VERSION 5.8 ;
BUSBITCHARS "[]" ;
DIVIDERCHAR "/" ;
UNITS
    DATABASE MICRONS 1000 ;
END UNITS

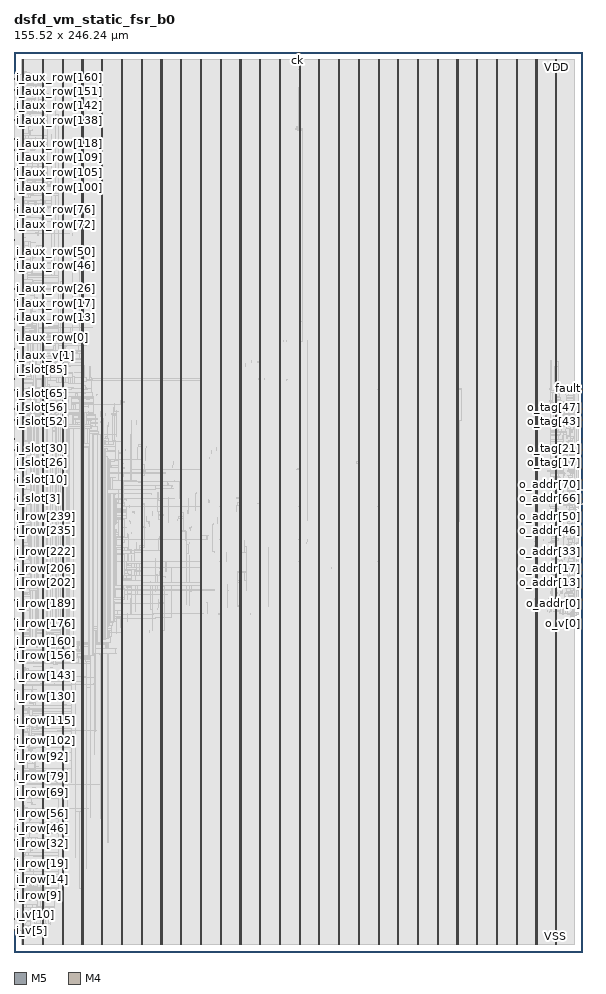
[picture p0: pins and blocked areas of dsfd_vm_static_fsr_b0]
MACRO dsfd_vm_static_fsr_b0
  FOREIGN dsfd_vm_static_fsr_b0 0 0 ;
  CLASS BLOCK ;
  SIZE 155.52 BY 246.24 ;
  PIN ck
    DIRECTION INPUT ;
    USE SIGNAL ;
    PORT
      LAYER M5 ;
        RECT  77.52 246.156 77.544 246.24 ;
    END
  END ck
  PIN fault
    DIRECTION OUTPUT ;
    USE SIGNAL ;
    PORT
      LAYER M4 ;
        RECT  155.436 154.176 155.52 154.2 ;
    END
  END fault
  PIN i_aux_row[0]
    DIRECTION INPUT ;
    USE SIGNAL ;
    PORT
      LAYER M4 ;
        RECT  0 168 0.084 168.024 ;
    END
  END i_aux_row[0]
  PIN i_aux_row[100]
    DIRECTION INPUT ;
    USE SIGNAL ;
    PORT
      LAYER M4 ;
        RECT  0 211.2 0.084 211.224 ;
    END
  END i_aux_row[100]
  PIN i_aux_row[101]
    DIRECTION INPUT ;
    USE SIGNAL ;
    PORT
      LAYER M4 ;
        RECT  0 211.632 0.084 211.656 ;
    END
  END i_aux_row[101]
  PIN i_aux_row[102]
    DIRECTION INPUT ;
    USE SIGNAL ;
    PORT
      LAYER M4 ;
        RECT  0 212.064 0.084 212.088 ;
    END
  END i_aux_row[102]
  PIN i_aux_row[103]
    DIRECTION INPUT ;
    USE SIGNAL ;
    PORT
      LAYER M4 ;
        RECT  0 212.496 0.084 212.52 ;
    END
  END i_aux_row[103]
  PIN i_aux_row[104]
    DIRECTION INPUT ;
    USE SIGNAL ;
    PORT
      LAYER M4 ;
        RECT  0 212.928 0.084 212.952 ;
    END
  END i_aux_row[104]
  PIN i_aux_row[105]
    DIRECTION INPUT ;
    USE SIGNAL ;
    PORT
      LAYER M4 ;
        RECT  0 213.36 0.084 213.384 ;
    END
  END i_aux_row[105]
  PIN i_aux_row[106]
    DIRECTION INPUT ;
    USE SIGNAL ;
    PORT
      LAYER M4 ;
        RECT  0 213.792 0.084 213.816 ;
    END
  END i_aux_row[106]
  PIN i_aux_row[107]
    DIRECTION INPUT ;
    USE SIGNAL ;
    PORT
      LAYER M4 ;
        RECT  0 214.224 0.084 214.248 ;
    END
  END i_aux_row[107]
  PIN i_aux_row[108]
    DIRECTION INPUT ;
    USE SIGNAL ;
    PORT
      LAYER M4 ;
        RECT  0 214.656 0.084 214.68 ;
    END
  END i_aux_row[108]
  PIN i_aux_row[109]
    DIRECTION INPUT ;
    USE SIGNAL ;
    PORT
      LAYER M4 ;
        RECT  0 215.088 0.084 215.112 ;
    END
  END i_aux_row[109]
  PIN i_aux_row[10]
    DIRECTION INPUT ;
    USE SIGNAL ;
    PORT
      LAYER M4 ;
        RECT  0 172.32 0.084 172.344 ;
    END
  END i_aux_row[10]
  PIN i_aux_row[110]
    DIRECTION INPUT ;
    USE SIGNAL ;
    PORT
      LAYER M4 ;
        RECT  0 215.52 0.084 215.544 ;
    END
  END i_aux_row[110]
  PIN i_aux_row[111]
    DIRECTION INPUT ;
    USE SIGNAL ;
    PORT
      LAYER M4 ;
        RECT  0 215.952 0.084 215.976 ;
    END
  END i_aux_row[111]
  PIN i_aux_row[112]
    DIRECTION INPUT ;
    USE SIGNAL ;
    PORT
      LAYER M4 ;
        RECT  0 216.384 0.084 216.408 ;
    END
  END i_aux_row[112]
  PIN i_aux_row[113]
    DIRECTION INPUT ;
    USE SIGNAL ;
    PORT
      LAYER M4 ;
        RECT  0 216.816 0.084 216.84 ;
    END
  END i_aux_row[113]
  PIN i_aux_row[114]
    DIRECTION INPUT ;
    USE SIGNAL ;
    PORT
      LAYER M4 ;
        RECT  0 217.248 0.084 217.272 ;
    END
  END i_aux_row[114]
  PIN i_aux_row[115]
    DIRECTION INPUT ;
    USE SIGNAL ;
    PORT
      LAYER M4 ;
        RECT  0 217.68 0.084 217.704 ;
    END
  END i_aux_row[115]
  PIN i_aux_row[116]
    DIRECTION INPUT ;
    USE SIGNAL ;
    PORT
      LAYER M4 ;
        RECT  0 218.112 0.084 218.136 ;
    END
  END i_aux_row[116]
  PIN i_aux_row[117]
    DIRECTION INPUT ;
    USE SIGNAL ;
    PORT
      LAYER M4 ;
        RECT  0 218.544 0.084 218.568 ;
    END
  END i_aux_row[117]
  PIN i_aux_row[118]
    DIRECTION INPUT ;
    USE SIGNAL ;
    PORT
      LAYER M4 ;
        RECT  0 218.976 0.084 219 ;
    END
  END i_aux_row[118]
  PIN i_aux_row[119]
    DIRECTION INPUT ;
    USE SIGNAL ;
    PORT
      LAYER M4 ;
        RECT  0 219.408 0.084 219.432 ;
    END
  END i_aux_row[119]
  PIN i_aux_row[11]
    DIRECTION INPUT ;
    USE SIGNAL ;
    PORT
      LAYER M4 ;
        RECT  0 172.752 0.084 172.776 ;
    END
  END i_aux_row[11]
  PIN i_aux_row[120]
    DIRECTION INPUT ;
    USE SIGNAL ;
    PORT
      LAYER M4 ;
        RECT  0 219.84 0.084 219.864 ;
    END
  END i_aux_row[120]
  PIN i_aux_row[121]
    DIRECTION INPUT ;
    USE SIGNAL ;
    PORT
      LAYER M4 ;
        RECT  0 220.272 0.084 220.296 ;
    END
  END i_aux_row[121]
  PIN i_aux_row[122]
    DIRECTION INPUT ;
    USE SIGNAL ;
    PORT
      LAYER M4 ;
        RECT  0 220.704 0.084 220.728 ;
    END
  END i_aux_row[122]
  PIN i_aux_row[123]
    DIRECTION INPUT ;
    USE SIGNAL ;
    PORT
      LAYER M4 ;
        RECT  0 221.136 0.084 221.16 ;
    END
  END i_aux_row[123]
  PIN i_aux_row[124]
    DIRECTION INPUT ;
    USE SIGNAL ;
    PORT
      LAYER M4 ;
        RECT  0 221.568 0.084 221.592 ;
    END
  END i_aux_row[124]
  PIN i_aux_row[125]
    DIRECTION INPUT ;
    USE SIGNAL ;
    PORT
      LAYER M4 ;
        RECT  0 222 0.084 222.024 ;
    END
  END i_aux_row[125]
  PIN i_aux_row[126]
    DIRECTION INPUT ;
    USE SIGNAL ;
    PORT
      LAYER M4 ;
        RECT  0 222.432 0.084 222.456 ;
    END
  END i_aux_row[126]
  PIN i_aux_row[127]
    DIRECTION INPUT ;
    USE SIGNAL ;
    PORT
      LAYER M4 ;
        RECT  0 222.864 0.084 222.888 ;
    END
  END i_aux_row[127]
  PIN i_aux_row[128]
    DIRECTION INPUT ;
    USE SIGNAL ;
    PORT
      LAYER M4 ;
        RECT  0 223.296 0.084 223.32 ;
    END
  END i_aux_row[128]
  PIN i_aux_row[129]
    DIRECTION INPUT ;
    USE SIGNAL ;
    PORT
      LAYER M4 ;
        RECT  0 223.728 0.084 223.752 ;
    END
  END i_aux_row[129]
  PIN i_aux_row[12]
    DIRECTION INPUT ;
    USE SIGNAL ;
    PORT
      LAYER M4 ;
        RECT  0 173.184 0.084 173.208 ;
    END
  END i_aux_row[12]
  PIN i_aux_row[130]
    DIRECTION INPUT ;
    USE SIGNAL ;
    PORT
      LAYER M4 ;
        RECT  0 224.16 0.084 224.184 ;
    END
  END i_aux_row[130]
  PIN i_aux_row[131]
    DIRECTION INPUT ;
    USE SIGNAL ;
    PORT
      LAYER M4 ;
        RECT  0 224.592 0.084 224.616 ;
    END
  END i_aux_row[131]
  PIN i_aux_row[132]
    DIRECTION INPUT ;
    USE SIGNAL ;
    PORT
      LAYER M4 ;
        RECT  0 225.024 0.084 225.048 ;
    END
  END i_aux_row[132]
  PIN i_aux_row[133]
    DIRECTION INPUT ;
    USE SIGNAL ;
    PORT
      LAYER M4 ;
        RECT  0 225.456 0.084 225.48 ;
    END
  END i_aux_row[133]
  PIN i_aux_row[134]
    DIRECTION INPUT ;
    USE SIGNAL ;
    PORT
      LAYER M4 ;
        RECT  0 225.888 0.084 225.912 ;
    END
  END i_aux_row[134]
  PIN i_aux_row[135]
    DIRECTION INPUT ;
    USE SIGNAL ;
    PORT
      LAYER M4 ;
        RECT  0 226.32 0.084 226.344 ;
    END
  END i_aux_row[135]
  PIN i_aux_row[136]
    DIRECTION INPUT ;
    USE SIGNAL ;
    PORT
      LAYER M4 ;
        RECT  0 226.752 0.084 226.776 ;
    END
  END i_aux_row[136]
  PIN i_aux_row[137]
    DIRECTION INPUT ;
    USE SIGNAL ;
    PORT
      LAYER M4 ;
        RECT  0 227.184 0.084 227.208 ;
    END
  END i_aux_row[137]
  PIN i_aux_row[138]
    DIRECTION INPUT ;
    USE SIGNAL ;
    PORT
      LAYER M4 ;
        RECT  0 227.616 0.084 227.64 ;
    END
  END i_aux_row[138]
  PIN i_aux_row[139]
    DIRECTION INPUT ;
    USE SIGNAL ;
    PORT
      LAYER M4 ;
        RECT  0 228.048 0.084 228.072 ;
    END
  END i_aux_row[139]
  PIN i_aux_row[13]
    DIRECTION INPUT ;
    USE SIGNAL ;
    PORT
      LAYER M4 ;
        RECT  0 173.616 0.084 173.64 ;
    END
  END i_aux_row[13]
  PIN i_aux_row[140]
    DIRECTION INPUT ;
    USE SIGNAL ;
    PORT
      LAYER M4 ;
        RECT  0 228.48 0.084 228.504 ;
    END
  END i_aux_row[140]
  PIN i_aux_row[141]
    DIRECTION INPUT ;
    USE SIGNAL ;
    PORT
      LAYER M4 ;
        RECT  0 228.912 0.084 228.936 ;
    END
  END i_aux_row[141]
  PIN i_aux_row[142]
    DIRECTION INPUT ;
    USE SIGNAL ;
    PORT
      LAYER M4 ;
        RECT  0 229.344 0.084 229.368 ;
    END
  END i_aux_row[142]
  PIN i_aux_row[143]
    DIRECTION INPUT ;
    USE SIGNAL ;
    PORT
      LAYER M4 ;
        RECT  0 229.776 0.084 229.8 ;
    END
  END i_aux_row[143]
  PIN i_aux_row[144]
    DIRECTION INPUT ;
    USE SIGNAL ;
    PORT
      LAYER M4 ;
        RECT  0 230.208 0.084 230.232 ;
    END
  END i_aux_row[144]
  PIN i_aux_row[145]
    DIRECTION INPUT ;
    USE SIGNAL ;
    PORT
      LAYER M4 ;
        RECT  0 230.64 0.084 230.664 ;
    END
  END i_aux_row[145]
  PIN i_aux_row[146]
    DIRECTION INPUT ;
    USE SIGNAL ;
    PORT
      LAYER M4 ;
        RECT  0 231.072 0.084 231.096 ;
    END
  END i_aux_row[146]
  PIN i_aux_row[147]
    DIRECTION INPUT ;
    USE SIGNAL ;
    PORT
      LAYER M4 ;
        RECT  0 231.504 0.084 231.528 ;
    END
  END i_aux_row[147]
  PIN i_aux_row[148]
    DIRECTION INPUT ;
    USE SIGNAL ;
    PORT
      LAYER M4 ;
        RECT  0 231.936 0.084 231.96 ;
    END
  END i_aux_row[148]
  PIN i_aux_row[149]
    DIRECTION INPUT ;
    USE SIGNAL ;
    PORT
      LAYER M4 ;
        RECT  0 232.368 0.084 232.392 ;
    END
  END i_aux_row[149]
  PIN i_aux_row[14]
    DIRECTION INPUT ;
    USE SIGNAL ;
    PORT
      LAYER M4 ;
        RECT  0 174.048 0.084 174.072 ;
    END
  END i_aux_row[14]
  PIN i_aux_row[150]
    DIRECTION INPUT ;
    USE SIGNAL ;
    PORT
      LAYER M4 ;
        RECT  0 232.8 0.084 232.824 ;
    END
  END i_aux_row[150]
  PIN i_aux_row[151]
    DIRECTION INPUT ;
    USE SIGNAL ;
    PORT
      LAYER M4 ;
        RECT  0 233.232 0.084 233.256 ;
    END
  END i_aux_row[151]
  PIN i_aux_row[152]
    DIRECTION INPUT ;
    USE SIGNAL ;
    PORT
      LAYER M4 ;
        RECT  0 233.664 0.084 233.688 ;
    END
  END i_aux_row[152]
  PIN i_aux_row[153]
    DIRECTION INPUT ;
    USE SIGNAL ;
    PORT
      LAYER M4 ;
        RECT  0 234.096 0.084 234.12 ;
    END
  END i_aux_row[153]
  PIN i_aux_row[154]
    DIRECTION INPUT ;
    USE SIGNAL ;
    PORT
      LAYER M4 ;
        RECT  0 234.528 0.084 234.552 ;
    END
  END i_aux_row[154]
  PIN i_aux_row[155]
    DIRECTION INPUT ;
    USE SIGNAL ;
    PORT
      LAYER M4 ;
        RECT  0 234.96 0.084 234.984 ;
    END
  END i_aux_row[155]
  PIN i_aux_row[156]
    DIRECTION INPUT ;
    USE SIGNAL ;
    PORT
      LAYER M4 ;
        RECT  0 235.392 0.084 235.416 ;
    END
  END i_aux_row[156]
  PIN i_aux_row[157]
    DIRECTION INPUT ;
    USE SIGNAL ;
    PORT
      LAYER M4 ;
        RECT  0 235.824 0.084 235.848 ;
    END
  END i_aux_row[157]
  PIN i_aux_row[158]
    DIRECTION INPUT ;
    USE SIGNAL ;
    PORT
      LAYER M4 ;
        RECT  0 236.256 0.084 236.28 ;
    END
  END i_aux_row[158]
  PIN i_aux_row[159]
    DIRECTION INPUT ;
    USE SIGNAL ;
    PORT
      LAYER M4 ;
        RECT  0 236.688 0.084 236.712 ;
    END
  END i_aux_row[159]
  PIN i_aux_row[15]
    DIRECTION INPUT ;
    USE SIGNAL ;
    PORT
      LAYER M4 ;
        RECT  0 174.48 0.084 174.504 ;
    END
  END i_aux_row[15]
  PIN i_aux_row[160]
    DIRECTION INPUT ;
    USE SIGNAL ;
    PORT
      LAYER M4 ;
        RECT  0 237.12 0.084 237.144 ;
    END
  END i_aux_row[160]
  PIN i_aux_row[161]
    DIRECTION INPUT ;
    USE SIGNAL ;
    PORT
      LAYER M4 ;
        RECT  0 237.552 0.084 237.576 ;
    END
  END i_aux_row[161]
  PIN i_aux_row[162]
    DIRECTION INPUT ;
    USE SIGNAL ;
    PORT
      LAYER M4 ;
        RECT  0 237.984 0.084 238.008 ;
    END
  END i_aux_row[162]
  PIN i_aux_row[163]
    DIRECTION INPUT ;
    USE SIGNAL ;
    PORT
      LAYER M4 ;
        RECT  0 238.416 0.084 238.44 ;
    END
  END i_aux_row[163]
  PIN i_aux_row[164]
    DIRECTION INPUT ;
    USE SIGNAL ;
    PORT
      LAYER M4 ;
        RECT  0 238.848 0.084 238.872 ;
    END
  END i_aux_row[164]
  PIN i_aux_row[165]
    DIRECTION INPUT ;
    USE SIGNAL ;
    PORT
      LAYER M4 ;
        RECT  0 239.28 0.084 239.304 ;
    END
  END i_aux_row[165]
  PIN i_aux_row[166]
    DIRECTION INPUT ;
    USE SIGNAL ;
    PORT
      LAYER M4 ;
        RECT  0 239.712 0.084 239.736 ;
    END
  END i_aux_row[166]
  PIN i_aux_row[167]
    DIRECTION INPUT ;
    USE SIGNAL ;
    PORT
      LAYER M4 ;
        RECT  0 240.144 0.084 240.168 ;
    END
  END i_aux_row[167]
  PIN i_aux_row[16]
    DIRECTION INPUT ;
    USE SIGNAL ;
    PORT
      LAYER M4 ;
        RECT  0 174.912 0.084 174.936 ;
    END
  END i_aux_row[16]
  PIN i_aux_row[17]
    DIRECTION INPUT ;
    USE SIGNAL ;
    PORT
      LAYER M4 ;
        RECT  0 175.344 0.084 175.368 ;
    END
  END i_aux_row[17]
  PIN i_aux_row[18]
    DIRECTION INPUT ;
    USE SIGNAL ;
    PORT
      LAYER M4 ;
        RECT  0 175.776 0.084 175.8 ;
    END
  END i_aux_row[18]
  PIN i_aux_row[19]
    DIRECTION INPUT ;
    USE SIGNAL ;
    PORT
      LAYER M4 ;
        RECT  0 176.208 0.084 176.232 ;
    END
  END i_aux_row[19]
  PIN i_aux_row[1]
    DIRECTION INPUT ;
    USE SIGNAL ;
    PORT
      LAYER M4 ;
        RECT  0 168.432 0.084 168.456 ;
    END
  END i_aux_row[1]
  PIN i_aux_row[20]
    DIRECTION INPUT ;
    USE SIGNAL ;
    PORT
      LAYER M4 ;
        RECT  0 176.64 0.084 176.664 ;
    END
  END i_aux_row[20]
  PIN i_aux_row[21]
    DIRECTION INPUT ;
    USE SIGNAL ;
    PORT
      LAYER M4 ;
        RECT  0 177.072 0.084 177.096 ;
    END
  END i_aux_row[21]
  PIN i_aux_row[22]
    DIRECTION INPUT ;
    USE SIGNAL ;
    PORT
      LAYER M4 ;
        RECT  0 177.504 0.084 177.528 ;
    END
  END i_aux_row[22]
  PIN i_aux_row[23]
    DIRECTION INPUT ;
    USE SIGNAL ;
    PORT
      LAYER M4 ;
        RECT  0 177.936 0.084 177.96 ;
    END
  END i_aux_row[23]
  PIN i_aux_row[24]
    DIRECTION INPUT ;
    USE SIGNAL ;
    PORT
      LAYER M4 ;
        RECT  0 178.368 0.084 178.392 ;
    END
  END i_aux_row[24]
  PIN i_aux_row[25]
    DIRECTION INPUT ;
    USE SIGNAL ;
    PORT
      LAYER M4 ;
        RECT  0 178.8 0.084 178.824 ;
    END
  END i_aux_row[25]
  PIN i_aux_row[26]
    DIRECTION INPUT ;
    USE SIGNAL ;
    PORT
      LAYER M4 ;
        RECT  0 179.232 0.084 179.256 ;
    END
  END i_aux_row[26]
  PIN i_aux_row[27]
    DIRECTION INPUT ;
    USE SIGNAL ;
    PORT
      LAYER M4 ;
        RECT  0 179.664 0.084 179.688 ;
    END
  END i_aux_row[27]
  PIN i_aux_row[28]
    DIRECTION INPUT ;
    USE SIGNAL ;
    PORT
      LAYER M4 ;
        RECT  0 180.096 0.084 180.12 ;
    END
  END i_aux_row[28]
  PIN i_aux_row[29]
    DIRECTION INPUT ;
    USE SIGNAL ;
    PORT
      LAYER M4 ;
        RECT  0 180.528 0.084 180.552 ;
    END
  END i_aux_row[29]
  PIN i_aux_row[2]
    DIRECTION INPUT ;
    USE SIGNAL ;
    PORT
      LAYER M4 ;
        RECT  0 168.864 0.084 168.888 ;
    END
  END i_aux_row[2]
  PIN i_aux_row[30]
    DIRECTION INPUT ;
    USE SIGNAL ;
    PORT
      LAYER M4 ;
        RECT  0 180.96 0.084 180.984 ;
    END
  END i_aux_row[30]
  PIN i_aux_row[31]
    DIRECTION INPUT ;
    USE SIGNAL ;
    PORT
      LAYER M4 ;
        RECT  0 181.392 0.084 181.416 ;
    END
  END i_aux_row[31]
  PIN i_aux_row[32]
    DIRECTION INPUT ;
    USE SIGNAL ;
    PORT
      LAYER M4 ;
        RECT  0 181.824 0.084 181.848 ;
    END
  END i_aux_row[32]
  PIN i_aux_row[33]
    DIRECTION INPUT ;
    USE SIGNAL ;
    PORT
      LAYER M4 ;
        RECT  0 182.256 0.084 182.28 ;
    END
  END i_aux_row[33]
  PIN i_aux_row[34]
    DIRECTION INPUT ;
    USE SIGNAL ;
    PORT
      LAYER M4 ;
        RECT  0 182.688 0.084 182.712 ;
    END
  END i_aux_row[34]
  PIN i_aux_row[35]
    DIRECTION INPUT ;
    USE SIGNAL ;
    PORT
      LAYER M4 ;
        RECT  0 183.12 0.084 183.144 ;
    END
  END i_aux_row[35]
  PIN i_aux_row[36]
    DIRECTION INPUT ;
    USE SIGNAL ;
    PORT
      LAYER M4 ;
        RECT  0 183.552 0.084 183.576 ;
    END
  END i_aux_row[36]
  PIN i_aux_row[37]
    DIRECTION INPUT ;
    USE SIGNAL ;
    PORT
      LAYER M4 ;
        RECT  0 183.984 0.084 184.008 ;
    END
  END i_aux_row[37]
  PIN i_aux_row[38]
    DIRECTION INPUT ;
    USE SIGNAL ;
    PORT
      LAYER M4 ;
        RECT  0 184.416 0.084 184.44 ;
    END
  END i_aux_row[38]
  PIN i_aux_row[39]
    DIRECTION INPUT ;
    USE SIGNAL ;
    PORT
      LAYER M4 ;
        RECT  0 184.848 0.084 184.872 ;
    END
  END i_aux_row[39]
  PIN i_aux_row[3]
    DIRECTION INPUT ;
    USE SIGNAL ;
    PORT
      LAYER M4 ;
        RECT  0 169.296 0.084 169.32 ;
    END
  END i_aux_row[3]
  PIN i_aux_row[40]
    DIRECTION INPUT ;
    USE SIGNAL ;
    PORT
      LAYER M4 ;
        RECT  0 185.28 0.084 185.304 ;
    END
  END i_aux_row[40]
  PIN i_aux_row[41]
    DIRECTION INPUT ;
    USE SIGNAL ;
    PORT
      LAYER M4 ;
        RECT  0 185.712 0.084 185.736 ;
    END
  END i_aux_row[41]
  PIN i_aux_row[42]
    DIRECTION INPUT ;
    USE SIGNAL ;
    PORT
      LAYER M4 ;
        RECT  0 186.144 0.084 186.168 ;
    END
  END i_aux_row[42]
  PIN i_aux_row[43]
    DIRECTION INPUT ;
    USE SIGNAL ;
    PORT
      LAYER M4 ;
        RECT  0 186.576 0.084 186.6 ;
    END
  END i_aux_row[43]
  PIN i_aux_row[44]
    DIRECTION INPUT ;
    USE SIGNAL ;
    PORT
      LAYER M4 ;
        RECT  0 187.008 0.084 187.032 ;
    END
  END i_aux_row[44]
  PIN i_aux_row[45]
    DIRECTION INPUT ;
    USE SIGNAL ;
    PORT
      LAYER M4 ;
        RECT  0 187.44 0.084 187.464 ;
    END
  END i_aux_row[45]
  PIN i_aux_row[46]
    DIRECTION INPUT ;
    USE SIGNAL ;
    PORT
      LAYER M4 ;
        RECT  0 187.872 0.084 187.896 ;
    END
  END i_aux_row[46]
  PIN i_aux_row[47]
    DIRECTION INPUT ;
    USE SIGNAL ;
    PORT
      LAYER M4 ;
        RECT  0 188.304 0.084 188.328 ;
    END
  END i_aux_row[47]
  PIN i_aux_row[48]
    DIRECTION INPUT ;
    USE SIGNAL ;
    PORT
      LAYER M4 ;
        RECT  0 188.736 0.084 188.76 ;
    END
  END i_aux_row[48]
  PIN i_aux_row[49]
    DIRECTION INPUT ;
    USE SIGNAL ;
    PORT
      LAYER M4 ;
        RECT  0 189.168 0.084 189.192 ;
    END
  END i_aux_row[49]
  PIN i_aux_row[4]
    DIRECTION INPUT ;
    USE SIGNAL ;
    PORT
      LAYER M4 ;
        RECT  0 169.728 0.084 169.752 ;
    END
  END i_aux_row[4]
  PIN i_aux_row[50]
    DIRECTION INPUT ;
    USE SIGNAL ;
    PORT
      LAYER M4 ;
        RECT  0 189.6 0.084 189.624 ;
    END
  END i_aux_row[50]
  PIN i_aux_row[51]
    DIRECTION INPUT ;
    USE SIGNAL ;
    PORT
      LAYER M4 ;
        RECT  0 190.032 0.084 190.056 ;
    END
  END i_aux_row[51]
  PIN i_aux_row[52]
    DIRECTION INPUT ;
    USE SIGNAL ;
    PORT
      LAYER M4 ;
        RECT  0 190.464 0.084 190.488 ;
    END
  END i_aux_row[52]
  PIN i_aux_row[53]
    DIRECTION INPUT ;
    USE SIGNAL ;
    PORT
      LAYER M4 ;
        RECT  0 190.896 0.084 190.92 ;
    END
  END i_aux_row[53]
  PIN i_aux_row[54]
    DIRECTION INPUT ;
    USE SIGNAL ;
    PORT
      LAYER M4 ;
        RECT  0 191.328 0.084 191.352 ;
    END
  END i_aux_row[54]
  PIN i_aux_row[55]
    DIRECTION INPUT ;
    USE SIGNAL ;
    PORT
      LAYER M4 ;
        RECT  0 191.76 0.084 191.784 ;
    END
  END i_aux_row[55]
  PIN i_aux_row[56]
    DIRECTION INPUT ;
    USE SIGNAL ;
    PORT
      LAYER M4 ;
        RECT  0 192.192 0.084 192.216 ;
    END
  END i_aux_row[56]
  PIN i_aux_row[57]
    DIRECTION INPUT ;
    USE SIGNAL ;
    PORT
      LAYER M4 ;
        RECT  0 192.624 0.084 192.648 ;
    END
  END i_aux_row[57]
  PIN i_aux_row[58]
    DIRECTION INPUT ;
    USE SIGNAL ;
    PORT
      LAYER M4 ;
        RECT  0 193.056 0.084 193.08 ;
    END
  END i_aux_row[58]
  PIN i_aux_row[59]
    DIRECTION INPUT ;
    USE SIGNAL ;
    PORT
      LAYER M4 ;
        RECT  0 193.488 0.084 193.512 ;
    END
  END i_aux_row[59]
  PIN i_aux_row[5]
    DIRECTION INPUT ;
    USE SIGNAL ;
    PORT
      LAYER M4 ;
        RECT  0 170.16 0.084 170.184 ;
    END
  END i_aux_row[5]
  PIN i_aux_row[60]
    DIRECTION INPUT ;
    USE SIGNAL ;
    PORT
      LAYER M4 ;
        RECT  0 193.92 0.084 193.944 ;
    END
  END i_aux_row[60]
  PIN i_aux_row[61]
    DIRECTION INPUT ;
    USE SIGNAL ;
    PORT
      LAYER M4 ;
        RECT  0 194.352 0.084 194.376 ;
    END
  END i_aux_row[61]
  PIN i_aux_row[62]
    DIRECTION INPUT ;
    USE SIGNAL ;
    PORT
      LAYER M4 ;
        RECT  0 194.784 0.084 194.808 ;
    END
  END i_aux_row[62]
  PIN i_aux_row[63]
    DIRECTION INPUT ;
    USE SIGNAL ;
    PORT
      LAYER M4 ;
        RECT  0 195.216 0.084 195.24 ;
    END
  END i_aux_row[63]
  PIN i_aux_row[64]
    DIRECTION INPUT ;
    USE SIGNAL ;
    PORT
      LAYER M4 ;
        RECT  0 195.648 0.084 195.672 ;
    END
  END i_aux_row[64]
  PIN i_aux_row[65]
    DIRECTION INPUT ;
    USE SIGNAL ;
    PORT
      LAYER M4 ;
        RECT  0 196.08 0.084 196.104 ;
    END
  END i_aux_row[65]
  PIN i_aux_row[66]
    DIRECTION INPUT ;
    USE SIGNAL ;
    PORT
      LAYER M4 ;
        RECT  0 196.512 0.084 196.536 ;
    END
  END i_aux_row[66]
  PIN i_aux_row[67]
    DIRECTION INPUT ;
    USE SIGNAL ;
    PORT
      LAYER M4 ;
        RECT  0 196.944 0.084 196.968 ;
    END
  END i_aux_row[67]
  PIN i_aux_row[68]
    DIRECTION INPUT ;
    USE SIGNAL ;
    PORT
      LAYER M4 ;
        RECT  0 197.376 0.084 197.4 ;
    END
  END i_aux_row[68]
  PIN i_aux_row[69]
    DIRECTION INPUT ;
    USE SIGNAL ;
    PORT
      LAYER M4 ;
        RECT  0 197.808 0.084 197.832 ;
    END
  END i_aux_row[69]
  PIN i_aux_row[6]
    DIRECTION INPUT ;
    USE SIGNAL ;
    PORT
      LAYER M4 ;
        RECT  0 170.592 0.084 170.616 ;
    END
  END i_aux_row[6]
  PIN i_aux_row[70]
    DIRECTION INPUT ;
    USE SIGNAL ;
    PORT
      LAYER M4 ;
        RECT  0 198.24 0.084 198.264 ;
    END
  END i_aux_row[70]
  PIN i_aux_row[71]
    DIRECTION INPUT ;
    USE SIGNAL ;
    PORT
      LAYER M4 ;
        RECT  0 198.672 0.084 198.696 ;
    END
  END i_aux_row[71]
  PIN i_aux_row[72]
    DIRECTION INPUT ;
    USE SIGNAL ;
    PORT
      LAYER M4 ;
        RECT  0 199.104 0.084 199.128 ;
    END
  END i_aux_row[72]
  PIN i_aux_row[73]
    DIRECTION INPUT ;
    USE SIGNAL ;
    PORT
      LAYER M4 ;
        RECT  0 199.536 0.084 199.56 ;
    END
  END i_aux_row[73]
  PIN i_aux_row[74]
    DIRECTION INPUT ;
    USE SIGNAL ;
    PORT
      LAYER M4 ;
        RECT  0 199.968 0.084 199.992 ;
    END
  END i_aux_row[74]
  PIN i_aux_row[75]
    DIRECTION INPUT ;
    USE SIGNAL ;
    PORT
      LAYER M4 ;
        RECT  0 200.4 0.084 200.424 ;
    END
  END i_aux_row[75]
  PIN i_aux_row[76]
    DIRECTION INPUT ;
    USE SIGNAL ;
    PORT
      LAYER M4 ;
        RECT  0 200.832 0.084 200.856 ;
    END
  END i_aux_row[76]
  PIN i_aux_row[77]
    DIRECTION INPUT ;
    USE SIGNAL ;
    PORT
      LAYER M4 ;
        RECT  0 201.264 0.084 201.288 ;
    END
  END i_aux_row[77]
  PIN i_aux_row[78]
    DIRECTION INPUT ;
    USE SIGNAL ;
    PORT
      LAYER M4 ;
        RECT  0 201.696 0.084 201.72 ;
    END
  END i_aux_row[78]
  PIN i_aux_row[79]
    DIRECTION INPUT ;
    USE SIGNAL ;
    PORT
      LAYER M4 ;
        RECT  0 202.128 0.084 202.152 ;
    END
  END i_aux_row[79]
  PIN i_aux_row[7]
    DIRECTION INPUT ;
    USE SIGNAL ;
    PORT
      LAYER M4 ;
        RECT  0 171.024 0.084 171.048 ;
    END
  END i_aux_row[7]
  PIN i_aux_row[80]
    DIRECTION INPUT ;
    USE SIGNAL ;
    PORT
      LAYER M4 ;
        RECT  0 202.56 0.084 202.584 ;
    END
  END i_aux_row[80]
  PIN i_aux_row[81]
    DIRECTION INPUT ;
    USE SIGNAL ;
    PORT
      LAYER M4 ;
        RECT  0 202.992 0.084 203.016 ;
    END
  END i_aux_row[81]
  PIN i_aux_row[82]
    DIRECTION INPUT ;
    USE SIGNAL ;
    PORT
      LAYER M4 ;
        RECT  0 203.424 0.084 203.448 ;
    END
  END i_aux_row[82]
  PIN i_aux_row[83]
    DIRECTION INPUT ;
    USE SIGNAL ;
    PORT
      LAYER M4 ;
        RECT  0 203.856 0.084 203.88 ;
    END
  END i_aux_row[83]
  PIN i_aux_row[84]
    DIRECTION INPUT ;
    USE SIGNAL ;
    PORT
      LAYER M4 ;
        RECT  0 204.288 0.084 204.312 ;
    END
  END i_aux_row[84]
  PIN i_aux_row[85]
    DIRECTION INPUT ;
    USE SIGNAL ;
    PORT
      LAYER M4 ;
        RECT  0 204.72 0.084 204.744 ;
    END
  END i_aux_row[85]
  PIN i_aux_row[86]
    DIRECTION INPUT ;
    USE SIGNAL ;
    PORT
      LAYER M4 ;
        RECT  0 205.152 0.084 205.176 ;
    END
  END i_aux_row[86]
  PIN i_aux_row[87]
    DIRECTION INPUT ;
    USE SIGNAL ;
    PORT
      LAYER M4 ;
        RECT  0 205.584 0.084 205.608 ;
    END
  END i_aux_row[87]
  PIN i_aux_row[88]
    DIRECTION INPUT ;
    USE SIGNAL ;
    PORT
      LAYER M4 ;
        RECT  0 206.016 0.084 206.04 ;
    END
  END i_aux_row[88]
  PIN i_aux_row[89]
    DIRECTION INPUT ;
    USE SIGNAL ;
    PORT
      LAYER M4 ;
        RECT  0 206.448 0.084 206.472 ;
    END
  END i_aux_row[89]
  PIN i_aux_row[8]
    DIRECTION INPUT ;
    USE SIGNAL ;
    PORT
      LAYER M4 ;
        RECT  0 171.456 0.084 171.48 ;
    END
  END i_aux_row[8]
  PIN i_aux_row[90]
    DIRECTION INPUT ;
    USE SIGNAL ;
    PORT
      LAYER M4 ;
        RECT  0 206.88 0.084 206.904 ;
    END
  END i_aux_row[90]
  PIN i_aux_row[91]
    DIRECTION INPUT ;
    USE SIGNAL ;
    PORT
      LAYER M4 ;
        RECT  0 207.312 0.084 207.336 ;
    END
  END i_aux_row[91]
  PIN i_aux_row[92]
    DIRECTION INPUT ;
    USE SIGNAL ;
    PORT
      LAYER M4 ;
        RECT  0 207.744 0.084 207.768 ;
    END
  END i_aux_row[92]
  PIN i_aux_row[93]
    DIRECTION INPUT ;
    USE SIGNAL ;
    PORT
      LAYER M4 ;
        RECT  0 208.176 0.084 208.2 ;
    END
  END i_aux_row[93]
  PIN i_aux_row[94]
    DIRECTION INPUT ;
    USE SIGNAL ;
    PORT
      LAYER M4 ;
        RECT  0 208.608 0.084 208.632 ;
    END
  END i_aux_row[94]
  PIN i_aux_row[95]
    DIRECTION INPUT ;
    USE SIGNAL ;
    PORT
      LAYER M4 ;
        RECT  0 209.04 0.084 209.064 ;
    END
  END i_aux_row[95]
  PIN i_aux_row[96]
    DIRECTION INPUT ;
    USE SIGNAL ;
    PORT
      LAYER M4 ;
        RECT  0 209.472 0.084 209.496 ;
    END
  END i_aux_row[96]
  PIN i_aux_row[97]
    DIRECTION INPUT ;
    USE SIGNAL ;
    PORT
      LAYER M4 ;
        RECT  0 209.904 0.084 209.928 ;
    END
  END i_aux_row[97]
  PIN i_aux_row[98]
    DIRECTION INPUT ;
    USE SIGNAL ;
    PORT
      LAYER M4 ;
        RECT  0 210.336 0.084 210.36 ;
    END
  END i_aux_row[98]
  PIN i_aux_row[99]
    DIRECTION INPUT ;
    USE SIGNAL ;
    PORT
      LAYER M4 ;
        RECT  0 210.768 0.084 210.792 ;
    END
  END i_aux_row[99]
  PIN i_aux_row[9]
    DIRECTION INPUT ;
    USE SIGNAL ;
    PORT
      LAYER M4 ;
        RECT  0 171.888 0.084 171.912 ;
    END
  END i_aux_row[9]
  PIN i_aux_v[0]
    DIRECTION INPUT ;
    USE SIGNAL ;
    PORT
      LAYER M4 ;
        RECT  0 162.816 0.084 162.84 ;
    END
  END i_aux_v[0]
  PIN i_aux_v[10]
    DIRECTION INPUT ;
    USE SIGNAL ;
    PORT
      LAYER M4 ;
        RECT  0 167.136 0.084 167.16 ;
    END
  END i_aux_v[10]
  PIN i_aux_v[11]
    DIRECTION INPUT ;
    USE SIGNAL ;
    PORT
      LAYER M4 ;
        RECT  0 167.568 0.084 167.592 ;
    END
  END i_aux_v[11]
  PIN i_aux_v[1]
    DIRECTION INPUT ;
    USE SIGNAL ;
    PORT
      LAYER M4 ;
        RECT  0 163.248 0.084 163.272 ;
    END
  END i_aux_v[1]
  PIN i_aux_v[2]
    DIRECTION INPUT ;
    USE SIGNAL ;
    PORT
      LAYER M4 ;
        RECT  0 163.68 0.084 163.704 ;
    END
  END i_aux_v[2]
  PIN i_aux_v[3]
    DIRECTION INPUT ;
    USE SIGNAL ;
    PORT
      LAYER M4 ;
        RECT  0 164.112 0.084 164.136 ;
    END
  END i_aux_v[3]
  PIN i_aux_v[4]
    DIRECTION INPUT ;
    USE SIGNAL ;
    PORT
      LAYER M4 ;
        RECT  0 164.544 0.084 164.568 ;
    END
  END i_aux_v[4]
  PIN i_aux_v[5]
    DIRECTION INPUT ;
    USE SIGNAL ;
    PORT
      LAYER M4 ;
        RECT  0 164.976 0.084 165 ;
    END
  END i_aux_v[5]
  PIN i_aux_v[6]
    DIRECTION INPUT ;
    USE SIGNAL ;
    PORT
      LAYER M4 ;
        RECT  0 165.408 0.084 165.432 ;
    END
  END i_aux_v[6]
  PIN i_aux_v[7]
    DIRECTION INPUT ;
    USE SIGNAL ;
    PORT
      LAYER M4 ;
        RECT  0 165.84 0.084 165.864 ;
    END
  END i_aux_v[7]
  PIN i_aux_v[8]
    DIRECTION INPUT ;
    USE SIGNAL ;
    PORT
      LAYER M4 ;
        RECT  0 166.272 0.084 166.296 ;
    END
  END i_aux_v[8]
  PIN i_aux_v[9]
    DIRECTION INPUT ;
    USE SIGNAL ;
    PORT
      LAYER M4 ;
        RECT  0 166.704 0.084 166.728 ;
    END
  END i_aux_v[9]
  PIN i_group[0]
    DIRECTION INPUT ;
    USE SIGNAL ;
    PORT
      LAYER M4 ;
        RECT  0 161.52 0.084 161.544 ;
    END
  END i_group[0]
  PIN i_group[1]
    DIRECTION INPUT ;
    USE SIGNAL ;
    PORT
      LAYER M4 ;
        RECT  0 161.952 0.084 161.976 ;
    END
  END i_group[1]
  PIN i_group[2]
    DIRECTION INPUT ;
    USE SIGNAL ;
    PORT
      LAYER M4 ;
        RECT  0 162.384 0.084 162.408 ;
    END
  END i_group[2]
  PIN i_row[0]
    DIRECTION INPUT ;
    USE SIGNAL ;
    PORT
      LAYER M4 ;
        RECT  0 13.776 0.084 13.8 ;
    END
  END i_row[0]
  PIN i_row[100]
    DIRECTION INPUT ;
    USE SIGNAL ;
    PORT
      LAYER M4 ;
        RECT  0 56.976 0.084 57 ;
    END
  END i_row[100]
  PIN i_row[101]
    DIRECTION INPUT ;
    USE SIGNAL ;
    PORT
      LAYER M4 ;
        RECT  0 57.408 0.084 57.432 ;
    END
  END i_row[101]
  PIN i_row[102]
    DIRECTION INPUT ;
    USE SIGNAL ;
    PORT
      LAYER M4 ;
        RECT  0 57.84 0.084 57.864 ;
    END
  END i_row[102]
  PIN i_row[103]
    DIRECTION INPUT ;
    USE SIGNAL ;
    PORT
      LAYER M4 ;
        RECT  0 58.272 0.084 58.296 ;
    END
  END i_row[103]
  PIN i_row[104]
    DIRECTION INPUT ;
    USE SIGNAL ;
    PORT
      LAYER M4 ;
        RECT  0 58.704 0.084 58.728 ;
    END
  END i_row[104]
  PIN i_row[105]
    DIRECTION INPUT ;
    USE SIGNAL ;
    PORT
      LAYER M4 ;
        RECT  0 59.136 0.084 59.16 ;
    END
  END i_row[105]
  PIN i_row[106]
    DIRECTION INPUT ;
    USE SIGNAL ;
    PORT
      LAYER M4 ;
        RECT  0 59.568 0.084 59.592 ;
    END
  END i_row[106]
  PIN i_row[107]
    DIRECTION INPUT ;
    USE SIGNAL ;
    PORT
      LAYER M4 ;
        RECT  0 60 0.084 60.024 ;
    END
  END i_row[107]
  PIN i_row[108]
    DIRECTION INPUT ;
    USE SIGNAL ;
    PORT
      LAYER M4 ;
        RECT  0 60.432 0.084 60.456 ;
    END
  END i_row[108]
  PIN i_row[109]
    DIRECTION INPUT ;
    USE SIGNAL ;
    PORT
      LAYER M4 ;
        RECT  0 60.864 0.084 60.888 ;
    END
  END i_row[109]
  PIN i_row[10]
    DIRECTION INPUT ;
    USE SIGNAL ;
    PORT
      LAYER M4 ;
        RECT  0 18.096 0.084 18.12 ;
    END
  END i_row[10]
  PIN i_row[110]
    DIRECTION INPUT ;
    USE SIGNAL ;
    PORT
      LAYER M4 ;
        RECT  0 61.296 0.084 61.32 ;
    END
  END i_row[110]
  PIN i_row[111]
    DIRECTION INPUT ;
    USE SIGNAL ;
    PORT
      LAYER M4 ;
        RECT  0 61.728 0.084 61.752 ;
    END
  END i_row[111]
  PIN i_row[112]
    DIRECTION INPUT ;
    USE SIGNAL ;
    PORT
      LAYER M4 ;
        RECT  0 62.16 0.084 62.184 ;
    END
  END i_row[112]
  PIN i_row[113]
    DIRECTION INPUT ;
    USE SIGNAL ;
    PORT
      LAYER M4 ;
        RECT  0 62.592 0.084 62.616 ;
    END
  END i_row[113]
  PIN i_row[114]
    DIRECTION INPUT ;
    USE SIGNAL ;
    PORT
      LAYER M4 ;
        RECT  0 63.024 0.084 63.048 ;
    END
  END i_row[114]
  PIN i_row[115]
    DIRECTION INPUT ;
    USE SIGNAL ;
    PORT
      LAYER M4 ;
        RECT  0 63.456 0.084 63.48 ;
    END
  END i_row[115]
  PIN i_row[116]
    DIRECTION INPUT ;
    USE SIGNAL ;
    PORT
      LAYER M4 ;
        RECT  0 63.888 0.084 63.912 ;
    END
  END i_row[116]
  PIN i_row[117]
    DIRECTION INPUT ;
    USE SIGNAL ;
    PORT
      LAYER M4 ;
        RECT  0 64.32 0.084 64.344 ;
    END
  END i_row[117]
  PIN i_row[118]
    DIRECTION INPUT ;
    USE SIGNAL ;
    PORT
      LAYER M4 ;
        RECT  0 64.752 0.084 64.776 ;
    END
  END i_row[118]
  PIN i_row[119]
    DIRECTION INPUT ;
    USE SIGNAL ;
    PORT
      LAYER M4 ;
        RECT  0 65.184 0.084 65.208 ;
    END
  END i_row[119]
  PIN i_row[11]
    DIRECTION INPUT ;
    USE SIGNAL ;
    PORT
      LAYER M4 ;
        RECT  0 18.528 0.084 18.552 ;
    END
  END i_row[11]
  PIN i_row[120]
    DIRECTION INPUT ;
    USE SIGNAL ;
    PORT
      LAYER M4 ;
        RECT  0 65.616 0.084 65.64 ;
    END
  END i_row[120]
  PIN i_row[121]
    DIRECTION INPUT ;
    USE SIGNAL ;
    PORT
      LAYER M4 ;
        RECT  0 66.048 0.084 66.072 ;
    END
  END i_row[121]
  PIN i_row[122]
    DIRECTION INPUT ;
    USE SIGNAL ;
    PORT
      LAYER M4 ;
        RECT  0 66.48 0.084 66.504 ;
    END
  END i_row[122]
  PIN i_row[123]
    DIRECTION INPUT ;
    USE SIGNAL ;
    PORT
      LAYER M4 ;
        RECT  0 66.912 0.084 66.936 ;
    END
  END i_row[123]
  PIN i_row[124]
    DIRECTION INPUT ;
    USE SIGNAL ;
    PORT
      LAYER M4 ;
        RECT  0 67.344 0.084 67.368 ;
    END
  END i_row[124]
  PIN i_row[125]
    DIRECTION INPUT ;
    USE SIGNAL ;
    PORT
      LAYER M4 ;
        RECT  0 67.776 0.084 67.8 ;
    END
  END i_row[125]
  PIN i_row[126]
    DIRECTION INPUT ;
    USE SIGNAL ;
    PORT
      LAYER M4 ;
        RECT  0 68.208 0.084 68.232 ;
    END
  END i_row[126]
  PIN i_row[127]
    DIRECTION INPUT ;
    USE SIGNAL ;
    PORT
      LAYER M4 ;
        RECT  0 68.64 0.084 68.664 ;
    END
  END i_row[127]
  PIN i_row[128]
    DIRECTION INPUT ;
    USE SIGNAL ;
    PORT
      LAYER M4 ;
        RECT  0 69.072 0.084 69.096 ;
    END
  END i_row[128]
  PIN i_row[129]
    DIRECTION INPUT ;
    USE SIGNAL ;
    PORT
      LAYER M4 ;
        RECT  0 69.504 0.084 69.528 ;
    END
  END i_row[129]
  PIN i_row[12]
    DIRECTION INPUT ;
    USE SIGNAL ;
    PORT
      LAYER M4 ;
        RECT  0 18.96 0.084 18.984 ;
    END
  END i_row[12]
  PIN i_row[130]
    DIRECTION INPUT ;
    USE SIGNAL ;
    PORT
      LAYER M4 ;
        RECT  0 69.936 0.084 69.96 ;
    END
  END i_row[130]
  PIN i_row[131]
    DIRECTION INPUT ;
    USE SIGNAL ;
    PORT
      LAYER M4 ;
        RECT  0 70.368 0.084 70.392 ;
    END
  END i_row[131]
  PIN i_row[132]
    DIRECTION INPUT ;
    USE SIGNAL ;
    PORT
      LAYER M4 ;
        RECT  0 70.8 0.084 70.824 ;
    END
  END i_row[132]
  PIN i_row[133]
    DIRECTION INPUT ;
    USE SIGNAL ;
    PORT
      LAYER M4 ;
        RECT  0 71.232 0.084 71.256 ;
    END
  END i_row[133]
  PIN i_row[134]
    DIRECTION INPUT ;
    USE SIGNAL ;
    PORT
      LAYER M4 ;
        RECT  0 71.664 0.084 71.688 ;
    END
  END i_row[134]
  PIN i_row[135]
    DIRECTION INPUT ;
    USE SIGNAL ;
    PORT
      LAYER M4 ;
        RECT  0 72.096 0.084 72.12 ;
    END
  END i_row[135]
  PIN i_row[136]
    DIRECTION INPUT ;
    USE SIGNAL ;
    PORT
      LAYER M4 ;
        RECT  0 72.528 0.084 72.552 ;
    END
  END i_row[136]
  PIN i_row[137]
    DIRECTION INPUT ;
    USE SIGNAL ;
    PORT
      LAYER M4 ;
        RECT  0 72.96 0.084 72.984 ;
    END
  END i_row[137]
  PIN i_row[138]
    DIRECTION INPUT ;
    USE SIGNAL ;
    PORT
      LAYER M4 ;
        RECT  0 73.392 0.084 73.416 ;
    END
  END i_row[138]
  PIN i_row[139]
    DIRECTION INPUT ;
    USE SIGNAL ;
    PORT
      LAYER M4 ;
        RECT  0 73.824 0.084 73.848 ;
    END
  END i_row[139]
  PIN i_row[13]
    DIRECTION INPUT ;
    USE SIGNAL ;
    PORT
      LAYER M4 ;
        RECT  0 19.392 0.084 19.416 ;
    END
  END i_row[13]
  PIN i_row[140]
    DIRECTION INPUT ;
    USE SIGNAL ;
    PORT
      LAYER M4 ;
        RECT  0 74.256 0.084 74.28 ;
    END
  END i_row[140]
  PIN i_row[141]
    DIRECTION INPUT ;
    USE SIGNAL ;
    PORT
      LAYER M4 ;
        RECT  0 74.688 0.084 74.712 ;
    END
  END i_row[141]
  PIN i_row[142]
    DIRECTION INPUT ;
    USE SIGNAL ;
    PORT
      LAYER M4 ;
        RECT  0 75.12 0.084 75.144 ;
    END
  END i_row[142]
  PIN i_row[143]
    DIRECTION INPUT ;
    USE SIGNAL ;
    PORT
      LAYER M4 ;
        RECT  0 75.552 0.084 75.576 ;
    END
  END i_row[143]
  PIN i_row[144]
    DIRECTION INPUT ;
    USE SIGNAL ;
    PORT
      LAYER M4 ;
        RECT  0 75.984 0.084 76.008 ;
    END
  END i_row[144]
  PIN i_row[145]
    DIRECTION INPUT ;
    USE SIGNAL ;
    PORT
      LAYER M4 ;
        RECT  0 76.416 0.084 76.44 ;
    END
  END i_row[145]
  PIN i_row[146]
    DIRECTION INPUT ;
    USE SIGNAL ;
    PORT
      LAYER M4 ;
        RECT  0 76.848 0.084 76.872 ;
    END
  END i_row[146]
  PIN i_row[147]
    DIRECTION INPUT ;
    USE SIGNAL ;
    PORT
      LAYER M4 ;
        RECT  0 77.28 0.084 77.304 ;
    END
  END i_row[147]
  PIN i_row[148]
    DIRECTION INPUT ;
    USE SIGNAL ;
    PORT
      LAYER M4 ;
        RECT  0 77.712 0.084 77.736 ;
    END
  END i_row[148]
  PIN i_row[149]
    DIRECTION INPUT ;
    USE SIGNAL ;
    PORT
      LAYER M4 ;
        RECT  0 78.144 0.084 78.168 ;
    END
  END i_row[149]
  PIN i_row[14]
    DIRECTION INPUT ;
    USE SIGNAL ;
    PORT
      LAYER M4 ;
        RECT  0 19.824 0.084 19.848 ;
    END
  END i_row[14]
  PIN i_row[150]
    DIRECTION INPUT ;
    USE SIGNAL ;
    PORT
      LAYER M4 ;
        RECT  0 78.576 0.084 78.6 ;
    END
  END i_row[150]
  PIN i_row[151]
    DIRECTION INPUT ;
    USE SIGNAL ;
    PORT
      LAYER M4 ;
        RECT  0 79.008 0.084 79.032 ;
    END
  END i_row[151]
  PIN i_row[152]
    DIRECTION INPUT ;
    USE SIGNAL ;
    PORT
      LAYER M4 ;
        RECT  0 79.44 0.084 79.464 ;
    END
  END i_row[152]
  PIN i_row[153]
    DIRECTION INPUT ;
    USE SIGNAL ;
    PORT
      LAYER M4 ;
        RECT  0 79.872 0.084 79.896 ;
    END
  END i_row[153]
  PIN i_row[154]
    DIRECTION INPUT ;
    USE SIGNAL ;
    PORT
      LAYER M4 ;
        RECT  0 80.304 0.084 80.328 ;
    END
  END i_row[154]
  PIN i_row[155]
    DIRECTION INPUT ;
    USE SIGNAL ;
    PORT
      LAYER M4 ;
        RECT  0 80.736 0.084 80.76 ;
    END
  END i_row[155]
  PIN i_row[156]
    DIRECTION INPUT ;
    USE SIGNAL ;
    PORT
      LAYER M4 ;
        RECT  0 81.168 0.084 81.192 ;
    END
  END i_row[156]
  PIN i_row[157]
    DIRECTION INPUT ;
    USE SIGNAL ;
    PORT
      LAYER M4 ;
        RECT  0 81.6 0.084 81.624 ;
    END
  END i_row[157]
  PIN i_row[158]
    DIRECTION INPUT ;
    USE SIGNAL ;
    PORT
      LAYER M4 ;
        RECT  0 82.032 0.084 82.056 ;
    END
  END i_row[158]
  PIN i_row[159]
    DIRECTION INPUT ;
    USE SIGNAL ;
    PORT
      LAYER M4 ;
        RECT  0 82.464 0.084 82.488 ;
    END
  END i_row[159]
  PIN i_row[15]
    DIRECTION INPUT ;
    USE SIGNAL ;
    PORT
      LAYER M4 ;
        RECT  0 20.256 0.084 20.28 ;
    END
  END i_row[15]
  PIN i_row[160]
    DIRECTION INPUT ;
    USE SIGNAL ;
    PORT
      LAYER M4 ;
        RECT  0 82.896 0.084 82.92 ;
    END
  END i_row[160]
  PIN i_row[161]
    DIRECTION INPUT ;
    USE SIGNAL ;
    PORT
      LAYER M4 ;
        RECT  0 83.328 0.084 83.352 ;
    END
  END i_row[161]
  PIN i_row[162]
    DIRECTION INPUT ;
    USE SIGNAL ;
    PORT
      LAYER M4 ;
        RECT  0 83.76 0.084 83.784 ;
    END
  END i_row[162]
  PIN i_row[163]
    DIRECTION INPUT ;
    USE SIGNAL ;
    PORT
      LAYER M4 ;
        RECT  0 84.192 0.084 84.216 ;
    END
  END i_row[163]
  PIN i_row[164]
    DIRECTION INPUT ;
    USE SIGNAL ;
    PORT
      LAYER M4 ;
        RECT  0 84.624 0.084 84.648 ;
    END
  END i_row[164]
  PIN i_row[165]
    DIRECTION INPUT ;
    USE SIGNAL ;
    PORT
      LAYER M4 ;
        RECT  0 85.056 0.084 85.08 ;
    END
  END i_row[165]
  PIN i_row[166]
    DIRECTION INPUT ;
    USE SIGNAL ;
    PORT
      LAYER M4 ;
        RECT  0 85.488 0.084 85.512 ;
    END
  END i_row[166]
  PIN i_row[167]
    DIRECTION INPUT ;
    USE SIGNAL ;
    PORT
      LAYER M4 ;
        RECT  0 85.92 0.084 85.944 ;
    END
  END i_row[167]
  PIN i_row[168]
    DIRECTION INPUT ;
    USE SIGNAL ;
    PORT
      LAYER M4 ;
        RECT  0 86.352 0.084 86.376 ;
    END
  END i_row[168]
  PIN i_row[169]
    DIRECTION INPUT ;
    USE SIGNAL ;
    PORT
      LAYER M4 ;
        RECT  0 86.784 0.084 86.808 ;
    END
  END i_row[169]
  PIN i_row[16]
    DIRECTION INPUT ;
    USE SIGNAL ;
    PORT
      LAYER M4 ;
        RECT  0 20.688 0.084 20.712 ;
    END
  END i_row[16]
  PIN i_row[170]
    DIRECTION INPUT ;
    USE SIGNAL ;
    PORT
      LAYER M4 ;
        RECT  0 87.216 0.084 87.24 ;
    END
  END i_row[170]
  PIN i_row[171]
    DIRECTION INPUT ;
    USE SIGNAL ;
    PORT
      LAYER M4 ;
        RECT  0 87.648 0.084 87.672 ;
    END
  END i_row[171]
  PIN i_row[172]
    DIRECTION INPUT ;
    USE SIGNAL ;
    PORT
      LAYER M4 ;
        RECT  0 88.08 0.084 88.104 ;
    END
  END i_row[172]
  PIN i_row[173]
    DIRECTION INPUT ;
    USE SIGNAL ;
    PORT
      LAYER M4 ;
        RECT  0 88.512 0.084 88.536 ;
    END
  END i_row[173]
  PIN i_row[174]
    DIRECTION INPUT ;
    USE SIGNAL ;
    PORT
      LAYER M4 ;
        RECT  0 88.944 0.084 88.968 ;
    END
  END i_row[174]
  PIN i_row[175]
    DIRECTION INPUT ;
    USE SIGNAL ;
    PORT
      LAYER M4 ;
        RECT  0 89.376 0.084 89.4 ;
    END
  END i_row[175]
  PIN i_row[176]
    DIRECTION INPUT ;
    USE SIGNAL ;
    PORT
      LAYER M4 ;
        RECT  0 89.808 0.084 89.832 ;
    END
  END i_row[176]
  PIN i_row[177]
    DIRECTION INPUT ;
    USE SIGNAL ;
    PORT
      LAYER M4 ;
        RECT  0 90.24 0.084 90.264 ;
    END
  END i_row[177]
  PIN i_row[178]
    DIRECTION INPUT ;
    USE SIGNAL ;
    PORT
      LAYER M4 ;
        RECT  0 90.672 0.084 90.696 ;
    END
  END i_row[178]
  PIN i_row[179]
    DIRECTION INPUT ;
    USE SIGNAL ;
    PORT
      LAYER M4 ;
        RECT  0 91.104 0.084 91.128 ;
    END
  END i_row[179]
  PIN i_row[17]
    DIRECTION INPUT ;
    USE SIGNAL ;
    PORT
      LAYER M4 ;
        RECT  0 21.12 0.084 21.144 ;
    END
  END i_row[17]
  PIN i_row[180]
    DIRECTION INPUT ;
    USE SIGNAL ;
    PORT
      LAYER M4 ;
        RECT  0 91.536 0.084 91.56 ;
    END
  END i_row[180]
  PIN i_row[181]
    DIRECTION INPUT ;
    USE SIGNAL ;
    PORT
      LAYER M4 ;
        RECT  0 91.968 0.084 91.992 ;
    END
  END i_row[181]
  PIN i_row[182]
    DIRECTION INPUT ;
    USE SIGNAL ;
    PORT
      LAYER M4 ;
        RECT  0 92.4 0.084 92.424 ;
    END
  END i_row[182]
  PIN i_row[183]
    DIRECTION INPUT ;
    USE SIGNAL ;
    PORT
      LAYER M4 ;
        RECT  0 92.832 0.084 92.856 ;
    END
  END i_row[183]
  PIN i_row[184]
    DIRECTION INPUT ;
    USE SIGNAL ;
    PORT
      LAYER M4 ;
        RECT  0 93.264 0.084 93.288 ;
    END
  END i_row[184]
  PIN i_row[185]
    DIRECTION INPUT ;
    USE SIGNAL ;
    PORT
      LAYER M4 ;
        RECT  0 93.696 0.084 93.72 ;
    END
  END i_row[185]
  PIN i_row[186]
    DIRECTION INPUT ;
    USE SIGNAL ;
    PORT
      LAYER M4 ;
        RECT  0 94.128 0.084 94.152 ;
    END
  END i_row[186]
  PIN i_row[187]
    DIRECTION INPUT ;
    USE SIGNAL ;
    PORT
      LAYER M4 ;
        RECT  0 94.56 0.084 94.584 ;
    END
  END i_row[187]
  PIN i_row[188]
    DIRECTION INPUT ;
    USE SIGNAL ;
    PORT
      LAYER M4 ;
        RECT  0 94.992 0.084 95.016 ;
    END
  END i_row[188]
  PIN i_row[189]
    DIRECTION INPUT ;
    USE SIGNAL ;
    PORT
      LAYER M4 ;
        RECT  0 95.424 0.084 95.448 ;
    END
  END i_row[189]
  PIN i_row[18]
    DIRECTION INPUT ;
    USE SIGNAL ;
    PORT
      LAYER M4 ;
        RECT  0 21.552 0.084 21.576 ;
    END
  END i_row[18]
  PIN i_row[190]
    DIRECTION INPUT ;
    USE SIGNAL ;
    PORT
      LAYER M4 ;
        RECT  0 95.856 0.084 95.88 ;
    END
  END i_row[190]
  PIN i_row[191]
    DIRECTION INPUT ;
    USE SIGNAL ;
    PORT
      LAYER M4 ;
        RECT  0 96.288 0.084 96.312 ;
    END
  END i_row[191]
  PIN i_row[192]
    DIRECTION INPUT ;
    USE SIGNAL ;
    PORT
      LAYER M4 ;
        RECT  0 96.72 0.084 96.744 ;
    END
  END i_row[192]
  PIN i_row[193]
    DIRECTION INPUT ;
    USE SIGNAL ;
    PORT
      LAYER M4 ;
        RECT  0 97.152 0.084 97.176 ;
    END
  END i_row[193]
  PIN i_row[194]
    DIRECTION INPUT ;
    USE SIGNAL ;
    PORT
      LAYER M4 ;
        RECT  0 97.584 0.084 97.608 ;
    END
  END i_row[194]
  PIN i_row[195]
    DIRECTION INPUT ;
    USE SIGNAL ;
    PORT
      LAYER M4 ;
        RECT  0 98.016 0.084 98.04 ;
    END
  END i_row[195]
  PIN i_row[196]
    DIRECTION INPUT ;
    USE SIGNAL ;
    PORT
      LAYER M4 ;
        RECT  0 98.448 0.084 98.472 ;
    END
  END i_row[196]
  PIN i_row[197]
    DIRECTION INPUT ;
    USE SIGNAL ;
    PORT
      LAYER M4 ;
        RECT  0 98.88 0.084 98.904 ;
    END
  END i_row[197]
  PIN i_row[198]
    DIRECTION INPUT ;
    USE SIGNAL ;
    PORT
      LAYER M4 ;
        RECT  0 99.312 0.084 99.336 ;
    END
  END i_row[198]
  PIN i_row[199]
    DIRECTION INPUT ;
    USE SIGNAL ;
    PORT
      LAYER M4 ;
        RECT  0 99.744 0.084 99.768 ;
    END
  END i_row[199]
  PIN i_row[19]
    DIRECTION INPUT ;
    USE SIGNAL ;
    PORT
      LAYER M4 ;
        RECT  0 21.984 0.084 22.008 ;
    END
  END i_row[19]
  PIN i_row[1]
    DIRECTION INPUT ;
    USE SIGNAL ;
    PORT
      LAYER M4 ;
        RECT  0 14.208 0.084 14.232 ;
    END
  END i_row[1]
  PIN i_row[200]
    DIRECTION INPUT ;
    USE SIGNAL ;
    PORT
      LAYER M4 ;
        RECT  0 100.176 0.084 100.2 ;
    END
  END i_row[200]
  PIN i_row[201]
    DIRECTION INPUT ;
    USE SIGNAL ;
    PORT
      LAYER M4 ;
        RECT  0 100.608 0.084 100.632 ;
    END
  END i_row[201]
  PIN i_row[202]
    DIRECTION INPUT ;
    USE SIGNAL ;
    PORT
      LAYER M4 ;
        RECT  0 101.04 0.084 101.064 ;
    END
  END i_row[202]
  PIN i_row[203]
    DIRECTION INPUT ;
    USE SIGNAL ;
    PORT
      LAYER M4 ;
        RECT  0 101.472 0.084 101.496 ;
    END
  END i_row[203]
  PIN i_row[204]
    DIRECTION INPUT ;
    USE SIGNAL ;
    PORT
      LAYER M4 ;
        RECT  0 101.904 0.084 101.928 ;
    END
  END i_row[204]
  PIN i_row[205]
    DIRECTION INPUT ;
    USE SIGNAL ;
    PORT
      LAYER M4 ;
        RECT  0 102.336 0.084 102.36 ;
    END
  END i_row[205]
  PIN i_row[206]
    DIRECTION INPUT ;
    USE SIGNAL ;
    PORT
      LAYER M4 ;
        RECT  0 102.768 0.084 102.792 ;
    END
  END i_row[206]
  PIN i_row[207]
    DIRECTION INPUT ;
    USE SIGNAL ;
    PORT
      LAYER M4 ;
        RECT  0 103.2 0.084 103.224 ;
    END
  END i_row[207]
  PIN i_row[208]
    DIRECTION INPUT ;
    USE SIGNAL ;
    PORT
      LAYER M4 ;
        RECT  0 103.632 0.084 103.656 ;
    END
  END i_row[208]
  PIN i_row[209]
    DIRECTION INPUT ;
    USE SIGNAL ;
    PORT
      LAYER M4 ;
        RECT  0 104.064 0.084 104.088 ;
    END
  END i_row[209]
  PIN i_row[20]
    DIRECTION INPUT ;
    USE SIGNAL ;
    PORT
      LAYER M4 ;
        RECT  0 22.416 0.084 22.44 ;
    END
  END i_row[20]
  PIN i_row[210]
    DIRECTION INPUT ;
    USE SIGNAL ;
    PORT
      LAYER M4 ;
        RECT  0 104.496 0.084 104.52 ;
    END
  END i_row[210]
  PIN i_row[211]
    DIRECTION INPUT ;
    USE SIGNAL ;
    PORT
      LAYER M4 ;
        RECT  0 104.928 0.084 104.952 ;
    END
  END i_row[211]
  PIN i_row[212]
    DIRECTION INPUT ;
    USE SIGNAL ;
    PORT
      LAYER M4 ;
        RECT  0 105.36 0.084 105.384 ;
    END
  END i_row[212]
  PIN i_row[213]
    DIRECTION INPUT ;
    USE SIGNAL ;
    PORT
      LAYER M4 ;
        RECT  0 105.792 0.084 105.816 ;
    END
  END i_row[213]
  PIN i_row[214]
    DIRECTION INPUT ;
    USE SIGNAL ;
    PORT
      LAYER M4 ;
        RECT  0 106.224 0.084 106.248 ;
    END
  END i_row[214]
  PIN i_row[215]
    DIRECTION INPUT ;
    USE SIGNAL ;
    PORT
      LAYER M4 ;
        RECT  0 106.656 0.084 106.68 ;
    END
  END i_row[215]
  PIN i_row[216]
    DIRECTION INPUT ;
    USE SIGNAL ;
    PORT
      LAYER M4 ;
        RECT  0 107.088 0.084 107.112 ;
    END
  END i_row[216]
  PIN i_row[217]
    DIRECTION INPUT ;
    USE SIGNAL ;
    PORT
      LAYER M4 ;
        RECT  0 107.52 0.084 107.544 ;
    END
  END i_row[217]
  PIN i_row[218]
    DIRECTION INPUT ;
    USE SIGNAL ;
    PORT
      LAYER M4 ;
        RECT  0 107.952 0.084 107.976 ;
    END
  END i_row[218]
  PIN i_row[219]
    DIRECTION INPUT ;
    USE SIGNAL ;
    PORT
      LAYER M4 ;
        RECT  0 108.384 0.084 108.408 ;
    END
  END i_row[219]
  PIN i_row[21]
    DIRECTION INPUT ;
    USE SIGNAL ;
    PORT
      LAYER M4 ;
        RECT  0 22.848 0.084 22.872 ;
    END
  END i_row[21]
  PIN i_row[220]
    DIRECTION INPUT ;
    USE SIGNAL ;
    PORT
      LAYER M4 ;
        RECT  0 108.816 0.084 108.84 ;
    END
  END i_row[220]
  PIN i_row[221]
    DIRECTION INPUT ;
    USE SIGNAL ;
    PORT
      LAYER M4 ;
        RECT  0 109.248 0.084 109.272 ;
    END
  END i_row[221]
  PIN i_row[222]
    DIRECTION INPUT ;
    USE SIGNAL ;
    PORT
      LAYER M4 ;
        RECT  0 109.68 0.084 109.704 ;
    END
  END i_row[222]
  PIN i_row[223]
    DIRECTION INPUT ;
    USE SIGNAL ;
    PORT
      LAYER M4 ;
        RECT  0 110.112 0.084 110.136 ;
    END
  END i_row[223]
  PIN i_row[224]
    DIRECTION INPUT ;
    USE SIGNAL ;
    PORT
      LAYER M4 ;
        RECT  0 110.544 0.084 110.568 ;
    END
  END i_row[224]
  PIN i_row[225]
    DIRECTION INPUT ;
    USE SIGNAL ;
    PORT
      LAYER M4 ;
        RECT  0 110.976 0.084 111 ;
    END
  END i_row[225]
  PIN i_row[226]
    DIRECTION INPUT ;
    USE SIGNAL ;
    PORT
      LAYER M4 ;
        RECT  0 111.408 0.084 111.432 ;
    END
  END i_row[226]
  PIN i_row[227]
    DIRECTION INPUT ;
    USE SIGNAL ;
    PORT
      LAYER M4 ;
        RECT  0 111.84 0.084 111.864 ;
    END
  END i_row[227]
  PIN i_row[228]
    DIRECTION INPUT ;
    USE SIGNAL ;
    PORT
      LAYER M4 ;
        RECT  0 112.272 0.084 112.296 ;
    END
  END i_row[228]
  PIN i_row[229]
    DIRECTION INPUT ;
    USE SIGNAL ;
    PORT
      LAYER M4 ;
        RECT  0 112.704 0.084 112.728 ;
    END
  END i_row[229]
  PIN i_row[22]
    DIRECTION INPUT ;
    USE SIGNAL ;
    PORT
      LAYER M4 ;
        RECT  0 23.28 0.084 23.304 ;
    END
  END i_row[22]
  PIN i_row[230]
    DIRECTION INPUT ;
    USE SIGNAL ;
    PORT
      LAYER M4 ;
        RECT  0 113.136 0.084 113.16 ;
    END
  END i_row[230]
  PIN i_row[231]
    DIRECTION INPUT ;
    USE SIGNAL ;
    PORT
      LAYER M4 ;
        RECT  0 113.568 0.084 113.592 ;
    END
  END i_row[231]
  PIN i_row[232]
    DIRECTION INPUT ;
    USE SIGNAL ;
    PORT
      LAYER M4 ;
        RECT  0 114 0.084 114.024 ;
    END
  END i_row[232]
  PIN i_row[233]
    DIRECTION INPUT ;
    USE SIGNAL ;
    PORT
      LAYER M4 ;
        RECT  0 114.432 0.084 114.456 ;
    END
  END i_row[233]
  PIN i_row[234]
    DIRECTION INPUT ;
    USE SIGNAL ;
    PORT
      LAYER M4 ;
        RECT  0 114.864 0.084 114.888 ;
    END
  END i_row[234]
  PIN i_row[235]
    DIRECTION INPUT ;
    USE SIGNAL ;
    PORT
      LAYER M4 ;
        RECT  0 115.296 0.084 115.32 ;
    END
  END i_row[235]
  PIN i_row[236]
    DIRECTION INPUT ;
    USE SIGNAL ;
    PORT
      LAYER M4 ;
        RECT  0 115.728 0.084 115.752 ;
    END
  END i_row[236]
  PIN i_row[237]
    DIRECTION INPUT ;
    USE SIGNAL ;
    PORT
      LAYER M4 ;
        RECT  0 116.16 0.084 116.184 ;
    END
  END i_row[237]
  PIN i_row[238]
    DIRECTION INPUT ;
    USE SIGNAL ;
    PORT
      LAYER M4 ;
        RECT  0 116.592 0.084 116.616 ;
    END
  END i_row[238]
  PIN i_row[239]
    DIRECTION INPUT ;
    USE SIGNAL ;
    PORT
      LAYER M4 ;
        RECT  0 117.024 0.084 117.048 ;
    END
  END i_row[239]
  PIN i_row[23]
    DIRECTION INPUT ;
    USE SIGNAL ;
    PORT
      LAYER M4 ;
        RECT  0 23.712 0.084 23.736 ;
    END
  END i_row[23]
  PIN i_row[240]
    DIRECTION INPUT ;
    USE SIGNAL ;
    PORT
      LAYER M4 ;
        RECT  0 117.456 0.084 117.48 ;
    END
  END i_row[240]
  PIN i_row[241]
    DIRECTION INPUT ;
    USE SIGNAL ;
    PORT
      LAYER M4 ;
        RECT  0 117.888 0.084 117.912 ;
    END
  END i_row[241]
  PIN i_row[242]
    DIRECTION INPUT ;
    USE SIGNAL ;
    PORT
      LAYER M4 ;
        RECT  0 118.32 0.084 118.344 ;
    END
  END i_row[242]
  PIN i_row[243]
    DIRECTION INPUT ;
    USE SIGNAL ;
    PORT
      LAYER M4 ;
        RECT  0 118.752 0.084 118.776 ;
    END
  END i_row[243]
  PIN i_row[244]
    DIRECTION INPUT ;
    USE SIGNAL ;
    PORT
      LAYER M4 ;
        RECT  0 119.184 0.084 119.208 ;
    END
  END i_row[244]
  PIN i_row[245]
    DIRECTION INPUT ;
    USE SIGNAL ;
    PORT
      LAYER M4 ;
        RECT  0 119.616 0.084 119.64 ;
    END
  END i_row[245]
  PIN i_row[246]
    DIRECTION INPUT ;
    USE SIGNAL ;
    PORT
      LAYER M4 ;
        RECT  0 120.048 0.084 120.072 ;
    END
  END i_row[246]
  PIN i_row[247]
    DIRECTION INPUT ;
    USE SIGNAL ;
    PORT
      LAYER M4 ;
        RECT  0 120.48 0.084 120.504 ;
    END
  END i_row[247]
  PIN i_row[248]
    DIRECTION INPUT ;
    USE SIGNAL ;
    PORT
      LAYER M4 ;
        RECT  0 120.912 0.084 120.936 ;
    END
  END i_row[248]
  PIN i_row[249]
    DIRECTION INPUT ;
    USE SIGNAL ;
    PORT
      LAYER M4 ;
        RECT  0 121.344 0.084 121.368 ;
    END
  END i_row[249]
  PIN i_row[24]
    DIRECTION INPUT ;
    USE SIGNAL ;
    PORT
      LAYER M4 ;
        RECT  0 24.144 0.084 24.168 ;
    END
  END i_row[24]
  PIN i_row[250]
    DIRECTION INPUT ;
    USE SIGNAL ;
    PORT
      LAYER M4 ;
        RECT  0 121.776 0.084 121.8 ;
    END
  END i_row[250]
  PIN i_row[251]
    DIRECTION INPUT ;
    USE SIGNAL ;
    PORT
      LAYER M4 ;
        RECT  0 122.208 0.084 122.232 ;
    END
  END i_row[251]
  PIN i_row[25]
    DIRECTION INPUT ;
    USE SIGNAL ;
    PORT
      LAYER M4 ;
        RECT  0 24.576 0.084 24.6 ;
    END
  END i_row[25]
  PIN i_row[26]
    DIRECTION INPUT ;
    USE SIGNAL ;
    PORT
      LAYER M4 ;
        RECT  0 25.008 0.084 25.032 ;
    END
  END i_row[26]
  PIN i_row[27]
    DIRECTION INPUT ;
    USE SIGNAL ;
    PORT
      LAYER M4 ;
        RECT  0 25.44 0.084 25.464 ;
    END
  END i_row[27]
  PIN i_row[28]
    DIRECTION INPUT ;
    USE SIGNAL ;
    PORT
      LAYER M4 ;
        RECT  0 25.872 0.084 25.896 ;
    END
  END i_row[28]
  PIN i_row[29]
    DIRECTION INPUT ;
    USE SIGNAL ;
    PORT
      LAYER M4 ;
        RECT  0 26.304 0.084 26.328 ;
    END
  END i_row[29]
  PIN i_row[2]
    DIRECTION INPUT ;
    USE SIGNAL ;
    PORT
      LAYER M4 ;
        RECT  0 14.64 0.084 14.664 ;
    END
  END i_row[2]
  PIN i_row[30]
    DIRECTION INPUT ;
    USE SIGNAL ;
    PORT
      LAYER M4 ;
        RECT  0 26.736 0.084 26.76 ;
    END
  END i_row[30]
  PIN i_row[31]
    DIRECTION INPUT ;
    USE SIGNAL ;
    PORT
      LAYER M4 ;
        RECT  0 27.168 0.084 27.192 ;
    END
  END i_row[31]
  PIN i_row[32]
    DIRECTION INPUT ;
    USE SIGNAL ;
    PORT
      LAYER M4 ;
        RECT  0 27.6 0.084 27.624 ;
    END
  END i_row[32]
  PIN i_row[33]
    DIRECTION INPUT ;
    USE SIGNAL ;
    PORT
      LAYER M4 ;
        RECT  0 28.032 0.084 28.056 ;
    END
  END i_row[33]
  PIN i_row[34]
    DIRECTION INPUT ;
    USE SIGNAL ;
    PORT
      LAYER M4 ;
        RECT  0 28.464 0.084 28.488 ;
    END
  END i_row[34]
  PIN i_row[35]
    DIRECTION INPUT ;
    USE SIGNAL ;
    PORT
      LAYER M4 ;
        RECT  0 28.896 0.084 28.92 ;
    END
  END i_row[35]
  PIN i_row[36]
    DIRECTION INPUT ;
    USE SIGNAL ;
    PORT
      LAYER M4 ;
        RECT  0 29.328 0.084 29.352 ;
    END
  END i_row[36]
  PIN i_row[37]
    DIRECTION INPUT ;
    USE SIGNAL ;
    PORT
      LAYER M4 ;
        RECT  0 29.76 0.084 29.784 ;
    END
  END i_row[37]
  PIN i_row[38]
    DIRECTION INPUT ;
    USE SIGNAL ;
    PORT
      LAYER M4 ;
        RECT  0 30.192 0.084 30.216 ;
    END
  END i_row[38]
  PIN i_row[39]
    DIRECTION INPUT ;
    USE SIGNAL ;
    PORT
      LAYER M4 ;
        RECT  0 30.624 0.084 30.648 ;
    END
  END i_row[39]
  PIN i_row[3]
    DIRECTION INPUT ;
    USE SIGNAL ;
    PORT
      LAYER M4 ;
        RECT  0 15.072 0.084 15.096 ;
    END
  END i_row[3]
  PIN i_row[40]
    DIRECTION INPUT ;
    USE SIGNAL ;
    PORT
      LAYER M4 ;
        RECT  0 31.056 0.084 31.08 ;
    END
  END i_row[40]
  PIN i_row[41]
    DIRECTION INPUT ;
    USE SIGNAL ;
    PORT
      LAYER M4 ;
        RECT  0 31.488 0.084 31.512 ;
    END
  END i_row[41]
  PIN i_row[42]
    DIRECTION INPUT ;
    USE SIGNAL ;
    PORT
      LAYER M4 ;
        RECT  0 31.92 0.084 31.944 ;
    END
  END i_row[42]
  PIN i_row[43]
    DIRECTION INPUT ;
    USE SIGNAL ;
    PORT
      LAYER M4 ;
        RECT  0 32.352 0.084 32.376 ;
    END
  END i_row[43]
  PIN i_row[44]
    DIRECTION INPUT ;
    USE SIGNAL ;
    PORT
      LAYER M4 ;
        RECT  0 32.784 0.084 32.808 ;
    END
  END i_row[44]
  PIN i_row[45]
    DIRECTION INPUT ;
    USE SIGNAL ;
    PORT
      LAYER M4 ;
        RECT  0 33.216 0.084 33.24 ;
    END
  END i_row[45]
  PIN i_row[46]
    DIRECTION INPUT ;
    USE SIGNAL ;
    PORT
      LAYER M4 ;
        RECT  0 33.648 0.084 33.672 ;
    END
  END i_row[46]
  PIN i_row[47]
    DIRECTION INPUT ;
    USE SIGNAL ;
    PORT
      LAYER M4 ;
        RECT  0 34.08 0.084 34.104 ;
    END
  END i_row[47]
  PIN i_row[48]
    DIRECTION INPUT ;
    USE SIGNAL ;
    PORT
      LAYER M4 ;
        RECT  0 34.512 0.084 34.536 ;
    END
  END i_row[48]
  PIN i_row[49]
    DIRECTION INPUT ;
    USE SIGNAL ;
    PORT
      LAYER M4 ;
        RECT  0 34.944 0.084 34.968 ;
    END
  END i_row[49]
  PIN i_row[4]
    DIRECTION INPUT ;
    USE SIGNAL ;
    PORT
      LAYER M4 ;
        RECT  0 15.504 0.084 15.528 ;
    END
  END i_row[4]
  PIN i_row[50]
    DIRECTION INPUT ;
    USE SIGNAL ;
    PORT
      LAYER M4 ;
        RECT  0 35.376 0.084 35.4 ;
    END
  END i_row[50]
  PIN i_row[51]
    DIRECTION INPUT ;
    USE SIGNAL ;
    PORT
      LAYER M4 ;
        RECT  0 35.808 0.084 35.832 ;
    END
  END i_row[51]
  PIN i_row[52]
    DIRECTION INPUT ;
    USE SIGNAL ;
    PORT
      LAYER M4 ;
        RECT  0 36.24 0.084 36.264 ;
    END
  END i_row[52]
  PIN i_row[53]
    DIRECTION INPUT ;
    USE SIGNAL ;
    PORT
      LAYER M4 ;
        RECT  0 36.672 0.084 36.696 ;
    END
  END i_row[53]
  PIN i_row[54]
    DIRECTION INPUT ;
    USE SIGNAL ;
    PORT
      LAYER M4 ;
        RECT  0 37.104 0.084 37.128 ;
    END
  END i_row[54]
  PIN i_row[55]
    DIRECTION INPUT ;
    USE SIGNAL ;
    PORT
      LAYER M4 ;
        RECT  0 37.536 0.084 37.56 ;
    END
  END i_row[55]
  PIN i_row[56]
    DIRECTION INPUT ;
    USE SIGNAL ;
    PORT
      LAYER M4 ;
        RECT  0 37.968 0.084 37.992 ;
    END
  END i_row[56]
  PIN i_row[57]
    DIRECTION INPUT ;
    USE SIGNAL ;
    PORT
      LAYER M4 ;
        RECT  0 38.4 0.084 38.424 ;
    END
  END i_row[57]
  PIN i_row[58]
    DIRECTION INPUT ;
    USE SIGNAL ;
    PORT
      LAYER M4 ;
        RECT  0 38.832 0.084 38.856 ;
    END
  END i_row[58]
  PIN i_row[59]
    DIRECTION INPUT ;
    USE SIGNAL ;
    PORT
      LAYER M4 ;
        RECT  0 39.264 0.084 39.288 ;
    END
  END i_row[59]
  PIN i_row[5]
    DIRECTION INPUT ;
    USE SIGNAL ;
    PORT
      LAYER M4 ;
        RECT  0 15.936 0.084 15.96 ;
    END
  END i_row[5]
  PIN i_row[60]
    DIRECTION INPUT ;
    USE SIGNAL ;
    PORT
      LAYER M4 ;
        RECT  0 39.696 0.084 39.72 ;
    END
  END i_row[60]
  PIN i_row[61]
    DIRECTION INPUT ;
    USE SIGNAL ;
    PORT
      LAYER M4 ;
        RECT  0 40.128 0.084 40.152 ;
    END
  END i_row[61]
  PIN i_row[62]
    DIRECTION INPUT ;
    USE SIGNAL ;
    PORT
      LAYER M4 ;
        RECT  0 40.56 0.084 40.584 ;
    END
  END i_row[62]
  PIN i_row[63]
    DIRECTION INPUT ;
    USE SIGNAL ;
    PORT
      LAYER M4 ;
        RECT  0 40.992 0.084 41.016 ;
    END
  END i_row[63]
  PIN i_row[64]
    DIRECTION INPUT ;
    USE SIGNAL ;
    PORT
      LAYER M4 ;
        RECT  0 41.424 0.084 41.448 ;
    END
  END i_row[64]
  PIN i_row[65]
    DIRECTION INPUT ;
    USE SIGNAL ;
    PORT
      LAYER M4 ;
        RECT  0 41.856 0.084 41.88 ;
    END
  END i_row[65]
  PIN i_row[66]
    DIRECTION INPUT ;
    USE SIGNAL ;
    PORT
      LAYER M4 ;
        RECT  0 42.288 0.084 42.312 ;
    END
  END i_row[66]
  PIN i_row[67]
    DIRECTION INPUT ;
    USE SIGNAL ;
    PORT
      LAYER M4 ;
        RECT  0 42.72 0.084 42.744 ;
    END
  END i_row[67]
  PIN i_row[68]
    DIRECTION INPUT ;
    USE SIGNAL ;
    PORT
      LAYER M4 ;
        RECT  0 43.152 0.084 43.176 ;
    END
  END i_row[68]
  PIN i_row[69]
    DIRECTION INPUT ;
    USE SIGNAL ;
    PORT
      LAYER M4 ;
        RECT  0 43.584 0.084 43.608 ;
    END
  END i_row[69]
  PIN i_row[6]
    DIRECTION INPUT ;
    USE SIGNAL ;
    PORT
      LAYER M4 ;
        RECT  0 16.368 0.084 16.392 ;
    END
  END i_row[6]
  PIN i_row[70]
    DIRECTION INPUT ;
    USE SIGNAL ;
    PORT
      LAYER M4 ;
        RECT  0 44.016 0.084 44.04 ;
    END
  END i_row[70]
  PIN i_row[71]
    DIRECTION INPUT ;
    USE SIGNAL ;
    PORT
      LAYER M4 ;
        RECT  0 44.448 0.084 44.472 ;
    END
  END i_row[71]
  PIN i_row[72]
    DIRECTION INPUT ;
    USE SIGNAL ;
    PORT
      LAYER M4 ;
        RECT  0 44.88 0.084 44.904 ;
    END
  END i_row[72]
  PIN i_row[73]
    DIRECTION INPUT ;
    USE SIGNAL ;
    PORT
      LAYER M4 ;
        RECT  0 45.312 0.084 45.336 ;
    END
  END i_row[73]
  PIN i_row[74]
    DIRECTION INPUT ;
    USE SIGNAL ;
    PORT
      LAYER M4 ;
        RECT  0 45.744 0.084 45.768 ;
    END
  END i_row[74]
  PIN i_row[75]
    DIRECTION INPUT ;
    USE SIGNAL ;
    PORT
      LAYER M4 ;
        RECT  0 46.176 0.084 46.2 ;
    END
  END i_row[75]
  PIN i_row[76]
    DIRECTION INPUT ;
    USE SIGNAL ;
    PORT
      LAYER M4 ;
        RECT  0 46.608 0.084 46.632 ;
    END
  END i_row[76]
  PIN i_row[77]
    DIRECTION INPUT ;
    USE SIGNAL ;
    PORT
      LAYER M4 ;
        RECT  0 47.04 0.084 47.064 ;
    END
  END i_row[77]
  PIN i_row[78]
    DIRECTION INPUT ;
    USE SIGNAL ;
    PORT
      LAYER M4 ;
        RECT  0 47.472 0.084 47.496 ;
    END
  END i_row[78]
  PIN i_row[79]
    DIRECTION INPUT ;
    USE SIGNAL ;
    PORT
      LAYER M4 ;
        RECT  0 47.904 0.084 47.928 ;
    END
  END i_row[79]
  PIN i_row[7]
    DIRECTION INPUT ;
    USE SIGNAL ;
    PORT
      LAYER M4 ;
        RECT  0 16.8 0.084 16.824 ;
    END
  END i_row[7]
  PIN i_row[80]
    DIRECTION INPUT ;
    USE SIGNAL ;
    PORT
      LAYER M4 ;
        RECT  0 48.336 0.084 48.36 ;
    END
  END i_row[80]
  PIN i_row[81]
    DIRECTION INPUT ;
    USE SIGNAL ;
    PORT
      LAYER M4 ;
        RECT  0 48.768 0.084 48.792 ;
    END
  END i_row[81]
  PIN i_row[82]
    DIRECTION INPUT ;
    USE SIGNAL ;
    PORT
      LAYER M4 ;
        RECT  0 49.2 0.084 49.224 ;
    END
  END i_row[82]
  PIN i_row[83]
    DIRECTION INPUT ;
    USE SIGNAL ;
    PORT
      LAYER M4 ;
        RECT  0 49.632 0.084 49.656 ;
    END
  END i_row[83]
  PIN i_row[84]
    DIRECTION INPUT ;
    USE SIGNAL ;
    PORT
      LAYER M4 ;
        RECT  0 50.064 0.084 50.088 ;
    END
  END i_row[84]
  PIN i_row[85]
    DIRECTION INPUT ;
    USE SIGNAL ;
    PORT
      LAYER M4 ;
        RECT  0 50.496 0.084 50.52 ;
    END
  END i_row[85]
  PIN i_row[86]
    DIRECTION INPUT ;
    USE SIGNAL ;
    PORT
      LAYER M4 ;
        RECT  0 50.928 0.084 50.952 ;
    END
  END i_row[86]
  PIN i_row[87]
    DIRECTION INPUT ;
    USE SIGNAL ;
    PORT
      LAYER M4 ;
        RECT  0 51.36 0.084 51.384 ;
    END
  END i_row[87]
  PIN i_row[88]
    DIRECTION INPUT ;
    USE SIGNAL ;
    PORT
      LAYER M4 ;
        RECT  0 51.792 0.084 51.816 ;
    END
  END i_row[88]
  PIN i_row[89]
    DIRECTION INPUT ;
    USE SIGNAL ;
    PORT
      LAYER M4 ;
        RECT  0 52.224 0.084 52.248 ;
    END
  END i_row[89]
  PIN i_row[8]
    DIRECTION INPUT ;
    USE SIGNAL ;
    PORT
      LAYER M4 ;
        RECT  0 17.232 0.084 17.256 ;
    END
  END i_row[8]
  PIN i_row[90]
    DIRECTION INPUT ;
    USE SIGNAL ;
    PORT
      LAYER M4 ;
        RECT  0 52.656 0.084 52.68 ;
    END
  END i_row[90]
  PIN i_row[91]
    DIRECTION INPUT ;
    USE SIGNAL ;
    PORT
      LAYER M4 ;
        RECT  0 53.088 0.084 53.112 ;
    END
  END i_row[91]
  PIN i_row[92]
    DIRECTION INPUT ;
    USE SIGNAL ;
    PORT
      LAYER M4 ;
        RECT  0 53.52 0.084 53.544 ;
    END
  END i_row[92]
  PIN i_row[93]
    DIRECTION INPUT ;
    USE SIGNAL ;
    PORT
      LAYER M4 ;
        RECT  0 53.952 0.084 53.976 ;
    END
  END i_row[93]
  PIN i_row[94]
    DIRECTION INPUT ;
    USE SIGNAL ;
    PORT
      LAYER M4 ;
        RECT  0 54.384 0.084 54.408 ;
    END
  END i_row[94]
  PIN i_row[95]
    DIRECTION INPUT ;
    USE SIGNAL ;
    PORT
      LAYER M4 ;
        RECT  0 54.816 0.084 54.84 ;
    END
  END i_row[95]
  PIN i_row[96]
    DIRECTION INPUT ;
    USE SIGNAL ;
    PORT
      LAYER M4 ;
        RECT  0 55.248 0.084 55.272 ;
    END
  END i_row[96]
  PIN i_row[97]
    DIRECTION INPUT ;
    USE SIGNAL ;
    PORT
      LAYER M4 ;
        RECT  0 55.68 0.084 55.704 ;
    END
  END i_row[97]
  PIN i_row[98]
    DIRECTION INPUT ;
    USE SIGNAL ;
    PORT
      LAYER M4 ;
        RECT  0 56.112 0.084 56.136 ;
    END
  END i_row[98]
  PIN i_row[99]
    DIRECTION INPUT ;
    USE SIGNAL ;
    PORT
      LAYER M4 ;
        RECT  0 56.544 0.084 56.568 ;
    END
  END i_row[99]
  PIN i_row[9]
    DIRECTION INPUT ;
    USE SIGNAL ;
    PORT
      LAYER M4 ;
        RECT  0 17.664 0.084 17.688 ;
    END
  END i_row[9]
  PIN i_slot[0]
    DIRECTION INPUT ;
    USE SIGNAL ;
    PORT
      LAYER M4 ;
        RECT  0 122.64 0.084 122.664 ;
    END
  END i_slot[0]
  PIN i_slot[10]
    DIRECTION INPUT ;
    USE SIGNAL ;
    PORT
      LAYER M4 ;
        RECT  0 126.96 0.084 126.984 ;
    END
  END i_slot[10]
  PIN i_slot[11]
    DIRECTION INPUT ;
    USE SIGNAL ;
    PORT
      LAYER M4 ;
        RECT  0 127.392 0.084 127.416 ;
    END
  END i_slot[11]
  PIN i_slot[12]
    DIRECTION INPUT ;
    USE SIGNAL ;
    PORT
      LAYER M4 ;
        RECT  0 127.824 0.084 127.848 ;
    END
  END i_slot[12]
  PIN i_slot[13]
    DIRECTION INPUT ;
    USE SIGNAL ;
    PORT
      LAYER M4 ;
        RECT  0 128.256 0.084 128.28 ;
    END
  END i_slot[13]
  PIN i_slot[14]
    DIRECTION INPUT ;
    USE SIGNAL ;
    PORT
      LAYER M4 ;
        RECT  0 128.688 0.084 128.712 ;
    END
  END i_slot[14]
  PIN i_slot[15]
    DIRECTION INPUT ;
    USE SIGNAL ;
    PORT
      LAYER M4 ;
        RECT  0 129.12 0.084 129.144 ;
    END
  END i_slot[15]
  PIN i_slot[16]
    DIRECTION INPUT ;
    USE SIGNAL ;
    PORT
      LAYER M4 ;
        RECT  0 129.552 0.084 129.576 ;
    END
  END i_slot[16]
  PIN i_slot[17]
    DIRECTION INPUT ;
    USE SIGNAL ;
    PORT
      LAYER M4 ;
        RECT  0 129.984 0.084 130.008 ;
    END
  END i_slot[17]
  PIN i_slot[18]
    DIRECTION INPUT ;
    USE SIGNAL ;
    PORT
      LAYER M4 ;
        RECT  0 130.416 0.084 130.44 ;
    END
  END i_slot[18]
  PIN i_slot[19]
    DIRECTION INPUT ;
    USE SIGNAL ;
    PORT
      LAYER M4 ;
        RECT  0 130.848 0.084 130.872 ;
    END
  END i_slot[19]
  PIN i_slot[1]
    DIRECTION INPUT ;
    USE SIGNAL ;
    PORT
      LAYER M4 ;
        RECT  0 123.072 0.084 123.096 ;
    END
  END i_slot[1]
  PIN i_slot[20]
    DIRECTION INPUT ;
    USE SIGNAL ;
    PORT
      LAYER M4 ;
        RECT  0 131.28 0.084 131.304 ;
    END
  END i_slot[20]
  PIN i_slot[21]
    DIRECTION INPUT ;
    USE SIGNAL ;
    PORT
      LAYER M4 ;
        RECT  0 131.712 0.084 131.736 ;
    END
  END i_slot[21]
  PIN i_slot[22]
    DIRECTION INPUT ;
    USE SIGNAL ;
    PORT
      LAYER M4 ;
        RECT  0 132.144 0.084 132.168 ;
    END
  END i_slot[22]
  PIN i_slot[23]
    DIRECTION INPUT ;
    USE SIGNAL ;
    PORT
      LAYER M4 ;
        RECT  0 132.576 0.084 132.6 ;
    END
  END i_slot[23]
  PIN i_slot[24]
    DIRECTION INPUT ;
    USE SIGNAL ;
    PORT
      LAYER M4 ;
        RECT  0 133.008 0.084 133.032 ;
    END
  END i_slot[24]
  PIN i_slot[25]
    DIRECTION INPUT ;
    USE SIGNAL ;
    PORT
      LAYER M4 ;
        RECT  0 133.44 0.084 133.464 ;
    END
  END i_slot[25]
  PIN i_slot[26]
    DIRECTION INPUT ;
    USE SIGNAL ;
    PORT
      LAYER M4 ;
        RECT  0 133.872 0.084 133.896 ;
    END
  END i_slot[26]
  PIN i_slot[27]
    DIRECTION INPUT ;
    USE SIGNAL ;
    PORT
      LAYER M4 ;
        RECT  0 134.304 0.084 134.328 ;
    END
  END i_slot[27]
  PIN i_slot[28]
    DIRECTION INPUT ;
    USE SIGNAL ;
    PORT
      LAYER M4 ;
        RECT  0 134.736 0.084 134.76 ;
    END
  END i_slot[28]
  PIN i_slot[29]
    DIRECTION INPUT ;
    USE SIGNAL ;
    PORT
      LAYER M4 ;
        RECT  0 135.168 0.084 135.192 ;
    END
  END i_slot[29]
  PIN i_slot[2]
    DIRECTION INPUT ;
    USE SIGNAL ;
    PORT
      LAYER M4 ;
        RECT  0 123.504 0.084 123.528 ;
    END
  END i_slot[2]
  PIN i_slot[30]
    DIRECTION INPUT ;
    USE SIGNAL ;
    PORT
      LAYER M4 ;
        RECT  0 135.6 0.084 135.624 ;
    END
  END i_slot[30]
  PIN i_slot[31]
    DIRECTION INPUT ;
    USE SIGNAL ;
    PORT
      LAYER M4 ;
        RECT  0 136.032 0.084 136.056 ;
    END
  END i_slot[31]
  PIN i_slot[32]
    DIRECTION INPUT ;
    USE SIGNAL ;
    PORT
      LAYER M4 ;
        RECT  0 136.464 0.084 136.488 ;
    END
  END i_slot[32]
  PIN i_slot[33]
    DIRECTION INPUT ;
    USE SIGNAL ;
    PORT
      LAYER M4 ;
        RECT  0 136.896 0.084 136.92 ;
    END
  END i_slot[33]
  PIN i_slot[34]
    DIRECTION INPUT ;
    USE SIGNAL ;
    PORT
      LAYER M4 ;
        RECT  0 137.328 0.084 137.352 ;
    END
  END i_slot[34]
  PIN i_slot[35]
    DIRECTION INPUT ;
    USE SIGNAL ;
    PORT
      LAYER M4 ;
        RECT  0 137.76 0.084 137.784 ;
    END
  END i_slot[35]
  PIN i_slot[36]
    DIRECTION INPUT ;
    USE SIGNAL ;
    PORT
      LAYER M4 ;
        RECT  0 138.192 0.084 138.216 ;
    END
  END i_slot[36]
  PIN i_slot[37]
    DIRECTION INPUT ;
    USE SIGNAL ;
    PORT
      LAYER M4 ;
        RECT  0 138.624 0.084 138.648 ;
    END
  END i_slot[37]
  PIN i_slot[38]
    DIRECTION INPUT ;
    USE SIGNAL ;
    PORT
      LAYER M4 ;
        RECT  0 139.056 0.084 139.08 ;
    END
  END i_slot[38]
  PIN i_slot[39]
    DIRECTION INPUT ;
    USE SIGNAL ;
    PORT
      LAYER M4 ;
        RECT  0 139.488 0.084 139.512 ;
    END
  END i_slot[39]
  PIN i_slot[3]
    DIRECTION INPUT ;
    USE SIGNAL ;
    PORT
      LAYER M4 ;
        RECT  0 123.936 0.084 123.96 ;
    END
  END i_slot[3]
  PIN i_slot[40]
    DIRECTION INPUT ;
    USE SIGNAL ;
    PORT
      LAYER M4 ;
        RECT  0 139.92 0.084 139.944 ;
    END
  END i_slot[40]
  PIN i_slot[41]
    DIRECTION INPUT ;
    USE SIGNAL ;
    PORT
      LAYER M4 ;
        RECT  0 140.352 0.084 140.376 ;
    END
  END i_slot[41]
  PIN i_slot[42]
    DIRECTION INPUT ;
    USE SIGNAL ;
    PORT
      LAYER M4 ;
        RECT  0 140.784 0.084 140.808 ;
    END
  END i_slot[42]
  PIN i_slot[43]
    DIRECTION INPUT ;
    USE SIGNAL ;
    PORT
      LAYER M4 ;
        RECT  0 141.216 0.084 141.24 ;
    END
  END i_slot[43]
  PIN i_slot[44]
    DIRECTION INPUT ;
    USE SIGNAL ;
    PORT
      LAYER M4 ;
        RECT  0 141.648 0.084 141.672 ;
    END
  END i_slot[44]
  PIN i_slot[45]
    DIRECTION INPUT ;
    USE SIGNAL ;
    PORT
      LAYER M4 ;
        RECT  0 142.08 0.084 142.104 ;
    END
  END i_slot[45]
  PIN i_slot[46]
    DIRECTION INPUT ;
    USE SIGNAL ;
    PORT
      LAYER M4 ;
        RECT  0 142.512 0.084 142.536 ;
    END
  END i_slot[46]
  PIN i_slot[47]
    DIRECTION INPUT ;
    USE SIGNAL ;
    PORT
      LAYER M4 ;
        RECT  0 142.944 0.084 142.968 ;
    END
  END i_slot[47]
  PIN i_slot[48]
    DIRECTION INPUT ;
    USE SIGNAL ;
    PORT
      LAYER M4 ;
        RECT  0 143.376 0.084 143.4 ;
    END
  END i_slot[48]
  PIN i_slot[49]
    DIRECTION INPUT ;
    USE SIGNAL ;
    PORT
      LAYER M4 ;
        RECT  0 143.808 0.084 143.832 ;
    END
  END i_slot[49]
  PIN i_slot[4]
    DIRECTION INPUT ;
    USE SIGNAL ;
    PORT
      LAYER M4 ;
        RECT  0 124.368 0.084 124.392 ;
    END
  END i_slot[4]
  PIN i_slot[50]
    DIRECTION INPUT ;
    USE SIGNAL ;
    PORT
      LAYER M4 ;
        RECT  0 144.24 0.084 144.264 ;
    END
  END i_slot[50]
  PIN i_slot[51]
    DIRECTION INPUT ;
    USE SIGNAL ;
    PORT
      LAYER M4 ;
        RECT  0 144.672 0.084 144.696 ;
    END
  END i_slot[51]
  PIN i_slot[52]
    DIRECTION INPUT ;
    USE SIGNAL ;
    PORT
      LAYER M4 ;
        RECT  0 145.104 0.084 145.128 ;
    END
  END i_slot[52]
  PIN i_slot[53]
    DIRECTION INPUT ;
    USE SIGNAL ;
    PORT
      LAYER M4 ;
        RECT  0 145.536 0.084 145.56 ;
    END
  END i_slot[53]
  PIN i_slot[54]
    DIRECTION INPUT ;
    USE SIGNAL ;
    PORT
      LAYER M4 ;
        RECT  0 145.968 0.084 145.992 ;
    END
  END i_slot[54]
  PIN i_slot[55]
    DIRECTION INPUT ;
    USE SIGNAL ;
    PORT
      LAYER M4 ;
        RECT  0 146.4 0.084 146.424 ;
    END
  END i_slot[55]
  PIN i_slot[56]
    DIRECTION INPUT ;
    USE SIGNAL ;
    PORT
      LAYER M4 ;
        RECT  0 146.832 0.084 146.856 ;
    END
  END i_slot[56]
  PIN i_slot[57]
    DIRECTION INPUT ;
    USE SIGNAL ;
    PORT
      LAYER M4 ;
        RECT  0 147.264 0.084 147.288 ;
    END
  END i_slot[57]
  PIN i_slot[58]
    DIRECTION INPUT ;
    USE SIGNAL ;
    PORT
      LAYER M4 ;
        RECT  0 147.696 0.084 147.72 ;
    END
  END i_slot[58]
  PIN i_slot[59]
    DIRECTION INPUT ;
    USE SIGNAL ;
    PORT
      LAYER M4 ;
        RECT  0 148.128 0.084 148.152 ;
    END
  END i_slot[59]
  PIN i_slot[5]
    DIRECTION INPUT ;
    USE SIGNAL ;
    PORT
      LAYER M4 ;
        RECT  0 124.8 0.084 124.824 ;
    END
  END i_slot[5]
  PIN i_slot[60]
    DIRECTION INPUT ;
    USE SIGNAL ;
    PORT
      LAYER M4 ;
        RECT  0 148.56 0.084 148.584 ;
    END
  END i_slot[60]
  PIN i_slot[61]
    DIRECTION INPUT ;
    USE SIGNAL ;
    PORT
      LAYER M4 ;
        RECT  0 148.992 0.084 149.016 ;
    END
  END i_slot[61]
  PIN i_slot[62]
    DIRECTION INPUT ;
    USE SIGNAL ;
    PORT
      LAYER M4 ;
        RECT  0 149.424 0.084 149.448 ;
    END
  END i_slot[62]
  PIN i_slot[63]
    DIRECTION INPUT ;
    USE SIGNAL ;
    PORT
      LAYER M4 ;
        RECT  0 149.856 0.084 149.88 ;
    END
  END i_slot[63]
  PIN i_slot[64]
    DIRECTION INPUT ;
    USE SIGNAL ;
    PORT
      LAYER M4 ;
        RECT  0 150.288 0.084 150.312 ;
    END
  END i_slot[64]
  PIN i_slot[65]
    DIRECTION INPUT ;
    USE SIGNAL ;
    PORT
      LAYER M4 ;
        RECT  0 150.72 0.084 150.744 ;
    END
  END i_slot[65]
  PIN i_slot[66]
    DIRECTION INPUT ;
    USE SIGNAL ;
    PORT
      LAYER M4 ;
        RECT  0 151.152 0.084 151.176 ;
    END
  END i_slot[66]
  PIN i_slot[67]
    DIRECTION INPUT ;
    USE SIGNAL ;
    PORT
      LAYER M4 ;
        RECT  0 151.584 0.084 151.608 ;
    END
  END i_slot[67]
  PIN i_slot[68]
    DIRECTION INPUT ;
    USE SIGNAL ;
    PORT
      LAYER M4 ;
        RECT  0 152.016 0.084 152.04 ;
    END
  END i_slot[68]
  PIN i_slot[69]
    DIRECTION INPUT ;
    USE SIGNAL ;
    PORT
      LAYER M4 ;
        RECT  0 152.448 0.084 152.472 ;
    END
  END i_slot[69]
  PIN i_slot[6]
    DIRECTION INPUT ;
    USE SIGNAL ;
    PORT
      LAYER M4 ;
        RECT  0 125.232 0.084 125.256 ;
    END
  END i_slot[6]
  PIN i_slot[70]
    DIRECTION INPUT ;
    USE SIGNAL ;
    PORT
      LAYER M4 ;
        RECT  0 152.88 0.084 152.904 ;
    END
  END i_slot[70]
  PIN i_slot[71]
    DIRECTION INPUT ;
    USE SIGNAL ;
    PORT
      LAYER M4 ;
        RECT  0 153.312 0.084 153.336 ;
    END
  END i_slot[71]
  PIN i_slot[72]
    DIRECTION INPUT ;
    USE SIGNAL ;
    PORT
      LAYER M4 ;
        RECT  0 153.744 0.084 153.768 ;
    END
  END i_slot[72]
  PIN i_slot[73]
    DIRECTION INPUT ;
    USE SIGNAL ;
    PORT
      LAYER M4 ;
        RECT  0 154.176 0.084 154.2 ;
    END
  END i_slot[73]
  PIN i_slot[74]
    DIRECTION INPUT ;
    USE SIGNAL ;
    PORT
      LAYER M4 ;
        RECT  0 154.608 0.084 154.632 ;
    END
  END i_slot[74]
  PIN i_slot[75]
    DIRECTION INPUT ;
    USE SIGNAL ;
    PORT
      LAYER M4 ;
        RECT  0 155.04 0.084 155.064 ;
    END
  END i_slot[75]
  PIN i_slot[76]
    DIRECTION INPUT ;
    USE SIGNAL ;
    PORT
      LAYER M4 ;
        RECT  0 155.472 0.084 155.496 ;
    END
  END i_slot[76]
  PIN i_slot[77]
    DIRECTION INPUT ;
    USE SIGNAL ;
    PORT
      LAYER M4 ;
        RECT  0 155.904 0.084 155.928 ;
    END
  END i_slot[77]
  PIN i_slot[78]
    DIRECTION INPUT ;
    USE SIGNAL ;
    PORT
      LAYER M4 ;
        RECT  0 156.336 0.084 156.36 ;
    END
  END i_slot[78]
  PIN i_slot[79]
    DIRECTION INPUT ;
    USE SIGNAL ;
    PORT
      LAYER M4 ;
        RECT  0 156.768 0.084 156.792 ;
    END
  END i_slot[79]
  PIN i_slot[7]
    DIRECTION INPUT ;
    USE SIGNAL ;
    PORT
      LAYER M4 ;
        RECT  0 125.664 0.084 125.688 ;
    END
  END i_slot[7]
  PIN i_slot[80]
    DIRECTION INPUT ;
    USE SIGNAL ;
    PORT
      LAYER M4 ;
        RECT  0 157.2 0.084 157.224 ;
    END
  END i_slot[80]
  PIN i_slot[81]
    DIRECTION INPUT ;
    USE SIGNAL ;
    PORT
      LAYER M4 ;
        RECT  0 157.632 0.084 157.656 ;
    END
  END i_slot[81]
  PIN i_slot[82]
    DIRECTION INPUT ;
    USE SIGNAL ;
    PORT
      LAYER M4 ;
        RECT  0 158.064 0.084 158.088 ;
    END
  END i_slot[82]
  PIN i_slot[83]
    DIRECTION INPUT ;
    USE SIGNAL ;
    PORT
      LAYER M4 ;
        RECT  0 158.496 0.084 158.52 ;
    END
  END i_slot[83]
  PIN i_slot[84]
    DIRECTION INPUT ;
    USE SIGNAL ;
    PORT
      LAYER M4 ;
        RECT  0 158.928 0.084 158.952 ;
    END
  END i_slot[84]
  PIN i_slot[85]
    DIRECTION INPUT ;
    USE SIGNAL ;
    PORT
      LAYER M4 ;
        RECT  0 159.36 0.084 159.384 ;
    END
  END i_slot[85]
  PIN i_slot[86]
    DIRECTION INPUT ;
    USE SIGNAL ;
    PORT
      LAYER M4 ;
        RECT  0 159.792 0.084 159.816 ;
    END
  END i_slot[86]
  PIN i_slot[87]
    DIRECTION INPUT ;
    USE SIGNAL ;
    PORT
      LAYER M4 ;
        RECT  0 160.224 0.084 160.248 ;
    END
  END i_slot[87]
  PIN i_slot[88]
    DIRECTION INPUT ;
    USE SIGNAL ;
    PORT
      LAYER M4 ;
        RECT  0 160.656 0.084 160.68 ;
    END
  END i_slot[88]
  PIN i_slot[89]
    DIRECTION INPUT ;
    USE SIGNAL ;
    PORT
      LAYER M4 ;
        RECT  0 161.088 0.084 161.112 ;
    END
  END i_slot[89]
  PIN i_slot[8]
    DIRECTION INPUT ;
    USE SIGNAL ;
    PORT
      LAYER M4 ;
        RECT  0 126.096 0.084 126.12 ;
    END
  END i_slot[8]
  PIN i_slot[9]
    DIRECTION INPUT ;
    USE SIGNAL ;
    PORT
      LAYER M4 ;
        RECT  0 126.528 0.084 126.552 ;
    END
  END i_slot[9]
  PIN i_v[0]
    DIRECTION INPUT ;
    USE SIGNAL ;
    PORT
      LAYER M4 ;
        RECT  0 6 0.084 6.024 ;
    END
  END i_v[0]
  PIN i_v[10]
    DIRECTION INPUT ;
    USE SIGNAL ;
    PORT
      LAYER M4 ;
        RECT  0 10.32 0.084 10.344 ;
    END
  END i_v[10]
  PIN i_v[11]
    DIRECTION INPUT ;
    USE SIGNAL ;
    PORT
      LAYER M4 ;
        RECT  0 10.752 0.084 10.776 ;
    END
  END i_v[11]
  PIN i_v[12]
    DIRECTION INPUT ;
    USE SIGNAL ;
    PORT
      LAYER M4 ;
        RECT  0 11.184 0.084 11.208 ;
    END
  END i_v[12]
  PIN i_v[13]
    DIRECTION INPUT ;
    USE SIGNAL ;
    PORT
      LAYER M4 ;
        RECT  0 11.616 0.084 11.64 ;
    END
  END i_v[13]
  PIN i_v[14]
    DIRECTION INPUT ;
    USE SIGNAL ;
    PORT
      LAYER M4 ;
        RECT  0 12.048 0.084 12.072 ;
    END
  END i_v[14]
  PIN i_v[15]
    DIRECTION INPUT ;
    USE SIGNAL ;
    PORT
      LAYER M4 ;
        RECT  0 12.48 0.084 12.504 ;
    END
  END i_v[15]
  PIN i_v[16]
    DIRECTION INPUT ;
    USE SIGNAL ;
    PORT
      LAYER M4 ;
        RECT  0 12.912 0.084 12.936 ;
    END
  END i_v[16]
  PIN i_v[17]
    DIRECTION INPUT ;
    USE SIGNAL ;
    PORT
      LAYER M4 ;
        RECT  0 13.344 0.084 13.368 ;
    END
  END i_v[17]
  PIN i_v[1]
    DIRECTION INPUT ;
    USE SIGNAL ;
    PORT
      LAYER M4 ;
        RECT  0 6.432 0.084 6.456 ;
    END
  END i_v[1]
  PIN i_v[2]
    DIRECTION INPUT ;
    USE SIGNAL ;
    PORT
      LAYER M4 ;
        RECT  0 6.864 0.084 6.888 ;
    END
  END i_v[2]
  PIN i_v[3]
    DIRECTION INPUT ;
    USE SIGNAL ;
    PORT
      LAYER M4 ;
        RECT  0 7.296 0.084 7.32 ;
    END
  END i_v[3]
  PIN i_v[4]
    DIRECTION INPUT ;
    USE SIGNAL ;
    PORT
      LAYER M4 ;
        RECT  0 7.728 0.084 7.752 ;
    END
  END i_v[4]
  PIN i_v[5]
    DIRECTION INPUT ;
    USE SIGNAL ;
    PORT
      LAYER M4 ;
        RECT  0 8.16 0.084 8.184 ;
    END
  END i_v[5]
  PIN i_v[6]
    DIRECTION INPUT ;
    USE SIGNAL ;
    PORT
      LAYER M4 ;
        RECT  0 8.592 0.084 8.616 ;
    END
  END i_v[6]
  PIN i_v[7]
    DIRECTION INPUT ;
    USE SIGNAL ;
    PORT
      LAYER M4 ;
        RECT  0 9.024 0.084 9.048 ;
    END
  END i_v[7]
  PIN i_v[8]
    DIRECTION INPUT ;
    USE SIGNAL ;
    PORT
      LAYER M4 ;
        RECT  0 9.456 0.084 9.48 ;
    END
  END i_v[8]
  PIN i_v[9]
    DIRECTION INPUT ;
    USE SIGNAL ;
    PORT
      LAYER M4 ;
        RECT  0 9.888 0.084 9.912 ;
    END
  END i_v[9]
  PIN o_addr[0]
    DIRECTION OUTPUT ;
    USE SIGNAL ;
    PORT
      LAYER M4 ;
        RECT  155.436 95.424 155.52 95.448 ;
    END
  END o_addr[0]
  PIN o_addr[10]
    DIRECTION OUTPUT ;
    USE SIGNAL ;
    PORT
      LAYER M4 ;
        RECT  155.436 99.744 155.52 99.768 ;
    END
  END o_addr[10]
  PIN o_addr[11]
    DIRECTION OUTPUT ;
    USE SIGNAL ;
    PORT
      LAYER M4 ;
        RECT  155.436 100.176 155.52 100.2 ;
    END
  END o_addr[11]
  PIN o_addr[12]
    DIRECTION OUTPUT ;
    USE SIGNAL ;
    PORT
      LAYER M4 ;
        RECT  155.436 100.608 155.52 100.632 ;
    END
  END o_addr[12]
  PIN o_addr[13]
    DIRECTION OUTPUT ;
    USE SIGNAL ;
    PORT
      LAYER M4 ;
        RECT  155.436 101.04 155.52 101.064 ;
    END
  END o_addr[13]
  PIN o_addr[14]
    DIRECTION OUTPUT ;
    USE SIGNAL ;
    PORT
      LAYER M4 ;
        RECT  155.436 101.472 155.52 101.496 ;
    END
  END o_addr[14]
  PIN o_addr[15]
    DIRECTION OUTPUT ;
    USE SIGNAL ;
    PORT
      LAYER M4 ;
        RECT  155.436 101.904 155.52 101.928 ;
    END
  END o_addr[15]
  PIN o_addr[16]
    DIRECTION OUTPUT ;
    USE SIGNAL ;
    PORT
      LAYER M4 ;
        RECT  155.436 102.336 155.52 102.36 ;
    END
  END o_addr[16]
  PIN o_addr[17]
    DIRECTION OUTPUT ;
    USE SIGNAL ;
    PORT
      LAYER M4 ;
        RECT  155.436 102.768 155.52 102.792 ;
    END
  END o_addr[17]
  PIN o_addr[18]
    DIRECTION OUTPUT ;
    USE SIGNAL ;
    PORT
      LAYER M4 ;
        RECT  155.436 103.2 155.52 103.224 ;
    END
  END o_addr[18]
  PIN o_addr[19]
    DIRECTION OUTPUT ;
    USE SIGNAL ;
    PORT
      LAYER M4 ;
        RECT  155.436 103.632 155.52 103.656 ;
    END
  END o_addr[19]
  PIN o_addr[1]
    DIRECTION OUTPUT ;
    USE SIGNAL ;
    PORT
      LAYER M4 ;
        RECT  155.436 95.856 155.52 95.88 ;
    END
  END o_addr[1]
  PIN o_addr[20]
    DIRECTION OUTPUT ;
    USE SIGNAL ;
    PORT
      LAYER M4 ;
        RECT  155.436 104.064 155.52 104.088 ;
    END
  END o_addr[20]
  PIN o_addr[21]
    DIRECTION OUTPUT ;
    USE SIGNAL ;
    PORT
      LAYER M4 ;
        RECT  155.436 104.496 155.52 104.52 ;
    END
  END o_addr[21]
  PIN o_addr[22]
    DIRECTION OUTPUT ;
    USE SIGNAL ;
    PORT
      LAYER M4 ;
        RECT  155.436 104.928 155.52 104.952 ;
    END
  END o_addr[22]
  PIN o_addr[23]
    DIRECTION OUTPUT ;
    USE SIGNAL ;
    PORT
      LAYER M4 ;
        RECT  155.436 105.36 155.52 105.384 ;
    END
  END o_addr[23]
  PIN o_addr[24]
    DIRECTION OUTPUT ;
    USE SIGNAL ;
    PORT
      LAYER M4 ;
        RECT  155.436 105.792 155.52 105.816 ;
    END
  END o_addr[24]
  PIN o_addr[25]
    DIRECTION OUTPUT ;
    USE SIGNAL ;
    PORT
      LAYER M4 ;
        RECT  155.436 106.224 155.52 106.248 ;
    END
  END o_addr[25]
  PIN o_addr[26]
    DIRECTION OUTPUT ;
    USE SIGNAL ;
    PORT
      LAYER M4 ;
        RECT  155.436 106.656 155.52 106.68 ;
    END
  END o_addr[26]
  PIN o_addr[27]
    DIRECTION OUTPUT ;
    USE SIGNAL ;
    PORT
      LAYER M4 ;
        RECT  155.436 107.088 155.52 107.112 ;
    END
  END o_addr[27]
  PIN o_addr[28]
    DIRECTION OUTPUT ;
    USE SIGNAL ;
    PORT
      LAYER M4 ;
        RECT  155.436 107.52 155.52 107.544 ;
    END
  END o_addr[28]
  PIN o_addr[29]
    DIRECTION OUTPUT ;
    USE SIGNAL ;
    PORT
      LAYER M4 ;
        RECT  155.436 107.952 155.52 107.976 ;
    END
  END o_addr[29]
  PIN o_addr[2]
    DIRECTION OUTPUT ;
    USE SIGNAL ;
    PORT
      LAYER M4 ;
        RECT  155.436 96.288 155.52 96.312 ;
    END
  END o_addr[2]
  PIN o_addr[30]
    DIRECTION OUTPUT ;
    USE SIGNAL ;
    PORT
      LAYER M4 ;
        RECT  155.436 108.384 155.52 108.408 ;
    END
  END o_addr[30]
  PIN o_addr[31]
    DIRECTION OUTPUT ;
    USE SIGNAL ;
    PORT
      LAYER M4 ;
        RECT  155.436 108.816 155.52 108.84 ;
    END
  END o_addr[31]
  PIN o_addr[32]
    DIRECTION OUTPUT ;
    USE SIGNAL ;
    PORT
      LAYER M4 ;
        RECT  155.436 109.248 155.52 109.272 ;
    END
  END o_addr[32]
  PIN o_addr[33]
    DIRECTION OUTPUT ;
    USE SIGNAL ;
    PORT
      LAYER M4 ;
        RECT  155.436 109.68 155.52 109.704 ;
    END
  END o_addr[33]
  PIN o_addr[34]
    DIRECTION OUTPUT ;
    USE SIGNAL ;
    PORT
      LAYER M4 ;
        RECT  155.436 110.112 155.52 110.136 ;
    END
  END o_addr[34]
  PIN o_addr[35]
    DIRECTION OUTPUT ;
    USE SIGNAL ;
    PORT
      LAYER M4 ;
        RECT  155.436 110.544 155.52 110.568 ;
    END
  END o_addr[35]
  PIN o_addr[36]
    DIRECTION OUTPUT ;
    USE SIGNAL ;
    PORT
      LAYER M4 ;
        RECT  155.436 110.976 155.52 111 ;
    END
  END o_addr[36]
  PIN o_addr[37]
    DIRECTION OUTPUT ;
    USE SIGNAL ;
    PORT
      LAYER M4 ;
        RECT  155.436 111.408 155.52 111.432 ;
    END
  END o_addr[37]
  PIN o_addr[38]
    DIRECTION OUTPUT ;
    USE SIGNAL ;
    PORT
      LAYER M4 ;
        RECT  155.436 111.84 155.52 111.864 ;
    END
  END o_addr[38]
  PIN o_addr[39]
    DIRECTION OUTPUT ;
    USE SIGNAL ;
    PORT
      LAYER M4 ;
        RECT  155.436 112.272 155.52 112.296 ;
    END
  END o_addr[39]
  PIN o_addr[3]
    DIRECTION OUTPUT ;
    USE SIGNAL ;
    PORT
      LAYER M4 ;
        RECT  155.436 96.72 155.52 96.744 ;
    END
  END o_addr[3]
  PIN o_addr[40]
    DIRECTION OUTPUT ;
    USE SIGNAL ;
    PORT
      LAYER M4 ;
        RECT  155.436 112.704 155.52 112.728 ;
    END
  END o_addr[40]
  PIN o_addr[41]
    DIRECTION OUTPUT ;
    USE SIGNAL ;
    PORT
      LAYER M4 ;
        RECT  155.436 113.136 155.52 113.16 ;
    END
  END o_addr[41]
  PIN o_addr[42]
    DIRECTION OUTPUT ;
    USE SIGNAL ;
    PORT
      LAYER M4 ;
        RECT  155.436 113.568 155.52 113.592 ;
    END
  END o_addr[42]
  PIN o_addr[43]
    DIRECTION OUTPUT ;
    USE SIGNAL ;
    PORT
      LAYER M4 ;
        RECT  155.436 114 155.52 114.024 ;
    END
  END o_addr[43]
  PIN o_addr[44]
    DIRECTION OUTPUT ;
    USE SIGNAL ;
    PORT
      LAYER M4 ;
        RECT  155.436 114.432 155.52 114.456 ;
    END
  END o_addr[44]
  PIN o_addr[45]
    DIRECTION OUTPUT ;
    USE SIGNAL ;
    PORT
      LAYER M4 ;
        RECT  155.436 114.864 155.52 114.888 ;
    END
  END o_addr[45]
  PIN o_addr[46]
    DIRECTION OUTPUT ;
    USE SIGNAL ;
    PORT
      LAYER M4 ;
        RECT  155.436 115.296 155.52 115.32 ;
    END
  END o_addr[46]
  PIN o_addr[47]
    DIRECTION OUTPUT ;
    USE SIGNAL ;
    PORT
      LAYER M4 ;
        RECT  155.436 115.728 155.52 115.752 ;
    END
  END o_addr[47]
  PIN o_addr[48]
    DIRECTION OUTPUT ;
    USE SIGNAL ;
    PORT
      LAYER M4 ;
        RECT  155.436 116.16 155.52 116.184 ;
    END
  END o_addr[48]
  PIN o_addr[49]
    DIRECTION OUTPUT ;
    USE SIGNAL ;
    PORT
      LAYER M4 ;
        RECT  155.436 116.592 155.52 116.616 ;
    END
  END o_addr[49]
  PIN o_addr[4]
    DIRECTION OUTPUT ;
    USE SIGNAL ;
    PORT
      LAYER M4 ;
        RECT  155.436 97.152 155.52 97.176 ;
    END
  END o_addr[4]
  PIN o_addr[50]
    DIRECTION OUTPUT ;
    USE SIGNAL ;
    PORT
      LAYER M4 ;
        RECT  155.436 117.024 155.52 117.048 ;
    END
  END o_addr[50]
  PIN o_addr[51]
    DIRECTION OUTPUT ;
    USE SIGNAL ;
    PORT
      LAYER M4 ;
        RECT  155.436 117.456 155.52 117.48 ;
    END
  END o_addr[51]
  PIN o_addr[52]
    DIRECTION OUTPUT ;
    USE SIGNAL ;
    PORT
      LAYER M4 ;
        RECT  155.436 117.888 155.52 117.912 ;
    END
  END o_addr[52]
  PIN o_addr[53]
    DIRECTION OUTPUT ;
    USE SIGNAL ;
    PORT
      LAYER M4 ;
        RECT  155.436 118.32 155.52 118.344 ;
    END
  END o_addr[53]
  PIN o_addr[54]
    DIRECTION OUTPUT ;
    USE SIGNAL ;
    PORT
      LAYER M4 ;
        RECT  155.436 118.752 155.52 118.776 ;
    END
  END o_addr[54]
  PIN o_addr[55]
    DIRECTION OUTPUT ;
    USE SIGNAL ;
    PORT
      LAYER M4 ;
        RECT  155.436 119.184 155.52 119.208 ;
    END
  END o_addr[55]
  PIN o_addr[56]
    DIRECTION OUTPUT ;
    USE SIGNAL ;
    PORT
      LAYER M4 ;
        RECT  155.436 119.616 155.52 119.64 ;
    END
  END o_addr[56]
  PIN o_addr[57]
    DIRECTION OUTPUT ;
    USE SIGNAL ;
    PORT
      LAYER M4 ;
        RECT  155.436 120.048 155.52 120.072 ;
    END
  END o_addr[57]
  PIN o_addr[58]
    DIRECTION OUTPUT ;
    USE SIGNAL ;
    PORT
      LAYER M4 ;
        RECT  155.436 120.48 155.52 120.504 ;
    END
  END o_addr[58]
  PIN o_addr[59]
    DIRECTION OUTPUT ;
    USE SIGNAL ;
    PORT
      LAYER M4 ;
        RECT  155.436 120.912 155.52 120.936 ;
    END
  END o_addr[59]
  PIN o_addr[5]
    DIRECTION OUTPUT ;
    USE SIGNAL ;
    PORT
      LAYER M4 ;
        RECT  155.436 97.584 155.52 97.608 ;
    END
  END o_addr[5]
  PIN o_addr[60]
    DIRECTION OUTPUT ;
    USE SIGNAL ;
    PORT
      LAYER M4 ;
        RECT  155.436 121.344 155.52 121.368 ;
    END
  END o_addr[60]
  PIN o_addr[61]
    DIRECTION OUTPUT ;
    USE SIGNAL ;
    PORT
      LAYER M4 ;
        RECT  155.436 121.776 155.52 121.8 ;
    END
  END o_addr[61]
  PIN o_addr[62]
    DIRECTION OUTPUT ;
    USE SIGNAL ;
    PORT
      LAYER M4 ;
        RECT  155.436 122.208 155.52 122.232 ;
    END
  END o_addr[62]
  PIN o_addr[63]
    DIRECTION OUTPUT ;
    USE SIGNAL ;
    PORT
      LAYER M4 ;
        RECT  155.436 122.64 155.52 122.664 ;
    END
  END o_addr[63]
  PIN o_addr[64]
    DIRECTION OUTPUT ;
    USE SIGNAL ;
    PORT
      LAYER M4 ;
        RECT  155.436 123.072 155.52 123.096 ;
    END
  END o_addr[64]
  PIN o_addr[65]
    DIRECTION OUTPUT ;
    USE SIGNAL ;
    PORT
      LAYER M4 ;
        RECT  155.436 123.504 155.52 123.528 ;
    END
  END o_addr[65]
  PIN o_addr[66]
    DIRECTION OUTPUT ;
    USE SIGNAL ;
    PORT
      LAYER M4 ;
        RECT  155.436 123.936 155.52 123.96 ;
    END
  END o_addr[66]
  PIN o_addr[67]
    DIRECTION OUTPUT ;
    USE SIGNAL ;
    PORT
      LAYER M4 ;
        RECT  155.436 124.368 155.52 124.392 ;
    END
  END o_addr[67]
  PIN o_addr[68]
    DIRECTION OUTPUT ;
    USE SIGNAL ;
    PORT
      LAYER M4 ;
        RECT  155.436 124.8 155.52 124.824 ;
    END
  END o_addr[68]
  PIN o_addr[69]
    DIRECTION OUTPUT ;
    USE SIGNAL ;
    PORT
      LAYER M4 ;
        RECT  155.436 125.232 155.52 125.256 ;
    END
  END o_addr[69]
  PIN o_addr[6]
    DIRECTION OUTPUT ;
    USE SIGNAL ;
    PORT
      LAYER M4 ;
        RECT  155.436 98.016 155.52 98.04 ;
    END
  END o_addr[6]
  PIN o_addr[70]
    DIRECTION OUTPUT ;
    USE SIGNAL ;
    PORT
      LAYER M4 ;
        RECT  155.436 125.664 155.52 125.688 ;
    END
  END o_addr[70]
  PIN o_addr[71]
    DIRECTION OUTPUT ;
    USE SIGNAL ;
    PORT
      LAYER M4 ;
        RECT  155.436 126.096 155.52 126.12 ;
    END
  END o_addr[71]
  PIN o_addr[7]
    DIRECTION OUTPUT ;
    USE SIGNAL ;
    PORT
      LAYER M4 ;
        RECT  155.436 98.448 155.52 98.472 ;
    END
  END o_addr[7]
  PIN o_addr[8]
    DIRECTION OUTPUT ;
    USE SIGNAL ;
    PORT
      LAYER M4 ;
        RECT  155.436 98.88 155.52 98.904 ;
    END
  END o_addr[8]
  PIN o_addr[9]
    DIRECTION OUTPUT ;
    USE SIGNAL ;
    PORT
      LAYER M4 ;
        RECT  155.436 99.312 155.52 99.336 ;
    END
  END o_addr[9]
  PIN o_tag[0]
    DIRECTION OUTPUT ;
    USE SIGNAL ;
    PORT
      LAYER M4 ;
        RECT  155.436 126.528 155.52 126.552 ;
    END
  END o_tag[0]
  PIN o_tag[10]
    DIRECTION OUTPUT ;
    USE SIGNAL ;
    PORT
      LAYER M4 ;
        RECT  155.436 130.848 155.52 130.872 ;
    END
  END o_tag[10]
  PIN o_tag[11]
    DIRECTION OUTPUT ;
    USE SIGNAL ;
    PORT
      LAYER M4 ;
        RECT  155.436 131.28 155.52 131.304 ;
    END
  END o_tag[11]
  PIN o_tag[12]
    DIRECTION OUTPUT ;
    USE SIGNAL ;
    PORT
      LAYER M4 ;
        RECT  155.436 131.712 155.52 131.736 ;
    END
  END o_tag[12]
  PIN o_tag[13]
    DIRECTION OUTPUT ;
    USE SIGNAL ;
    PORT
      LAYER M4 ;
        RECT  155.436 132.144 155.52 132.168 ;
    END
  END o_tag[13]
  PIN o_tag[14]
    DIRECTION OUTPUT ;
    USE SIGNAL ;
    PORT
      LAYER M4 ;
        RECT  155.436 132.576 155.52 132.6 ;
    END
  END o_tag[14]
  PIN o_tag[15]
    DIRECTION OUTPUT ;
    USE SIGNAL ;
    PORT
      LAYER M4 ;
        RECT  155.436 133.008 155.52 133.032 ;
    END
  END o_tag[15]
  PIN o_tag[16]
    DIRECTION OUTPUT ;
    USE SIGNAL ;
    PORT
      LAYER M4 ;
        RECT  155.436 133.44 155.52 133.464 ;
    END
  END o_tag[16]
  PIN o_tag[17]
    DIRECTION OUTPUT ;
    USE SIGNAL ;
    PORT
      LAYER M4 ;
        RECT  155.436 133.872 155.52 133.896 ;
    END
  END o_tag[17]
  PIN o_tag[18]
    DIRECTION OUTPUT ;
    USE SIGNAL ;
    PORT
      LAYER M4 ;
        RECT  155.436 134.304 155.52 134.328 ;
    END
  END o_tag[18]
  PIN o_tag[19]
    DIRECTION OUTPUT ;
    USE SIGNAL ;
    PORT
      LAYER M4 ;
        RECT  155.436 134.736 155.52 134.76 ;
    END
  END o_tag[19]
  PIN o_tag[1]
    DIRECTION OUTPUT ;
    USE SIGNAL ;
    PORT
      LAYER M4 ;
        RECT  155.436 126.96 155.52 126.984 ;
    END
  END o_tag[1]
  PIN o_tag[20]
    DIRECTION OUTPUT ;
    USE SIGNAL ;
    PORT
      LAYER M4 ;
        RECT  155.436 135.168 155.52 135.192 ;
    END
  END o_tag[20]
  PIN o_tag[21]
    DIRECTION OUTPUT ;
    USE SIGNAL ;
    PORT
      LAYER M4 ;
        RECT  155.436 135.6 155.52 135.624 ;
    END
  END o_tag[21]
  PIN o_tag[22]
    DIRECTION OUTPUT ;
    USE SIGNAL ;
    PORT
      LAYER M4 ;
        RECT  155.436 136.032 155.52 136.056 ;
    END
  END o_tag[22]
  PIN o_tag[23]
    DIRECTION OUTPUT ;
    USE SIGNAL ;
    PORT
      LAYER M4 ;
        RECT  155.436 136.464 155.52 136.488 ;
    END
  END o_tag[23]
  PIN o_tag[24]
    DIRECTION OUTPUT ;
    USE SIGNAL ;
    PORT
      LAYER M4 ;
        RECT  155.436 136.896 155.52 136.92 ;
    END
  END o_tag[24]
  PIN o_tag[25]
    DIRECTION OUTPUT ;
    USE SIGNAL ;
    PORT
      LAYER M4 ;
        RECT  155.436 137.328 155.52 137.352 ;
    END
  END o_tag[25]
  PIN o_tag[26]
    DIRECTION OUTPUT ;
    USE SIGNAL ;
    PORT
      LAYER M4 ;
        RECT  155.436 137.76 155.52 137.784 ;
    END
  END o_tag[26]
  PIN o_tag[27]
    DIRECTION OUTPUT ;
    USE SIGNAL ;
    PORT
      LAYER M4 ;
        RECT  155.436 138.192 155.52 138.216 ;
    END
  END o_tag[27]
  PIN o_tag[28]
    DIRECTION OUTPUT ;
    USE SIGNAL ;
    PORT
      LAYER M4 ;
        RECT  155.436 138.624 155.52 138.648 ;
    END
  END o_tag[28]
  PIN o_tag[29]
    DIRECTION OUTPUT ;
    USE SIGNAL ;
    PORT
      LAYER M4 ;
        RECT  155.436 139.056 155.52 139.08 ;
    END
  END o_tag[29]
  PIN o_tag[2]
    DIRECTION OUTPUT ;
    USE SIGNAL ;
    PORT
      LAYER M4 ;
        RECT  155.436 127.392 155.52 127.416 ;
    END
  END o_tag[2]
  PIN o_tag[30]
    DIRECTION OUTPUT ;
    USE SIGNAL ;
    PORT
      LAYER M4 ;
        RECT  155.436 139.488 155.52 139.512 ;
    END
  END o_tag[30]
  PIN o_tag[31]
    DIRECTION OUTPUT ;
    USE SIGNAL ;
    PORT
      LAYER M4 ;
        RECT  155.436 139.92 155.52 139.944 ;
    END
  END o_tag[31]
  PIN o_tag[32]
    DIRECTION OUTPUT ;
    USE SIGNAL ;
    PORT
      LAYER M4 ;
        RECT  155.436 140.352 155.52 140.376 ;
    END
  END o_tag[32]
  PIN o_tag[33]
    DIRECTION OUTPUT ;
    USE SIGNAL ;
    PORT
      LAYER M4 ;
        RECT  155.436 140.784 155.52 140.808 ;
    END
  END o_tag[33]
  PIN o_tag[34]
    DIRECTION OUTPUT ;
    USE SIGNAL ;
    PORT
      LAYER M4 ;
        RECT  155.436 141.216 155.52 141.24 ;
    END
  END o_tag[34]
  PIN o_tag[35]
    DIRECTION OUTPUT ;
    USE SIGNAL ;
    PORT
      LAYER M4 ;
        RECT  155.436 141.648 155.52 141.672 ;
    END
  END o_tag[35]
  PIN o_tag[36]
    DIRECTION OUTPUT ;
    USE SIGNAL ;
    PORT
      LAYER M4 ;
        RECT  155.436 142.08 155.52 142.104 ;
    END
  END o_tag[36]
  PIN o_tag[37]
    DIRECTION OUTPUT ;
    USE SIGNAL ;
    PORT
      LAYER M4 ;
        RECT  155.436 142.512 155.52 142.536 ;
    END
  END o_tag[37]
  PIN o_tag[38]
    DIRECTION OUTPUT ;
    USE SIGNAL ;
    PORT
      LAYER M4 ;
        RECT  155.436 142.944 155.52 142.968 ;
    END
  END o_tag[38]
  PIN o_tag[39]
    DIRECTION OUTPUT ;
    USE SIGNAL ;
    PORT
      LAYER M4 ;
        RECT  155.436 143.376 155.52 143.4 ;
    END
  END o_tag[39]
  PIN o_tag[3]
    DIRECTION OUTPUT ;
    USE SIGNAL ;
    PORT
      LAYER M4 ;
        RECT  155.436 127.824 155.52 127.848 ;
    END
  END o_tag[3]
  PIN o_tag[40]
    DIRECTION OUTPUT ;
    USE SIGNAL ;
    PORT
      LAYER M4 ;
        RECT  155.436 143.808 155.52 143.832 ;
    END
  END o_tag[40]
  PIN o_tag[41]
    DIRECTION OUTPUT ;
    USE SIGNAL ;
    PORT
      LAYER M4 ;
        RECT  155.436 144.24 155.52 144.264 ;
    END
  END o_tag[41]
  PIN o_tag[42]
    DIRECTION OUTPUT ;
    USE SIGNAL ;
    PORT
      LAYER M4 ;
        RECT  155.436 144.672 155.52 144.696 ;
    END
  END o_tag[42]
  PIN o_tag[43]
    DIRECTION OUTPUT ;
    USE SIGNAL ;
    PORT
      LAYER M4 ;
        RECT  155.436 145.104 155.52 145.128 ;
    END
  END o_tag[43]
  PIN o_tag[44]
    DIRECTION OUTPUT ;
    USE SIGNAL ;
    PORT
      LAYER M4 ;
        RECT  155.436 145.536 155.52 145.56 ;
    END
  END o_tag[44]
  PIN o_tag[45]
    DIRECTION OUTPUT ;
    USE SIGNAL ;
    PORT
      LAYER M4 ;
        RECT  155.436 145.968 155.52 145.992 ;
    END
  END o_tag[45]
  PIN o_tag[46]
    DIRECTION OUTPUT ;
    USE SIGNAL ;
    PORT
      LAYER M4 ;
        RECT  155.436 146.4 155.52 146.424 ;
    END
  END o_tag[46]
  PIN o_tag[47]
    DIRECTION OUTPUT ;
    USE SIGNAL ;
    PORT
      LAYER M4 ;
        RECT  155.436 146.832 155.52 146.856 ;
    END
  END o_tag[47]
  PIN o_tag[48]
    DIRECTION OUTPUT ;
    USE SIGNAL ;
    PORT
      LAYER M4 ;
        RECT  155.436 147.264 155.52 147.288 ;
    END
  END o_tag[48]
  PIN o_tag[49]
    DIRECTION OUTPUT ;
    USE SIGNAL ;
    PORT
      LAYER M4 ;
        RECT  155.436 147.696 155.52 147.72 ;
    END
  END o_tag[49]
  PIN o_tag[4]
    DIRECTION OUTPUT ;
    USE SIGNAL ;
    PORT
      LAYER M4 ;
        RECT  155.436 128.256 155.52 128.28 ;
    END
  END o_tag[4]
  PIN o_tag[50]
    DIRECTION OUTPUT ;
    USE SIGNAL ;
    PORT
      LAYER M4 ;
        RECT  155.436 148.128 155.52 148.152 ;
    END
  END o_tag[50]
  PIN o_tag[51]
    DIRECTION OUTPUT ;
    USE SIGNAL ;
    PORT
      LAYER M4 ;
        RECT  155.436 148.56 155.52 148.584 ;
    END
  END o_tag[51]
  PIN o_tag[52]
    DIRECTION OUTPUT ;
    USE SIGNAL ;
    PORT
      LAYER M4 ;
        RECT  155.436 148.992 155.52 149.016 ;
    END
  END o_tag[52]
  PIN o_tag[53]
    DIRECTION OUTPUT ;
    USE SIGNAL ;
    PORT
      LAYER M4 ;
        RECT  155.436 149.424 155.52 149.448 ;
    END
  END o_tag[53]
  PIN o_tag[54]
    DIRECTION OUTPUT ;
    USE SIGNAL ;
    PORT
      LAYER M4 ;
        RECT  155.436 149.856 155.52 149.88 ;
    END
  END o_tag[54]
  PIN o_tag[55]
    DIRECTION OUTPUT ;
    USE SIGNAL ;
    PORT
      LAYER M4 ;
        RECT  155.436 150.288 155.52 150.312 ;
    END
  END o_tag[55]
  PIN o_tag[56]
    DIRECTION OUTPUT ;
    USE SIGNAL ;
    PORT
      LAYER M4 ;
        RECT  155.436 150.72 155.52 150.744 ;
    END
  END o_tag[56]
  PIN o_tag[57]
    DIRECTION OUTPUT ;
    USE SIGNAL ;
    PORT
      LAYER M4 ;
        RECT  155.436 151.152 155.52 151.176 ;
    END
  END o_tag[57]
  PIN o_tag[58]
    DIRECTION OUTPUT ;
    USE SIGNAL ;
    PORT
      LAYER M4 ;
        RECT  155.436 151.584 155.52 151.608 ;
    END
  END o_tag[58]
  PIN o_tag[59]
    DIRECTION OUTPUT ;
    USE SIGNAL ;
    PORT
      LAYER M4 ;
        RECT  155.436 152.016 155.52 152.04 ;
    END
  END o_tag[59]
  PIN o_tag[5]
    DIRECTION OUTPUT ;
    USE SIGNAL ;
    PORT
      LAYER M4 ;
        RECT  155.436 128.688 155.52 128.712 ;
    END
  END o_tag[5]
  PIN o_tag[60]
    DIRECTION OUTPUT ;
    USE SIGNAL ;
    PORT
      LAYER M4 ;
        RECT  155.436 152.448 155.52 152.472 ;
    END
  END o_tag[60]
  PIN o_tag[61]
    DIRECTION OUTPUT ;
    USE SIGNAL ;
    PORT
      LAYER M4 ;
        RECT  155.436 152.88 155.52 152.904 ;
    END
  END o_tag[61]
  PIN o_tag[62]
    DIRECTION OUTPUT ;
    USE SIGNAL ;
    PORT
      LAYER M4 ;
        RECT  155.436 153.312 155.52 153.336 ;
    END
  END o_tag[62]
  PIN o_tag[63]
    DIRECTION OUTPUT ;
    USE SIGNAL ;
    PORT
      LAYER M4 ;
        RECT  155.436 153.744 155.52 153.768 ;
    END
  END o_tag[63]
  PIN o_tag[6]
    DIRECTION OUTPUT ;
    USE SIGNAL ;
    PORT
      LAYER M4 ;
        RECT  155.436 129.12 155.52 129.144 ;
    END
  END o_tag[6]
  PIN o_tag[7]
    DIRECTION OUTPUT ;
    USE SIGNAL ;
    PORT
      LAYER M4 ;
        RECT  155.436 129.552 155.52 129.576 ;
    END
  END o_tag[7]
  PIN o_tag[8]
    DIRECTION OUTPUT ;
    USE SIGNAL ;
    PORT
      LAYER M4 ;
        RECT  155.436 129.984 155.52 130.008 ;
    END
  END o_tag[8]
  PIN o_tag[9]
    DIRECTION OUTPUT ;
    USE SIGNAL ;
    PORT
      LAYER M4 ;
        RECT  155.436 130.416 155.52 130.44 ;
    END
  END o_tag[9]
  PIN o_v[0]
    DIRECTION OUTPUT ;
    USE SIGNAL ;
    PORT
      LAYER M4 ;
        RECT  155.436 91.968 155.52 91.992 ;
    END
  END o_v[0]
  PIN o_v[1]
    DIRECTION OUTPUT ;
    USE SIGNAL ;
    PORT
      LAYER M4 ;
        RECT  155.436 92.4 155.52 92.424 ;
    END
  END o_v[1]
  PIN o_v[2]
    DIRECTION OUTPUT ;
    USE SIGNAL ;
    PORT
      LAYER M4 ;
        RECT  155.436 92.832 155.52 92.856 ;
    END
  END o_v[2]
  PIN o_v[3]
    DIRECTION OUTPUT ;
    USE SIGNAL ;
    PORT
      LAYER M4 ;
        RECT  155.436 93.264 155.52 93.288 ;
    END
  END o_v[3]
  PIN o_v[4]
    DIRECTION OUTPUT ;
    USE SIGNAL ;
    PORT
      LAYER M4 ;
        RECT  155.436 93.696 155.52 93.72 ;
    END
  END o_v[4]
  PIN o_v[5]
    DIRECTION OUTPUT ;
    USE SIGNAL ;
    PORT
      LAYER M4 ;
        RECT  155.436 94.128 155.52 94.152 ;
    END
  END o_v[5]
  PIN o_v[6]
    DIRECTION OUTPUT ;
    USE SIGNAL ;
    PORT
      LAYER M4 ;
        RECT  155.436 94.56 155.52 94.584 ;
    END
  END o_v[6]
  PIN o_v[7]
    DIRECTION OUTPUT ;
    USE SIGNAL ;
    PORT
      LAYER M4 ;
        RECT  155.436 94.992 155.52 95.016 ;
    END
  END o_v[7]
  PIN rst_n
    DIRECTION INPUT ;
    USE SIGNAL ;
    PORT
      LAYER M5 ;
        RECT  77.952 246.156 77.976 246.24 ;
    END
  END rst_n
  PIN VDD
    DIRECTION INOUT ;
    USE POWER ;
    PORT
      LAYER M5 ;
        RECT  148.392 2.151 148.512 244.089 ;
        RECT  142.992 2.151 143.112 244.089 ;
        RECT  137.592 2.151 137.712 244.089 ;
        RECT  132.192 2.151 132.312 244.089 ;
        RECT  126.792 2.151 126.912 244.089 ;
        RECT  121.392 2.151 121.512 244.089 ;
        RECT  115.992 2.151 116.112 244.089 ;
        RECT  110.592 2.151 110.712 244.089 ;
        RECT  105.192 2.151 105.312 244.089 ;
        RECT  99.792 2.151 99.912 244.089 ;
        RECT  94.392 2.151 94.512 244.089 ;
        RECT  88.992 2.151 89.112 244.089 ;
        RECT  83.592 2.151 83.712 244.089 ;
        RECT  78.192 2.151 78.312 244.089 ;
        RECT  72.792 2.151 72.912 244.089 ;
        RECT  67.392 2.151 67.512 244.089 ;
        RECT  61.992 2.151 62.112 244.089 ;
        RECT  56.592 2.151 56.712 244.089 ;
        RECT  51.192 2.151 51.312 244.089 ;
        RECT  45.792 2.151 45.912 244.089 ;
        RECT  40.392 2.151 40.512 244.089 ;
        RECT  34.992 2.151 35.112 244.089 ;
        RECT  29.592 2.151 29.712 244.089 ;
        RECT  24.192 2.151 24.312 244.089 ;
        RECT  18.792 2.151 18.912 244.089 ;
        RECT  13.392 2.151 13.512 244.089 ;
        RECT  7.992 2.151 8.112 244.089 ;
        RECT  2.592 2.151 2.712 244.089 ;
    END
  END VDD
  PIN VSS
    DIRECTION INOUT ;
    USE GROUND ;
    PORT
      LAYER M5 ;
        RECT  148.2 2.137 148.32 244.103 ;
        RECT  142.8 2.137 142.92 244.103 ;
        RECT  137.4 2.137 137.52 244.103 ;
        RECT  132 2.137 132.12 244.103 ;
        RECT  126.6 2.137 126.72 244.103 ;
        RECT  121.2 2.137 121.32 244.103 ;
        RECT  115.8 2.137 115.92 244.103 ;
        RECT  110.4 2.137 110.52 244.103 ;
        RECT  105 2.137 105.12 244.103 ;
        RECT  99.6 2.137 99.72 244.103 ;
        RECT  94.2 2.137 94.32 244.103 ;
        RECT  88.8 2.137 88.92 244.103 ;
        RECT  83.4 2.137 83.52 244.103 ;
        RECT  78 2.137 78.12 244.103 ;
        RECT  72.6 2.137 72.72 244.103 ;
        RECT  67.2 2.137 67.32 244.103 ;
        RECT  61.8 2.137 61.92 244.103 ;
        RECT  56.4 2.137 56.52 244.103 ;
        RECT  51 2.137 51.12 244.103 ;
        RECT  45.6 2.137 45.72 244.103 ;
        RECT  40.2 2.137 40.32 244.103 ;
        RECT  34.8 2.137 34.92 244.103 ;
        RECT  29.4 2.137 29.52 244.103 ;
        RECT  24 2.137 24.12 244.103 ;
        RECT  18.6 2.137 18.72 244.103 ;
        RECT  13.2 2.137 13.32 244.103 ;
        RECT  7.8 2.137 7.92 244.103 ;
        RECT  2.4 2.137 2.52 244.103 ;
    END
  END VSS
  # OT_OBS_CLOSED layer=M5 d_um=1.536 added=100
  OBS
    LAYER RVTN ;
     RECT  2.16 2.16 153.36 2.295 ;
     RECT  2.16 2.565 153.36 2.835 ;
     RECT  2.16 3.105 153.36 3.375 ;
     RECT  2.16 3.645 153.36 3.915 ;
     RECT  2.16 4.185 153.36 4.455 ;
     RECT  2.16 4.725 153.36 4.995 ;
     RECT  2.16 5.265 153.36 5.535 ;
     RECT  2.16 5.805 153.36 6.075 ;
     RECT  2.16 6.345 153.36 6.615 ;
     RECT  2.16 6.885 153.36 7.155 ;
     RECT  2.16 7.425 153.36 7.695 ;
     RECT  2.16 7.965 153.36 8.235 ;
     RECT  2.16 8.505 153.36 8.775 ;
     RECT  2.16 9.045 153.36 9.315 ;
     RECT  2.16 9.585 153.36 9.855 ;
     RECT  2.16 10.125 153.36 10.395 ;
     RECT  2.16 10.665 153.36 10.935 ;
     RECT  2.16 11.205 153.36 11.475 ;
     RECT  2.16 11.745 153.36 12.015 ;
     RECT  2.16 12.285 153.36 12.555 ;
     RECT  2.16 12.825 153.36 13.095 ;
     RECT  2.16 13.365 153.36 13.635 ;
     RECT  2.16 13.905 153.36 14.175 ;
     RECT  2.16 14.445 153.36 14.715 ;
     RECT  2.16 14.985 153.36 15.255 ;
     RECT  2.16 15.525 153.36 15.795 ;
     RECT  2.16 16.065 153.36 16.335 ;
     RECT  2.16 16.605 153.36 16.875 ;
     RECT  2.16 17.145 153.36 17.415 ;
     RECT  2.16 17.685 153.36 17.955 ;
     RECT  2.16 18.225 153.36 18.495 ;
     RECT  2.16 18.765 153.36 19.035 ;
     RECT  2.16 19.305 153.36 19.575 ;
     RECT  2.16 19.845 153.36 20.115 ;
     RECT  2.16 20.385 153.36 20.655 ;
     RECT  2.16 20.925 153.36 21.195 ;
     RECT  2.16 21.465 153.36 21.735 ;
     RECT  2.16 22.005 153.36 22.275 ;
     RECT  2.16 22.545 153.36 22.815 ;
     RECT  2.16 23.085 153.36 23.355 ;
     RECT  2.16 23.625 153.36 23.895 ;
     RECT  2.16 24.165 153.36 24.435 ;
     RECT  2.16 24.705 153.36 24.975 ;
     RECT  2.16 25.245 153.36 25.515 ;
     RECT  2.16 25.785 153.36 26.055 ;
     RECT  2.16 26.325 153.36 26.595 ;
     RECT  2.16 26.865 153.36 27.135 ;
     RECT  2.16 27.405 153.36 27.675 ;
     RECT  2.16 27.945 153.36 28.215 ;
     RECT  2.16 28.485 153.36 28.755 ;
     RECT  2.16 29.025 153.36 29.295 ;
     RECT  2.16 29.565 153.36 29.835 ;
     RECT  2.16 30.105 153.36 30.375 ;
     RECT  2.16 30.645 153.36 30.915 ;
     RECT  2.16 31.185 153.36 31.455 ;
     RECT  2.16 31.725 153.36 31.995 ;
     RECT  2.16 32.265 153.36 32.535 ;
     RECT  2.16 32.805 153.36 33.075 ;
     RECT  2.16 33.345 153.36 33.615 ;
     RECT  2.16 33.885 153.36 34.155 ;
     RECT  2.16 34.425 153.36 34.695 ;
     RECT  2.16 34.965 153.36 35.235 ;
     RECT  2.16 35.505 153.36 35.775 ;
     RECT  2.16 36.045 153.36 36.315 ;
     RECT  2.16 36.585 153.36 36.855 ;
     RECT  2.16 37.125 153.36 37.395 ;
     RECT  2.16 37.665 153.36 37.935 ;
     RECT  2.16 38.205 153.36 38.475 ;
     RECT  2.16 38.745 153.36 39.015 ;
     RECT  2.16 39.285 153.36 39.555 ;
     RECT  2.16 39.825 153.36 40.095 ;
     RECT  2.16 40.365 153.36 40.635 ;
     RECT  2.16 40.905 153.36 41.175 ;
     RECT  2.16 41.445 153.36 41.715 ;
     RECT  2.16 41.985 153.36 42.255 ;
     RECT  2.16 42.525 153.36 42.795 ;
     RECT  2.16 43.065 153.36 43.335 ;
     RECT  2.16 43.605 153.36 43.875 ;
     RECT  2.16 44.145 153.36 44.415 ;
     RECT  2.16 44.685 153.36 44.955 ;
     RECT  2.16 45.225 153.36 45.495 ;
     RECT  2.16 45.765 153.36 46.035 ;
     RECT  2.16 46.305 153.36 46.575 ;
     RECT  2.16 46.845 153.36 47.115 ;
     RECT  2.16 47.385 153.36 47.655 ;
     RECT  2.16 47.925 153.36 48.195 ;
     RECT  2.16 48.465 153.36 48.735 ;
     RECT  2.16 49.005 153.36 49.275 ;
     RECT  2.16 49.545 153.36 49.815 ;
     RECT  2.16 50.085 153.36 50.355 ;
     RECT  2.16 50.625 153.36 50.895 ;
     RECT  2.16 51.165 153.36 51.435 ;
     RECT  2.16 51.705 153.36 51.975 ;
     RECT  2.16 52.245 153.36 52.515 ;
     RECT  2.16 52.785 153.36 53.055 ;
     RECT  2.16 53.325 153.36 53.595 ;
     RECT  2.16 53.865 153.36 54.135 ;
     RECT  2.16 54.405 153.36 54.675 ;
     RECT  2.16 54.945 153.36 55.215 ;
     RECT  2.16 55.485 153.36 55.755 ;
     RECT  2.16 56.025 153.36 56.295 ;
     RECT  2.16 56.565 153.36 56.835 ;
     RECT  2.16 57.105 153.36 57.375 ;
     RECT  2.16 57.645 153.36 57.915 ;
     RECT  2.16 58.185 153.36 58.455 ;
     RECT  2.16 58.725 153.36 58.995 ;
     RECT  2.16 59.265 153.36 59.535 ;
     RECT  2.16 59.805 153.36 60.075 ;
     RECT  2.16 60.345 153.36 60.615 ;
     RECT  2.16 60.885 153.36 61.155 ;
     RECT  2.16 61.425 153.36 61.695 ;
     RECT  2.16 61.965 153.36 62.235 ;
     RECT  2.16 62.505 153.36 62.775 ;
     RECT  2.16 63.045 153.36 63.315 ;
     RECT  2.16 63.585 153.36 63.855 ;
     RECT  2.16 64.125 153.36 64.395 ;
     RECT  2.16 64.665 153.36 64.935 ;
     RECT  2.16 65.205 153.36 65.475 ;
     RECT  2.16 65.745 153.36 66.015 ;
     RECT  2.16 66.285 153.36 66.555 ;
     RECT  2.16 66.825 153.36 67.095 ;
     RECT  2.16 67.365 153.36 67.635 ;
     RECT  2.16 67.905 153.36 68.175 ;
     RECT  2.16 68.445 153.36 68.715 ;
     RECT  2.16 68.985 153.36 69.255 ;
     RECT  2.16 69.525 153.36 69.795 ;
     RECT  2.16 70.065 153.36 70.335 ;
     RECT  2.16 70.605 153.36 70.875 ;
     RECT  2.16 71.145 153.36 71.415 ;
     RECT  2.16 71.685 153.36 71.955 ;
     RECT  2.16 72.225 153.36 72.495 ;
     RECT  2.16 72.765 153.36 73.035 ;
     RECT  2.16 73.305 153.36 73.575 ;
     RECT  2.16 73.845 153.36 74.115 ;
     RECT  2.16 74.385 153.36 74.655 ;
     RECT  2.16 74.925 153.36 75.195 ;
     RECT  2.16 75.465 153.36 75.735 ;
     RECT  2.16 76.005 153.36 76.275 ;
     RECT  2.16 76.545 153.36 76.815 ;
     RECT  2.16 77.085 153.36 77.355 ;
     RECT  2.16 77.625 153.36 77.895 ;
     RECT  2.16 78.165 153.36 78.435 ;
     RECT  2.16 78.705 153.36 78.975 ;
     RECT  2.16 79.245 153.36 79.515 ;
     RECT  2.16 79.785 153.36 80.055 ;
     RECT  2.16 80.325 153.36 80.595 ;
     RECT  2.16 80.865 153.36 81.135 ;
     RECT  2.16 81.405 153.36 81.675 ;
     RECT  2.16 81.945 153.36 82.215 ;
     RECT  2.16 82.485 153.36 82.755 ;
     RECT  2.16 83.025 153.36 83.295 ;
     RECT  2.16 83.565 153.36 83.835 ;
     RECT  2.16 84.105 153.36 84.375 ;
     RECT  2.16 84.645 153.36 84.915 ;
     RECT  2.16 85.185 153.36 85.455 ;
     RECT  2.16 85.725 153.36 85.995 ;
     RECT  2.16 86.265 153.36 86.535 ;
     RECT  2.16 86.805 153.36 87.075 ;
     RECT  2.16 87.345 153.36 87.615 ;
     RECT  2.16 87.885 153.36 88.155 ;
     RECT  2.16 88.425 153.36 88.695 ;
     RECT  2.16 88.965 153.36 89.235 ;
     RECT  2.16 89.505 153.36 89.775 ;
     RECT  2.16 90.045 153.36 90.315 ;
     RECT  2.16 90.585 153.36 90.855 ;
     RECT  2.16 91.125 153.36 91.395 ;
     RECT  2.16 91.665 153.36 91.935 ;
     RECT  2.16 92.205 153.36 92.475 ;
     RECT  2.16 92.745 153.36 93.015 ;
     RECT  2.16 93.285 153.36 93.555 ;
     RECT  2.16 93.825 153.36 94.095 ;
     RECT  2.16 94.365 153.36 94.635 ;
     RECT  2.16 94.905 153.36 95.175 ;
     RECT  2.16 95.445 153.36 95.715 ;
     RECT  2.16 95.985 153.36 96.255 ;
     RECT  2.16 96.525 153.36 96.795 ;
     RECT  2.16 97.065 153.36 97.335 ;
     RECT  2.16 97.605 153.36 97.875 ;
     RECT  2.16 98.145 153.36 98.415 ;
     RECT  2.16 98.685 153.36 98.955 ;
     RECT  2.16 99.225 153.36 99.495 ;
     RECT  2.16 99.765 153.36 100.035 ;
     RECT  2.16 100.305 153.36 100.575 ;
     RECT  2.16 100.845 153.36 101.115 ;
     RECT  2.16 101.385 153.36 101.655 ;
     RECT  2.16 101.925 153.36 102.195 ;
     RECT  2.16 102.465 153.36 102.735 ;
     RECT  2.16 103.005 153.36 103.275 ;
     RECT  2.16 103.545 153.36 103.815 ;
     RECT  2.16 104.085 153.36 104.355 ;
     RECT  2.16 104.625 153.36 104.895 ;
     RECT  2.16 105.165 153.36 105.435 ;
     RECT  2.16 105.705 153.36 105.975 ;
     RECT  2.16 106.245 153.36 106.515 ;
     RECT  2.16 106.785 153.36 107.055 ;
     RECT  2.16 107.325 153.36 107.595 ;
     RECT  2.16 107.865 153.36 108.135 ;
     RECT  2.16 108.405 153.36 108.675 ;
     RECT  2.16 108.945 153.36 109.215 ;
     RECT  2.16 109.485 153.36 109.755 ;
     RECT  2.16 110.025 153.36 110.295 ;
     RECT  2.16 110.565 153.36 110.835 ;
     RECT  2.16 111.105 153.36 111.375 ;
     RECT  2.16 111.645 153.36 111.915 ;
     RECT  2.16 112.185 153.36 112.455 ;
     RECT  2.16 112.725 153.36 112.995 ;
     RECT  2.16 113.265 153.36 113.535 ;
     RECT  2.16 113.805 153.36 114.075 ;
     RECT  2.16 114.345 153.36 114.615 ;
     RECT  2.16 114.885 153.36 115.155 ;
     RECT  2.16 115.425 153.36 115.695 ;
     RECT  2.16 115.965 153.36 116.235 ;
     RECT  2.16 116.505 153.36 116.775 ;
     RECT  2.16 117.045 153.36 117.315 ;
     RECT  2.16 117.585 153.36 117.855 ;
     RECT  2.16 118.125 153.36 118.395 ;
     RECT  2.16 118.665 153.36 118.935 ;
     RECT  2.16 119.205 153.36 119.475 ;
     RECT  2.16 119.745 153.36 120.015 ;
     RECT  2.16 120.285 153.36 120.555 ;
     RECT  2.16 120.825 153.36 121.095 ;
     RECT  2.16 121.365 153.36 121.635 ;
     RECT  2.16 121.905 153.36 122.175 ;
     RECT  2.16 122.445 153.36 122.715 ;
     RECT  2.16 122.985 153.36 123.255 ;
     RECT  2.16 123.525 153.36 123.795 ;
     RECT  2.16 124.065 153.36 124.335 ;
     RECT  2.16 124.605 153.36 124.875 ;
     RECT  2.16 125.145 153.36 125.415 ;
     RECT  2.16 125.685 153.36 125.955 ;
     RECT  2.16 126.225 153.36 126.495 ;
     RECT  2.16 126.765 153.36 127.035 ;
     RECT  2.16 127.305 153.36 127.575 ;
     RECT  2.16 127.845 153.36 128.115 ;
     RECT  2.16 128.385 153.36 128.655 ;
     RECT  2.16 128.925 153.36 129.195 ;
     RECT  2.16 129.465 153.36 129.735 ;
     RECT  2.16 130.005 153.36 130.275 ;
     RECT  2.16 130.545 153.36 130.815 ;
     RECT  2.16 131.085 153.36 131.355 ;
     RECT  2.16 131.625 153.36 131.895 ;
     RECT  2.16 132.165 153.36 132.435 ;
     RECT  2.16 132.705 153.36 132.975 ;
     RECT  2.16 133.245 153.36 133.515 ;
     RECT  2.16 133.785 153.36 134.055 ;
     RECT  2.16 134.325 153.36 134.595 ;
     RECT  2.16 134.865 153.36 135.135 ;
     RECT  2.16 135.405 153.36 135.675 ;
     RECT  2.16 135.945 153.36 136.215 ;
     RECT  2.16 136.485 153.36 136.755 ;
     RECT  2.16 137.025 153.36 137.295 ;
     RECT  2.16 137.565 153.36 137.835 ;
     RECT  2.16 138.105 153.36 138.375 ;
     RECT  2.16 138.645 153.36 138.915 ;
     RECT  2.16 139.185 153.36 139.455 ;
     RECT  2.16 139.725 153.36 139.995 ;
     RECT  2.16 140.265 153.36 140.535 ;
     RECT  2.16 140.805 153.36 141.075 ;
     RECT  2.16 141.345 153.36 141.615 ;
     RECT  2.16 141.885 153.36 142.155 ;
     RECT  2.16 142.425 153.36 142.695 ;
     RECT  2.16 142.965 153.36 143.235 ;
     RECT  2.16 143.505 153.36 143.775 ;
     RECT  2.16 144.045 153.36 144.315 ;
     RECT  2.16 144.585 153.36 144.855 ;
     RECT  2.16 145.125 153.36 145.395 ;
     RECT  2.16 145.665 153.36 145.935 ;
     RECT  2.16 146.205 153.36 146.475 ;
     RECT  2.16 146.745 153.36 147.015 ;
     RECT  2.16 147.285 153.36 147.555 ;
     RECT  2.16 147.825 153.36 148.095 ;
     RECT  2.16 148.365 153.36 148.635 ;
     RECT  2.16 148.905 153.36 149.175 ;
     RECT  2.16 149.445 153.36 149.715 ;
     RECT  2.16 149.985 153.36 150.255 ;
     RECT  2.16 150.525 153.36 150.795 ;
     RECT  2.16 151.065 153.36 151.335 ;
     RECT  2.16 151.605 153.36 151.875 ;
     RECT  2.16 152.145 153.36 152.415 ;
     RECT  2.16 152.685 153.36 152.955 ;
     RECT  2.16 153.225 153.36 153.495 ;
     RECT  2.16 153.765 153.36 154.035 ;
     RECT  2.16 154.305 153.36 154.575 ;
     RECT  2.16 154.845 153.36 155.115 ;
     RECT  2.16 155.385 153.36 155.655 ;
     RECT  2.16 155.925 153.36 156.195 ;
     RECT  2.16 156.465 153.36 156.735 ;
     RECT  2.16 157.005 153.36 157.275 ;
     RECT  2.16 157.545 153.36 157.815 ;
     RECT  2.16 158.085 153.36 158.355 ;
     RECT  2.16 158.625 153.36 158.895 ;
     RECT  2.16 159.165 153.36 159.435 ;
     RECT  2.16 159.705 153.36 159.975 ;
     RECT  2.16 160.245 153.36 160.515 ;
     RECT  2.16 160.785 153.36 161.055 ;
     RECT  2.16 161.325 153.36 161.595 ;
     RECT  2.16 161.865 153.36 162.135 ;
     RECT  2.16 162.405 153.36 162.675 ;
     RECT  2.16 162.945 153.36 163.215 ;
     RECT  2.16 163.485 153.36 163.755 ;
     RECT  2.16 164.025 153.36 164.295 ;
     RECT  2.16 164.565 153.36 164.835 ;
     RECT  2.16 165.105 153.36 165.375 ;
     RECT  2.16 165.645 153.36 165.915 ;
     RECT  2.16 166.185 153.36 166.455 ;
     RECT  2.16 166.725 153.36 166.995 ;
     RECT  2.16 167.265 153.36 167.535 ;
     RECT  2.16 167.805 153.36 168.075 ;
     RECT  2.16 168.345 153.36 168.615 ;
     RECT  2.16 168.885 153.36 169.155 ;
     RECT  2.16 169.425 153.36 169.695 ;
     RECT  2.16 169.965 153.36 170.235 ;
     RECT  2.16 170.505 153.36 170.775 ;
     RECT  2.16 171.045 153.36 171.315 ;
     RECT  2.16 171.585 153.36 171.855 ;
     RECT  2.16 172.125 153.36 172.395 ;
     RECT  2.16 172.665 153.36 172.935 ;
     RECT  2.16 173.205 153.36 173.475 ;
     RECT  2.16 173.745 153.36 174.015 ;
     RECT  2.16 174.285 153.36 174.555 ;
     RECT  2.16 174.825 153.36 175.095 ;
     RECT  2.16 175.365 153.36 175.635 ;
     RECT  2.16 175.905 153.36 176.175 ;
     RECT  2.16 176.445 153.36 176.715 ;
     RECT  2.16 176.985 153.36 177.255 ;
     RECT  2.16 177.525 153.36 177.795 ;
     RECT  2.16 178.065 153.36 178.335 ;
     RECT  2.16 178.605 153.36 178.875 ;
     RECT  2.16 179.145 153.36 179.415 ;
     RECT  2.16 179.685 153.36 179.955 ;
     RECT  2.16 180.225 153.36 180.495 ;
     RECT  2.16 180.765 153.36 181.035 ;
     RECT  2.16 181.305 153.36 181.575 ;
     RECT  2.16 181.845 153.36 182.115 ;
     RECT  2.16 182.385 153.36 182.655 ;
     RECT  2.16 182.925 153.36 183.195 ;
     RECT  2.16 183.465 153.36 183.735 ;
     RECT  2.16 184.005 153.36 184.275 ;
     RECT  2.16 184.545 153.36 184.815 ;
     RECT  2.16 185.085 153.36 185.355 ;
     RECT  2.16 185.625 153.36 185.895 ;
     RECT  2.16 186.165 153.36 186.435 ;
     RECT  2.16 186.705 153.36 186.975 ;
     RECT  2.16 187.245 153.36 187.515 ;
     RECT  2.16 187.785 153.36 188.055 ;
     RECT  2.16 188.325 153.36 188.595 ;
     RECT  2.16 188.865 153.36 189.135 ;
     RECT  2.16 189.405 153.36 189.675 ;
     RECT  2.16 189.945 153.36 190.215 ;
     RECT  2.16 190.485 153.36 190.755 ;
     RECT  2.16 191.025 153.36 191.295 ;
     RECT  2.16 191.565 153.36 191.835 ;
     RECT  2.16 192.105 153.36 192.375 ;
     RECT  2.16 192.645 153.36 192.915 ;
     RECT  2.16 193.185 153.36 193.455 ;
     RECT  2.16 193.725 153.36 193.995 ;
     RECT  2.16 194.265 153.36 194.535 ;
     RECT  2.16 194.805 153.36 195.075 ;
     RECT  2.16 195.345 153.36 195.615 ;
     RECT  2.16 195.885 153.36 196.155 ;
     RECT  2.16 196.425 153.36 196.695 ;
     RECT  2.16 196.965 153.36 197.235 ;
     RECT  2.16 197.505 153.36 197.775 ;
     RECT  2.16 198.045 153.36 198.315 ;
     RECT  2.16 198.585 153.36 198.855 ;
     RECT  2.16 199.125 153.36 199.395 ;
     RECT  2.16 199.665 153.36 199.935 ;
     RECT  2.16 200.205 153.36 200.475 ;
     RECT  2.16 200.745 153.36 201.015 ;
     RECT  2.16 201.285 153.36 201.555 ;
     RECT  2.16 201.825 153.36 202.095 ;
     RECT  2.16 202.365 153.36 202.635 ;
     RECT  2.16 202.905 153.36 203.175 ;
     RECT  2.16 203.445 153.36 203.715 ;
     RECT  2.16 203.985 153.36 204.255 ;
     RECT  2.16 204.525 153.36 204.795 ;
     RECT  2.16 205.065 153.36 205.335 ;
     RECT  2.16 205.605 153.36 205.875 ;
     RECT  2.16 206.145 153.36 206.415 ;
     RECT  2.16 206.685 153.36 206.955 ;
     RECT  2.16 207.225 153.36 207.495 ;
     RECT  2.16 207.765 153.36 208.035 ;
     RECT  2.16 208.305 153.36 208.575 ;
     RECT  2.16 208.845 153.36 209.115 ;
     RECT  2.16 209.385 153.36 209.655 ;
     RECT  2.16 209.925 153.36 210.195 ;
     RECT  2.16 210.465 153.36 210.735 ;
     RECT  2.16 211.005 153.36 211.275 ;
     RECT  2.16 211.545 153.36 211.815 ;
     RECT  2.16 212.085 153.36 212.355 ;
     RECT  2.16 212.625 153.36 212.895 ;
     RECT  2.16 213.165 153.36 213.435 ;
     RECT  2.16 213.705 153.36 213.975 ;
     RECT  2.16 214.245 153.36 214.515 ;
     RECT  2.16 214.785 153.36 215.055 ;
     RECT  2.16 215.325 153.36 215.595 ;
     RECT  2.16 215.865 153.36 216.135 ;
     RECT  2.16 216.405 153.36 216.675 ;
     RECT  2.16 216.945 153.36 217.215 ;
     RECT  2.16 217.485 153.36 217.755 ;
     RECT  2.16 218.025 153.36 218.295 ;
     RECT  2.16 218.565 153.36 218.835 ;
     RECT  2.16 219.105 153.36 219.375 ;
     RECT  2.16 219.645 153.36 219.915 ;
     RECT  2.16 220.185 153.36 220.455 ;
     RECT  2.16 220.725 153.36 220.995 ;
     RECT  2.16 221.265 153.36 221.535 ;
     RECT  2.16 221.805 153.36 222.075 ;
     RECT  2.16 222.345 153.36 222.615 ;
     RECT  2.16 222.885 153.36 223.155 ;
     RECT  2.16 223.425 153.36 223.695 ;
     RECT  2.16 223.965 153.36 224.235 ;
     RECT  2.16 224.505 153.36 224.775 ;
     RECT  2.16 225.045 153.36 225.315 ;
     RECT  2.16 225.585 153.36 225.855 ;
     RECT  2.16 226.125 153.36 226.395 ;
     RECT  2.16 226.665 153.36 226.935 ;
     RECT  2.16 227.205 153.36 227.475 ;
     RECT  2.16 227.745 153.36 228.015 ;
     RECT  2.16 228.285 153.36 228.555 ;
     RECT  2.16 228.825 153.36 229.095 ;
     RECT  2.16 229.365 153.36 229.635 ;
     RECT  2.16 229.905 153.36 230.175 ;
     RECT  2.16 230.445 153.36 230.715 ;
     RECT  2.16 230.985 153.36 231.255 ;
     RECT  2.16 231.525 153.36 231.795 ;
     RECT  2.16 232.065 153.36 232.335 ;
     RECT  2.16 232.605 153.36 232.875 ;
     RECT  2.16 233.145 153.36 233.415 ;
     RECT  2.16 233.685 153.36 233.955 ;
     RECT  2.16 234.225 153.36 234.495 ;
     RECT  2.16 234.765 153.36 235.035 ;
     RECT  2.16 235.305 153.36 235.575 ;
     RECT  2.16 235.845 153.36 236.115 ;
     RECT  2.16 236.385 153.36 236.655 ;
     RECT  2.16 236.925 153.36 237.195 ;
     RECT  2.16 237.465 153.36 237.735 ;
     RECT  2.16 238.005 153.36 238.275 ;
     RECT  2.16 238.545 153.36 238.815 ;
     RECT  2.16 239.085 153.36 239.355 ;
     RECT  2.16 239.625 153.36 239.895 ;
     RECT  2.16 240.165 153.36 240.435 ;
     RECT  2.16 240.705 153.36 240.975 ;
     RECT  2.16 241.245 153.36 241.515 ;
     RECT  2.16 241.785 153.36 242.055 ;
     RECT  2.16 242.325 153.36 242.595 ;
     RECT  2.16 242.865 153.36 243.135 ;
     RECT  2.16 243.405 153.36 243.675 ;
     RECT  2.16 243.945 153.36 244.08 ;
    LAYER RVTP ;
     RECT  2.16 2.295 153.36 2.565 ;
     RECT  2.16 2.835 153.36 3.105 ;
     RECT  2.16 3.375 153.36 3.645 ;
     RECT  2.16 3.915 153.36 4.185 ;
     RECT  2.16 4.455 153.36 4.725 ;
     RECT  2.16 4.995 153.36 5.265 ;
     RECT  2.16 5.535 153.36 5.805 ;
     RECT  2.16 6.075 153.36 6.345 ;
     RECT  2.16 6.615 153.36 6.885 ;
     RECT  2.16 7.155 153.36 7.425 ;
     RECT  2.16 7.695 153.36 7.965 ;
     RECT  2.16 8.235 153.36 8.505 ;
     RECT  2.16 8.775 153.36 9.045 ;
     RECT  2.16 9.315 153.36 9.585 ;
     RECT  2.16 9.855 153.36 10.125 ;
     RECT  2.16 10.395 153.36 10.665 ;
     RECT  2.16 10.935 153.36 11.205 ;
     RECT  2.16 11.475 153.36 11.745 ;
     RECT  2.16 12.015 153.36 12.285 ;
     RECT  2.16 12.555 153.36 12.825 ;
     RECT  2.16 13.095 153.36 13.365 ;
     RECT  2.16 13.635 153.36 13.905 ;
     RECT  2.16 14.175 153.36 14.445 ;
     RECT  2.16 14.715 153.36 14.985 ;
     RECT  2.16 15.255 153.36 15.525 ;
     RECT  2.16 15.795 153.36 16.065 ;
     RECT  2.16 16.335 153.36 16.605 ;
     RECT  2.16 16.875 153.36 17.145 ;
     RECT  2.16 17.415 153.36 17.685 ;
     RECT  2.16 17.955 153.36 18.225 ;
     RECT  2.16 18.495 153.36 18.765 ;
     RECT  2.16 19.035 153.36 19.305 ;
     RECT  2.16 19.575 153.36 19.845 ;
     RECT  2.16 20.115 153.36 20.385 ;
     RECT  2.16 20.655 153.36 20.925 ;
     RECT  2.16 21.195 153.36 21.465 ;
     RECT  2.16 21.735 153.36 22.005 ;
     RECT  2.16 22.275 153.36 22.545 ;
     RECT  2.16 22.815 153.36 23.085 ;
     RECT  2.16 23.355 153.36 23.625 ;
     RECT  2.16 23.895 153.36 24.165 ;
     RECT  2.16 24.435 153.36 24.705 ;
     RECT  2.16 24.975 153.36 25.245 ;
     RECT  2.16 25.515 153.36 25.785 ;
     RECT  2.16 26.055 153.36 26.325 ;
     RECT  2.16 26.595 153.36 26.865 ;
     RECT  2.16 27.135 153.36 27.405 ;
     RECT  2.16 27.675 153.36 27.945 ;
     RECT  2.16 28.215 153.36 28.485 ;
     RECT  2.16 28.755 153.36 29.025 ;
     RECT  2.16 29.295 153.36 29.565 ;
     RECT  2.16 29.835 153.36 30.105 ;
     RECT  2.16 30.375 153.36 30.645 ;
     RECT  2.16 30.915 153.36 31.185 ;
     RECT  2.16 31.455 153.36 31.725 ;
     RECT  2.16 31.995 153.36 32.265 ;
     RECT  2.16 32.535 153.36 32.805 ;
     RECT  2.16 33.075 153.36 33.345 ;
     RECT  2.16 33.615 153.36 33.885 ;
     RECT  2.16 34.155 153.36 34.425 ;
     RECT  2.16 34.695 153.36 34.965 ;
     RECT  2.16 35.235 153.36 35.505 ;
     RECT  2.16 35.775 153.36 36.045 ;
     RECT  2.16 36.315 153.36 36.585 ;
     RECT  2.16 36.855 153.36 37.125 ;
     RECT  2.16 37.395 153.36 37.665 ;
     RECT  2.16 37.935 153.36 38.205 ;
     RECT  2.16 38.475 153.36 38.745 ;
     RECT  2.16 39.015 153.36 39.285 ;
     RECT  2.16 39.555 153.36 39.825 ;
     RECT  2.16 40.095 153.36 40.365 ;
     RECT  2.16 40.635 153.36 40.905 ;
     RECT  2.16 41.175 153.36 41.445 ;
     RECT  2.16 41.715 153.36 41.985 ;
     RECT  2.16 42.255 153.36 42.525 ;
     RECT  2.16 42.795 153.36 43.065 ;
     RECT  2.16 43.335 153.36 43.605 ;
     RECT  2.16 43.875 153.36 44.145 ;
     RECT  2.16 44.415 153.36 44.685 ;
     RECT  2.16 44.955 153.36 45.225 ;
     RECT  2.16 45.495 153.36 45.765 ;
     RECT  2.16 46.035 153.36 46.305 ;
     RECT  2.16 46.575 153.36 46.845 ;
     RECT  2.16 47.115 153.36 47.385 ;
     RECT  2.16 47.655 153.36 47.925 ;
     RECT  2.16 48.195 153.36 48.465 ;
     RECT  2.16 48.735 153.36 49.005 ;
     RECT  2.16 49.275 153.36 49.545 ;
     RECT  2.16 49.815 153.36 50.085 ;
     RECT  2.16 50.355 153.36 50.625 ;
     RECT  2.16 50.895 153.36 51.165 ;
     RECT  2.16 51.435 153.36 51.705 ;
     RECT  2.16 51.975 153.36 52.245 ;
     RECT  2.16 52.515 153.36 52.785 ;
     RECT  2.16 53.055 153.36 53.325 ;
     RECT  2.16 53.595 153.36 53.865 ;
     RECT  2.16 54.135 153.36 54.405 ;
     RECT  2.16 54.675 153.36 54.945 ;
     RECT  2.16 55.215 153.36 55.485 ;
     RECT  2.16 55.755 153.36 56.025 ;
     RECT  2.16 56.295 153.36 56.565 ;
     RECT  2.16 56.835 153.36 57.105 ;
     RECT  2.16 57.375 153.36 57.645 ;
     RECT  2.16 57.915 153.36 58.185 ;
     RECT  2.16 58.455 153.36 58.725 ;
     RECT  2.16 58.995 153.36 59.265 ;
     RECT  2.16 59.535 153.36 59.805 ;
     RECT  2.16 60.075 153.36 60.345 ;
     RECT  2.16 60.615 153.36 60.885 ;
     RECT  2.16 61.155 153.36 61.425 ;
     RECT  2.16 61.695 153.36 61.965 ;
     RECT  2.16 62.235 153.36 62.505 ;
     RECT  2.16 62.775 153.36 63.045 ;
     RECT  2.16 63.315 153.36 63.585 ;
     RECT  2.16 63.855 153.36 64.125 ;
     RECT  2.16 64.395 153.36 64.665 ;
     RECT  2.16 64.935 153.36 65.205 ;
     RECT  2.16 65.475 153.36 65.745 ;
     RECT  2.16 66.015 153.36 66.285 ;
     RECT  2.16 66.555 153.36 66.825 ;
     RECT  2.16 67.095 153.36 67.365 ;
     RECT  2.16 67.635 153.36 67.905 ;
     RECT  2.16 68.175 153.36 68.445 ;
     RECT  2.16 68.715 153.36 68.985 ;
     RECT  2.16 69.255 153.36 69.525 ;
     RECT  2.16 69.795 153.36 70.065 ;
     RECT  2.16 70.335 153.36 70.605 ;
     RECT  2.16 70.875 153.36 71.145 ;
     RECT  2.16 71.415 153.36 71.685 ;
     RECT  2.16 71.955 153.36 72.225 ;
     RECT  2.16 72.495 153.36 72.765 ;
     RECT  2.16 73.035 153.36 73.305 ;
     RECT  2.16 73.575 153.36 73.845 ;
     RECT  2.16 74.115 153.36 74.385 ;
     RECT  2.16 74.655 153.36 74.925 ;
     RECT  2.16 75.195 153.36 75.465 ;
     RECT  2.16 75.735 153.36 76.005 ;
     RECT  2.16 76.275 153.36 76.545 ;
     RECT  2.16 76.815 153.36 77.085 ;
     RECT  2.16 77.355 153.36 77.625 ;
     RECT  2.16 77.895 153.36 78.165 ;
     RECT  2.16 78.435 153.36 78.705 ;
     RECT  2.16 78.975 153.36 79.245 ;
     RECT  2.16 79.515 153.36 79.785 ;
     RECT  2.16 80.055 153.36 80.325 ;
     RECT  2.16 80.595 153.36 80.865 ;
     RECT  2.16 81.135 153.36 81.405 ;
     RECT  2.16 81.675 153.36 81.945 ;
     RECT  2.16 82.215 153.36 82.485 ;
     RECT  2.16 82.755 153.36 83.025 ;
     RECT  2.16 83.295 153.36 83.565 ;
     RECT  2.16 83.835 153.36 84.105 ;
     RECT  2.16 84.375 153.36 84.645 ;
     RECT  2.16 84.915 153.36 85.185 ;
     RECT  2.16 85.455 153.36 85.725 ;
     RECT  2.16 85.995 153.36 86.265 ;
     RECT  2.16 86.535 153.36 86.805 ;
     RECT  2.16 87.075 153.36 87.345 ;
     RECT  2.16 87.615 153.36 87.885 ;
     RECT  2.16 88.155 153.36 88.425 ;
     RECT  2.16 88.695 153.36 88.965 ;
     RECT  2.16 89.235 153.36 89.505 ;
     RECT  2.16 89.775 153.36 90.045 ;
     RECT  2.16 90.315 153.36 90.585 ;
     RECT  2.16 90.855 153.36 91.125 ;
     RECT  2.16 91.395 153.36 91.665 ;
     RECT  2.16 91.935 153.36 92.205 ;
     RECT  2.16 92.475 153.36 92.745 ;
     RECT  2.16 93.015 153.36 93.285 ;
     RECT  2.16 93.555 153.36 93.825 ;
     RECT  2.16 94.095 153.36 94.365 ;
     RECT  2.16 94.635 153.36 94.905 ;
     RECT  2.16 95.175 153.36 95.445 ;
     RECT  2.16 95.715 153.36 95.985 ;
     RECT  2.16 96.255 153.36 96.525 ;
     RECT  2.16 96.795 153.36 97.065 ;
     RECT  2.16 97.335 153.36 97.605 ;
     RECT  2.16 97.875 153.36 98.145 ;
     RECT  2.16 98.415 153.36 98.685 ;
     RECT  2.16 98.955 153.36 99.225 ;
     RECT  2.16 99.495 153.36 99.765 ;
     RECT  2.16 100.035 153.36 100.305 ;
     RECT  2.16 100.575 153.36 100.845 ;
     RECT  2.16 101.115 153.36 101.385 ;
     RECT  2.16 101.655 153.36 101.925 ;
     RECT  2.16 102.195 153.36 102.465 ;
     RECT  2.16 102.735 153.36 103.005 ;
     RECT  2.16 103.275 153.36 103.545 ;
     RECT  2.16 103.815 153.36 104.085 ;
     RECT  2.16 104.355 153.36 104.625 ;
     RECT  2.16 104.895 153.36 105.165 ;
     RECT  2.16 105.435 153.36 105.705 ;
     RECT  2.16 105.975 153.36 106.245 ;
     RECT  2.16 106.515 153.36 106.785 ;
     RECT  2.16 107.055 153.36 107.325 ;
     RECT  2.16 107.595 153.36 107.865 ;
     RECT  2.16 108.135 153.36 108.405 ;
     RECT  2.16 108.675 153.36 108.945 ;
     RECT  2.16 109.215 153.36 109.485 ;
     RECT  2.16 109.755 153.36 110.025 ;
     RECT  2.16 110.295 153.36 110.565 ;
     RECT  2.16 110.835 153.36 111.105 ;
     RECT  2.16 111.375 153.36 111.645 ;
     RECT  2.16 111.915 153.36 112.185 ;
     RECT  2.16 112.455 153.36 112.725 ;
     RECT  2.16 112.995 153.36 113.265 ;
     RECT  2.16 113.535 153.36 113.805 ;
     RECT  2.16 114.075 153.36 114.345 ;
     RECT  2.16 114.615 153.36 114.885 ;
     RECT  2.16 115.155 153.36 115.425 ;
     RECT  2.16 115.695 153.36 115.965 ;
     RECT  2.16 116.235 153.36 116.505 ;
     RECT  2.16 116.775 153.36 117.045 ;
     RECT  2.16 117.315 153.36 117.585 ;
     RECT  2.16 117.855 153.36 118.125 ;
     RECT  2.16 118.395 153.36 118.665 ;
     RECT  2.16 118.935 153.36 119.205 ;
     RECT  2.16 119.475 153.36 119.745 ;
     RECT  2.16 120.015 153.36 120.285 ;
     RECT  2.16 120.555 153.36 120.825 ;
     RECT  2.16 121.095 153.36 121.365 ;
     RECT  2.16 121.635 153.36 121.905 ;
     RECT  2.16 122.175 153.36 122.445 ;
     RECT  2.16 122.715 153.36 122.985 ;
     RECT  2.16 123.255 153.36 123.525 ;
     RECT  2.16 123.795 153.36 124.065 ;
     RECT  2.16 124.335 153.36 124.605 ;
     RECT  2.16 124.875 153.36 125.145 ;
     RECT  2.16 125.415 153.36 125.685 ;
     RECT  2.16 125.955 153.36 126.225 ;
     RECT  2.16 126.495 153.36 126.765 ;
     RECT  2.16 127.035 153.36 127.305 ;
     RECT  2.16 127.575 153.36 127.845 ;
     RECT  2.16 128.115 153.36 128.385 ;
     RECT  2.16 128.655 153.36 128.925 ;
     RECT  2.16 129.195 153.36 129.465 ;
     RECT  2.16 129.735 153.36 130.005 ;
     RECT  2.16 130.275 153.36 130.545 ;
     RECT  2.16 130.815 153.36 131.085 ;
     RECT  2.16 131.355 153.36 131.625 ;
     RECT  2.16 131.895 153.36 132.165 ;
     RECT  2.16 132.435 153.36 132.705 ;
     RECT  2.16 132.975 153.36 133.245 ;
     RECT  2.16 133.515 153.36 133.785 ;
     RECT  2.16 134.055 153.36 134.325 ;
     RECT  2.16 134.595 153.36 134.865 ;
     RECT  2.16 135.135 153.36 135.405 ;
     RECT  2.16 135.675 153.36 135.945 ;
     RECT  2.16 136.215 153.36 136.485 ;
     RECT  2.16 136.755 153.36 137.025 ;
     RECT  2.16 137.295 153.36 137.565 ;
     RECT  2.16 137.835 153.36 138.105 ;
     RECT  2.16 138.375 153.36 138.645 ;
     RECT  2.16 138.915 153.36 139.185 ;
     RECT  2.16 139.455 153.36 139.725 ;
     RECT  2.16 139.995 153.36 140.265 ;
     RECT  2.16 140.535 153.36 140.805 ;
     RECT  2.16 141.075 153.36 141.345 ;
     RECT  2.16 141.615 153.36 141.885 ;
     RECT  2.16 142.155 153.36 142.425 ;
     RECT  2.16 142.695 153.36 142.965 ;
     RECT  2.16 143.235 153.36 143.505 ;
     RECT  2.16 143.775 153.36 144.045 ;
     RECT  2.16 144.315 153.36 144.585 ;
     RECT  2.16 144.855 153.36 145.125 ;
     RECT  2.16 145.395 153.36 145.665 ;
     RECT  2.16 145.935 153.36 146.205 ;
     RECT  2.16 146.475 153.36 146.745 ;
     RECT  2.16 147.015 153.36 147.285 ;
     RECT  2.16 147.555 153.36 147.825 ;
     RECT  2.16 148.095 153.36 148.365 ;
     RECT  2.16 148.635 153.36 148.905 ;
     RECT  2.16 149.175 153.36 149.445 ;
     RECT  2.16 149.715 153.36 149.985 ;
     RECT  2.16 150.255 153.36 150.525 ;
     RECT  2.16 150.795 153.36 151.065 ;
     RECT  2.16 151.335 153.36 151.605 ;
     RECT  2.16 151.875 153.36 152.145 ;
     RECT  2.16 152.415 153.36 152.685 ;
     RECT  2.16 152.955 153.36 153.225 ;
     RECT  2.16 153.495 153.36 153.765 ;
     RECT  2.16 154.035 153.36 154.305 ;
     RECT  2.16 154.575 153.36 154.845 ;
     RECT  2.16 155.115 153.36 155.385 ;
     RECT  2.16 155.655 153.36 155.925 ;
     RECT  2.16 156.195 153.36 156.465 ;
     RECT  2.16 156.735 153.36 157.005 ;
     RECT  2.16 157.275 153.36 157.545 ;
     RECT  2.16 157.815 153.36 158.085 ;
     RECT  2.16 158.355 153.36 158.625 ;
     RECT  2.16 158.895 153.36 159.165 ;
     RECT  2.16 159.435 153.36 159.705 ;
     RECT  2.16 159.975 153.36 160.245 ;
     RECT  2.16 160.515 153.36 160.785 ;
     RECT  2.16 161.055 153.36 161.325 ;
     RECT  2.16 161.595 153.36 161.865 ;
     RECT  2.16 162.135 153.36 162.405 ;
     RECT  2.16 162.675 153.36 162.945 ;
     RECT  2.16 163.215 153.36 163.485 ;
     RECT  2.16 163.755 153.36 164.025 ;
     RECT  2.16 164.295 153.36 164.565 ;
     RECT  2.16 164.835 153.36 165.105 ;
     RECT  2.16 165.375 153.36 165.645 ;
     RECT  2.16 165.915 153.36 166.185 ;
     RECT  2.16 166.455 153.36 166.725 ;
     RECT  2.16 166.995 153.36 167.265 ;
     RECT  2.16 167.535 153.36 167.805 ;
     RECT  2.16 168.075 153.36 168.345 ;
     RECT  2.16 168.615 153.36 168.885 ;
     RECT  2.16 169.155 153.36 169.425 ;
     RECT  2.16 169.695 153.36 169.965 ;
     RECT  2.16 170.235 153.36 170.505 ;
     RECT  2.16 170.775 153.36 171.045 ;
     RECT  2.16 171.315 153.36 171.585 ;
     RECT  2.16 171.855 153.36 172.125 ;
     RECT  2.16 172.395 153.36 172.665 ;
     RECT  2.16 172.935 153.36 173.205 ;
     RECT  2.16 173.475 153.36 173.745 ;
     RECT  2.16 174.015 153.36 174.285 ;
     RECT  2.16 174.555 153.36 174.825 ;
     RECT  2.16 175.095 153.36 175.365 ;
     RECT  2.16 175.635 153.36 175.905 ;
     RECT  2.16 176.175 153.36 176.445 ;
     RECT  2.16 176.715 153.36 176.985 ;
     RECT  2.16 177.255 153.36 177.525 ;
     RECT  2.16 177.795 153.36 178.065 ;
     RECT  2.16 178.335 153.36 178.605 ;
     RECT  2.16 178.875 153.36 179.145 ;
     RECT  2.16 179.415 153.36 179.685 ;
     RECT  2.16 179.955 153.36 180.225 ;
     RECT  2.16 180.495 153.36 180.765 ;
     RECT  2.16 181.035 153.36 181.305 ;
     RECT  2.16 181.575 153.36 181.845 ;
     RECT  2.16 182.115 153.36 182.385 ;
     RECT  2.16 182.655 153.36 182.925 ;
     RECT  2.16 183.195 153.36 183.465 ;
     RECT  2.16 183.735 153.36 184.005 ;
     RECT  2.16 184.275 153.36 184.545 ;
     RECT  2.16 184.815 153.36 185.085 ;
     RECT  2.16 185.355 153.36 185.625 ;
     RECT  2.16 185.895 153.36 186.165 ;
     RECT  2.16 186.435 153.36 186.705 ;
     RECT  2.16 186.975 153.36 187.245 ;
     RECT  2.16 187.515 153.36 187.785 ;
     RECT  2.16 188.055 153.36 188.325 ;
     RECT  2.16 188.595 153.36 188.865 ;
     RECT  2.16 189.135 153.36 189.405 ;
     RECT  2.16 189.675 153.36 189.945 ;
     RECT  2.16 190.215 153.36 190.485 ;
     RECT  2.16 190.755 153.36 191.025 ;
     RECT  2.16 191.295 153.36 191.565 ;
     RECT  2.16 191.835 153.36 192.105 ;
     RECT  2.16 192.375 153.36 192.645 ;
     RECT  2.16 192.915 153.36 193.185 ;
     RECT  2.16 193.455 153.36 193.725 ;
     RECT  2.16 193.995 153.36 194.265 ;
     RECT  2.16 194.535 153.36 194.805 ;
     RECT  2.16 195.075 153.36 195.345 ;
     RECT  2.16 195.615 153.36 195.885 ;
     RECT  2.16 196.155 153.36 196.425 ;
     RECT  2.16 196.695 153.36 196.965 ;
     RECT  2.16 197.235 153.36 197.505 ;
     RECT  2.16 197.775 153.36 198.045 ;
     RECT  2.16 198.315 153.36 198.585 ;
     RECT  2.16 198.855 153.36 199.125 ;
     RECT  2.16 199.395 153.36 199.665 ;
     RECT  2.16 199.935 153.36 200.205 ;
     RECT  2.16 200.475 153.36 200.745 ;
     RECT  2.16 201.015 153.36 201.285 ;
     RECT  2.16 201.555 153.36 201.825 ;
     RECT  2.16 202.095 153.36 202.365 ;
     RECT  2.16 202.635 153.36 202.905 ;
     RECT  2.16 203.175 153.36 203.445 ;
     RECT  2.16 203.715 153.36 203.985 ;
     RECT  2.16 204.255 153.36 204.525 ;
     RECT  2.16 204.795 153.36 205.065 ;
     RECT  2.16 205.335 153.36 205.605 ;
     RECT  2.16 205.875 153.36 206.145 ;
     RECT  2.16 206.415 153.36 206.685 ;
     RECT  2.16 206.955 153.36 207.225 ;
     RECT  2.16 207.495 153.36 207.765 ;
     RECT  2.16 208.035 153.36 208.305 ;
     RECT  2.16 208.575 153.36 208.845 ;
     RECT  2.16 209.115 153.36 209.385 ;
     RECT  2.16 209.655 153.36 209.925 ;
     RECT  2.16 210.195 153.36 210.465 ;
     RECT  2.16 210.735 153.36 211.005 ;
     RECT  2.16 211.275 153.36 211.545 ;
     RECT  2.16 211.815 153.36 212.085 ;
     RECT  2.16 212.355 153.36 212.625 ;
     RECT  2.16 212.895 153.36 213.165 ;
     RECT  2.16 213.435 153.36 213.705 ;
     RECT  2.16 213.975 153.36 214.245 ;
     RECT  2.16 214.515 153.36 214.785 ;
     RECT  2.16 215.055 153.36 215.325 ;
     RECT  2.16 215.595 153.36 215.865 ;
     RECT  2.16 216.135 153.36 216.405 ;
     RECT  2.16 216.675 153.36 216.945 ;
     RECT  2.16 217.215 153.36 217.485 ;
     RECT  2.16 217.755 153.36 218.025 ;
     RECT  2.16 218.295 153.36 218.565 ;
     RECT  2.16 218.835 153.36 219.105 ;
     RECT  2.16 219.375 153.36 219.645 ;
     RECT  2.16 219.915 153.36 220.185 ;
     RECT  2.16 220.455 153.36 220.725 ;
     RECT  2.16 220.995 153.36 221.265 ;
     RECT  2.16 221.535 153.36 221.805 ;
     RECT  2.16 222.075 153.36 222.345 ;
     RECT  2.16 222.615 153.36 222.885 ;
     RECT  2.16 223.155 153.36 223.425 ;
     RECT  2.16 223.695 153.36 223.965 ;
     RECT  2.16 224.235 153.36 224.505 ;
     RECT  2.16 224.775 153.36 225.045 ;
     RECT  2.16 225.315 153.36 225.585 ;
     RECT  2.16 225.855 153.36 226.125 ;
     RECT  2.16 226.395 153.36 226.665 ;
     RECT  2.16 226.935 153.36 227.205 ;
     RECT  2.16 227.475 153.36 227.745 ;
     RECT  2.16 228.015 153.36 228.285 ;
     RECT  2.16 228.555 153.36 228.825 ;
     RECT  2.16 229.095 153.36 229.365 ;
     RECT  2.16 229.635 153.36 229.905 ;
     RECT  2.16 230.175 153.36 230.445 ;
     RECT  2.16 230.715 153.36 230.985 ;
     RECT  2.16 231.255 153.36 231.525 ;
     RECT  2.16 231.795 153.36 232.065 ;
     RECT  2.16 232.335 153.36 232.605 ;
     RECT  2.16 232.875 153.36 233.145 ;
     RECT  2.16 233.415 153.36 233.685 ;
     RECT  2.16 233.955 153.36 234.225 ;
     RECT  2.16 234.495 153.36 234.765 ;
     RECT  2.16 235.035 153.36 235.305 ;
     RECT  2.16 235.575 153.36 235.845 ;
     RECT  2.16 236.115 153.36 236.385 ;
     RECT  2.16 236.655 153.36 236.925 ;
     RECT  2.16 237.195 153.36 237.465 ;
     RECT  2.16 237.735 153.36 238.005 ;
     RECT  2.16 238.275 153.36 238.545 ;
     RECT  2.16 238.815 153.36 239.085 ;
     RECT  2.16 239.355 153.36 239.625 ;
     RECT  2.16 239.895 153.36 240.165 ;
     RECT  2.16 240.435 153.36 240.705 ;
     RECT  2.16 240.975 153.36 241.245 ;
     RECT  2.16 241.515 153.36 241.785 ;
     RECT  2.16 242.055 153.36 242.325 ;
     RECT  2.16 242.595 153.36 242.865 ;
     RECT  2.16 243.135 153.36 243.405 ;
     RECT  2.16 243.675 153.36 243.945 ;
    LAYER M1 ;
     RECT  2.16 2.151 153.36 244.089 ;
    LAYER M2 ;
     RECT  0.103 170.982 0.391 171 ;
     RECT  0.103 88.902 0.427 88.92 ;
     RECT  0.283 89.748 0.427 89.766 ;
     RECT  0.391 170.982 0.427 171.414 ;
     RECT  0.391 115.236 0.499 115.254 ;
     RECT  0.319 116.046 0.499 116.064 ;
     RECT  0.103 114.282 0.823 114.3 ;
     RECT  0.355 121.914 0.967 121.932 ;
     RECT  0.427 88.902 1.003 89.766 ;
     RECT  0.535 129.816 1.003 129.834 ;
     RECT  0.967 142.704 1.003 142.722 ;
     RECT  0.967 198.936 1.003 198.954 ;
     RECT  0.967 93.06 1.075 93.078 ;
     RECT  1.003 129.816 1.111 130.194 ;
     RECT  0.247 133.056 1.111 133.074 ;
     RECT  0.463 162.144 1.399 162.162 ;
     RECT  0.931 163.026 1.399 163.044 ;
     RECT  1.003 88.506 1.435 89.766 ;
     RECT  1.075 127.89 1.471 127.908 ;
     RECT  0.391 94.41 1.507 94.428 ;
     RECT  0.103 120.762 1.507 120.78 ;
     RECT  0.823 101.736 1.543 101.754 ;
     RECT  1.471 127.854 1.543 127.908 ;
     RECT  1.471 138.15 1.543 138.168 ;
     RECT  0.319 97.416 1.615 97.434 ;
     RECT  1.039 123.03 1.615 123.048 ;
     RECT  1.507 94.374 1.651 94.428 ;
     RECT  1.615 123.03 1.651 123.786 ;
     RECT  1.543 138.15 1.651 138.204 ;
     RECT  0.247 85.428 1.903 85.446 ;
     RECT  1.003 142.128 1.903 142.722 ;
     RECT  0.535 99.162 1.939 99.18 ;
     RECT  0.283 117.63 1.939 117.648 ;
     RECT  1.651 138.15 1.975 138.744 ;
     RECT  1.651 94.374 2.011 95.13 ;
     RECT  1.579 110.268 2.011 110.286 ;
     RECT  1.651 122.76 2.047 123.786 ;
     RECT  0.103 105.75 2.083 105.768 ;
     RECT  0.859 102.78 2.119 102.798 ;
     RECT  2.083 105.336 2.119 106.344 ;
     RECT  1.507 120.294 2.119 120.78 ;
     RECT  0.103 182.934 2.119 182.952 ;
     RECT  1.975 160.326 2.155 160.344 ;
     RECT  0.103 17.622 2.16 17.64 ;
     RECT  0.535 47.736 2.16 47.754 ;
     RECT  0.103 58.698 2.16 58.716 ;
     RECT  1.687 67.374 2.16 67.392 ;
     RECT  1.039 79.218 2.16 79.236 ;
     RECT  1.903 84.888 2.16 85.446 ;
     RECT  1.111 86.544 2.16 86.562 ;
     RECT  1.435 88.506 2.16 89.838 ;
     RECT  0.931 90.828 2.16 90.846 ;
     RECT  1.579 91.674 2.16 91.692 ;
     RECT  1.075 92.484 2.16 93.078 ;
     RECT  2.011 94.374 2.16 95.202 ;
     RECT  2.119 95.994 2.16 96.012 ;
     RECT  1.615 97.236 2.16 97.434 ;
     RECT  0.355 98.388 2.16 98.406 ;
     RECT  1.939 99.162 2.16 99.288 ;
     RECT  1.543 101.16 2.16 101.754 ;
     RECT  2.119 102.708 2.16 102.834 ;
     RECT  1.471 104.166 2.16 104.184 ;
     RECT  2.119 105.21 2.16 106.344 ;
     RECT  2.011 110.268 2.16 110.826 ;
     RECT  0.931 111.726 2.16 111.744 ;
     RECT  0.823 114.084 2.16 114.3 ;
     RECT  0.499 115.236 2.16 116.064 ;
     RECT  1.939 117.63 2.16 117.684 ;
     RECT  0.895 118.746 2.16 118.764 ;
     RECT  2.119 120.096 2.16 120.78 ;
     RECT  0.967 121.878 2.16 121.932 ;
     RECT  2.047 122.76 2.16 124.128 ;
     RECT  1.543 127.854 2.16 128.106 ;
     RECT  1.111 129.474 2.16 130.194 ;
     RECT  0.535 131.598 2.16 131.616 ;
     RECT  1.111 132.984 2.16 133.074 ;
     RECT  2.119 133.866 2.16 133.884 ;
     RECT  2.083 135.45 2.16 135.468 ;
     RECT  1.975 137.61 2.16 138.744 ;
     RECT  0.103 140.778 2.16 140.796 ;
     RECT  1.903 142.128 2.16 142.992 ;
     RECT  2.155 149.22 2.16 149.238 ;
     RECT  2.155 153.306 2.16 153.324 ;
     RECT  2.155 159.912 2.16 160.344 ;
     RECT  0.103 161.262 2.16 161.28 ;
     RECT  1.399 162.144 2.16 163.044 ;
     RECT  0.103 166.932 2.16 166.95 ;
     RECT  1.471 169.434 2.16 169.452 ;
     RECT  0.427 170.856 2.16 171.414 ;
     RECT  2.155 172.746 2.16 172.764 ;
     RECT  1.543 173.952 2.16 173.97 ;
     RECT  2.155 174.906 2.16 174.924 ;
     RECT  2.047 177.066 2.16 177.084 ;
     RECT  2.011 181.476 2.16 181.494 ;
     RECT  2.119 182.466 2.16 182.952 ;
     RECT  0.499 187.056 2.16 187.074 ;
     RECT  1.039 191.646 2.16 191.664 ;
     RECT  2.083 193.266 2.16 193.284 ;
     RECT  0.103 196.632 2.16 196.65 ;
     RECT  1.003 198.936 2.16 199.152 ;
     RECT  0.103 213.102 2.16 213.12 ;
     RECT  0.103 215.37 2.16 215.388 ;
     RECT  1.615 217.026 2.16 217.044 ;
     RECT  0.895 220.266 2.16 220.284 ;
     RECT  0.535 223.434 2.16 223.452 ;
     RECT  1.687 232.146 2.16 232.164 ;
     RECT  1.651 233.964 2.16 233.982 ;
     RECT  1.111 236.898 2.16 236.916 ;
     RECT  2.16 2.151 153.36 244.089 ;
     RECT  153.36 120.456 153.599 128.304 ;
     RECT  153.36 92.016 153.887 92.934 ;
     RECT  153.36 95.418 153.887 101.034 ;
     RECT  153.36 103.176 153.887 111.024 ;
     RECT  153.36 136.116 153.887 149.544 ;
     RECT  153.36 154.206 153.887 154.494 ;
     RECT  153.36 93.726 153.923 94.554 ;
     RECT  153.887 103.446 153.923 111.024 ;
     RECT  153.599 120.456 153.923 120.654 ;
     RECT  153.36 129.132 153.923 135.324 ;
     RECT  153.887 154.206 153.923 154.404 ;
     RECT  153.923 129.132 154.427 133.47 ;
     RECT  153.887 92.286 154.463 92.934 ;
     RECT  153.923 93.726 154.463 94.284 ;
     RECT  153.887 95.418 154.463 98.91 ;
     RECT  153.887 99.738 154.463 101.034 ;
     RECT  153.36 101.898 154.463 102.384 ;
     RECT  153.923 103.446 154.463 105.39 ;
     RECT  153.923 106.218 154.463 111.024 ;
     RECT  153.36 111.852 154.463 119.664 ;
     RECT  153.923 120.456 154.463 120.474 ;
     RECT  153.599 121.536 154.463 128.304 ;
     RECT  154.427 129.132 154.463 130.878 ;
     RECT  154.427 131.796 154.463 133.47 ;
     RECT  153.923 134.766 154.463 135.324 ;
     RECT  153.887 136.116 154.463 139.104 ;
     RECT  153.887 139.932 154.463 143.424 ;
     RECT  153.887 144.486 154.463 144.774 ;
     RECT  153.887 145.566 154.463 149.544 ;
     RECT  153.36 150.3 154.463 152.712 ;
     RECT  153.923 154.206 154.463 154.224 ;
     RECT  154.463 92.286 154.499 92.304 ;
     RECT  154.463 99.738 154.499 99.756 ;
     RECT  154.463 104.796 154.499 104.814 ;
     RECT  154.463 113.976 154.499 113.994 ;
     RECT  154.463 115.668 154.499 115.686 ;
     RECT  154.463 119.106 154.499 119.124 ;
     RECT  154.463 124.236 154.499 124.254 ;
     RECT  154.463 140.616 154.499 140.634 ;
     RECT  154.463 152.694 154.499 152.712 ;
     RECT  154.463 122.526 155.435 122.544 ;
     RECT  154.463 126.396 155.435 126.414 ;
    LAYER M3 ;
     RECT  2.415 2.143 2.505 2.413 ;
     RECT  7.815 2.143 7.905 2.413 ;
     RECT  13.215 2.143 13.305 2.413 ;
     RECT  18.615 2.143 18.705 2.413 ;
     RECT  24.015 2.143 24.105 2.413 ;
     RECT  29.415 2.143 29.505 2.413 ;
     RECT  34.815 2.143 34.905 2.413 ;
     RECT  40.215 2.143 40.305 2.413 ;
     RECT  45.615 2.143 45.705 2.413 ;
     RECT  51.015 2.143 51.105 2.413 ;
     RECT  56.415 2.143 56.505 2.413 ;
     RECT  61.815 2.143 61.905 2.413 ;
     RECT  67.215 2.143 67.305 2.413 ;
     RECT  72.615 2.143 72.705 2.413 ;
     RECT  78.015 2.143 78.105 2.413 ;
     RECT  83.415 2.143 83.505 2.413 ;
     RECT  88.815 2.143 88.905 2.413 ;
     RECT  94.215 2.143 94.305 2.413 ;
     RECT  99.615 2.143 99.705 2.413 ;
     RECT  105.015 2.143 105.105 2.413 ;
     RECT  110.415 2.143 110.505 2.413 ;
     RECT  115.815 2.143 115.905 2.413 ;
     RECT  121.215 2.143 121.305 2.413 ;
     RECT  126.615 2.143 126.705 2.413 ;
     RECT  132.015 2.143 132.105 2.413 ;
     RECT  137.415 2.143 137.505 2.413 ;
     RECT  142.815 2.143 142.905 2.413 ;
     RECT  148.215 2.143 148.305 2.413 ;
     RECT  2.415 2.413 2.697 5.995 ;
     RECT  4.212 5.971 4.23 6.079 ;
     RECT  4.176 6.079 4.23 6.115 ;
     RECT  2.304 5.995 2.697 6.151 ;
     RECT  4.068 6.115 4.23 6.151 ;
     RECT  5.796 6.511 5.814 6.655 ;
     RECT  2.304 6.151 4.23 6.691 ;
     RECT  5.616 6.655 5.814 6.691 ;
     RECT  2.304 6.691 6.21 6.808 ;
     RECT  6.948 6.511 6.966 6.808 ;
     RECT  2.304 6.808 6.966 6.817 ;
     RECT  7.815 2.413 8.097 6.817 ;
     RECT  2.304 6.817 8.097 6.845 ;
     RECT  2.304 6.845 6.21 7.079 ;
     RECT  6.948 6.845 8.097 7.187 ;
     RECT  2.304 7.079 5.022 7.349 ;
     RECT  7.344 7.187 8.097 7.699 ;
     RECT  8.82 7.465 8.838 7.699 ;
     RECT  7.344 7.699 8.838 7.763 ;
     RECT  9.864 7.393 9.882 7.771 ;
     RECT  6.192 7.079 6.21 7.933 ;
     RECT  2.304 7.349 4.626 8.437 ;
     RECT  5.724 7.933 6.21 8.437 ;
     RECT  2.304 8.437 6.21 8.735 ;
     RECT  6.192 8.735 6.21 8.851 ;
     RECT  7.344 7.763 8.586 8.851 ;
     RECT  7.308 8.851 8.586 8.941 ;
     RECT  9.468 7.771 9.882 8.941 ;
     RECT  7.308 8.941 9.882 9.005 ;
     RECT  7.344 9.005 9.882 9.391 ;
     RECT  2.304 8.735 4.77 9.545 ;
     RECT  2.34 9.545 4.77 9.653 ;
     RECT  6.192 8.851 6.534 9.859 ;
     RECT  5.796 9.859 6.534 9.895 ;
     RECT  2.412 9.653 4.77 9.923 ;
     RECT  2.415 9.923 4.77 9.931 ;
     RECT  5.652 9.895 6.534 9.931 ;
     RECT  2.415 9.931 6.534 10.021 ;
     RECT  7.344 9.391 10.53 10.021 ;
     RECT  2.415 10.021 10.53 10.229 ;
     RECT  5.148 10.229 10.53 10.661 ;
     RECT  2.415 10.229 4.338 10.747 ;
     RECT  5.472 10.661 10.53 10.781 ;
     RECT  2.304 10.747 4.338 11.245 ;
     RECT  5.58 10.781 10.53 11.281 ;
     RECT  5.58 11.281 11.142 12.019 ;
     RECT  5.4 12.019 11.142 12.083 ;
     RECT  2.304 11.245 4.554 12.091 ;
     RECT  5.4 12.083 5.418 12.091 ;
     RECT  2.304 12.091 5.418 12.209 ;
     RECT  6.192 12.083 11.142 12.515 ;
     RECT  2.304 12.209 5.058 13.063 ;
     RECT  6.192 12.515 6.534 13.063 ;
     RECT  2.304 13.063 6.534 14.099 ;
     RECT  2.304 14.099 4.518 14.135 ;
     RECT  3.42 14.135 4.518 14.945 ;
     RECT  3.636 14.945 4.518 15.061 ;
     RECT  5.76 14.099 6.534 15.061 ;
     RECT  3.636 15.061 4.698 15.295 ;
     RECT  5.472 15.061 6.534 15.295 ;
     RECT  2.304 14.135 2.697 15.331 ;
     RECT  2.304 15.331 2.898 15.835 ;
     RECT  3.636 15.295 6.534 15.835 ;
     RECT  0.108 15.835 0.126 15.965 ;
     RECT  2.304 15.835 6.534 16.025 ;
     RECT  2.415 16.025 6.534 16.105 ;
     RECT  7.272 12.515 11.142 16.105 ;
     RECT  2.415 16.105 11.142 16.537 ;
     RECT  2.415 16.537 11.574 16.795 ;
     RECT  2.34 16.795 11.574 17.227 ;
     RECT  18.615 2.413 18.897 17.311 ;
     RECT  2.304 17.227 11.574 17.339 ;
     RECT  2.415 17.339 11.574 17.491 ;
     RECT  2.415 17.491 12.258 17.519 ;
     RECT  2.415 17.519 2.79 17.609 ;
     RECT  3.6 17.519 12.258 17.609 ;
     RECT  3.636 17.609 12.258 17.645 ;
     RECT  2.415 17.609 2.754 17.681 ;
     RECT  0.108 17.617 0.126 17.693 ;
     RECT  3.636 17.645 6.534 17.879 ;
     RECT  3.636 17.879 4.554 17.951 ;
     RECT  2.415 17.681 2.697 18.091 ;
     RECT  2.304 18.091 2.697 18.185 ;
     RECT  3.636 17.951 4.482 18.811 ;
     RECT  5.292 17.879 6.534 18.811 ;
     RECT  2.34 18.185 2.697 18.955 ;
     RECT  2.304 18.955 2.697 19.075 ;
     RECT  3.636 18.811 6.534 19.075 ;
     RECT  2.304 19.075 6.534 19.381 ;
     RECT  2.268 19.381 6.534 19.421 ;
     RECT  2.304 19.421 6.534 19.651 ;
     RECT  7.272 17.645 12.258 19.651 ;
     RECT  2.304 19.651 12.258 20.525 ;
     RECT  2.304 20.525 6.534 21.271 ;
     RECT  7.272 20.525 12.258 21.271 ;
     RECT  2.304 21.271 12.258 21.971 ;
     RECT  2.304 21.971 4.23 22.711 ;
     RECT  4.968 21.971 12.258 22.711 ;
     RECT  2.304 22.711 12.258 23.701 ;
     RECT  2.268 23.701 12.258 23.741 ;
     RECT  2.304 23.741 12.258 24.125 ;
     RECT  2.34 24.125 12.258 24.665 ;
     RECT  0.108 24.571 0.126 24.701 ;
     RECT  0.108 25.867 0.126 26.045 ;
     RECT  2.415 24.665 12.258 26.293 ;
     RECT  2.34 26.293 12.258 26.429 ;
     RECT  2.34 26.429 3.042 26.731 ;
     RECT  2.304 26.731 3.042 27.211 ;
     RECT  3.996 26.429 12.258 27.211 ;
     RECT  2.304 27.211 12.258 28.985 ;
     RECT  2.34 28.985 12.258 29.633 ;
     RECT  2.34 29.633 3.258 30.187 ;
     RECT  2.304 30.187 3.258 30.415 ;
     RECT  3.996 29.633 12.258 30.415 ;
     RECT  2.304 30.415 12.258 30.605 ;
     RECT  3.924 30.605 12.258 30.749 ;
     RECT  2.304 30.605 2.754 31.483 ;
     RECT  2.304 31.483 3.114 31.801 ;
     RECT  2.268 31.801 3.114 31.891 ;
     RECT  2.268 31.891 3.33 32.299 ;
     RECT  4.104 30.749 12.258 32.299 ;
     RECT  2.268 32.299 12.258 32.765 ;
     RECT  2.268 32.765 2.862 33.691 ;
     RECT  3.78 32.765 12.258 33.691 ;
     RECT  2.268 33.691 12.258 34.889 ;
     RECT  3.492 34.889 12.258 35.429 ;
     RECT  2.268 34.889 2.697 35.851 ;
     RECT  2.268 35.851 2.862 36.391 ;
     RECT  4.104 35.429 12.258 36.391 ;
     RECT  3.96 36.391 12.258 36.545 ;
     RECT  24.015 2.413 24.297 36.589 ;
     RECT  2.268 36.391 3.222 36.661 ;
     RECT  2.232 36.661 3.222 36.701 ;
     RECT  2.268 36.701 3.222 37.049 ;
     RECT  4.104 36.545 12.258 37.471 ;
     RECT  3.78 37.471 12.258 37.561 ;
     RECT  13.215 2.413 13.497 37.561 ;
     RECT  3.78 37.561 13.497 37.633 ;
     RECT  14.724 31.891 14.742 37.633 ;
     RECT  3.78 37.633 14.742 37.661 ;
     RECT  2.268 37.049 2.934 38.005 ;
     RECT  3.78 37.661 12.258 38.005 ;
     RECT  2.268 38.005 12.258 38.435 ;
     RECT  16.776 25.951 16.794 38.443 ;
     RECT  17.928 17.311 18.897 38.443 ;
     RECT  2.268 38.435 2.898 38.821 ;
     RECT  2.232 38.821 2.898 38.861 ;
     RECT  2.268 38.861 2.898 39.361 ;
     RECT  3.852 38.435 12.258 39.361 ;
     RECT  2.268 39.361 12.258 41.909 ;
     RECT  3.96 41.909 12.258 41.945 ;
     RECT  2.268 41.909 2.898 42.691 ;
     RECT  2.268 42.691 3.186 42.715 ;
     RECT  3.996 41.945 12.258 42.715 ;
     RECT  2.268 42.715 12.258 43.501 ;
     RECT  13.215 37.661 14.742 43.501 ;
     RECT  0.108 43.147 0.126 44.141 ;
     RECT  0.108 45.307 0.126 45.485 ;
     RECT  2.268 43.501 14.742 45.931 ;
     RECT  19.728 22.783 19.746 45.967 ;
     RECT  2.268 45.931 14.814 46.061 ;
     RECT  2.268 46.061 14.742 46.805 ;
     RECT  2.268 46.805 2.697 47.551 ;
     RECT  3.6 46.805 14.742 47.551 ;
     RECT  0.54 47.731 0.558 47.933 ;
     RECT  2.268 47.551 14.742 48.425 ;
     RECT  2.268 48.425 2.862 49.171 ;
     RECT  2.268 49.171 3.042 49.351 ;
     RECT  3.78 48.425 14.742 49.351 ;
     RECT  2.268 49.351 14.742 49.621 ;
     RECT  2.232 49.621 14.742 49.661 ;
     RECT  2.268 49.661 14.742 50.089 ;
     RECT  15.66 46.471 15.678 50.089 ;
     RECT  2.268 50.089 15.678 50.315 ;
     RECT  2.268 50.315 2.862 50.729 ;
     RECT  2.268 50.729 2.754 51.511 ;
     RECT  2.268 51.511 2.934 52.321 ;
     RECT  3.744 50.315 15.678 52.321 ;
     RECT  2.268 52.321 15.678 54.715 ;
     RECT  2.196 54.715 15.678 55.985 ;
     RECT  2.196 55.985 2.898 56.327 ;
     RECT  2.268 56.327 2.898 56.489 ;
     RECT  3.744 55.985 15.678 56.911 ;
     RECT  3.528 56.911 15.678 57.335 ;
     RECT  3.708 57.335 15.678 58.081 ;
     RECT  2.268 56.489 2.697 58.729 ;
     RECT  0.108 58.693 0.126 58.733 ;
     RECT  2.196 58.729 2.697 58.801 ;
     RECT  3.636 58.081 15.678 58.801 ;
     RECT  2.196 58.801 15.678 60.221 ;
     RECT  22.068 54.031 22.086 60.349 ;
     RECT  2.196 60.221 2.862 61.231 ;
     RECT  3.744 60.221 15.678 61.231 ;
     RECT  2.196 61.231 15.678 62.699 ;
     RECT  2.268 62.699 15.678 63.509 ;
     RECT  3.744 63.509 15.678 64.291 ;
     RECT  2.268 63.509 2.898 64.363 ;
     RECT  3.672 64.291 15.678 64.363 ;
     RECT  2.268 64.363 15.678 65.129 ;
     RECT  3.636 65.129 15.678 65.669 ;
     RECT  21.024 36.787 21.042 65.983 ;
     RECT  2.268 65.129 2.697 66.091 ;
     RECT  2.268 66.091 2.934 66.631 ;
     RECT  3.744 65.669 15.678 66.631 ;
     RECT  0.108 66.907 0.126 67.085 ;
     RECT  2.268 66.631 15.678 67.369 ;
     RECT  19.728 45.967 19.962 72.463 ;
     RECT  20.916 65.983 21.042 72.463 ;
     RECT  1.692 67.369 15.678 72.959 ;
     RECT  22.068 60.349 22.194 73.381 ;
     RECT  21.78 73.381 22.194 73.421 ;
     RECT  1.692 72.959 2.697 73.921 ;
     RECT  3.528 72.959 15.678 73.921 ;
     RECT  1.692 73.921 15.678 74.011 ;
     RECT  16.776 38.443 18.897 74.011 ;
     RECT  0.108 74.251 0.126 74.381 ;
     RECT  0.108 77.707 0.126 77.885 ;
     RECT  22.068 73.421 22.194 77.971 ;
     RECT  1.692 74.011 18.897 78.941 ;
     RECT  1.692 78.941 17.514 79.213 ;
     RECT  19.728 72.463 21.042 79.447 ;
     RECT  18.615 78.941 18.897 80.059 ;
     RECT  19.62 79.447 21.042 80.059 ;
     RECT  18.615 80.059 21.042 80.095 ;
     RECT  18.576 80.095 21.042 80.131 ;
     RECT  18.396 80.131 21.042 80.365 ;
     RECT  1.044 79.213 17.514 80.563 ;
     RECT  18.252 80.365 21.042 80.563 ;
     RECT  1.044 80.563 21.042 80.789 ;
     RECT  23.796 36.589 24.297 81.445 ;
     RECT  1.044 80.789 2.79 81.679 ;
     RECT  1.044 81.679 2.862 81.751 ;
     RECT  3.636 80.789 21.042 81.751 ;
     RECT  21.888 77.971 22.194 81.949 ;
     RECT  1.044 81.751 21.042 82.111 ;
     RECT  1.044 82.111 21.078 82.561 ;
     RECT  21.852 81.949 22.194 82.561 ;
     RECT  1.044 82.561 22.194 82.651 ;
     RECT  23.328 81.445 24.297 82.651 ;
     RECT  25.704 30.001 25.722 83.191 ;
     RECT  29.415 2.413 29.697 83.335 ;
     RECT  25.092 83.191 25.722 83.461 ;
     RECT  25.056 83.461 25.722 83.803 ;
     RECT  25.056 83.803 25.794 83.839 ;
     RECT  1.044 82.651 24.297 84.181 ;
     RECT  25.02 83.839 25.794 84.181 ;
     RECT  1.044 84.181 25.794 84.271 ;
     RECT  1.044 84.271 25.974 84.649 ;
     RECT  1.044 84.649 26.154 84.721 ;
     RECT  1.044 84.721 26.478 86.233 ;
     RECT  1.044 86.233 26.694 87.421 ;
     RECT  37.044 87.313 37.062 87.845 ;
     RECT  1.044 87.421 26.802 87.881 ;
     RECT  40.215 2.413 40.497 87.961 ;
     RECT  0.252 85.423 0.27 88.075 ;
     RECT  1.044 87.881 26.73 88.501 ;
     RECT  29.415 83.335 29.754 88.699 ;
     RECT  0.108 88.075 0.27 88.973 ;
     RECT  0.252 88.973 0.27 89.311 ;
     RECT  1.008 88.501 26.73 89.311 ;
     RECT  0.252 89.311 26.946 90.283 ;
     RECT  0.252 90.283 27.09 90.625 ;
     RECT  28.08 87.277 28.098 91.093 ;
     RECT  0.252 90.625 27.162 91.165 ;
     RECT  29.088 88.699 29.754 91.165 ;
     RECT  34.815 2.413 35.097 91.285 ;
     RECT  0.252 91.165 27.198 91.291 ;
     RECT  34.704 91.285 35.097 91.325 ;
     RECT  38.772 91.291 38.79 91.421 ;
     RECT  152.568 91.291 152.586 91.471 ;
     RECT  0.252 91.291 27.27 91.531 ;
     RECT  28.008 91.093 28.098 91.633 ;
     RECT  29.016 91.165 29.754 91.633 ;
     RECT  0.108 91.531 27.27 91.661 ;
     RECT  0.252 91.661 27.27 91.741 ;
     RECT  28.008 91.633 29.754 91.741 ;
     RECT  152.136 91.471 152.802 91.741 ;
     RECT  153.864 91.963 153.882 92.039 ;
     RECT  152.136 91.741 153.126 92.165 ;
     RECT  152.136 92.165 153.054 92.245 ;
     RECT  37.98 87.961 37.998 92.371 ;
     RECT  151.596 92.245 153.054 92.371 ;
     RECT  154.476 92.281 154.494 92.429 ;
     RECT  66.276 92.395 66.294 92.435 ;
     RECT  56.415 2.413 56.697 92.443 ;
     RECT  64.728 92.371 64.746 92.477 ;
     RECT  37.98 92.371 38.034 92.479 ;
     RECT  51.015 2.413 51.297 92.491 ;
     RECT  150.192 92.371 150.21 92.515 ;
     RECT  151.344 92.371 153.054 92.515 ;
     RECT  37.98 92.479 38.178 92.525 ;
     RECT  51.015 92.491 51.894 92.543 ;
     RECT  55.836 92.443 56.697 92.543 ;
     RECT  149.256 92.539 149.274 92.551 ;
     RECT  150.084 92.515 153.054 92.551 ;
     RECT  30.96 90.391 30.978 92.669 ;
     RECT  149.256 92.551 153.054 92.669 ;
     RECT  150.192 92.669 152.946 92.705 ;
     RECT  152.316 92.705 152.946 92.777 ;
     RECT  32.004 92.749 32.022 92.821 ;
     RECT  154.44 92.827 154.458 92.939 ;
     RECT  31.788 92.821 32.022 92.975 ;
     RECT  148.215 2.413 148.497 93.019 ;
     RECT  146.484 92.911 146.502 93.047 ;
     RECT  148.176 93.019 148.497 93.055 ;
     RECT  149.256 92.669 149.418 93.055 ;
     RECT  31.968 92.975 32.022 93.091 ;
     RECT  147.6 93.055 149.418 93.197 ;
     RECT  146.016 93.163 146.034 93.209 ;
     RECT  152.64 92.777 152.946 93.209 ;
     RECT  146.808 93.217 146.826 93.253 ;
     RECT  145.944 93.217 145.962 93.389 ;
     RECT  148.176 93.197 149.418 93.479 ;
     RECT  148.215 93.479 149.418 93.515 ;
     RECT  31.968 93.091 32.058 93.595 ;
     RECT  37.98 92.525 37.998 93.757 ;
     RECT  150.948 92.705 151.362 93.865 ;
     RECT  152.748 93.209 152.946 93.865 ;
     RECT  72.615 2.413 72.897 93.991 ;
     RECT  39.276 93.631 39.294 94.055 ;
     RECT  150.948 93.865 151.614 94.099 ;
     RECT  152.748 93.865 153.018 94.099 ;
     RECT  150.948 94.099 153.018 94.127 ;
     RECT  150.192 92.705 150.21 94.135 ;
     RECT  151.596 94.127 153.018 94.163 ;
     RECT  146.808 93.253 146.97 94.171 ;
     RECT  149.4 93.515 149.418 94.199 ;
     RECT  150.192 94.135 150.822 94.205 ;
     RECT  154.44 93.691 154.458 94.289 ;
     RECT  150.192 94.205 150.534 94.297 ;
     RECT  146.484 94.171 146.97 94.361 ;
     RECT  151.812 94.163 153.018 94.361 ;
     RECT  61.815 2.413 62.097 94.405 ;
     RECT  149.22 94.369 149.238 94.445 ;
     RECT  153.9 94.531 153.918 94.589 ;
     RECT  150.048 94.297 150.534 94.595 ;
     RECT  148.215 93.515 148.497 94.603 ;
     RECT  146.952 94.361 146.97 94.711 ;
     RECT  147.816 94.603 148.497 94.711 ;
     RECT  150.048 94.595 150.21 94.739 ;
     RECT  151.812 94.361 152.622 94.829 ;
     RECT  61.092 94.405 62.097 94.865 ;
     RECT  149.76 94.981 149.778 95.099 ;
     RECT  145.98 94.795 145.998 95.171 ;
     RECT  146.952 94.711 148.497 95.179 ;
     RECT  146.952 95.179 149.13 95.215 ;
     RECT  152.028 94.829 152.622 95.251 ;
     RECT  153.576 94.987 153.594 95.251 ;
     RECT  146.844 95.215 149.13 95.369 ;
     RECT  146.952 95.369 149.13 95.405 ;
     RECT  39.42 94.171 39.438 95.419 ;
     RECT  40.215 87.961 41.058 95.419 ;
     RECT  152.028 95.251 153.594 95.513 ;
     RECT  151.056 95.521 151.074 95.563 ;
     RECT  152.028 95.513 153.018 95.611 ;
     RECT  39.42 95.419 41.058 95.675 ;
     RECT  52.812 92.515 52.83 95.741 ;
     RECT  148.215 95.405 149.13 95.842 ;
     RECT  43.092 91.387 43.11 95.881 ;
     RECT  151.848 95.611 153.018 95.945 ;
     RECT  43.02 95.881 43.11 96.179 ;
     RECT  153 95.945 153.018 96.179 ;
     RECT  150.912 95.563 151.074 96.295 ;
     RECT  151.848 95.945 152.262 96.295 ;
     RECT  146.952 95.405 147.294 96.331 ;
     RECT  39.42 95.675 39.438 96.359 ;
     RECT  148.215 95.842 148.806 96.359 ;
     RECT  31.968 93.595 32.274 96.421 ;
     RECT  0.252 91.741 29.754 96.565 ;
     RECT  142.815 2.413 143.097 96.565 ;
     RECT  146.412 96.331 147.294 96.565 ;
     RECT  148.215 96.359 148.59 96.565 ;
     RECT  31.896 96.421 32.274 96.593 ;
     RECT  146.268 96.565 147.294 96.601 ;
     RECT  148.032 96.565 148.59 96.601 ;
     RECT  150.912 96.295 152.262 96.601 ;
     RECT  146.268 96.601 148.59 96.605 ;
     RECT  149.544 96.601 149.562 96.691 ;
     RECT  150.552 96.601 152.262 96.691 ;
     RECT  142.524 96.565 143.097 96.719 ;
     RECT  146.952 96.605 148.497 96.719 ;
     RECT  150.552 96.691 152.91 96.719 ;
     RECT  149.364 96.691 149.562 96.755 ;
     RECT  150.624 96.719 152.91 96.755 ;
     RECT  146.952 96.719 147.294 96.827 ;
     RECT  32.04 96.593 32.274 96.989 ;
     RECT  150.624 96.755 150.858 97.133 ;
     RECT  0.252 96.565 30.222 97.147 ;
     RECT  0.108 97.147 30.222 97.325 ;
     RECT  151.812 96.755 152.91 97.339 ;
     RECT  151.812 97.339 152.946 97.645 ;
     RECT  149.364 96.755 149.382 97.709 ;
     RECT  33.228 93.217 33.246 97.807 ;
     RECT  41.832 97.807 41.85 97.853 ;
     RECT  150.624 97.133 150.642 97.949 ;
     RECT  31.104 96.565 31.122 97.951 ;
     RECT  32.256 96.989 32.274 97.951 ;
     RECT  151.812 97.645 153.018 97.951 ;
     RECT  146.952 96.827 147.222 98.059 ;
     RECT  151.596 97.951 153.018 98.141 ;
     RECT  148.215 96.719 148.497 98.149 ;
     RECT  148.215 98.149 148.554 98.221 ;
     RECT  151.596 98.141 152.802 98.221 ;
     RECT  148.215 98.221 148.626 98.285 ;
     RECT  151.02 98.221 152.802 98.339 ;
     RECT  146.7 98.059 147.222 98.375 ;
     RECT  149.544 98.221 150.138 98.375 ;
     RECT  0.252 97.325 30.222 98.443 ;
     RECT  146.844 98.375 147.222 98.609 ;
     RECT  151.056 98.339 152.802 98.609 ;
     RECT  149.652 98.375 150.138 98.645 ;
     RECT  48.132 94.873 48.15 98.725 ;
     RECT  150.048 98.645 150.138 98.879 ;
     RECT  31.104 97.951 32.274 98.887 ;
     RECT  58.464 94.333 58.482 98.887 ;
     RECT  154.44 95.413 154.458 98.915 ;
     RECT  58.464 98.887 58.734 98.987 ;
     RECT  63.756 98.887 63.774 98.987 ;
     RECT  38.736 98.761 38.754 98.995 ;
     RECT  152.316 98.609 152.802 98.995 ;
     RECT  58.464 98.987 58.482 99.163 ;
     RECT  54.72 99.019 54.738 99.197 ;
     RECT  152.316 98.995 153.018 99.391 ;
     RECT  150.048 98.879 150.066 99.419 ;
     RECT  0.252 98.443 30.258 99.455 ;
     RECT  151.92 99.391 153.018 99.491 ;
     RECT  148.215 98.285 148.497 99.571 ;
     RECT  151.056 98.609 151.074 99.571 ;
     RECT  153.864 99.307 153.882 99.599 ;
     RECT  58.284 99.163 58.482 99.689 ;
     RECT  149.76 99.571 149.922 99.725 ;
     RECT  150.84 99.571 151.65 99.725 ;
     RECT  154.44 99.733 154.494 99.773 ;
     RECT  30.996 98.887 32.274 99.841 ;
     RECT  40.215 95.675 41.058 99.869 ;
     RECT  58.356 99.689 58.446 99.959 ;
     RECT  30.744 99.841 32.274 99.995 ;
     RECT  148.215 99.571 148.842 100.111 ;
     RECT  0.252 99.455 29.826 100.171 ;
     RECT  150.948 99.725 151.002 100.229 ;
     RECT  148.215 100.111 149.238 100.265 ;
     RECT  152.388 99.491 153.018 100.273 ;
     RECT  0.108 100.171 29.826 100.301 ;
     RECT  152.136 100.273 153.018 100.301 ;
     RECT  34.815 91.325 35.097 100.315 ;
     RECT  37.296 93.757 37.998 100.349 ;
     RECT  34.776 100.315 35.097 100.363 ;
     RECT  34.704 100.363 35.097 100.409 ;
     RECT  146.952 98.609 147.222 100.471 ;
     RECT  58.356 99.959 58.374 100.535 ;
     RECT  152.136 100.301 152.802 100.571 ;
     RECT  0.252 100.301 29.826 100.651 ;
     RECT  152.136 100.571 152.766 100.651 ;
     RECT  37.98 100.349 37.998 100.679 ;
     RECT  150.804 100.651 150.822 100.84 ;
     RECT  151.776 100.651 152.766 100.849 ;
     RECT  150.624 100.84 150.822 100.877 ;
     RECT  154.44 99.773 154.458 101.069 ;
     RECT  61.236 94.865 62.097 101.131 ;
     RECT  48.132 98.725 48.582 101.183 ;
     RECT  0.252 100.651 29.934 101.425 ;
     RECT  149.724 101.416 149.742 101.453 ;
     RECT  146.952 100.471 147.33 101.461 ;
     RECT  151.668 100.849 152.766 101.461 ;
     RECT  37.224 101.191 37.242 101.489 ;
     RECT  33.228 97.807 33.858 101.563 ;
     RECT  34.815 100.409 35.097 101.563 ;
     RECT  61.236 101.131 62.154 101.579 ;
     RECT  146.484 101.461 147.33 101.579 ;
     RECT  150.912 101.461 152.766 101.615 ;
     RECT  63.684 99.031 63.702 101.731 ;
     RECT  148.215 100.265 148.59 101.741 ;
     RECT  0.252 101.425 30.222 101.821 ;
     RECT  31.104 99.995 32.274 101.821 ;
     RECT  142.815 96.719 143.097 101.821 ;
     RECT  149.544 101.731 149.634 101.885 ;
     RECT  150.516 101.731 150.534 101.885 ;
     RECT  153.9 101.467 153.918 101.893 ;
     RECT  151.596 101.615 152.766 101.965 ;
     RECT  142.524 101.821 143.097 101.993 ;
     RECT  153.9 101.893 154.458 102.029 ;
     RECT  149.364 102.001 149.382 102.155 ;
     RECT  151.596 101.965 153.054 102.271 ;
     RECT  0.252 101.821 32.274 102.299 ;
     RECT  0.252 102.299 29.934 102.331 ;
     RECT  146.952 101.579 147.33 102.361 ;
     RECT  0.108 102.331 29.934 102.461 ;
     RECT  151.596 102.271 153.234 102.469 ;
     RECT  146.484 102.361 147.33 102.533 ;
     RECT  151.344 102.469 153.234 102.541 ;
     RECT  41.364 102.361 41.382 102.659 ;
     RECT  151.236 102.541 153.234 102.695 ;
     RECT  40.215 99.869 40.497 102.763 ;
     RECT  40.215 102.763 41.13 102.803 ;
     RECT  146.952 102.533 147.33 102.901 ;
     RECT  148.215 101.741 148.497 102.901 ;
     RECT  151.38 102.695 153.234 102.929 ;
     RECT  33.228 101.563 35.097 102.965 ;
     RECT  151.38 102.929 153.054 102.965 ;
     RECT  33.228 102.965 33.57 103.081 ;
     RECT  154.44 102.029 154.458 103.171 ;
     RECT  30.78 102.299 32.274 103.199 ;
     RECT  38.736 98.995 39.294 103.199 ;
     RECT  146.952 102.901 148.497 103.199 ;
     RECT  153.864 103.171 154.458 103.229 ;
     RECT  0.252 102.461 29.934 103.351 ;
     RECT  40.215 102.803 40.497 103.351 ;
     RECT  148.068 103.199 148.497 103.351 ;
     RECT  150.264 102.379 150.282 103.351 ;
     RECT  148.068 103.351 148.626 103.441 ;
     RECT  149.652 103.351 150.39 103.441 ;
     RECT  152.892 102.965 152.91 103.505 ;
     RECT  148.068 103.441 150.39 103.517 ;
     RECT  151.38 102.965 152.118 103.621 ;
     RECT  151.272 103.621 152.118 103.747 ;
     RECT  148.068 103.517 148.626 103.757 ;
     RECT  149.364 103.517 150.39 103.811 ;
     RECT  0.252 103.351 29.97 103.867 ;
     RECT  61.236 101.579 62.097 103.891 ;
     RECT  63.036 101.731 63.702 103.891 ;
     RECT  151.272 103.747 152.838 104.009 ;
     RECT  39.78 103.351 40.497 104.045 ;
     RECT  146.952 103.199 147.33 104.089 ;
     RECT  33.012 103.081 33.57 104.125 ;
     RECT  34.452 102.965 35.097 104.125 ;
     RECT  150.264 103.811 150.39 104.125 ;
     RECT  151.272 104.009 152.442 104.125 ;
     RECT  61.236 103.891 63.702 104.189 ;
     RECT  146.484 104.089 147.33 104.189 ;
     RECT  33.012 104.125 35.097 104.279 ;
     RECT  149.364 103.811 149.526 104.279 ;
     RECT  150.264 104.125 152.442 104.315 ;
     RECT  0.252 103.867 30.258 104.431 ;
     RECT  31.104 103.199 32.274 104.431 ;
     RECT  154.44 103.229 154.458 104.549 ;
     RECT  150.372 104.315 152.442 104.585 ;
     RECT  43.02 96.179 43.038 104.665 ;
     RECT  150.372 104.585 150.39 104.693 ;
     RECT  43.02 104.665 43.074 104.729 ;
     RECT  151.524 104.585 152.442 104.791 ;
     RECT  43.056 104.729 43.074 104.819 ;
     RECT  146.952 104.189 147.33 104.899 ;
     RECT  148.068 103.757 148.497 104.899 ;
     RECT  40.215 104.045 40.497 104.935 ;
     RECT  154.476 104.791 154.494 104.957 ;
     RECT  149.4 104.279 149.526 104.971 ;
     RECT  151.524 104.791 152.55 104.971 ;
     RECT  86.832 105.061 86.85 105.101 ;
     RECT  144.792 104.923 144.81 105.101 ;
     RECT  85.284 105.115 85.302 105.161 ;
     RECT  39.888 104.935 40.497 105.233 ;
     RECT  151.524 104.971 152.766 105.359 ;
     RECT  152.316 105.359 152.766 105.395 ;
     RECT  154.44 105.355 154.458 105.395 ;
     RECT  149.4 104.971 149.598 105.403 ;
     RECT  152.46 105.395 152.766 105.475 ;
     RECT  150.48 105.403 150.498 105.629 ;
     RECT  149.364 105.403 149.598 105.665 ;
     RECT  0.252 104.431 32.274 105.737 ;
     RECT  0.252 105.737 31.302 105.745 ;
     RECT  152.46 105.475 152.91 105.745 ;
     RECT  153.9 105.781 153.918 105.821 ;
     RECT  151.38 105.403 151.398 105.871 ;
     RECT  0.108 105.745 31.302 105.899 ;
     RECT  149.904 105.709 150.066 105.935 ;
     RECT  33.012 104.279 33.57 106.171 ;
     RECT  34.452 104.279 35.097 106.171 ;
     RECT  152.46 105.745 152.982 106.249 ;
     RECT  0.108 105.899 30.258 106.253 ;
     RECT  152.352 106.249 152.982 106.285 ;
     RECT  151.344 105.871 151.398 106.321 ;
     RECT  152.352 106.285 153.018 106.321 ;
     RECT  150.84 106.321 153.018 106.475 ;
     RECT  149.904 105.935 149.958 106.555 ;
     RECT  151.38 106.475 153.018 106.709 ;
     RECT  45.615 2.413 45.897 106.825 ;
     RECT  56.415 92.543 56.697 106.825 ;
     RECT  67.215 2.413 67.497 106.825 ;
     RECT  78.015 2.413 78.297 106.825 ;
     RECT  88.815 2.413 89.097 106.825 ;
     RECT  99.615 2.413 99.897 106.825 ;
     RECT  110.415 2.413 110.697 106.825 ;
     RECT  121.215 2.413 121.497 106.825 ;
     RECT  132.015 2.413 132.297 106.825 ;
     RECT  142.815 101.993 143.097 106.825 ;
     RECT  151.596 106.709 153.018 106.861 ;
     RECT  45.504 106.825 45.897 106.877 ;
     RECT  56.304 106.825 56.697 106.877 ;
     RECT  67.104 106.825 67.497 106.877 ;
     RECT  77.904 106.825 78.297 106.877 ;
     RECT  88.704 106.825 89.097 106.877 ;
     RECT  99.504 106.825 99.897 106.877 ;
     RECT  110.304 106.825 110.697 106.877 ;
     RECT  121.104 106.825 121.497 106.877 ;
     RECT  131.904 106.825 132.297 106.877 ;
     RECT  142.704 106.825 143.097 106.877 ;
     RECT  41.58 104.161 41.598 106.889 ;
     RECT  149.364 106.555 149.958 107.015 ;
     RECT  154.44 106.213 154.458 107.083 ;
     RECT  153.864 107.083 154.458 107.159 ;
     RECT  149.76 107.015 149.958 107.249 ;
     RECT  146.952 104.899 148.497 107.401 ;
     RECT  146.952 107.401 148.95 107.555 ;
     RECT  149.76 107.249 149.778 107.741 ;
     RECT  38.736 103.199 38.754 107.789 ;
     RECT  151.596 106.861 153.054 107.789 ;
     RECT  150.732 107.401 150.75 107.941 ;
     RECT  150.732 107.941 150.858 108.059 ;
     RECT  150.84 108.059 150.858 108.095 ;
     RECT  151.848 107.789 152.046 108.131 ;
     RECT  146.952 107.555 148.77 108.445 ;
     RECT  149.688 107.941 149.706 108.445 ;
     RECT  32.256 105.737 32.274 108.473 ;
     RECT  48.132 101.183 48.15 108.509 ;
     RECT  146.952 108.445 149.706 108.653 ;
     RECT  0.252 106.253 30.258 108.715 ;
     RECT  149.364 108.653 149.706 108.751 ;
     RECT  151.992 108.131 152.046 108.751 ;
     RECT  152.784 107.789 153.018 108.751 ;
     RECT  0.108 108.715 30.258 108.845 ;
     RECT  151.992 108.751 153.018 108.869 ;
     RECT  149.364 108.751 150.066 108.905 ;
     RECT  149.76 108.905 150.066 109.139 ;
     RECT  47.268 95.071 47.286 109.147 ;
     RECT  33.012 106.171 35.097 109.291 ;
     RECT  61.815 104.189 63.702 109.319 ;
     RECT  32.688 109.291 35.097 109.409 ;
     RECT  58.104 106.951 58.122 109.409 ;
     RECT  149.76 109.139 149.958 109.409 ;
     RECT  152.064 108.869 153.018 109.409 ;
     RECT  149.76 109.409 149.778 109.445 ;
     RECT  54.72 109.417 54.738 109.525 ;
     RECT  31.032 105.899 31.302 109.561 ;
     RECT  150.948 109.561 151.146 109.675 ;
     RECT  54.396 109.525 54.738 109.679 ;
     RECT  54.396 109.679 54.414 109.715 ;
     RECT  40.215 105.233 40.497 109.819 ;
     RECT  144.792 109.723 144.81 109.859 ;
     RECT  31.032 109.561 31.734 109.921 ;
     RECT  150.948 109.675 151.182 109.949 ;
     RECT  150.948 109.949 150.966 109.985 ;
     RECT  31.032 109.921 31.986 109.997 ;
     RECT  146.952 108.653 148.497 110.011 ;
     RECT  152.064 109.409 152.478 110.191 ;
     RECT  33.048 109.409 35.097 110.219 ;
     RECT  146.952 110.011 148.626 110.219 ;
     RECT  146.952 110.219 148.554 110.291 ;
     RECT  149.544 110.371 150.21 110.489 ;
     RECT  149.544 110.489 149.562 110.525 ;
     RECT  0.252 108.845 30.258 110.569 ;
     RECT  0.252 110.569 30.294 110.641 ;
     RECT  31.032 109.997 31.302 110.641 ;
     RECT  146.952 110.291 148.497 110.641 ;
     RECT  33.552 110.219 33.606 110.669 ;
     RECT  69.624 94.441 69.642 110.759 ;
     RECT  34.452 110.219 35.097 110.767 ;
     RECT  146.52 110.641 148.497 110.869 ;
     RECT  146.376 110.869 148.497 110.909 ;
     RECT  142.815 106.877 143.097 111.001 ;
     RECT  63.036 109.319 63.702 111.029 ;
     RECT  154.44 107.159 154.458 111.029 ;
     RECT  151.704 110.191 153.018 111.101 ;
     RECT  142.524 111.001 143.097 111.137 ;
     RECT  151.704 111.101 152.586 111.181 ;
     RECT  34.452 110.767 35.802 111.299 ;
     RECT  151.452 111.181 152.586 111.451 ;
     RECT  47.268 109.147 47.718 111.569 ;
     RECT  151.2 111.451 152.586 111.605 ;
     RECT  153.9 111.403 153.918 111.835 ;
     RECT  151.632 111.605 152.586 111.955 ;
     RECT  146.952 110.909 148.497 111.991 ;
     RECT  48.132 111.721 48.15 112.019 ;
     RECT  153.9 111.835 154.458 112.019 ;
     RECT  146.376 111.991 148.497 112.027 ;
     RECT  80.064 111.739 80.082 112.109 ;
     RECT  146.232 112.027 148.497 112.109 ;
     RECT  151.632 111.955 153.018 112.109 ;
     RECT  33.552 110.669 33.57 112.145 ;
     RECT  149.4 111.991 149.418 112.145 ;
     RECT  142.815 111.137 143.097 112.189 ;
     RECT  33.804 112.189 33.822 112.289 ;
     RECT  142.524 112.189 143.097 112.289 ;
     RECT  146.7 112.109 148.497 112.289 ;
     RECT  146.952 112.289 148.497 112.531 ;
     RECT  47.268 111.569 47.286 112.621 ;
     RECT  63.036 111.029 63.054 112.649 ;
     RECT  144.792 112.621 144.81 112.793 ;
     RECT  151.632 112.109 152.838 112.801 ;
     RECT  34.815 111.299 35.802 112.885 ;
     RECT  45.615 106.877 45.897 112.891 ;
     RECT  56.415 106.877 56.697 112.891 ;
     RECT  67.215 106.877 67.497 112.891 ;
     RECT  78.015 106.877 78.297 112.891 ;
     RECT  150.372 111.019 150.39 112.891 ;
     RECT  34.704 112.885 35.802 112.925 ;
     RECT  80.352 112.261 80.37 112.925 ;
     RECT  45.504 112.891 45.897 112.928 ;
     RECT  56.304 112.891 56.697 112.928 ;
     RECT  67.104 112.891 67.497 112.928 ;
     RECT  77.904 112.891 78.297 112.928 ;
     RECT  151.452 112.801 152.838 113.035 ;
     RECT  39.6 109.819 40.497 113.189 ;
     RECT  146.952 112.531 148.986 113.189 ;
     RECT  151.452 113.035 153.018 113.189 ;
     RECT  150.228 112.891 150.39 113.341 ;
     RECT  0.252 110.641 31.302 113.531 ;
     RECT  149.976 113.341 150.39 113.539 ;
     RECT  149.976 113.539 150.498 113.611 ;
     RECT  149.832 113.611 150.498 113.639 ;
     RECT  39.924 113.189 40.497 113.765 ;
     RECT  146.952 113.189 148.914 113.765 ;
     RECT  0.252 113.531 30.258 113.801 ;
     RECT  154.44 112.019 154.458 113.971 ;
     RECT  52.776 113.419 52.794 113.999 ;
     RECT  154.44 113.971 154.494 114.029 ;
     RECT  152.208 113.189 153.018 114.071 ;
     RECT  146.952 113.765 148.626 114.151 ;
     RECT  146.52 114.151 148.626 114.241 ;
     RECT  149.832 113.639 150.318 114.241 ;
     RECT  151.272 113.611 151.29 114.241 ;
     RECT  152.208 114.071 152.946 114.241 ;
     RECT  31.032 113.531 31.302 114.269 ;
     RECT  146.484 114.241 148.626 114.269 ;
     RECT  149.724 114.241 150.318 114.269 ;
     RECT  0.252 113.801 28.638 114.277 ;
     RECT  146.484 114.269 148.497 114.449 ;
     RECT  31.032 114.269 31.05 114.539 ;
     RECT  149.724 114.269 149.886 114.539 ;
     RECT  149.724 114.539 149.742 114.575 ;
     RECT  151.272 114.241 152.946 114.691 ;
     RECT  32.184 114.547 32.202 114.719 ;
     RECT  0.108 114.277 28.638 114.893 ;
     RECT  46.8 112.621 47.286 115.079 ;
     RECT  45.615 112.928 45.897 115.123 ;
     RECT  46.8 115.079 46.818 115.123 ;
     RECT  150.66 114.691 152.946 115.151 ;
     RECT  146.808 114.449 148.497 115.231 ;
     RECT  72.615 93.991 72.99 115.349 ;
     RECT  146.808 115.231 148.77 115.349 ;
     RECT  154.44 114.029 154.458 115.349 ;
     RECT  146.808 115.349 148.497 115.357 ;
     RECT  45.615 115.123 46.818 115.385 ;
     RECT  150.66 115.151 151.074 115.501 ;
     RECT  149.544 115.501 149.562 115.591 ;
     RECT  146.304 115.357 148.497 115.627 ;
     RECT  149.328 115.591 149.562 115.655 ;
     RECT  150.48 115.501 151.074 115.663 ;
     RECT  146.16 115.627 148.497 115.709 ;
     RECT  48.168 115.393 48.186 115.735 ;
     RECT  152.064 115.151 152.946 115.735 ;
     RECT  154.476 115.663 154.494 115.757 ;
     RECT  150.444 115.663 151.074 115.889 ;
     RECT  149.328 115.655 149.346 115.925 ;
     RECT  29.415 113.801 30.258 116.041 ;
     RECT  34.815 112.925 35.802 116.041 ;
     RECT  29.415 116.041 30.798 116.159 ;
     RECT  34.815 116.041 35.874 116.159 ;
     RECT  47.916 115.735 48.186 116.167 ;
     RECT  47.916 116.167 48.51 116.231 ;
     RECT  48.492 116.231 48.51 116.339 ;
     RECT  34.815 116.159 35.73 116.429 ;
     RECT  150.696 115.889 151.074 116.581 ;
     RECT  152.064 115.735 153.018 116.581 ;
     RECT  146.808 115.709 148.497 116.635 ;
     RECT  150.696 116.581 153.054 116.669 ;
     RECT  146.808 116.635 148.842 116.699 ;
     RECT  37.008 116.401 37.026 116.707 ;
     RECT  36.936 116.707 37.026 116.815 ;
     RECT  54.288 109.795 54.306 116.851 ;
     RECT  54.288 116.851 54.702 116.879 ;
     RECT  54.684 116.879 54.702 117.149 ;
     RECT  33.012 117.121 33.03 117.239 ;
     RECT  151.344 116.669 153.054 117.239 ;
     RECT  36.936 116.815 37.062 117.355 ;
     RECT  149.904 116.815 149.922 117.391 ;
     RECT  0.252 114.893 28.638 117.451 ;
     RECT  142.815 112.289 143.097 117.517 ;
     RECT  149.616 117.391 150.318 117.545 ;
     RECT  0.108 117.451 28.638 117.581 ;
     RECT  36.756 117.355 37.062 117.661 ;
     RECT  121.215 106.877 121.497 117.661 ;
     RECT  151.344 117.239 152.802 117.661 ;
     RECT  142.524 117.517 143.097 117.689 ;
     RECT  31.896 117.283 31.914 117.779 ;
     RECT  36.36 117.661 37.062 117.815 ;
     RECT  31.716 117.895 31.734 118.049 ;
     RECT  0.252 117.581 28.638 118.201 ;
     RECT  29.415 116.159 30.258 118.201 ;
     RECT  151.272 117.661 152.802 118.201 ;
     RECT  150.336 118.201 150.354 118.253 ;
     RECT  146.808 116.699 148.497 118.315 ;
     RECT  44.784 117.931 44.802 118.319 ;
     RECT  146.808 118.315 148.986 118.355 ;
     RECT  151.272 118.201 152.946 118.355 ;
     RECT  40.215 113.765 40.497 118.435 ;
     RECT  0.252 118.201 30.258 118.561 ;
     RECT  0.252 118.561 30.294 118.603 ;
     RECT  150.804 118.471 150.822 118.625 ;
     RECT  45.615 115.385 46.386 118.705 ;
     RECT  55.548 117.121 55.566 118.895 ;
     RECT  36.36 117.815 36.378 119.039 ;
     RECT  151.812 118.355 152.946 119.101 ;
     RECT  154.44 116.131 154.458 119.101 ;
     RECT  45.108 118.705 46.386 119.129 ;
     RECT  151.74 119.101 152.946 119.129 ;
     RECT  154.44 119.101 154.494 119.213 ;
     RECT  152.532 119.129 152.946 119.245 ;
     RECT  146.808 118.355 148.59 119.281 ;
     RECT  0.252 118.603 30.798 119.399 ;
     RECT  146.808 119.281 148.77 119.399 ;
     RECT  39.6 118.435 40.497 119.479 ;
     RECT  149.868 119.101 149.886 119.551 ;
     RECT  151.74 119.129 151.794 119.551 ;
     RECT  39.6 119.479 41.022 119.579 ;
     RECT  152.532 119.245 153.018 119.785 ;
     RECT  149.724 119.551 149.886 119.899 ;
     RECT  149.724 119.899 150.174 119.975 ;
     RECT  47.808 119.911 47.826 120.055 ;
     RECT  45.615 119.129 46.386 120.119 ;
     RECT  0.252 119.399 30.69 120.187 ;
     RECT  149.724 119.975 149.994 120.209 ;
     RECT  149.724 120.209 149.922 120.217 ;
     RECT  151.056 119.551 151.794 120.245 ;
     RECT  152.532 119.785 153.054 120.253 ;
     RECT  149.22 120.217 149.922 120.269 ;
     RECT  33.048 119.983 33.066 120.289 ;
     RECT  151.812 120.253 153.054 120.475 ;
     RECT  32.364 120.289 33.066 120.479 ;
     RECT  154.44 119.213 154.458 120.479 ;
     RECT  37.98 119.515 37.998 120.515 ;
     RECT  0.252 120.187 30.798 120.551 ;
     RECT  39.6 119.579 40.497 120.631 ;
     RECT  146.808 119.399 148.497 120.631 ;
     RECT  149.22 120.269 149.238 120.631 ;
     RECT  151.812 120.475 153.594 120.631 ;
     RECT  47.484 120.055 47.826 120.749 ;
     RECT  151.02 120.361 151.038 120.749 ;
     RECT  0.252 120.551 30.69 120.757 ;
     RECT  146.808 120.631 149.238 120.785 ;
     RECT  151.812 120.631 153.918 120.821 ;
     RECT  0.108 120.757 30.69 120.941 ;
     RECT  153.9 120.821 153.918 120.941 ;
     RECT  151.812 120.821 153.018 121.055 ;
     RECT  146.808 120.785 148.95 121.289 ;
     RECT  152.064 121.055 153.018 121.631 ;
     RECT  0.252 120.941 30.69 121.829 ;
     RECT  34.815 116.429 35.622 121.963 ;
     RECT  45.615 120.119 45.897 121.963 ;
     RECT  56.415 112.928 56.697 121.963 ;
     RECT  67.215 112.928 67.497 121.963 ;
     RECT  78.015 112.928 78.297 121.963 ;
     RECT  88.815 106.877 89.097 121.963 ;
     RECT  99.615 106.877 99.897 121.963 ;
     RECT  110.415 106.877 110.697 121.963 ;
     RECT  121.215 117.661 121.986 121.963 ;
     RECT  132.015 106.877 132.297 121.963 ;
     RECT  142.815 117.689 143.097 121.963 ;
     RECT  146.808 121.289 148.497 121.963 ;
     RECT  34.704 121.963 35.622 122.009 ;
     RECT  45.504 121.963 45.897 122.009 ;
     RECT  56.304 121.963 56.697 122.009 ;
     RECT  77.904 121.963 78.297 122.009 ;
     RECT  88.704 121.963 89.097 122.009 ;
     RECT  99.504 121.963 99.897 122.009 ;
     RECT  110.304 121.963 110.697 122.009 ;
     RECT  121.104 121.963 121.986 122.009 ;
     RECT  131.904 121.963 132.297 122.009 ;
     RECT  150.336 122.059 150.354 122.071 ;
     RECT  151.128 121.675 151.146 122.071 ;
     RECT  31.536 121.531 31.554 122.099 ;
     RECT  60.876 120.523 60.894 122.099 ;
     RECT  150.336 122.071 151.146 122.215 ;
     RECT  152.064 121.631 152.802 122.215 ;
     RECT  61.815 109.319 62.097 122.251 ;
     RECT  150.336 122.215 152.802 122.485 ;
     RECT  34.815 122.009 35.622 122.521 ;
     RECT  150.336 122.485 152.946 122.549 ;
     RECT  0.252 121.829 30.294 122.639 ;
     RECT  150.444 122.549 152.946 122.639 ;
     RECT  67.104 121.963 67.497 122.647 ;
     RECT  146.484 121.963 148.497 122.647 ;
     RECT  155.412 122.521 155.43 122.669 ;
     RECT  34.815 122.521 35.694 122.675 ;
     RECT  149.22 122.521 149.238 122.675 ;
     RECT  142.704 121.963 143.097 122.719 ;
     RECT  64.152 122.611 64.17 122.747 ;
     RECT  66.744 122.647 67.497 122.747 ;
     RECT  146.376 122.647 148.497 122.791 ;
     RECT  142.56 122.719 143.097 122.819 ;
     RECT  150.48 122.639 150.966 122.909 ;
     RECT  151.884 122.639 152.946 122.909 ;
     RECT  29.34 122.639 30.294 122.945 ;
     RECT  61.164 122.251 62.097 122.945 ;
     RECT  146.196 122.791 148.497 122.957 ;
     RECT  0.252 122.639 28.602 122.971 ;
     RECT  150.48 122.909 150.534 123.053 ;
     RECT  0.108 122.971 28.602 123.101 ;
     RECT  146.736 122.957 148.497 123.179 ;
     RECT  39.384 120.631 40.497 123.449 ;
     RECT  77.076 123.403 77.094 123.449 ;
     RECT  74.664 123.403 74.682 123.533 ;
     RECT  76.752 123.529 76.77 123.581 ;
     RECT  42.228 117.589 42.246 123.601 ;
     RECT  53.244 123.601 53.262 123.755 ;
     RECT  30.744 123.457 30.762 123.821 ;
     RECT  146.808 123.179 148.497 123.871 ;
     RECT  149.364 123.835 149.382 123.871 ;
     RECT  150.516 123.053 150.534 123.871 ;
     RECT  151.884 122.909 152.91 123.871 ;
     RECT  146.808 123.871 149.382 123.899 ;
     RECT  47.808 120.749 47.826 123.989 ;
     RECT  151.452 123.871 152.91 123.989 ;
     RECT  154.44 121.339 154.458 123.989 ;
     RECT  61.815 122.945 62.097 123.997 ;
     RECT  43.776 123.961 43.794 124.013 ;
     RECT  146.808 123.899 148.806 124.025 ;
     RECT  150.3 123.871 150.534 124.025 ;
     RECT  61.344 123.997 62.097 124.105 ;
     RECT  45.615 122.009 45.897 124.141 ;
     RECT  61.092 124.105 62.097 124.141 ;
     RECT  60.984 124.141 62.097 124.219 ;
     RECT  42.156 123.601 42.246 124.259 ;
     RECT  60.912 124.219 62.097 124.259 ;
     RECT  42.156 124.259 42.174 124.331 ;
     RECT  154.476 124.231 154.494 124.397 ;
     RECT  142.815 122.819 143.097 124.411 ;
     RECT  146.052 124.375 146.07 124.411 ;
     RECT  146.808 124.025 148.497 124.411 ;
     RECT  150.444 124.025 150.534 124.411 ;
     RECT  42.084 124.339 42.102 124.439 ;
     RECT  142.524 124.411 143.097 124.529 ;
     RECT  146.052 124.411 148.497 124.529 ;
     RECT  150.444 124.411 150.93 124.529 ;
     RECT  45.324 124.141 45.897 124.565 ;
     RECT  146.052 124.529 146.07 124.829 ;
     RECT  150.732 124.529 150.93 124.835 ;
     RECT  151.776 123.989 152.91 124.915 ;
     RECT  29.34 122.945 29.826 124.979 ;
     RECT  151.776 124.915 153.054 125.105 ;
     RECT  146.808 124.529 148.497 125.221 ;
     RECT  152.784 125.105 153.054 125.221 ;
     RECT  37.692 125.221 37.71 125.311 ;
     RECT  36.972 125.311 37.71 125.339 ;
     RECT  49.716 120.793 49.734 125.375 ;
     RECT  151.776 125.105 151.866 125.491 ;
     RECT  36.972 125.339 36.99 125.501 ;
     RECT  49.968 125.491 49.986 125.609 ;
     RECT  151.344 125.491 151.866 125.609 ;
     RECT  146.808 125.221 148.986 125.707 ;
     RECT  150.084 125.383 150.102 125.761 ;
     RECT  39.384 123.449 39.402 125.789 ;
     RECT  146.772 125.707 148.986 125.851 ;
     RECT  149.76 125.761 150.462 125.851 ;
     RECT  146.772 125.851 150.462 125.879 ;
     RECT  154.44 124.795 154.458 125.879 ;
     RECT  146.808 125.879 150.462 125.915 ;
     RECT  151.56 125.609 151.866 126.031 ;
     RECT  152.784 125.221 153.234 126.031 ;
     RECT  151.56 126.031 153.234 126.091 ;
     RECT  151.56 126.091 153.918 126.149 ;
     RECT  151.56 126.149 153.018 126.185 ;
     RECT  153.9 126.149 153.918 126.329 ;
     RECT  150.444 125.915 150.462 126.419 ;
     RECT  146.808 125.915 149.67 126.455 ;
     RECT  0.252 123.101 28.602 126.523 ;
     RECT  155.412 126.391 155.43 126.557 ;
     RECT  0.108 126.523 28.602 126.653 ;
     RECT  151.56 126.185 152.874 126.689 ;
     RECT  151.56 126.689 152.55 126.805 ;
     RECT  45.396 124.565 45.897 126.841 ;
     RECT  150.84 126.805 152.55 126.845 ;
     RECT  43.668 126.763 43.686 126.869 ;
     RECT  151.02 126.845 152.55 126.959 ;
     RECT  151.272 126.959 152.55 126.995 ;
     RECT  146.808 126.455 149.166 127.195 ;
     RECT  30.78 127.075 30.798 127.229 ;
     RECT  34.815 122.675 35.097 127.471 ;
     RECT  43.308 127.381 43.326 127.499 ;
     RECT  34.704 127.471 35.097 127.517 ;
     RECT  45.288 126.841 45.897 127.535 ;
     RECT  146.808 127.195 149.382 127.543 ;
     RECT  38.772 126.667 38.79 127.613 ;
     RECT  152.532 126.995 152.55 127.615 ;
     RECT  43.056 127.579 43.074 127.616 ;
     RECT  41.94 127.339 41.958 127.651 ;
     RECT  30.6 127.381 30.618 127.679 ;
     RECT  45.36 127.535 45.897 127.679 ;
     RECT  146.484 127.543 149.382 127.679 ;
     RECT  150.48 127.651 150.498 127.769 ;
     RECT  29.415 124.979 29.826 127.805 ;
     RECT  146.808 127.679 149.382 127.805 ;
     RECT  152.532 127.615 152.946 127.885 ;
     RECT  151.272 126.995 151.398 127.921 ;
     RECT  152.532 127.885 153.018 127.921 ;
     RECT  146.808 127.805 148.662 128.039 ;
     RECT  150.624 127.921 153.018 128.039 ;
     RECT  151.596 128.039 153.018 128.191 ;
     RECT  41.94 127.651 42.21 128.309 ;
     RECT  154.44 126.955 154.458 128.309 ;
     RECT  150.624 128.039 150.822 128.345 ;
     RECT  34.815 127.517 35.097 128.425 ;
     RECT  150.732 128.345 150.822 128.579 ;
     RECT  41.94 128.309 41.958 128.615 ;
     RECT  146.808 128.039 148.497 128.623 ;
     RECT  151.596 128.191 153.234 128.683 ;
     RECT  45.396 127.679 45.897 128.717 ;
     RECT  0.252 126.653 28.602 128.821 ;
     RECT  34.164 128.425 35.097 128.849 ;
     RECT  33.444 128.92 33.462 128.957 ;
     RECT  146.736 128.623 148.497 128.971 ;
     RECT  44.028 128.695 44.046 128.993 ;
     RECT  149.76 128.965 149.778 129.001 ;
     RECT  151.596 128.683 153.522 129.001 ;
     RECT  151.56 129.001 153.522 129.119 ;
     RECT  150.732 128.579 150.75 129.155 ;
     RECT  151.632 129.119 153.522 129.227 ;
     RECT  146.736 128.971 148.626 129.271 ;
     RECT  149.76 129.001 149.886 129.271 ;
     RECT  151.632 129.227 153.054 129.389 ;
     RECT  149.76 129.271 150.462 129.497 ;
     RECT  146.736 129.271 148.806 129.541 ;
     RECT  151.632 129.389 152.802 129.731 ;
     RECT  146.736 129.541 149.418 129.929 ;
     RECT  146.736 129.929 149.346 129.965 ;
     RECT  29.415 127.805 29.697 130.171 ;
     RECT  150.336 129.497 150.462 130.315 ;
     RECT  151.632 129.731 152.73 130.351 ;
     RECT  154.44 129.115 154.458 130.411 ;
     RECT  151.524 130.351 152.73 130.469 ;
     RECT  34.815 128.849 35.097 130.477 ;
     RECT  151.524 130.469 151.542 130.505 ;
     RECT  29.415 130.171 29.826 130.855 ;
     RECT  152.352 130.469 152.73 130.855 ;
     RECT  150.336 130.315 150.606 130.891 ;
     RECT  29.415 130.855 29.898 131.009 ;
     RECT  150.264 130.891 150.966 131.009 ;
     RECT  146.736 129.965 149.094 131.017 ;
     RECT  150.264 131.009 150.498 131.017 ;
     RECT  41.292 131.017 41.31 131.069 ;
     RECT  152.352 130.855 153.054 131.251 ;
     RECT  146.736 131.017 150.498 131.279 ;
     RECT  151.92 131.251 153.054 131.279 ;
     RECT  146.736 131.279 150.462 131.521 ;
     RECT  151.92 131.279 152.946 131.521 ;
     RECT  37.008 131.431 37.026 131.549 ;
     RECT  146.232 131.521 150.462 131.549 ;
     RECT  34.815 130.477 35.622 131.557 ;
     RECT  146.232 131.549 150.354 131.557 ;
     RECT  34.815 131.557 35.946 131.693 ;
     RECT  146.088 131.557 150.354 131.729 ;
     RECT  154.404 130.411 154.458 131.741 ;
     RECT  151.344 131.521 152.946 131.855 ;
     RECT  78.015 122.009 78.297 132.061 ;
     RECT  77.616 132.061 78.297 132.088 ;
     RECT  77.4 132.088 78.297 132.125 ;
     RECT  151.704 131.855 152.946 132.125 ;
     RECT  29.415 131.009 29.697 132.205 ;
     RECT  77.616 132.125 78.297 132.221 ;
     RECT  153.036 132.205 153.054 132.359 ;
     RECT  146.736 131.729 150.354 132.511 ;
     RECT  29.415 132.205 30.222 132.539 ;
     RECT  0.252 128.821 28.638 132.629 ;
     RECT  151.704 132.125 151.722 132.629 ;
     RECT  146.736 132.511 150.57 132.665 ;
     RECT  152.892 132.871 152.91 133.015 ;
     RECT  0.252 132.629 28.602 133.079 ;
     RECT  151.776 133.015 152.91 133.141 ;
     RECT  43.452 132.511 43.47 133.205 ;
     RECT  146.736 132.665 150.354 133.439 ;
     RECT  34.815 131.693 35.622 133.475 ;
     RECT  154.44 131.741 154.458 133.475 ;
     RECT  146.736 133.439 149.13 133.483 ;
     RECT  150.048 133.439 150.354 133.583 ;
     RECT  29.415 132.539 29.697 133.591 ;
     RECT  94.215 2.413 94.497 133.591 ;
     RECT  150.3 133.583 150.354 133.591 ;
     RECT  151.776 133.141 153.018 133.591 ;
     RECT  29.415 133.591 29.826 133.745 ;
     RECT  150.3 133.591 153.018 133.861 ;
     RECT  150.3 133.861 153.234 133.867 ;
     RECT  93.6 133.591 94.497 134.123 ;
     RECT  34.815 133.475 35.097 134.131 ;
     RECT  43.704 133.321 43.722 134.159 ;
     RECT  150.3 133.867 153.918 134.159 ;
     RECT  34.776 134.131 35.097 134.249 ;
     RECT  146.484 133.483 149.13 134.299 ;
     RECT  150.3 134.159 153.342 134.401 ;
     RECT  52.668 134.401 52.686 134.519 ;
     RECT  146.232 134.299 149.13 134.519 ;
     RECT  149.868 134.401 153.342 134.519 ;
     RECT  0.396 133.079 28.602 134.555 ;
     RECT  149.868 134.519 150.354 134.555 ;
     RECT  152.172 134.519 152.73 134.789 ;
     RECT  28.512 134.555 28.602 134.933 ;
     RECT  146.736 134.519 149.13 134.941 ;
     RECT  53.46 135.067 53.478 135.329 ;
     RECT  152.352 134.789 152.73 135.445 ;
     RECT  152.352 135.445 153.018 135.481 ;
     RECT  152.352 135.481 153.342 135.571 ;
     RECT  151.272 134.519 151.29 135.595 ;
     RECT  152.244 135.571 153.342 135.629 ;
     RECT  152.244 135.629 153.054 135.643 ;
     RECT  54.936 135.481 54.954 135.677 ;
     RECT  151.128 135.595 151.29 135.751 ;
     RECT  152.208 135.643 153.054 135.751 ;
     RECT  150.336 134.555 150.354 135.835 ;
     RECT  146.736 134.941 149.382 135.841 ;
     RECT  150.228 135.835 150.354 135.841 ;
     RECT  151.128 135.751 151.326 136.049 ;
     RECT  146.736 135.841 150.354 136.111 ;
     RECT  151.128 136.049 151.254 136.111 ;
     RECT  152.1 135.751 153.054 136.111 ;
     RECT  146.736 136.111 151.254 136.139 ;
     RECT  146.736 136.139 151.182 136.175 ;
     RECT  146.736 136.175 150.894 136.211 ;
     RECT  152.064 136.111 153.054 136.211 ;
     RECT  28.584 134.933 28.602 136.381 ;
     RECT  29.415 133.745 29.697 136.381 ;
     RECT  152.136 136.211 153.054 136.409 ;
     RECT  28.584 136.381 29.697 136.715 ;
     RECT  146.736 136.211 149.022 136.831 ;
     RECT  0.396 134.555 27.702 136.891 ;
     RECT  0.108 136.891 27.702 137.069 ;
     RECT  149.904 136.211 150.894 137.093 ;
     RECT  150.012 137.093 150.894 137.101 ;
     RECT  152.136 136.409 153.018 137.101 ;
     RECT  28.584 136.715 28.602 137.219 ;
     RECT  54.144 136.489 54.162 137.255 ;
     RECT  150.012 137.101 153.018 137.255 ;
     RECT  30.456 137.101 30.474 137.489 ;
     RECT  150.012 137.255 150.966 137.489 ;
     RECT  146.484 136.831 149.022 137.669 ;
     RECT  151.74 137.255 153.018 137.669 ;
     RECT  35.892 134.491 35.91 137.795 ;
     RECT  150.336 137.489 150.966 137.795 ;
     RECT  55.404 137.191 55.422 138.029 ;
     RECT  151.74 137.669 152.946 138.029 ;
     RECT  33.876 134.635 33.894 138.065 ;
     RECT  34.815 134.249 35.097 138.181 ;
     RECT  0.396 137.069 27.702 138.187 ;
     RECT  36.144 137.911 36.162 138.209 ;
     RECT  151.74 138.029 152.874 138.271 ;
     RECT  0.108 138.187 27.702 138.365 ;
     RECT  34.128 138.181 35.097 138.839 ;
     RECT  151.704 138.271 152.874 138.919 ;
     RECT  151.56 138.919 152.874 138.991 ;
     RECT  150.336 137.795 150.498 139.051 ;
     RECT  151.452 138.991 152.874 139.081 ;
     RECT  150.192 139.051 150.498 139.085 ;
     RECT  154.44 134.731 154.458 139.109 ;
     RECT  151.452 139.081 153.018 139.181 ;
     RECT  153.864 139.483 153.882 139.523 ;
     RECT  151.452 139.181 152.874 139.531 ;
     RECT  151.236 139.531 152.874 139.621 ;
     RECT  0.396 138.365 27.702 139.649 ;
     RECT  151.164 139.621 152.874 139.661 ;
     RECT  151.236 139.661 152.874 139.685 ;
     RECT  0.396 139.649 26.226 139.721 ;
     RECT  146.736 137.669 149.022 139.801 ;
     RECT  150.192 139.085 150.354 139.801 ;
     RECT  151.812 139.685 152.874 139.919 ;
     RECT  152.172 139.919 152.874 139.955 ;
     RECT  27.036 139.649 27.702 140.063 ;
     RECT  146.736 139.801 150.354 140.225 ;
     RECT  45.54 128.717 45.897 140.459 ;
     RECT  154.44 139.915 154.458 140.459 ;
     RECT  152.208 139.955 152.874 140.539 ;
     RECT  0.396 139.721 25.938 140.567 ;
     RECT  152.208 140.539 152.91 140.575 ;
     RECT  0.396 140.567 25.47 140.621 ;
     RECT  0.396 140.621 24.426 140.765 ;
     RECT  0.396 140.765 23.238 140.773 ;
     RECT  0.108 140.773 23.238 140.801 ;
     RECT  0.108 140.801 23.166 140.813 ;
     RECT  154.476 140.611 154.494 140.813 ;
     RECT  0.396 140.813 23.166 140.909 ;
     RECT  152.208 140.575 153.054 140.971 ;
     RECT  0.396 140.909 23.13 140.999 ;
     RECT  152.136 140.971 153.054 140.999 ;
     RECT  25.164 140.621 25.47 141.035 ;
     RECT  151.2 140.611 151.362 141.151 ;
     RECT  152.136 140.999 152.154 141.151 ;
     RECT  151.164 141.151 152.154 141.305 ;
     RECT  146.736 140.225 149.022 141.355 ;
     RECT  150.192 140.225 150.354 141.389 ;
     RECT  32.004 128.695 32.022 141.575 ;
     RECT  146.736 141.355 149.31 141.691 ;
     RECT  150.336 141.389 150.354 141.691 ;
     RECT  25.452 141.035 25.47 141.845 ;
     RECT  0.396 140.999 23.058 141.881 ;
     RECT  150.336 141.691 151.074 142.195 ;
     RECT  151.992 141.305 152.154 142.195 ;
     RECT  146.736 141.691 149.454 142.231 ;
     RECT  150.336 142.195 151.146 142.231 ;
     RECT  146.736 142.231 151.146 142.349 ;
     RECT  146.736 142.349 150.858 142.355 ;
     RECT  151.992 142.195 152.766 142.465 ;
     RECT  0.396 141.881 22.986 142.493 ;
     RECT  146.736 142.355 149.094 142.493 ;
     RECT  149.832 142.355 150.858 142.493 ;
     RECT  0.396 142.493 22.914 142.507 ;
     RECT  149.832 142.493 149.922 142.619 ;
     RECT  0.108 142.507 22.914 142.685 ;
     RECT  146.736 142.493 149.022 142.691 ;
     RECT  149.832 142.619 149.886 142.691 ;
     RECT  151.992 142.465 152.874 142.771 ;
     RECT  151.884 142.771 152.874 142.889 ;
     RECT  150.84 142.493 150.858 142.925 ;
     RECT  151.884 142.889 152.262 143.275 ;
     RECT  146.736 142.691 148.914 143.309 ;
     RECT  24.015 140.765 24.426 143.311 ;
     RECT  151.704 143.275 152.262 143.311 ;
     RECT  154.44 141.211 154.458 143.429 ;
     RECT  146.736 143.309 148.842 143.465 ;
     RECT  149.868 142.691 149.886 143.465 ;
     RECT  153 143.005 153.018 143.545 ;
     RECT  0.396 142.685 22.914 143.699 ;
     RECT  153 143.545 153.054 143.699 ;
     RECT  151.272 143.311 152.262 143.707 ;
     RECT  25.596 141.961 25.614 143.779 ;
     RECT  25.596 143.779 25.758 143.807 ;
     RECT  151.02 143.707 152.262 143.815 ;
     RECT  151.02 143.815 152.946 143.851 ;
     RECT  144.792 143.707 144.81 143.879 ;
     RECT  153.864 143.803 153.882 143.879 ;
     RECT  24.015 143.311 24.534 144.005 ;
     RECT  25.668 143.807 25.758 144.005 ;
     RECT  149.904 143.851 152.946 144.005 ;
     RECT  150.876 144.005 152.946 144.173 ;
     RECT  151.56 144.173 152.946 144.239 ;
     RECT  149.904 144.005 149.922 144.545 ;
     RECT  0.396 143.699 22.41 144.661 ;
     RECT  25.92 144.121 25.938 144.779 ;
     RECT  154.44 144.235 154.458 144.779 ;
     RECT  0.396 144.661 22.842 144.815 ;
     RECT  148.215 143.465 148.842 144.895 ;
     RECT  24.015 144.005 24.426 144.931 ;
     RECT  148.215 144.895 148.986 144.941 ;
     RECT  142.815 124.529 143.097 145.021 ;
     RECT  150.696 144.751 150.714 145.021 ;
     RECT  151.56 144.239 151.578 145.021 ;
     RECT  23.76 144.931 24.426 145.049 ;
     RECT  153.864 145.093 153.882 145.133 ;
     RECT  152.388 144.239 152.658 145.165 ;
     RECT  142.524 145.021 143.097 145.193 ;
     RECT  146.736 143.465 147.474 145.201 ;
     RECT  148.215 144.941 148.842 145.201 ;
     RECT  150.696 145.021 151.578 145.291 ;
     RECT  152.316 145.165 152.658 145.291 ;
     RECT  33.624 144.283 33.642 145.319 ;
     RECT  150.696 145.291 152.658 145.319 ;
     RECT  121.215 122.009 121.986 145.327 ;
     RECT  146.736 145.201 148.842 145.355 ;
     RECT  32.256 141.691 32.274 145.499 ;
     RECT  150.264 145.471 150.282 145.589 ;
     RECT  151.056 145.319 152.658 145.705 ;
     RECT  0.396 144.815 22.41 145.741 ;
     RECT  0.396 145.741 22.806 145.859 ;
     RECT  24.015 145.049 24.426 145.859 ;
     RECT  151.056 145.705 153.018 145.895 ;
     RECT  0.396 145.859 22.41 145.963 ;
     RECT  148.215 145.355 148.842 146.137 ;
     RECT  151.128 145.895 153.018 146.201 ;
     RECT  148.215 146.137 148.878 146.245 ;
     RECT  24.015 145.859 24.297 146.551 ;
     RECT  23.58 146.551 24.297 146.669 ;
     RECT  148.215 146.245 148.914 146.779 ;
     RECT  149.904 145.741 150.066 146.779 ;
     RECT  148.215 146.779 150.066 146.819 ;
     RECT  149.904 146.819 150.066 146.821 ;
     RECT  151.128 146.201 152.802 146.821 ;
     RECT  0.144 145.963 22.41 146.827 ;
     RECT  27.036 140.063 27.378 146.911 ;
     RECT  28.152 141.151 28.17 146.911 ;
     RECT  146.736 145.355 147.474 146.939 ;
     RECT  0.108 146.827 22.41 147.005 ;
     RECT  0.396 147.005 22.41 147.047 ;
     RECT  149.904 146.821 152.802 147.055 ;
     RECT  27.036 146.911 28.17 147.091 ;
     RECT  26.784 147.091 28.17 147.209 ;
     RECT  149.904 147.055 153.054 147.209 ;
     RECT  25.092 146.749 25.11 147.245 ;
     RECT  150.48 147.209 150.858 147.251 ;
     RECT  0.396 147.047 21.834 147.281 ;
     RECT  0.396 147.281 21.798 147.479 ;
     RECT  27.324 147.209 28.17 147.757 ;
     RECT  148.215 146.819 148.878 147.757 ;
     RECT  23.652 146.669 24.297 147.785 ;
     RECT  27.324 147.757 28.53 147.785 ;
     RECT  28.152 147.785 28.53 147.929 ;
     RECT  150.48 147.251 150.606 148.171 ;
     RECT  149.868 148.171 150.606 148.205 ;
     RECT  146.736 146.939 147.402 148.261 ;
     RECT  28.152 147.929 28.17 148.289 ;
     RECT  149.868 148.205 150.03 148.289 ;
     RECT  149.868 148.289 149.886 148.325 ;
     RECT  148.215 147.757 149.022 148.441 ;
     RECT  148.215 148.441 149.778 148.595 ;
     RECT  151.704 147.209 153.018 148.675 ;
     RECT  151.704 148.675 153.054 148.711 ;
     RECT  27.324 147.785 27.378 148.937 ;
     RECT  146.484 148.261 147.402 149.009 ;
     RECT  150.732 148.981 150.75 149.135 ;
     RECT  151.56 148.711 153.054 149.369 ;
     RECT  148.215 148.595 148.95 149.377 ;
     RECT  149.76 148.595 149.778 149.377 ;
     RECT  152.424 149.369 153.054 149.639 ;
     RECT  29.415 136.715 29.697 149.755 ;
     RECT  151.56 149.369 151.614 149.791 ;
     RECT  29.196 149.755 29.697 149.909 ;
     RECT  151.056 149.791 151.614 149.945 ;
     RECT  27.36 148.937 27.378 150.179 ;
     RECT  0.396 147.479 21.762 150.187 ;
     RECT  146.736 149.009 147.402 150.295 ;
     RECT  0.108 150.187 21.762 150.317 ;
     RECT  29.268 149.909 29.697 150.331 ;
     RECT  148.215 149.377 149.778 150.331 ;
     RECT  151.056 149.945 151.074 150.331 ;
     RECT  152.424 149.639 153.018 150.331 ;
     RECT  146.736 150.295 147.474 150.449 ;
     RECT  146.736 150.449 147.33 150.472 ;
     RECT  29.268 150.331 30.33 150.485 ;
     RECT  148.215 150.331 151.074 150.485 ;
     RECT  30.564 150.601 30.582 150.719 ;
     RECT  146.736 150.472 147.294 150.727 ;
     RECT  29.268 150.485 29.697 150.755 ;
     RECT  148.215 150.485 149.886 150.755 ;
     RECT  151.056 150.485 151.074 150.871 ;
     RECT  152.28 150.331 153.018 150.871 ;
     RECT  146.484 150.727 147.294 150.899 ;
     RECT  148.215 150.755 149.778 150.989 ;
     RECT  148.215 150.989 149.634 151.037 ;
     RECT  151.056 150.871 153.018 151.375 ;
     RECT  0.396 150.317 21.762 151.387 ;
     RECT  151.056 151.375 153.054 151.439 ;
     RECT  0.108 151.387 21.762 151.613 ;
     RECT  148.215 151.037 149.526 151.799 ;
     RECT  151.128 151.439 153.054 151.799 ;
     RECT  148.215 151.799 149.382 151.951 ;
     RECT  148.032 151.951 149.382 151.997 ;
     RECT  0.396 151.613 21.762 152.069 ;
     RECT  148.032 151.997 149.13 152.105 ;
     RECT  150.3 151.951 150.318 152.105 ;
     RECT  151.128 151.799 153.018 152.375 ;
     RECT  22.5 152.149 22.518 152.491 ;
     RECT  22.5 152.491 22.77 152.609 ;
     RECT  150.804 152.491 150.858 152.609 ;
     RECT  22.5 152.609 22.518 152.645 ;
     RECT  154.44 145.531 154.458 152.689 ;
     RECT  151.596 152.375 153.018 152.725 ;
     RECT  148.215 152.105 149.13 152.789 ;
     RECT  154.44 152.689 154.494 152.909 ;
     RECT  0.396 152.069 21.366 152.987 ;
     RECT  151.596 152.725 153.054 153.031 ;
     RECT  149.904 152.761 149.922 153.101 ;
     RECT  0.396 152.987 21.222 153.149 ;
     RECT  151.596 153.031 153.162 153.149 ;
     RECT  146.736 150.899 147.294 153.157 ;
     RECT  148.215 152.789 148.95 153.157 ;
     RECT  150.84 152.609 150.858 153.301 ;
     RECT  151.596 153.149 153.054 153.301 ;
     RECT  150.84 153.301 153.054 153.329 ;
     RECT  150.84 153.329 152.73 153.419 ;
     RECT  146.736 153.157 148.95 153.571 ;
     RECT  146.736 153.571 149.742 153.689 ;
     RECT  153.864 153.307 153.882 153.739 ;
     RECT  121.215 145.327 122.382 153.883 ;
     RECT  110.415 122.009 110.697 153.925 ;
     RECT  121.104 153.883 122.382 153.925 ;
     RECT  88.815 122.009 89.097 153.931 ;
     RECT  99.615 122.009 99.897 153.931 ;
     RECT  132.015 122.009 132.297 153.931 ;
     RECT  142.815 145.193 143.097 153.931 ;
     RECT  146.736 153.689 146.934 153.931 ;
     RECT  110.304 153.925 110.697 153.965 ;
     RECT  120.96 153.925 122.382 153.965 ;
     RECT  88.704 153.931 89.097 153.968 ;
     RECT  99.504 153.931 99.897 153.968 ;
     RECT  131.904 153.931 132.297 153.968 ;
     RECT  142.704 153.931 143.097 153.968 ;
     RECT  121.104 153.965 122.382 154.039 ;
     RECT  147.888 153.689 149.742 154.039 ;
     RECT  150.48 153.841 150.498 154.039 ;
     RECT  146.484 153.931 146.934 154.061 ;
     RECT  151.56 153.419 152.73 154.075 ;
     RECT  121.104 154.039 122.562 154.103 ;
     RECT  0.396 153.149 21.114 154.111 ;
     RECT  151.56 154.075 152.766 154.111 ;
     RECT  0.396 154.111 21.15 154.171 ;
     RECT  153.864 153.739 153.918 154.171 ;
     RECT  121.215 154.103 122.562 154.229 ;
     RECT  147.888 154.039 150.498 154.229 ;
     RECT  153.864 154.171 154.458 154.229 ;
     RECT  151.56 154.111 153.054 154.265 ;
     RECT  0.108 154.171 21.15 154.301 ;
     RECT  150.12 154.229 150.498 154.301 ;
     RECT  150.48 154.301 150.498 154.381 ;
     RECT  151.56 154.265 152.73 154.381 ;
     RECT  153.864 154.229 153.918 154.409 ;
     RECT  150.48 154.381 152.73 154.499 ;
     RECT  153.864 154.409 153.882 154.499 ;
     RECT  150.48 154.499 151.038 154.535 ;
     RECT  152.208 154.499 152.73 154.535 ;
     RECT  150.48 154.535 150.498 154.769 ;
     RECT  152.208 154.535 152.226 154.769 ;
     RECT  0.396 154.301 21.15 156.505 ;
     RECT  74.484 156.379 74.502 156.541 ;
     RECT  0.396 156.505 21.222 156.695 ;
     RECT  74.484 156.541 74.826 156.701 ;
     RECT  103.032 156.631 103.05 156.701 ;
     RECT  101.484 156.667 101.502 156.704 ;
     RECT  74.808 156.701 74.826 156.749 ;
     RECT  40.215 123.449 40.497 156.763 ;
     RECT  67.215 122.747 67.497 156.763 ;
     RECT  39.888 156.763 40.497 156.929 ;
     RECT  66.888 156.763 67.497 156.929 ;
     RECT  68.436 156.667 68.454 156.929 ;
     RECT  40.176 156.929 40.497 156.941 ;
     RECT  0.396 156.695 19.278 157.037 ;
     RECT  20.556 156.695 21.222 157.199 ;
     RECT  20.556 157.199 20.97 157.235 ;
     RECT  147.888 154.229 148.878 160.169 ;
     RECT  20.556 157.235 20.826 160.277 ;
     RECT  20.808 160.277 20.826 160.313 ;
     RECT  0.396 157.037 19.206 160.475 ;
     RECT  63.216 160.285 63.234 161.051 ;
     RECT  0.396 160.475 18.954 161.257 ;
     RECT  67.215 156.929 67.497 161.401 ;
     RECT  148.215 160.169 148.878 161.519 ;
     RECT  66.492 161.401 67.497 161.555 ;
     RECT  146.916 154.061 146.934 161.789 ;
     RECT  64.872 161.365 64.89 161.825 ;
     RECT  0.108 161.257 18.954 162.131 ;
     RECT  0.108 162.131 18.897 162.329 ;
     RECT  0.108 162.329 17.874 162.413 ;
     RECT  0.396 162.413 17.874 163.759 ;
     RECT  18.615 162.329 18.897 163.759 ;
     RECT  0.396 163.759 18.897 164.669 ;
     RECT  0.396 164.669 17.766 165.835 ;
     RECT  18.615 164.669 18.897 165.835 ;
     RECT  0.396 165.835 18.897 166.451 ;
     RECT  0.396 166.451 16.83 166.927 ;
     RECT  78.015 132.221 78.297 167.161 ;
     RECT  73.62 167.071 73.638 167.189 ;
     RECT  80.172 117.931 80.19 167.189 ;
     RECT  74.664 167.161 74.682 167.261 ;
     RECT  0.108 166.927 16.83 167.297 ;
     RECT  0.108 167.297 16.65 167.597 ;
     RECT  0.396 167.597 16.65 168.179 ;
     RECT  0.396 168.179 15.138 168.449 ;
     RECT  0.396 168.449 15.066 168.575 ;
     RECT  12.816 168.575 15.066 168.611 ;
     RECT  12.816 168.611 14.454 168.647 ;
     RECT  13.068 168.647 14.454 168.881 ;
     RECT  15.912 168.179 16.65 168.917 ;
     RECT  13.068 168.881 14.166 168.953 ;
     RECT  13.14 168.953 14.166 169.079 ;
     RECT  13.215 169.079 14.166 169.259 ;
     RECT  0.396 168.575 12.078 169.291 ;
     RECT  0.108 169.291 12.078 169.421 ;
     RECT  13.215 169.259 13.497 170.251 ;
     RECT  15.912 168.917 16.002 170.465 ;
     RECT  0.396 169.421 12.078 170.587 ;
     RECT  0.108 170.587 12.078 171.053 ;
     RECT  0.396 171.053 12.078 171.419 ;
     RECT  78.015 167.161 78.93 172.589 ;
     RECT  21.096 172.699 21.114 173.101 ;
     RECT  21.096 173.101 21.402 173.129 ;
     RECT  21.384 173.129 21.402 173.165 ;
     RECT  0.504 171.419 12.078 177.931 ;
     RECT  0.108 177.931 12.078 178.061 ;
     RECT  0.504 178.061 12.078 181.387 ;
     RECT  0.108 181.387 12.078 181.565 ;
     RECT  0.504 181.565 12.078 182.929 ;
     RECT  0.108 182.929 12.078 183.149 ;
     RECT  12.816 170.251 13.497 183.389 ;
     RECT  0.504 183.149 12.078 184.411 ;
     RECT  0.108 184.411 12.078 184.541 ;
     RECT  0.504 184.541 12.078 185.009 ;
     RECT  15.912 170.465 15.93 186.899 ;
     RECT  0.504 185.009 10.242 187.079 ;
     RECT  13.215 183.389 13.497 188.491 ;
     RECT  13.104 188.491 13.497 188.528 ;
     RECT  17.928 166.451 18.897 193.109 ;
     RECT  0.54 187.079 10.242 196.459 ;
     RECT  11.196 185.009 12.078 196.459 ;
     RECT  15.156 196.459 15.174 196.619 ;
     RECT  15.984 196.075 16.002 196.619 ;
     RECT  0.54 196.459 12.078 196.627 ;
     RECT  0.108 196.627 12.078 196.637 ;
     RECT  0.108 196.637 10.242 197.501 ;
     RECT  11.196 196.637 12.078 198.779 ;
     RECT  0.54 197.501 10.242 200.827 ;
     RECT  0.108 200.827 10.242 201.725 ;
     RECT  0.54 201.725 10.242 203.851 ;
     RECT  0.108 203.851 10.242 203.981 ;
     RECT  0.54 203.981 10.242 204.791 ;
     RECT  0.54 204.791 2.934 205.681 ;
     RECT  3.672 204.791 10.242 205.681 ;
     RECT  0.54 205.681 10.242 206.923 ;
     RECT  11.412 198.779 12.078 206.923 ;
     RECT  0.54 206.923 12.078 207.419 ;
     RECT  0.54 207.419 10.566 207.491 ;
     RECT  0.54 207.491 10.242 209.467 ;
     RECT  0.108 209.467 10.242 209.645 ;
     RECT  0.54 209.645 10.242 210.389 ;
     RECT  0.54 210.389 2.97 210.425 ;
     RECT  3.708 210.389 10.242 210.569 ;
     RECT  0.54 210.425 2.754 211.171 ;
     RECT  3.708 210.569 9.486 211.171 ;
     RECT  0.54 211.171 9.486 211.469 ;
     RECT  13.215 188.528 13.497 212.251 ;
     RECT  20.808 212.059 20.826 212.279 ;
     RECT  13.104 212.251 13.497 212.288 ;
     RECT  14.832 212.251 14.85 212.381 ;
     RECT  19.692 212.347 19.71 212.459 ;
     RECT  0.54 211.469 9.126 213.097 ;
     RECT  0.108 213.097 9.126 213.389 ;
     RECT  0.54 213.389 9.126 214.781 ;
     RECT  0.54 214.781 2.862 215.365 ;
     RECT  0.108 215.365 2.862 215.671 ;
     RECT  3.636 214.781 9.126 215.671 ;
     RECT  0.108 215.671 9.126 215.981 ;
     RECT  0.54 215.981 9.126 216.905 ;
     RECT  0.54 216.905 2.862 217.651 ;
     RECT  3.672 216.905 9.126 217.651 ;
     RECT  0.54 217.651 9.126 220.829 ;
     RECT  0.54 220.829 2.697 221.563 ;
     RECT  3.564 220.829 9.126 221.563 ;
     RECT  0.54 221.563 9.126 222.647 ;
     RECT  0.54 222.647 3.15 223.393 ;
     RECT  3.924 222.647 9.126 223.393 ;
     RECT  0.54 223.393 9.126 223.457 ;
     RECT  10.224 210.569 10.242 223.619 ;
     RECT  78.015 172.589 78.822 224.671 ;
     RECT  77.58 224.671 78.822 224.941 ;
     RECT  77.148 224.941 78.822 225.049 ;
     RECT  76.968 225.049 78.822 225.149 ;
     RECT  77.148 225.149 78.822 225.239 ;
     RECT  77.148 225.239 78.426 225.275 ;
     RECT  77.292 225.275 78.426 225.509 ;
     RECT  77.292 225.509 78.297 225.779 ;
     RECT  0.108 226.651 0.126 226.781 ;
     RECT  1.116 223.457 9.126 227.405 ;
     RECT  1.116 227.405 6.03 227.705 ;
     RECT  4.176 227.705 6.03 228.325 ;
     RECT  6.768 227.405 9.126 228.325 ;
     RECT  1.116 227.705 2.862 228.523 ;
     RECT  1.116 228.523 2.97 228.631 ;
     RECT  4.176 228.325 9.126 228.631 ;
     RECT  11.412 207.419 12.078 229.199 ;
     RECT  1.116 228.631 9.126 229.289 ;
     RECT  1.116 229.289 8.658 229.559 ;
     RECT  1.116 229.559 5.958 229.829 ;
     RECT  3.456 229.829 5.958 230.299 ;
     RECT  6.804 229.559 8.658 230.299 ;
     RECT  1.116 229.829 2.697 230.791 ;
     RECT  3.456 230.299 8.658 230.791 ;
     RECT  1.116 230.791 8.658 230.909 ;
     RECT  0.108 231.067 0.126 231.245 ;
     RECT  1.116 230.909 5.634 231.719 ;
     RECT  5.616 231.719 5.634 231.871 ;
     RECT  6.48 230.909 8.658 231.989 ;
     RECT  1.116 231.719 4.77 232.025 ;
     RECT  5.616 231.871 5.706 232.259 ;
     RECT  1.116 232.025 2.697 232.951 ;
     RECT  3.492 232.025 4.77 232.951 ;
     RECT  5.616 232.259 5.634 233.131 ;
     RECT  1.116 232.951 4.77 233.221 ;
     RECT  6.804 231.989 8.658 233.221 ;
     RECT  6.696 233.221 8.658 233.311 ;
     RECT  1.116 233.221 4.842 233.383 ;
     RECT  5.616 233.131 5.778 233.383 ;
     RECT  1.116 233.383 5.778 233.959 ;
     RECT  6.66 233.311 8.658 233.959 ;
     RECT  1.116 233.959 8.658 233.987 ;
     RECT  2.304 233.987 8.658 234.419 ;
     RECT  11.412 229.199 11.43 234.419 ;
     RECT  6.048 234.419 8.658 234.455 ;
     RECT  2.304 234.419 5.13 234.689 ;
     RECT  6.804 234.455 8.658 234.859 ;
     RECT  6.804 234.859 8.946 234.959 ;
     RECT  6.804 234.959 8.694 235.103 ;
     RECT  6.804 235.103 8.658 235.229 ;
     RECT  2.304 234.689 5.022 235.265 ;
     RECT  6.048 234.455 6.066 235.345 ;
     RECT  5.976 235.345 6.066 235.421 ;
     RECT  6.804 235.229 8.097 235.499 ;
     RECT  3.888 235.265 5.022 235.627 ;
     RECT  3.888 235.627 5.202 236.281 ;
     RECT  6.048 235.421 6.066 236.281 ;
     RECT  2.304 235.265 3.006 236.347 ;
     RECT  3.888 236.281 6.066 236.347 ;
     RECT  0.108 236.251 0.126 236.381 ;
     RECT  77.868 225.779 78.297 236.417 ;
     RECT  2.304 236.347 6.066 236.539 ;
     RECT  1.116 233.987 1.134 236.921 ;
     RECT  2.304 236.539 6.138 236.965 ;
     RECT  2.304 236.965 6.39 237.001 ;
     RECT  7.236 235.499 8.097 237.001 ;
     RECT  2.304 237.001 8.097 237.389 ;
     RECT  2.304 237.389 5.382 237.541 ;
     RECT  6.372 237.389 8.097 237.569 ;
     RECT  2.268 237.541 5.382 237.581 ;
     RECT  2.304 237.581 5.382 237.659 ;
     RECT  6.372 237.569 6.39 237.659 ;
     RECT  7.272 237.569 8.097 238.267 ;
     RECT  2.304 237.659 4.338 238.469 ;
     RECT  2.304 238.469 3.114 238.505 ;
     RECT  5.22 237.659 5.382 238.507 ;
     RECT  5.22 238.507 5.454 238.621 ;
     RECT  5.22 238.621 5.778 238.649 ;
     RECT  5.436 238.649 5.778 238.711 ;
     RECT  5.436 238.711 6.246 238.739 ;
     RECT  7.272 238.267 8.73 238.739 ;
     RECT  3.852 238.469 4.338 238.747 ;
     RECT  7.272 238.739 8.097 238.775 ;
     RECT  6.228 238.739 6.246 239.009 ;
     RECT  5.436 238.739 5.454 239.279 ;
     RECT  2.304 238.505 2.862 239.315 ;
     RECT  2.34 239.315 2.862 239.359 ;
     RECT  6.66 239.419 6.822 239.549 ;
     RECT  3.852 238.747 4.698 239.665 ;
     RECT  2.34 239.359 3.006 239.701 ;
     RECT  3.852 239.665 4.842 239.701 ;
     RECT  6.66 239.549 6.678 239.819 ;
     RECT  5.76 239.707 5.778 239.855 ;
     RECT  0.108 239.707 0.126 239.885 ;
     RECT  5.832 239.863 5.85 240.089 ;
     RECT  2.34 239.701 4.842 240.139 ;
     RECT  2.304 240.139 4.842 240.269 ;
     RECT  2.304 240.269 4.734 240.359 ;
     RECT  2.304 240.359 4.194 240.431 ;
     RECT  2.304 240.431 4.158 240.629 ;
     RECT  2.304 240.629 4.05 240.665 ;
     RECT  2.304 240.665 3.546 240.737 ;
     RECT  2.304 240.737 3.294 240.899 ;
     RECT  2.304 240.899 2.697 240.935 ;
     RECT  77.976 236.417 78.297 241.447 ;
     RECT  77.94 241.447 78.297 241.517 ;
     RECT  77.976 241.517 78.297 241.547 ;
     RECT  2.415 240.935 2.697 243.827 ;
     RECT  7.815 238.775 8.097 243.827 ;
     RECT  13.215 212.288 13.497 243.827 ;
     RECT  18.615 193.109 18.897 243.827 ;
     RECT  24.015 147.785 24.297 243.827 ;
     RECT  29.415 150.755 29.697 243.827 ;
     RECT  34.815 138.839 35.097 243.827 ;
     RECT  40.215 156.941 40.497 243.827 ;
     RECT  45.615 140.459 45.897 243.827 ;
     RECT  51.015 92.543 51.297 243.827 ;
     RECT  56.415 122.009 56.697 243.827 ;
     RECT  61.815 124.259 62.097 243.827 ;
     RECT  67.215 161.555 67.497 243.827 ;
     RECT  72.615 115.349 72.897 243.827 ;
     RECT  78.015 241.547 78.297 243.827 ;
     RECT  83.415 2.413 83.697 243.827 ;
     RECT  88.815 153.968 89.097 243.827 ;
     RECT  94.215 134.123 94.497 243.827 ;
     RECT  99.615 153.968 99.897 243.827 ;
     RECT  105.015 2.413 105.297 243.827 ;
     RECT  110.415 153.965 110.697 243.827 ;
     RECT  115.815 2.413 116.097 243.827 ;
     RECT  121.215 154.229 121.497 243.827 ;
     RECT  126.615 2.413 126.897 243.827 ;
     RECT  132.015 153.968 132.297 243.827 ;
     RECT  137.415 2.413 137.697 243.827 ;
     RECT  142.815 153.968 143.097 243.827 ;
     RECT  148.215 161.519 148.497 243.827 ;
     RECT  78.015 243.827 78.138 243.869 ;
     RECT  78.015 243.869 78.105 243.877 ;
     RECT  2.415 243.827 2.505 244.097 ;
     RECT  7.815 243.827 7.905 244.097 ;
     RECT  13.215 243.827 13.305 244.097 ;
     RECT  18.615 243.827 18.705 244.097 ;
     RECT  24.015 243.827 24.105 244.097 ;
     RECT  29.415 243.827 29.505 244.097 ;
     RECT  34.815 243.827 34.905 244.097 ;
     RECT  40.215 243.827 40.305 244.097 ;
     RECT  45.615 243.827 45.705 244.097 ;
     RECT  51.015 243.827 51.105 244.097 ;
     RECT  56.415 243.827 56.505 244.097 ;
     RECT  61.815 243.827 61.905 244.097 ;
     RECT  67.215 243.827 67.305 244.097 ;
     RECT  72.615 243.827 72.705 244.097 ;
     RECT  77.976 243.877 78.105 244.097 ;
     RECT  83.415 243.827 83.505 244.097 ;
     RECT  88.815 243.827 88.905 244.097 ;
     RECT  94.215 243.827 94.305 244.097 ;
     RECT  99.615 243.827 99.705 244.097 ;
     RECT  105.015 243.827 105.105 244.097 ;
     RECT  110.415 243.827 110.505 244.097 ;
     RECT  115.815 243.827 115.905 244.097 ;
     RECT  121.215 243.827 121.305 244.097 ;
     RECT  126.615 243.827 126.705 244.097 ;
     RECT  132.015 243.827 132.105 244.097 ;
     RECT  137.415 243.827 137.505 244.097 ;
     RECT  142.815 243.827 142.905 244.097 ;
     RECT  148.215 243.827 148.305 244.097 ;
     RECT  77.976 244.097 77.994 244.253 ;
    LAYER M4 ;
     RECT  0.06 6 2.408 240.168 ;
     RECT  2.408 2.148 2.512 244.092 ;
     RECT  2.512 2.418 2.704 243.822 ;
     RECT  2.704 19.248 2.729 21.144 ;
     RECT  2.704 97.776 2.729 98.904 ;
     RECT  2.704 195.552 2.729 196.104 ;
     RECT  2.704 228.48 2.729 229.368 ;
     RECT  2.704 9.6 2.765 11.112 ;
     RECT  2.704 24.144 2.765 25.032 ;
     RECT  2.704 55.68 2.765 55.704 ;
     RECT  2.704 115.392 2.765 123 ;
     RECT  2.704 156.768 2.765 160.248 ;
     RECT  2.704 175.536 2.765 178.392 ;
     RECT  2.704 210.768 2.765 210.792 ;
     RECT  2.704 217.536 2.765 217.704 ;
     RECT  2.704 226.656 2.765 227.208 ;
     RECT  2.704 32.784 2.801 32.808 ;
     RECT  2.704 54.384 2.801 54.408 ;
     RECT  2.704 60 2.801 60.216 ;
     RECT  2.704 86.784 2.801 93.336 ;
     RECT  2.704 15.504 2.837 15.864 ;
     RECT  2.729 19.248 2.837 20.52 ;
     RECT  2.765 24.144 2.837 24.696 ;
     RECT  2.704 62.88 2.837 63.048 ;
     RECT  2.704 75.936 2.837 77.88 ;
     RECT  2.765 157.2 2.837 160.248 ;
     RECT  2.704 179.664 2.837 179.688 ;
     RECT  2.704 190.464 2.837 191.4 ;
     RECT  2.704 192.624 2.837 194.424 ;
     RECT  2.704 199.104 2.837 199.896 ;
     RECT  2.704 225.024 2.837 225.048 ;
     RECT  2.729 229.344 2.837 229.368 ;
     RECT  2.704 206.304 2.845 207.48 ;
     RECT  2.837 192.672 2.867 194.424 ;
     RECT  2.704 26.016 2.873 26.04 ;
     RECT  2.704 39.264 2.873 40.152 ;
     RECT  2.704 42.288 2.873 42.312 ;
     RECT  2.801 88.08 2.873 93.336 ;
     RECT  2.704 100.272 2.873 101.352 ;
     RECT  2.765 175.536 2.873 178.056 ;
     RECT  2.704 187.008 2.873 187.56 ;
     RECT  2.704 200.976 2.873 201.624 ;
     RECT  2.704 220.608 2.873 222.264 ;
     RECT  2.704 239.856 2.873 239.88 ;
     RECT  2.873 39.648 2.909 40.152 ;
     RECT  2.704 66.192 2.909 67.08 ;
     RECT  2.704 74.352 2.909 74.712 ;
     RECT  2.873 100.272 2.909 100.296 ;
     RECT  2.704 107.376 2.909 111.096 ;
     RECT  2.765 116.544 2.909 123 ;
     RECT  2.704 139.968 2.909 151.416 ;
     RECT  2.704 154.08 2.909 154.296 ;
     RECT  2.704 167.616 2.909 172.68 ;
     RECT  2.873 200.976 2.909 201.24 ;
     RECT  2.704 45.456 2.981 45.48 ;
     RECT  2.909 147.6 2.981 151.416 ;
     RECT  2.704 208.608 2.981 209.64 ;
     RECT  2.704 43.296 3.017 44.136 ;
     RECT  2.729 195.552 3.017 195.576 ;
     RECT  3.017 44.112 3.089 44.136 ;
     RECT  2.704 53.088 3.089 53.112 ;
     RECT  2.704 68.208 3.089 68.232 ;
     RECT  2.704 102.432 3.089 102.456 ;
     RECT  2.704 197.472 3.089 197.496 ;
     RECT  2.704 31.488 3.125 31.512 ;
     RECT  2.704 231.216 3.125 231.24 ;
     RECT  2.837 15.84 3.197 15.864 ;
     RECT  2.909 169.728 3.197 169.8 ;
     RECT  2.704 215.856 3.197 215.88 ;
     RECT  2.837 76.944 3.233 77.88 ;
     RECT  2.837 157.2 3.233 160.104 ;
     RECT  2.704 7.44 3.277 8.472 ;
     RECT  2.704 6.192 3.292 6.216 ;
     RECT  3.277 7.968 3.299 8.472 ;
     RECT  2.765 9.6 3.299 9.624 ;
     RECT  2.765 11.088 3.299 11.112 ;
     RECT  2.704 12.24 3.299 13.08 ;
     RECT  2.837 24.672 3.305 24.696 ;
     RECT  3.233 157.2 3.305 159.096 ;
     RECT  2.704 236.352 3.305 236.376 ;
     RECT  2.704 83.328 3.341 85.752 ;
     RECT  2.909 167.616 3.347 168.456 ;
     RECT  2.873 175.536 3.395 178.008 ;
     RECT  2.909 116.64 3.413 122.568 ;
     RECT  2.704 126.576 3.413 138.408 ;
     RECT  3.233 76.944 3.443 77.544 ;
     RECT  2.704 183.936 3.587 185.544 ;
     RECT  2.704 47.712 3.697 48.408 ;
     RECT  2.729 97.776 3.697 98.04 ;
     RECT  2.704 38.016 3.733 38.04 ;
     RECT  3.413 136.848 3.733 138.408 ;
     RECT  2.909 139.968 3.733 146.28 ;
     RECT  2.704 164.16 3.733 166.488 ;
     RECT  3.587 185.424 3.733 185.544 ;
     RECT  2.704 80.352 3.769 82.152 ;
     RECT  2.704 112.176 3.769 114.408 ;
     RECT  2.765 115.392 3.769 115.416 ;
     RECT  2.765 217.536 3.769 217.56 ;
     RECT  3.587 183.936 3.779 184.344 ;
     RECT  2.909 39.648 3.827 39.672 ;
     RECT  2.801 86.784 3.829 87.096 ;
     RECT  3.733 164.112 3.841 166.488 ;
     RECT  2.704 180.864 3.841 181.8 ;
     RECT  2.867 192.672 3.841 193.272 ;
     RECT  2.867 194.4 3.841 194.424 ;
     RECT  3.443 76.992 3.845 77.544 ;
     RECT  3.733 136.848 3.877 138.504 ;
     RECT  3.733 139.584 3.877 146.28 ;
     RECT  3.697 32.304 3.884 32.328 ;
     RECT  3.733 31.296 3.913 31.32 ;
     RECT  3.733 38.016 3.913 38.232 ;
     RECT  2.909 154.08 3.913 154.104 ;
     RECT  3.841 164.112 3.913 166.584 ;
     RECT  2.845 206.304 3.923 207.192 ;
     RECT  3.884 32.304 3.925 32.904 ;
     RECT  2.909 107.376 3.925 108.216 ;
     RECT  2.704 203.376 3.925 204.744 ;
     RECT  2.801 60.192 3.949 60.216 ;
     RECT  2.909 66.192 3.949 66.216 ;
     RECT  2.873 101.328 3.949 101.352 ;
     RECT  3.925 32.304 3.971 33.672 ;
     RECT  3.925 204.576 3.971 205.224 ;
     RECT  2.704 224.016 3.973 224.04 ;
     RECT  3.913 225.216 3.973 225.24 ;
     RECT  2.765 226.656 3.973 226.728 ;
     RECT  2.909 109.536 3.985 111.096 ;
     RECT  3.769 112.176 3.985 115.416 ;
     RECT  3.913 38.016 3.997 38.76 ;
     RECT  3.769 80.352 4.019 82.632 ;
     RECT  3.973 224.016 4.019 226.728 ;
     RECT  3.98 55.008 4.021 55.032 ;
     RECT  3.949 59.712 4.021 60.216 ;
     RECT  2.873 220.608 4.021 220.632 ;
     RECT  2.704 218.832 4.067 218.856 ;
     RECT  3.949 66.192 4.069 66.888 ;
     RECT  3.877 136.848 4.104 146.28 ;
     RECT  4.021 220.368 4.108 221.208 ;
     RECT  4.069 65.568 4.115 66.888 ;
     RECT  2.873 88.176 4.117 93.336 ;
     RECT  2.704 94.368 4.117 96.312 ;
     RECT  3.769 217.344 4.117 217.56 ;
     RECT  2.873 222.24 4.117 222.264 ;
     RECT  3.997 38.016 4.124 38.232 ;
     RECT  3.697 97.776 4.129 98.472 ;
     RECT  4.117 222.24 4.163 222.504 ;
     RECT  2.704 49.584 4.165 49.608 ;
     RECT  3.949 101.328 4.165 101.832 ;
     RECT  3.347 167.616 4.165 168.216 ;
     RECT  3.985 109.536 4.201 115.416 ;
     RECT  4.165 49.584 4.205 50.04 ;
     RECT  4.124 37.44 4.211 38.232 ;
     RECT  3.197 169.776 4.213 169.8 ;
     RECT  3.829 86.736 4.237 87.096 ;
     RECT  4.117 88.176 4.237 96.312 ;
     RECT  3.925 107.28 4.237 108.36 ;
     RECT  2.704 237.648 4.237 238.536 ;
     RECT  2.704 61.584 4.268 61.896 ;
     RECT  2.837 62.88 4.268 62.904 ;
     RECT  3.341 84.096 4.268 85.752 ;
     RECT  4.237 86.736 4.268 96.312 ;
     RECT  4.129 97.68 4.268 99 ;
     RECT  2.704 233.232 4.268 233.256 ;
     RECT  3.697 42.72 4.273 42.744 ;
     RECT  2.873 187.536 4.273 187.56 ;
     RECT  3.299 8.448 4.277 8.472 ;
     RECT  4.021 59.232 4.309 60.216 ;
     RECT  4.268 61.536 4.309 61.896 ;
     RECT  4.268 62.88 4.309 62.952 ;
     RECT  4.115 65.568 4.309 66.216 ;
     RECT  2.704 73.152 4.309 73.176 ;
     RECT  4.021 55.008 4.313 56.472 ;
     RECT  4.019 224.016 4.316 224.76 ;
     RECT  4.237 107.136 4.345 108.36 ;
     RECT  4.201 109.536 4.345 115.608 ;
     RECT  4.104 136.848 4.345 146.376 ;
     RECT  4.309 59.232 4.355 61.896 ;
     RECT  4.268 97.68 4.355 99.384 ;
     RECT  4.268 197.904 4.355 197.928 ;
     RECT  3.233 160.08 4.357 160.104 ;
     RECT  4.316 161.52 4.357 161.544 ;
     RECT  4.313 55.008 4.381 55.704 ;
     RECT  4.165 100.56 4.381 101.832 ;
     RECT  2.704 103.488 4.381 106.008 ;
     RECT  4.316 223.584 4.385 224.76 ;
     RECT  4.309 196.608 4.393 196.632 ;
     RECT  4.385 223.584 4.403 223.608 ;
     RECT  4.345 107.136 4.405 115.608 ;
     RECT  3.413 116.64 4.405 116.856 ;
     RECT  3.413 117.984 4.405 122.568 ;
     RECT  2.704 125.28 4.417 125.304 ;
     RECT  4.405 107.136 4.453 122.568 ;
     RECT  2.704 152.64 4.453 152.664 ;
     RECT  3.395 176.112 4.453 178.008 ;
     RECT  4.355 97.68 4.457 99 ;
     RECT  2.837 199.872 4.457 199.896 ;
     RECT  2.837 20.496 4.493 20.52 ;
     RECT  3.923 206.4 4.493 207.192 ;
     RECT  4.237 27.216 4.501 27.24 ;
     RECT  2.704 29.04 4.501 29.064 ;
     RECT  4.165 36.384 4.501 36.408 ;
     RECT  3.413 126.576 4.501 135.864 ;
     RECT  4.345 136.848 4.501 146.52 ;
     RECT  4.019 225.744 4.501 226.728 ;
     RECT  4.165 229.104 4.501 229.128 ;
     RECT  4.309 231.408 4.501 231.432 ;
     RECT  4.508 23.52 4.517 23.544 ;
     RECT  4.309 25.392 4.517 25.416 ;
     RECT  2.704 14.496 4.525 14.52 ;
     RECT  3.971 33.648 4.525 33.672 ;
     RECT  4.268 84.096 4.525 96.312 ;
     RECT  4.381 100.56 4.525 106.008 ;
     RECT  4.453 107.136 4.525 123.096 ;
     RECT  2.704 188.688 4.525 189.336 ;
     RECT  4.501 236.496 4.525 236.52 ;
     RECT  3.697 47.328 4.529 48.408 ;
     RECT  4.501 27.216 4.547 29.064 ;
     RECT  4.501 229.104 4.547 231.432 ;
     RECT  4.345 21.936 4.549 21.96 ;
     RECT  4.517 23.52 4.549 25.416 ;
     RECT  4.273 42.096 4.549 42.744 ;
     RECT  2.704 124.224 4.549 124.248 ;
     RECT  4.417 125.28 4.549 125.592 ;
     RECT  4.501 126.576 4.549 146.52 ;
     RECT  3.913 154.08 4.549 154.44 ;
     RECT  3.305 157.584 4.549 159.096 ;
     RECT  4.357 160.08 4.549 161.544 ;
     RECT  3.913 163.056 4.549 166.584 ;
     RECT  4.549 124.224 4.556 146.568 ;
     RECT  2.981 147.6 4.556 151.08 ;
     RECT  3.841 192.672 4.556 194.424 ;
     RECT  4.525 83.76 4.561 96.312 ;
     RECT  4.457 97.68 4.561 98.904 ;
     RECT  4.021 216 4.561 216.024 ;
     RECT  4.547 27.888 4.565 29.064 ;
     RECT  4.525 33.648 4.565 34.248 ;
     RECT  4.549 160.08 4.565 166.584 ;
     RECT  2.909 201.216 4.565 201.24 ;
     RECT  4.163 222.48 4.565 222.504 ;
     RECT  4.501 225.744 4.565 227.352 ;
     RECT  4.501 35.856 4.588 36.408 ;
     RECT  4.565 226.704 4.588 227.352 ;
     RECT  4.547 229.44 4.588 231.432 ;
     RECT  4.549 21.936 4.595 25.416 ;
     RECT  4.595 24.48 4.601 25.128 ;
     RECT  2.837 191.376 4.601 191.4 ;
     RECT  4.117 217.344 4.601 217.752 ;
     RECT  4.309 18.144 4.625 18.168 ;
     RECT  2.837 19.248 4.625 19.368 ;
     RECT  4.588 229.44 4.637 229.848 ;
     RECT  4.556 192.432 4.643 194.424 ;
     RECT  4.525 16.992 4.645 17.016 ;
     RECT  4.625 18.144 4.645 19.368 ;
     RECT  2.704 173.808 4.645 173.832 ;
     RECT  4.453 176.112 4.645 178.44 ;
     RECT  3.913 30.72 4.652 31.32 ;
     RECT  4.645 16.992 4.669 19.368 ;
     RECT  3.741 40.992 4.669 41.016 ;
     RECT  4.549 42.096 4.669 43.272 ;
     RECT  3.829 214.896 4.669 214.92 ;
     RECT  4.237 237.648 4.669 239.4 ;
     RECT  4.669 16.992 4.691 19.464 ;
     RECT  4.691 18.816 4.709 19.464 ;
     RECT  4.588 36.384 4.709 36.408 ;
     RECT  4.355 59.232 4.709 61.608 ;
     RECT  4.309 62.88 4.709 63.768 ;
     RECT  4.556 124.224 4.709 151.08 ;
     RECT  4.268 232.464 4.709 233.256 ;
     RECT  4.669 237.648 4.709 239.736 ;
     RECT  4.645 173.808 4.732 178.44 ;
     RECT  4.652 29.904 4.739 31.32 ;
     RECT  4.525 100.56 4.777 123.096 ;
     RECT  4.309 52.896 4.789 52.92 ;
     RECT  4.381 54.144 4.789 55.704 ;
     RECT  4.549 157.44 4.789 159.096 ;
     RECT  2.704 70.704 4.813 70.728 ;
     RECT  2.704 71.808 4.813 71.832 ;
     RECT  4.789 52.896 4.835 55.704 ;
     RECT  4.732 173.808 4.835 173.832 ;
     RECT  4.669 40.416 4.837 41.016 ;
     RECT  4.669 42.096 4.837 43.368 ;
     RECT  2.909 171.696 4.837 172.68 ;
     RECT  3.733 185.424 4.849 185.832 ;
     RECT  4.273 187.152 4.849 187.56 ;
     RECT  4.309 212.064 4.849 212.088 ;
     RECT  4.691 17.04 4.853 17.64 ;
     RECT  4.835 52.896 4.876 53.928 ;
     RECT  4.709 124.752 4.885 151.08 ;
     RECT  4.525 235.632 4.885 236.52 ;
     RECT  4.849 212.064 4.889 212.472 ;
     RECT  4.837 40.416 4.924 43.368 ;
     RECT  4.853 17.04 4.931 17.112 ;
     RECT  4.565 27.888 4.961 28.44 ;
     RECT  4.525 44.448 4.981 44.472 ;
     RECT  4.549 154.08 4.988 154.584 ;
     RECT  2.704 155.616 4.988 155.688 ;
     RECT  4.669 214.032 4.988 214.92 ;
     RECT  4.561 216 4.988 216.36 ;
     RECT  4.385 224.736 4.988 224.76 ;
     RECT  4.981 44.448 5.027 45.144 ;
     RECT  4.835 55.056 5.027 55.704 ;
     RECT  3.841 180.864 5.029 182.616 ;
     RECT  4.309 64.8 5.033 66.216 ;
     RECT  3.845 76.992 5.033 77.016 ;
     RECT  4.561 83.76 5.033 98.904 ;
     RECT  4.813 70.704 5.057 71.832 ;
     RECT  4.309 73.104 5.057 73.176 ;
     RECT  3.925 203.376 5.065 203.544 ;
     RECT  4.988 224.736 5.069 224.952 ;
     RECT  4.837 170.976 5.075 172.68 ;
     RECT  5.069 224.928 5.075 224.952 ;
     RECT  4.021 51.504 5.077 51.528 ;
     RECT  4.876 52.896 5.077 52.92 ;
     RECT  4.849 185.424 5.077 187.56 ;
     RECT  4.525 188.688 5.077 190.248 ;
     RECT  2.837 75.936 5.101 75.96 ;
     RECT  4.924 40.416 5.123 41.016 ;
     RECT  5.077 51.504 5.123 52.92 ;
     RECT  5.077 185.424 5.123 190.248 ;
     RECT  2.704 79.2 5.132 79.224 ;
     RECT  5.029 180.72 5.137 182.616 ;
     RECT  3.779 183.936 5.137 183.96 ;
     RECT  4.709 60.96 5.141 61.608 ;
     RECT  5.057 70.704 5.141 73.176 ;
     RECT  4.732 175.152 5.141 178.44 ;
     RECT  5.123 187.968 5.164 188.664 ;
     RECT  5.101 75.936 5.173 76.92 ;
     RECT  4.565 160.176 5.177 166.584 ;
     RECT  5.137 180.72 5.177 183.96 ;
     RECT  4.988 214.032 5.177 216.36 ;
     RECT  5.141 71.232 5.184 71.832 ;
     RECT  4.453 152.64 5.209 152.808 ;
     RECT  4.949 210.912 5.209 210.936 ;
     RECT  4.885 235.632 5.213 236.568 ;
     RECT  5.132 79.056 5.219 79.224 ;
     RECT  5.177 180.72 5.219 183.672 ;
     RECT  5.123 189.84 5.219 190.248 ;
     RECT  4.561 198.624 5.219 198.84 ;
     RECT  4.885 124.752 5.221 151.656 ;
     RECT  5.209 152.64 5.221 152.904 ;
     RECT  5.219 182.976 5.221 183.672 ;
     RECT  5.219 79.2 5.228 79.224 ;
     RECT  4.019 80.352 5.228 82.152 ;
     RECT  4.709 237.648 5.249 238.68 ;
     RECT  5.141 73.104 5.269 73.176 ;
     RECT  5.228 79.2 5.285 82.152 ;
     RECT  5.141 60.96 5.308 61.512 ;
     RECT  5.285 79.728 5.315 82.152 ;
     RECT  4.565 34.224 5.324 34.248 ;
     RECT  4.525 14.496 5.357 15.384 ;
     RECT  5.177 160.176 5.357 166.392 ;
     RECT  2.909 74.688 5.365 74.712 ;
     RECT  5.173 75.792 5.365 76.92 ;
     RECT  4.988 154.08 5.365 155.688 ;
     RECT  4.789 156.672 5.365 159.096 ;
     RECT  5.075 172.032 5.365 172.68 ;
     RECT  4.595 21.936 5.389 22.824 ;
     RECT  4.309 68.112 5.389 68.136 ;
     RECT  5.213 236.544 5.389 236.568 ;
     RECT  4.601 25.104 5.411 25.128 ;
     RECT  4.924 42.096 5.411 43.368 ;
     RECT  4.885 69.408 5.411 69.432 ;
     RECT  5.219 189.84 5.411 190.104 ;
     RECT  5.389 21.312 5.429 22.824 ;
     RECT  5.357 164.064 5.429 166.392 ;
     RECT  4.885 10.752 5.461 10.776 ;
     RECT  5.123 185.424 5.461 185.544 ;
     RECT  4.493 206.88 5.465 207.192 ;
     RECT  5.249 238.512 5.465 238.68 ;
     RECT  5.465 206.88 5.507 206.904 ;
     RECT  5.177 215.712 5.507 216.36 ;
     RECT  4.529 47.712 5.533 48.408 ;
     RECT  4.057 58.128 5.533 58.152 ;
     RECT  5.365 74.688 5.605 76.92 ;
     RECT  5.141 176.352 5.605 178.44 ;
     RECT  4.525 179.52 5.605 179.544 ;
     RECT  5.533 57.6 5.612 58.152 ;
     RECT  4.709 59.232 5.612 59.736 ;
     RECT  5.465 238.656 5.651 238.68 ;
     RECT  4.213 169.776 5.653 169.944 ;
     RECT  5.075 170.976 5.653 171 ;
     RECT  5.605 176.352 5.653 179.544 ;
     RECT  5.219 180.72 5.653 181.8 ;
     RECT  4.525 219.408 5.653 219.432 ;
     RECT  4.108 220.608 5.653 221.208 ;
     RECT  4.601 217.68 5.677 217.752 ;
     RECT  2.981 208.608 5.688 209.16 ;
     RECT  5.612 57.6 5.699 59.736 ;
     RECT  5.221 124.752 5.699 152.904 ;
     RECT  5.653 176.352 5.699 181.8 ;
     RECT  5.653 219.408 5.699 221.208 ;
     RECT  5.324 34.224 5.701 34.728 ;
     RECT  4.205 50.016 5.701 50.04 ;
     RECT  5.123 51.504 5.701 52.44 ;
     RECT  5.065 203.376 5.701 203.592 ;
     RECT  3.971 204.72 5.701 205.224 ;
     RECT  5.209 210.816 5.701 210.936 ;
     RECT  4.889 212.448 5.701 212.472 ;
     RECT  4.777 100.56 5.713 123.768 ;
     RECT  4.709 19.44 5.741 19.464 ;
     RECT  5.701 33.6 5.747 34.728 ;
     RECT  5.701 50.016 5.747 52.44 ;
     RECT  5.701 210.816 5.747 211.368 ;
     RECT  4.211 38.208 5.749 38.232 ;
     RECT  4.165 167.568 5.749 168.216 ;
     RECT  5.653 169.776 5.749 171 ;
     RECT  5.461 196.656 5.749 196.68 ;
     RECT  5.688 207.984 5.749 209.16 ;
     RECT  5.027 44.88 5.753 45.144 ;
     RECT  5.033 66.096 5.753 66.216 ;
     RECT  5.677 217.68 5.753 218.328 ;
     RECT  4.709 233.136 5.753 233.256 ;
     RECT  5.533 47.712 5.756 48.648 ;
     RECT  5.461 10.032 5.785 10.776 ;
     RECT  3.299 12.24 5.785 12.264 ;
     RECT  5.749 38.208 5.785 38.952 ;
     RECT  5.699 147.552 5.785 152.904 ;
     RECT  5.365 154.08 5.785 159.096 ;
     RECT  5.701 212.448 5.788 213 ;
     RECT  5.357 160.176 5.789 163.08 ;
     RECT  5.699 219.696 5.789 221.208 ;
     RECT  5.753 233.136 5.789 233.16 ;
     RECT  4.709 239.712 5.789 239.736 ;
     RECT  5.429 21.312 5.797 21.336 ;
     RECT  5.785 38.112 5.797 38.952 ;
     RECT  5.756 47.28 5.797 48.648 ;
     RECT  5.747 50.016 5.797 50.712 ;
     RECT  5.701 202.368 5.797 205.56 ;
     RECT  5.741 19.344 5.825 19.464 ;
     RECT  5.756 45.552 5.843 45.576 ;
     RECT  5.797 47.28 5.843 50.712 ;
     RECT  5.789 220.608 5.845 221.208 ;
     RECT  4.588 226.704 5.857 226.728 ;
     RECT  5.411 42.096 5.861 42.84 ;
     RECT  5.785 10.032 5.869 12.264 ;
     RECT  5.797 38.112 5.869 39.048 ;
     RECT  5.797 200.64 5.884 200.664 ;
     RECT  5.785 147.552 5.891 159.096 ;
     RECT  5.845 220.608 5.891 222.792 ;
     RECT  4.739 30.816 5.893 31.32 ;
     RECT  4.709 62.88 5.897 62.904 ;
     RECT  5.843 47.712 5.933 50.712 ;
     RECT  5.699 180.144 5.933 180.216 ;
     RECT  5.933 50.64 5.939 50.712 ;
     RECT  5.357 14.496 5.965 14.808 ;
     RECT  5.033 84.096 5.969 98.904 ;
     RECT  5.891 222 5.969 222.792 ;
     RECT  5.389 236.544 5.987 237.096 ;
     RECT  5.869 38.784 5.989 39.048 ;
     RECT  5.825 19.44 6.005 19.464 ;
     RECT  5.429 22.8 6.005 22.824 ;
     RECT  5.747 33.6 6.005 33.624 ;
     RECT  5.123 40.416 6.005 40.44 ;
     RECT  5.027 55.68 6.005 55.704 ;
     RECT  5.389 67.536 6.005 68.136 ;
     RECT  5.141 175.152 6.005 175.176 ;
     RECT  5.411 190.08 6.005 190.104 ;
     RECT  4.643 194.112 6.005 194.136 ;
     RECT  5.747 211.344 6.005 211.368 ;
     RECT  5.753 217.728 6.005 218.328 ;
     RECT  5.941 235.392 6.028 235.416 ;
     RECT  5.989 38.784 6.035 39.24 ;
     RECT  4.961 28.416 6.041 28.44 ;
     RECT  6.035 38.928 6.041 39.24 ;
     RECT  5.699 176.352 6.041 178.968 ;
     RECT  5.797 201.984 6.041 205.56 ;
     RECT  5.184 71.808 6.077 71.832 ;
     RECT  5.789 160.176 6.077 163.032 ;
     RECT  5.969 85.2 6.083 98.904 ;
     RECT  5.891 147.552 6.083 156.696 ;
     RECT  5.245 78.192 6.085 78.216 ;
     RECT  6.083 147.552 6.113 153.384 ;
     RECT  5.699 181.248 6.113 181.8 ;
     RECT  6.041 204.048 6.113 205.56 ;
     RECT  5.869 12.24 6.133 12.264 ;
     RECT  5.857 226.704 6.14 227.4 ;
     RECT  4.643 192.672 6.145 192.696 ;
     RECT  5.987 236.544 6.149 236.568 ;
     RECT  5.933 180.192 6.179 180.216 ;
     RECT  4.637 229.44 6.181 229.464 ;
     RECT  5.269 73.104 6.185 73.272 ;
     RECT  6.085 78.048 6.185 78.216 ;
     RECT  5.749 207.984 6.185 210.12 ;
     RECT  6.109 25.056 6.193 25.08 ;
     RECT  5.747 52.416 6.221 52.44 ;
     RECT  6.113 147.552 6.221 151.416 ;
     RECT  6.14 226.704 6.227 228.36 ;
     RECT  6.181 229.44 6.227 230.328 ;
     RECT  5.713 99.936 6.229 123.768 ;
     RECT  5.699 124.752 6.229 146.472 ;
     RECT  5.749 196.656 6.229 196.92 ;
     RECT  5.965 14.256 6.275 14.808 ;
     RECT  5.308 61.008 6.277 61.512 ;
     RECT  6.037 62.544 6.277 62.76 ;
     RECT  5.969 84.096 6.277 84.168 ;
     RECT  5.749 167.568 6.277 171 ;
     RECT  5.365 172.032 6.277 173.256 ;
     RECT  6.041 177.6 6.293 178.968 ;
     RECT  5.891 220.608 6.293 220.632 ;
     RECT  6.041 39.216 6.325 39.24 ;
     RECT  6.083 88.176 6.325 98.904 ;
     RECT  6.229 99.936 6.325 146.472 ;
     RECT  5.861 42.096 6.329 42.744 ;
     RECT  6.277 61.008 6.365 62.76 ;
     RECT  6.277 83.232 6.365 84.168 ;
     RECT  6.325 39.216 6.409 39.336 ;
     RECT  4.849 6.816 6.421 6.84 ;
     RECT  5.429 164.112 6.433 166.392 ;
     RECT  6.133 12.24 6.437 12.504 ;
     RECT  5.164 188.64 6.437 188.664 ;
     RECT  6.38 8.976 6.467 9 ;
     RECT  5.869 10.032 6.467 10.44 ;
     RECT  6.365 61.008 6.467 61.56 ;
     RECT  5.315 80.352 6.469 82.152 ;
     RECT  5.797 20.832 6.473 21.336 ;
     RECT  6.469 80.352 6.473 82.632 ;
     RECT  6.421 6.816 6.501 7.752 ;
     RECT  6.229 196.464 6.505 196.92 ;
     RECT  5.893 30.192 6.509 31.32 ;
     RECT  4.588 231.408 6.509 231.432 ;
     RECT  6.113 152.4 6.515 153.384 ;
     RECT  5.507 216.336 6.524 216.36 ;
     RECT  6.253 186.912 6.541 186.936 ;
     RECT  6.473 81.312 6.553 82.632 ;
     RECT  5.605 74.592 6.563 76.92 ;
     RECT  5.177 214.032 6.565 214.056 ;
     RECT  6.524 215.472 6.565 216.36 ;
     RECT  6.505 196.08 6.577 196.92 ;
     RECT  5.033 64.8 6.581 64.824 ;
     RECT  6.113 204.048 6.581 204.744 ;
     RECT  6.227 230.304 6.581 230.328 ;
     RECT  6.329 42.096 6.611 42.696 ;
     RECT  6.565 214.032 6.611 216.36 ;
     RECT  5.969 222 6.617 222.024 ;
     RECT  6.325 88.176 6.659 146.472 ;
     RECT  5.219 198.816 6.661 198.84 ;
     RECT  6.041 176.352 6.685 176.376 ;
     RECT  6.541 186.912 6.707 186.984 ;
     RECT  6.145 192.672 6.716 193.272 ;
     RECT  5.699 57.6 6.725 57.624 ;
     RECT  6.277 167.568 6.757 173.256 ;
     RECT  6.563 76.704 6.761 76.92 ;
     RECT  5.939 50.64 6.797 50.664 ;
     RECT  6.467 61.008 6.797 61.512 ;
     RECT  6.757 167.472 6.797 173.256 ;
     RECT  6.581 204.048 6.797 204.072 ;
     RECT  6.505 190.56 6.803 190.584 ;
     RECT  6.716 192.432 6.803 193.272 ;
     RECT  6.577 196.08 6.803 197.4 ;
     RECT  6.661 198.384 6.803 198.84 ;
     RECT  6.709 239.424 6.833 239.448 ;
     RECT  5.965 34.992 6.997 35.016 ;
     RECT  5.891 158.304 7.045 159.096 ;
     RECT  6.473 20.832 7.189 20.856 ;
     RECT  6.077 160.704 7.189 163.032 ;
     RECT  6.433 164.112 7.189 166.44 ;
     RECT  7.189 160.704 7.237 166.44 ;
     RECT  6.797 167.472 7.237 169.368 ;
     RECT  6.185 73.248 7.333 73.272 ;
     RECT  6.221 147.552 7.333 149.208 ;
     RECT  6.221 150.288 7.333 151.416 ;
     RECT  7.045 158.304 7.333 159.48 ;
     RECT  7.237 160.704 7.333 169.368 ;
     RECT  7.333 147.552 7.513 151.416 ;
     RECT  6.515 152.4 7.513 153.336 ;
     RECT  6.901 207.456 7.513 207.528 ;
     RECT  6.083 154.368 7.573 156.696 ;
     RECT  6.929 200.64 7.621 200.664 ;
     RECT  6.659 146.352 7.628 146.472 ;
     RECT  7.513 207.456 7.649 207.576 ;
     RECT  7.628 146.352 7.657 146.568 ;
     RECT  7.573 154.368 7.669 156.984 ;
     RECT  6.501 7.728 7.808 7.752 ;
     RECT  6.467 10.032 7.808 10.152 ;
     RECT  6.437 12.48 7.808 12.504 ;
     RECT  4.931 17.088 7.808 17.112 ;
     RECT  7.189 20.496 7.808 20.856 ;
     RECT  7.381 23.328 7.808 23.352 ;
     RECT  5.209 26.208 7.808 26.232 ;
     RECT  6.509 30.192 7.808 31.176 ;
     RECT  6.997 34.992 7.808 35.064 ;
     RECT  6.965 36.48 7.808 36.504 ;
     RECT  6.409 39.216 7.808 39.24 ;
     RECT  6.611 42.096 7.808 42.12 ;
     RECT  5.933 47.712 7.808 48.408 ;
     RECT  7.073 49.536 7.808 49.56 ;
     RECT  4.876 53.904 7.808 53.928 ;
     RECT  5.699 59.472 7.808 59.736 ;
     RECT  6.797 61.488 7.808 61.512 ;
     RECT  6.365 62.544 7.808 62.76 ;
     RECT  5.753 66.192 7.808 66.216 ;
     RECT  6.005 67.536 7.808 67.56 ;
     RECT  5.533 69.504 7.808 69.528 ;
     RECT  7.333 73.248 7.808 73.512 ;
     RECT  6.563 74.592 7.808 75.432 ;
     RECT  6.761 76.896 7.808 76.92 ;
     RECT  6.185 78.192 7.808 78.216 ;
     RECT  6.553 81.312 7.808 82.152 ;
     RECT  6.365 84.096 7.808 84.168 ;
     RECT  6.083 85.2 7.808 87.144 ;
     RECT  6.659 88.176 7.808 144.84 ;
     RECT  7.657 146.256 7.808 146.568 ;
     RECT  7.513 147.552 7.808 153.336 ;
     RECT  7.669 154.368 7.808 157.08 ;
     RECT  7.333 158.304 7.808 169.368 ;
     RECT  6.797 170.736 7.808 173.256 ;
     RECT  6.685 175.824 7.808 176.376 ;
     RECT  6.293 177.6 7.808 178.008 ;
     RECT  7.693 180.528 7.808 180.552 ;
     RECT  6.113 181.776 7.808 181.8 ;
     RECT  5.221 183.648 7.808 183.672 ;
     RECT  5.461 185.232 7.808 185.544 ;
     RECT  6.707 186.912 7.808 186.936 ;
     RECT  7.657 192.096 7.808 192.12 ;
     RECT  6.803 193.248 7.808 193.272 ;
     RECT  6.803 196.464 7.808 196.488 ;
     RECT  6.803 198.48 7.808 198.84 ;
     RECT  7.621 199.872 7.808 200.664 ;
     RECT  6.041 202.848 7.808 202.872 ;
     RECT  7.325 205.776 7.808 205.8 ;
     RECT  7.649 206.928 7.808 207.576 ;
     RECT  6.185 209.04 7.808 210.12 ;
     RECT  6.325 212.256 7.808 212.28 ;
     RECT  6.901 213.744 7.808 213.768 ;
     RECT  6.611 214.848 7.808 214.872 ;
     RECT  6.611 216.048 7.808 216.072 ;
     RECT  6.005 217.728 7.808 217.752 ;
     RECT  6.227 226.704 7.808 226.728 ;
     RECT  7.477 229.152 7.808 229.176 ;
     RECT  7.808 2.148 7.912 244.092 ;
     RECT  7.912 2.418 8.104 243.822 ;
     RECT  8.104 164.496 8.129 166.584 ;
     RECT  8.104 62.544 8.201 62.568 ;
     RECT  8.104 9.36 8.243 10.152 ;
     RECT  8.104 11.184 8.243 11.208 ;
     RECT  8.104 12.768 8.243 13.656 ;
     RECT  8.104 180.144 8.243 180.552 ;
     RECT  8.104 158.4 8.273 162.984 ;
     RECT  8.273 158.592 8.309 162.984 ;
     RECT  8.309 158.592 8.332 161.256 ;
     RECT  8.129 164.832 8.339 166.584 ;
     RECT  8.104 79.68 8.345 84.168 ;
     RECT  8.104 147.552 8.345 150.888 ;
     RECT  8.104 225.744 8.417 226.728 ;
     RECT  8.104 154.416 8.435 157.368 ;
     RECT  8.332 160.128 8.435 161.256 ;
     RECT  8.104 23.328 8.453 23.352 ;
     RECT  8.104 181.776 8.453 181.8 ;
     RECT  8.309 162.24 8.489 162.984 ;
     RECT  8.435 154.416 8.525 157.08 ;
     RECT  8.104 190.416 8.569 190.968 ;
     RECT  8.104 175.824 8.579 175.848 ;
     RECT  8.345 150.288 8.597 150.888 ;
     RECT  8.339 166.08 8.705 166.584 ;
     RECT  8.104 205.2 8.723 205.224 ;
     RECT  8.243 13.632 8.915 13.656 ;
     RECT  8.569 190.416 8.915 190.44 ;
     RECT  8.104 85.2 8.921 144.84 ;
     RECT  8.339 164.832 9.011 164.856 ;
     RECT  8.104 152.88 9.109 153.288 ;
     RECT  8.921 88.128 9.133 144.84 ;
     RECT  8.104 145.824 9.133 146.472 ;
     RECT  8.104 169.104 9.133 169.368 ;
     RECT  8.104 209.952 9.133 210.36 ;
     RECT  8.345 79.68 9.137 80.952 ;
     RECT  8.525 154.752 9.137 157.08 ;
     RECT  9.137 79.68 9.169 80.376 ;
     RECT  8.597 150.432 9.169 150.888 ;
     RECT  8.705 166.56 9.169 166.584 ;
     RECT  9.133 168.528 9.169 169.368 ;
     RECT  9.133 88.128 9.173 146.472 ;
     RECT  9.169 150.432 9.173 151.608 ;
     RECT  8.104 217.728 9.203 217.752 ;
     RECT  8.921 85.2 9.208 87.144 ;
     RECT  9.109 152.832 9.209 153.288 ;
     RECT  8.345 82.128 9.241 84.168 ;
     RECT  9.208 85.152 9.241 87.144 ;
     RECT  9.169 166.56 9.241 166.632 ;
     RECT  8.243 180.144 9.251 180.168 ;
     RECT  9.169 168.528 9.317 169.416 ;
     RECT  9.241 18.192 9.325 18.216 ;
     RECT  8.104 203.568 9.349 203.592 ;
     RECT  8.104 31.152 9.395 31.176 ;
     RECT  8.417 225.744 9.395 225.768 ;
     RECT  8.332 158.592 9.421 159.096 ;
     RECT  9.173 150.48 9.425 151.608 ;
     RECT  8.104 36.96 9.443 36.984 ;
     RECT  9.349 203.52 9.443 203.592 ;
     RECT  8.489 162.96 9.457 162.984 ;
     RECT  9.169 79.248 9.461 80.376 ;
     RECT  8.104 170.736 9.491 171.912 ;
     RECT  8.104 234.864 9.539 234.888 ;
     RECT  9.209 152.832 9.637 153.24 ;
     RECT  9.137 154.752 9.641 155.4 ;
     RECT  9.425 150.48 9.677 151.032 ;
     RECT  9.241 166.56 9.713 167.256 ;
     RECT  9.241 82.128 9.745 87.144 ;
     RECT  9.421 158.592 9.745 159.624 ;
     RECT  8.435 160.752 9.745 161.256 ;
     RECT  9.641 154.752 9.817 154.776 ;
     RECT  9.461 79.536 9.821 80.376 ;
     RECT  8.345 147.552 9.853 149.112 ;
     RECT  9.137 156.384 9.853 157.08 ;
     RECT  9.745 158.592 9.853 161.256 ;
     RECT  9.713 167.232 9.929 167.256 ;
     RECT  9.817 154.32 9.961 154.776 ;
     RECT  9.133 209.952 9.971 210.936 ;
     RECT  9.241 164.688 10.033 164.712 ;
     RECT  9.173 88.128 10.037 133.128 ;
     RECT  9.853 147.552 10.056 149.4 ;
     RECT  9.853 156.384 10.109 161.256 ;
     RECT  9.491 170.736 10.115 171.048 ;
     RECT  9.997 167.568 10.211 167.592 ;
     RECT  10.109 158.4 10.253 161.256 ;
     RECT  10.056 146.928 10.259 149.4 ;
     RECT  9.317 169.344 10.259 169.416 ;
     RECT  10.177 42.144 10.261 42.168 ;
     RECT  9.821 79.776 10.285 80.376 ;
     RECT  9.745 81.552 10.285 87.144 ;
     RECT  9.457 162.96 10.289 163.128 ;
     RECT  8.104 206.928 10.307 207.528 ;
     RECT  10.289 163.104 10.321 163.128 ;
     RECT  9.971 209.952 10.355 209.976 ;
     RECT  10.285 79.776 10.397 87.144 ;
     RECT  9.961 154.224 10.397 154.776 ;
     RECT  9.173 134.16 10.403 145.8 ;
     RECT  8.104 48.384 10.405 48.408 ;
     RECT  10.037 88.176 10.465 133.128 ;
     RECT  10.403 134.16 10.465 142.392 ;
     RECT  10.397 154.272 10.469 154.776 ;
     RECT  10.069 77.952 10.541 77.976 ;
     RECT  10.259 148.608 10.541 149.4 ;
     RECT  10.405 47.856 10.577 48.408 ;
     RECT  10.307 206.928 10.577 207.48 ;
     RECT  9.385 43.248 10.595 43.272 ;
     RECT  10.397 79.776 10.613 87.048 ;
     RECT  9.677 150.48 10.643 150.84 ;
     RECT  10.577 48.384 10.685 48.408 ;
     RECT  10.033 164.64 10.753 164.712 ;
     RECT  10.577 206.928 10.757 206.952 ;
     RECT  10.693 78.624 10.825 78.648 ;
     RECT  10.613 79.776 10.825 81.096 ;
     RECT  10.753 164.64 10.825 164.904 ;
     RECT  8.104 196.608 10.825 196.632 ;
     RECT  10.825 78.624 10.829 81.096 ;
     RECT  10.825 164.64 10.861 165.144 ;
     RECT  10.825 196.464 10.865 196.632 ;
     RECT  8.104 237.648 10.883 238.296 ;
     RECT  10.613 82.128 10.901 87.048 ;
     RECT  9.637 152.688 10.901 153.24 ;
     RECT  9.443 203.568 10.931 203.592 ;
     RECT  8.104 75.408 10.969 75.432 ;
     RECT  8.104 73.248 10.997 73.272 ;
     RECT  10.901 82.128 11.045 86.76 ;
     RECT  10.969 75.216 11.053 75.432 ;
     RECT  10.403 143.424 11.077 145.8 ;
     RECT  10.259 146.928 11.077 147.576 ;
     RECT  10.997 73.248 11.081 73.512 ;
     RECT  10.253 158.496 11.113 161.256 ;
     RECT  11.045 82.176 11.117 86.76 ;
     RECT  8.104 20.832 11.189 20.856 ;
     RECT  11.077 143.424 11.219 147.576 ;
     RECT  11.113 158.496 11.221 161.304 ;
     RECT  10.643 150.624 11.261 150.84 ;
     RECT  10.829 78.624 11.369 80.376 ;
     RECT  10.465 88.176 11.401 142.392 ;
     RECT  11.219 143.424 11.401 145.8 ;
     RECT  10.861 164.64 11.401 165.816 ;
     RECT  11.401 164.64 11.441 166.44 ;
     RECT  10.883 238.272 11.459 238.296 ;
     RECT  11.369 78.624 11.477 78.696 ;
     RECT  10.109 156.384 11.545 157.08 ;
     RECT  10.901 152.736 11.581 153.24 ;
     RECT  10.469 154.32 11.581 154.776 ;
     RECT  11.117 82.416 11.585 86.76 ;
     RECT  10.541 148.704 11.617 149.4 ;
     RECT  11.581 152.736 11.621 154.776 ;
     RECT  11.221 158.496 11.653 161.64 ;
     RECT  8.104 199.872 11.699 199.896 ;
     RECT  11.113 46.752 11.725 46.776 ;
     RECT  11.401 88.176 11.747 145.8 ;
     RECT  11.477 78.624 11.764 78.648 ;
     RECT  11.764 78.576 11.765 78.648 ;
     RECT  11.765 78.576 11.881 78.6 ;
     RECT  11.725 46.032 11.891 46.776 ;
     RECT  10.321 163.104 11.969 163.512 ;
     RECT  11.893 21.072 12.017 21.096 ;
     RECT  11.585 83.04 12.053 86.76 ;
     RECT  11.969 163.104 12.053 163.56 ;
     RECT  11.441 164.688 12.053 166.44 ;
     RECT  11.545 155.904 12.085 157.08 ;
     RECT  11.869 168.384 12.085 168.408 ;
     RECT  11.261 150.624 12.089 150.792 ;
     RECT  11.621 153.504 12.089 154.776 ;
     RECT  12.053 163.104 12.089 163.512 ;
     RECT  11.747 88.224 12.193 145.8 ;
     RECT  11.219 146.976 12.193 147.576 ;
     RECT  11.369 79.728 12.337 80.376 ;
     RECT  11.653 158.304 12.337 161.64 ;
     RECT  12.337 79.728 12.469 80.808 ;
     RECT  12.053 83.04 12.553 83.16 ;
     RECT  12.589 151.824 12.697 151.848 ;
     RECT  12.053 84.336 12.733 86.76 ;
     RECT  12.193 88.224 12.733 147.576 ;
     RECT  12.089 150.768 12.733 150.792 ;
     RECT  12.697 151.824 12.733 151.896 ;
     RECT  10.259 169.392 12.805 169.416 ;
     RECT  10.115 170.736 12.805 171 ;
     RECT  12.085 155.808 12.985 157.08 ;
     RECT  11.617 148.608 13.021 149.4 ;
     RECT  12.085 168.24 13.201 168.408 ;
     RECT  8.104 39.216 13.208 39.24 ;
     RECT  11.891 46.032 13.208 46.056 ;
     RECT  12.229 57.6 13.208 57.624 ;
     RECT  11.977 60.672 13.208 60.696 ;
     RECT  8.104 67.536 13.208 67.56 ;
     RECT  11.081 73.248 13.208 73.272 ;
     RECT  11.053 75.408 13.208 75.432 ;
     RECT  12.469 79.728 13.208 81.48 ;
     RECT  12.553 82.8 13.208 83.16 ;
     RECT  12.733 84.336 13.208 147.576 ;
     RECT  13.021 148.608 13.208 149.688 ;
     RECT  12.733 150.768 13.208 151.896 ;
     RECT  12.089 153.504 13.208 154.536 ;
     RECT  12.985 155.712 13.208 157.08 ;
     RECT  12.337 158.304 13.208 161.736 ;
     RECT  12.089 163.248 13.208 163.512 ;
     RECT  12.053 164.688 13.208 165.912 ;
     RECT  13.201 167.568 13.208 168.408 ;
     RECT  12.805 169.392 13.208 171 ;
     RECT  8.104 173.136 13.208 173.16 ;
     RECT  8.104 188.496 13.208 188.52 ;
     RECT  10.865 196.464 13.208 196.488 ;
     RECT  8.104 212.256 13.208 212.28 ;
     RECT  13.208 2.148 13.312 244.092 ;
     RECT  13.312 2.418 13.504 243.822 ;
     RECT  13.504 163.68 13.709 165.72 ;
     RECT  13.504 82.8 13.853 83.064 ;
     RECT  13.504 153.168 13.889 154.536 ;
     RECT  13.889 153.504 13.925 154.536 ;
     RECT  13.709 165.12 14.003 165.72 ;
     RECT  13.504 155.712 14.005 159.192 ;
     RECT  13.504 167.568 14.243 167.88 ;
     RECT  13.504 67.776 14.249 67.8 ;
     RECT  14.003 165.696 14.249 165.72 ;
     RECT  13.504 161.616 14.293 162.504 ;
     RECT  13.504 84.336 14.393 152.088 ;
     RECT  14.393 84.336 14.501 147.048 ;
     RECT  14.005 158.16 14.531 159.192 ;
     RECT  14.293 161.616 14.537 161.64 ;
     RECT  13.853 83.04 14.569 83.064 ;
     RECT  14.501 84.336 14.569 146.952 ;
     RECT  13.504 46.032 14.785 46.056 ;
     RECT  14.531 158.16 14.789 158.664 ;
     RECT  14.005 155.712 14.821 157.08 ;
     RECT  13.709 163.68 14.821 164.088 ;
     RECT  13.504 212.256 14.821 212.28 ;
     RECT  14.785 45.936 14.825 46.056 ;
     RECT  14.569 83.04 14.857 146.952 ;
     RECT  14.243 167.808 14.861 167.88 ;
     RECT  14.821 212.256 14.861 212.376 ;
     RECT  13.504 80.016 14.893 81.624 ;
     RECT  14.857 82.944 14.893 146.952 ;
     RECT  14.393 148.512 14.897 152.088 ;
     RECT  14.789 158.16 14.908 158.52 ;
     RECT  13.504 160.224 14.917 160.584 ;
     RECT  14.893 80.016 15.005 146.952 ;
     RECT  14.908 158.256 15.005 158.52 ;
     RECT  14.917 160.224 15.005 161.352 ;
     RECT  14.821 162.768 15.005 164.088 ;
     RECT  15.005 80.016 15.107 143.208 ;
     RECT  15.107 81.312 15.149 143.208 ;
     RECT  15.107 80.016 15.155 80.328 ;
     RECT  14.861 167.808 15.185 167.832 ;
     RECT  13.504 196.464 15.185 196.488 ;
     RECT  15.155 80.016 15.221 80.232 ;
     RECT  15.221 80.208 15.293 80.232 ;
     RECT  15.005 163.68 15.293 164.088 ;
     RECT  14.821 155.568 15.329 157.08 ;
     RECT  13.504 169.392 15.443 171 ;
     RECT  15.005 160.224 15.545 160.584 ;
     RECT  15.149 81.312 15.653 84.024 ;
     RECT  13.925 153.984 15.653 154.536 ;
     RECT  14.897 148.512 15.725 151.896 ;
     RECT  15.725 151.104 15.797 151.896 ;
     RECT  15.329 155.616 15.901 157.08 ;
     RECT  15.005 158.256 15.901 158.424 ;
     RECT  15.901 155.616 16.013 158.424 ;
     RECT  15.925 196.08 16.013 196.104 ;
     RECT  16.013 155.664 16.049 158.424 ;
     RECT  15.005 144.192 16.115 146.952 ;
     RECT  15.149 85.296 16.153 143.208 ;
     RECT  15.653 81.312 16.261 83.688 ;
     RECT  16.153 166.416 16.265 166.44 ;
     RECT  15.725 148.512 16.333 149.784 ;
     RECT  15.653 154.512 16.373 154.536 ;
     RECT  16.153 85.056 16.405 143.208 ;
     RECT  16.333 148.416 16.405 149.784 ;
     RECT  16.115 144.24 16.409 146.952 ;
     RECT  16.049 155.664 16.499 157.512 ;
     RECT  16.261 80.784 16.553 83.688 ;
     RECT  16.081 162.336 16.589 162.36 ;
     RECT  16.553 80.784 16.693 81.672 ;
     RECT  15.797 151.872 16.729 151.896 ;
     RECT  16.405 148.368 16.909 149.784 ;
     RECT  16.409 144.24 16.913 145.8 ;
     RECT  16.441 158.496 17.017 158.52 ;
     RECT  15.293 163.68 17.017 163.992 ;
     RECT  16.693 80.352 17.093 81.672 ;
     RECT  17.017 158.496 17.201 158.616 ;
     RECT  16.409 146.928 17.269 146.952 ;
     RECT  16.553 82.656 17.305 83.688 ;
     RECT  16.913 144.24 17.377 144.888 ;
     RECT  16.729 151.872 17.381 152.76 ;
     RECT  17.093 80.784 17.453 81.672 ;
     RECT  17.017 163.68 17.453 164.28 ;
     RECT  17.269 146.928 17.557 147.24 ;
     RECT  17.305 82.656 17.561 83.832 ;
     RECT  15.545 160.512 17.597 160.584 ;
     RECT  17.381 151.872 17.629 151.896 ;
     RECT  17.629 151.584 17.737 151.896 ;
     RECT  17.557 145.872 17.797 147.24 ;
     RECT  16.909 148.368 17.797 150.168 ;
     RECT  17.797 145.872 17.809 150.168 ;
     RECT  17.737 151.296 17.809 151.896 ;
     RECT  17.377 144.192 18.141 144.888 ;
     RECT  17.809 145.872 18.141 151.896 ;
     RECT  16.405 84.912 18.169 143.208 ;
     RECT  18.141 144.192 18.169 151.896 ;
     RECT  17.453 80.784 18.229 80.808 ;
     RECT  17.561 82.752 18.241 83.832 ;
     RECT  18.241 82.752 18.385 83.88 ;
     RECT  18.169 84.912 18.385 151.896 ;
     RECT  16.499 155.664 18.449 157.08 ;
     RECT  18.449 155.616 18.469 157.08 ;
     RECT  13.504 39.216 18.608 39.24 ;
     RECT  14.825 45.936 18.608 45.96 ;
     RECT  13.504 60.672 18.608 60.696 ;
     RECT  13.504 73.248 18.608 73.272 ;
     RECT  13.504 75.408 18.608 75.432 ;
     RECT  17.917 78.912 18.608 78.936 ;
     RECT  18.229 80.688 18.608 80.808 ;
     RECT  18.385 82.752 18.608 151.896 ;
     RECT  18.469 154.896 18.608 157.08 ;
     RECT  17.201 158.592 18.608 158.616 ;
     RECT  17.597 160.512 18.608 160.536 ;
     RECT  17.453 164.256 18.608 164.28 ;
     RECT  17.917 165.84 18.608 165.864 ;
     RECT  15.443 169.392 18.608 169.416 ;
     RECT  15.443 170.976 18.608 171 ;
     RECT  13.504 173.136 18.608 173.16 ;
     RECT  13.504 188.496 18.608 188.52 ;
     RECT  14.861 212.352 18.608 212.376 ;
     RECT  18.608 2.148 18.712 244.092 ;
     RECT  18.712 2.418 18.904 243.822 ;
     RECT  18.904 149.136 19.037 150.504 ;
     RECT  18.904 151.872 19.037 152.76 ;
     RECT  18.904 81.216 19.109 147.48 ;
     RECT  19.109 139.104 19.181 147.48 ;
     RECT  19.181 139.2 19.361 147.48 ;
     RECT  18.904 153.888 19.619 154.92 ;
     RECT  19.037 152.736 19.649 152.76 ;
     RECT  19.619 153.888 19.721 154.536 ;
     RECT  18.904 212.352 19.721 212.376 ;
     RECT  18.904 156.096 19.763 157.08 ;
     RECT  18.904 75.072 19.829 75.432 ;
     RECT  19.361 144.288 19.829 147.48 ;
     RECT  18.904 165.84 19.859 165.864 ;
     RECT  19.721 153.888 19.973 153.912 ;
     RECT  19.957 151.056 20.045 151.08 ;
     RECT  19.361 139.2 20.185 143.208 ;
     RECT  18.904 169.392 20.291 169.416 ;
     RECT  19.037 149.136 20.293 149.784 ;
     RECT  19.109 81.216 20.3 83.688 ;
     RECT  19.109 84.672 20.3 138.072 ;
     RECT  18.904 39.216 20.339 39.24 ;
     RECT  19.829 144.288 20.341 145.32 ;
     RECT  19.829 146.976 20.348 147.48 ;
     RECT  20.293 148.944 20.387 149.784 ;
     RECT  20.348 146.976 20.435 147.912 ;
     RECT  20.435 146.976 20.441 147.48 ;
     RECT  20.365 151.248 20.621 151.272 ;
     RECT  20.3 81.216 20.653 138.072 ;
     RECT  20.185 139.104 20.653 143.208 ;
     RECT  20.653 81.216 20.765 143.208 ;
     RECT  18.904 188.496 20.819 188.52 ;
     RECT  20.765 143.184 21.013 143.208 ;
     RECT  20.341 144.192 21.013 145.32 ;
     RECT  21.013 143.184 21.017 145.32 ;
     RECT  18.904 78.912 21.059 78.936 ;
     RECT  18.904 173.136 21.085 173.16 ;
     RECT  21.017 143.184 21.107 144.12 ;
     RECT  21.017 145.296 21.189 145.32 ;
     RECT  20.441 146.976 21.189 147.384 ;
     RECT  21.189 146.976 21.233 147 ;
     RECT  20.765 81.216 21.341 141.912 ;
     RECT  21.107 143.664 21.347 144.12 ;
     RECT  19.763 156.384 21.349 156.408 ;
     RECT  21.301 145.92 21.385 145.944 ;
     RECT  18.904 170.976 21.395 171 ;
     RECT  21.085 172.704 21.395 173.16 ;
     RECT  21.395 173.136 21.413 173.16 ;
     RECT  21.341 81.216 21.629 141.576 ;
     RECT  20.797 212.064 21.635 212.088 ;
     RECT  21.629 81.216 21.683 87.912 ;
     RECT  18.904 73.248 21.769 73.272 ;
     RECT  21.769 73.248 21.923 73.416 ;
     RECT  19.829 75.072 21.923 75.096 ;
     RECT  21.347 143.664 22.061 143.688 ;
     RECT  21.923 73.248 22.133 73.272 ;
     RECT  21.683 81.6 22.355 87.912 ;
     RECT  22.355 81.6 22.385 83.16 ;
     RECT  22.355 84.384 22.529 87.912 ;
     RECT  18.904 60.672 22.547 60.696 ;
     RECT  22.529 84.576 22.637 87.912 ;
     RECT  22.637 84.768 22.741 87.912 ;
     RECT  21.629 88.944 22.741 141.576 ;
     RECT  22.741 84.768 23.605 141.576 ;
     RECT  18.904 45.936 24.008 45.96 ;
     RECT  22.385 81.6 24.008 83.112 ;
     RECT  23.605 84.672 24.008 141.576 ;
     RECT  20.387 149.76 24.008 149.784 ;
     RECT  21.349 156.384 24.008 156.936 ;
     RECT  24.008 2.148 24.112 244.092 ;
     RECT  24.112 2.418 24.304 243.822 ;
     RECT  24.304 85.584 24.581 141.576 ;
     RECT  24.581 85.584 24.611 140.04 ;
     RECT  24.611 85.584 24.689 137.88 ;
     RECT  24.611 138.864 24.755 140.04 ;
     RECT  24.689 85.584 24.977 137.784 ;
     RECT  24.977 85.632 25.121 137.784 ;
     RECT  25.121 85.632 25.157 135.672 ;
     RECT  24.755 138.912 25.157 140.04 ;
     RECT  25.157 85.68 25.445 135.672 ;
     RECT  25.436 84.336 25.523 84.36 ;
     RECT  25.445 85.776 25.589 135.672 ;
     RECT  25.121 137.04 25.589 137.784 ;
     RECT  25.589 85.776 25.625 125.544 ;
     RECT  25.589 126.624 25.697 135.672 ;
     RECT  25.625 89.04 25.733 125.544 ;
     RECT  25.733 89.136 25.769 125.544 ;
     RECT  25.697 126.624 25.811 135.144 ;
     RECT  25.625 85.776 25.877 87.912 ;
     RECT  25.811 126.624 25.955 134.856 ;
     RECT  25.157 138.912 25.981 139.752 ;
     RECT  25.769 89.136 25.985 125.496 ;
     RECT  25.955 126.624 26.051 134.808 ;
     RECT  25.877 86.016 26.057 87.912 ;
     RECT  26.051 126.624 26.057 134.664 ;
     RECT  26.057 130.944 26.093 134.664 ;
     RECT  25.985 89.232 26.201 125.496 ;
     RECT  26.093 132.432 26.201 134.664 ;
     RECT  26.057 86.592 26.236 87.912 ;
     RECT  26.057 126.624 26.291 129.96 ;
     RECT  26.201 132.672 26.339 134.664 ;
     RECT  26.201 90.048 26.387 125.496 ;
     RECT  26.339 132.672 26.525 132.792 ;
     RECT  25.589 137.04 26.531 137.112 ;
     RECT  26.525 132.72 26.627 132.792 ;
     RECT  26.627 132.72 26.633 132.744 ;
     RECT  26.236 87.312 26.741 87.912 ;
     RECT  26.291 126.672 27.059 129.96 ;
     RECT  25.981 138.768 27.107 139.752 ;
     RECT  26.387 90.528 27.251 125.496 ;
     RECT  27.251 90.528 27.389 95.832 ;
     RECT  26.339 134.256 27.389 134.664 ;
     RECT  27.251 96.864 27.533 125.496 ;
     RECT  27.389 95.424 27.569 95.832 ;
     RECT  27.533 96.864 27.569 124.008 ;
     RECT  27.569 97.056 27.605 124.008 ;
     RECT  26.531 137.088 27.605 137.112 ;
     RECT  27.059 129.936 27.635 129.96 ;
     RECT  27.605 97.056 27.749 99.144 ;
     RECT  24.304 81.6 27.779 82.968 ;
     RECT  27.533 125.088 27.785 125.496 ;
     RECT  27.605 116.88 27.821 124.008 ;
     RECT  27.605 100.224 27.875 115.464 ;
     RECT  27.821 116.976 27.893 124.008 ;
     RECT  27.875 100.224 27.923 110.328 ;
     RECT  27.875 114.96 27.923 115.464 ;
     RECT  27.893 117.216 27.923 124.008 ;
     RECT  27.923 120.192 27.929 124.008 ;
     RECT  27.929 120.192 27.965 122.664 ;
     RECT  27.779 82.944 27.971 82.968 ;
     RECT  27.923 117.216 27.971 119.16 ;
     RECT  27.971 118.608 28.009 119.16 ;
     RECT  27.923 108.144 28.019 110.328 ;
     RECT  24.581 141.552 28.019 141.576 ;
     RECT  27.779 81.6 28.067 81.624 ;
     RECT  28.019 109.008 28.067 110.328 ;
     RECT  27.923 114.96 28.067 114.984 ;
     RECT  26.093 130.944 28.067 131.064 ;
     RECT  27.389 90.528 28.115 91.32 ;
     RECT  27.971 117.408 28.115 117.432 ;
     RECT  27.875 111.312 28.145 113.448 ;
     RECT  27.389 92.4 28.211 93.528 ;
     RECT  26.741 87.312 29.408 87.336 ;
     RECT  28.115 91.296 29.408 91.32 ;
     RECT  28.211 92.4 29.408 92.424 ;
     RECT  28.211 93.504 29.408 93.528 ;
     RECT  27.569 95.424 29.408 95.496 ;
     RECT  27.749 97.056 29.408 99.048 ;
     RECT  27.923 100.224 29.408 106.872 ;
     RECT  28.067 109.008 29.408 110.04 ;
     RECT  28.145 111.312 29.408 112.92 ;
     RECT  28.009 118.608 29.408 118.872 ;
     RECT  27.965 120.192 29.408 120.216 ;
     RECT  27.965 121.392 29.408 122.664 ;
     RECT  27.929 123.792 29.408 124.008 ;
     RECT  27.785 125.472 29.408 125.496 ;
     RECT  27.059 126.672 29.408 128.952 ;
     RECT  28.067 131.04 29.408 131.064 ;
     RECT  27.389 134.64 29.408 134.664 ;
     RECT  27.107 139.728 29.408 139.752 ;
     RECT  24.304 149.76 29.408 149.784 ;
     RECT  24.304 156.384 29.408 156.936 ;
     RECT  29.408 2.148 29.512 244.092 ;
     RECT  29.512 2.418 29.704 243.822 ;
     RECT  29.704 121.968 29.765 122.664 ;
     RECT  29.704 126.672 29.837 128.952 ;
     RECT  29.704 97.056 30.233 99.048 ;
     RECT  29.765 121.968 30.233 122.136 ;
     RECT  30.233 97.824 30.269 99.048 ;
     RECT  29.704 102.912 30.269 106.872 ;
     RECT  29.704 111.936 30.269 112.92 ;
     RECT  30.269 104.544 30.737 106.872 ;
     RECT  29.704 123.792 30.773 124.008 ;
     RECT  30.737 104.544 30.809 105.144 ;
     RECT  29.704 118.608 30.809 118.632 ;
     RECT  29.704 120.192 30.809 120.216 ;
     RECT  30.269 102.912 31.313 103.512 ;
     RECT  29.704 109.008 31.957 109.848 ;
     RECT  31.957 109.008 32.041 109.992 ;
     RECT  32.041 109.008 33.041 109.848 ;
     RECT  30.809 104.544 33.437 105.096 ;
     RECT  29.837 128.688 33.473 128.952 ;
     RECT  29.704 91.296 34.808 91.32 ;
     RECT  29.704 92.4 34.808 92.424 ;
     RECT  29.704 95.424 34.808 95.448 ;
     RECT  30.269 97.824 34.808 97.848 ;
     RECT  30.269 98.88 34.808 99.048 ;
     RECT  29.704 100.224 34.808 101.592 ;
     RECT  31.313 102.912 34.808 102.936 ;
     RECT  33.437 105.072 34.808 105.096 ;
     RECT  30.737 106.176 34.808 106.872 ;
     RECT  33.041 109.824 34.808 109.848 ;
     RECT  30.269 112.896 34.808 112.92 ;
     RECT  30.233 121.968 34.808 121.992 ;
     RECT  30.773 123.984 34.808 124.008 ;
     RECT  29.704 125.472 34.808 125.496 ;
     RECT  29.837 126.672 34.808 127.512 ;
     RECT  33.473 128.688 34.808 128.712 ;
     RECT  29.704 131.04 34.808 131.064 ;
     RECT  31.957 132.096 34.808 132.12 ;
     RECT  29.704 134.64 34.808 134.664 ;
     RECT  29.704 156.384 34.808 156.936 ;
     RECT  34.808 2.148 34.912 244.092 ;
     RECT  34.912 2.418 35.104 243.822 ;
     RECT  35.104 125.472 37.001 125.496 ;
     RECT  35.104 92.4 38.045 92.424 ;
     RECT  35.104 91.296 38.761 91.32 ;
     RECT  35.104 126.672 38.761 127.512 ;
     RECT  38.761 91.296 38.801 91.416 ;
     RECT  38.761 126.672 38.801 127.608 ;
     RECT  38.801 91.392 40.208 91.416 ;
     RECT  38.149 92.496 40.208 92.52 ;
     RECT  35.104 95.424 40.208 95.448 ;
     RECT  35.104 97.824 40.208 97.848 ;
     RECT  35.104 98.88 40.208 99.048 ;
     RECT  35.104 100.224 40.208 101.16 ;
     RECT  35.104 102.912 40.208 102.936 ;
     RECT  35.104 105.072 40.208 105.096 ;
     RECT  35.104 106.848 40.208 106.872 ;
     RECT  35.104 109.824 40.208 109.848 ;
     RECT  35.104 112.896 40.208 112.92 ;
     RECT  35.104 121.968 40.208 121.992 ;
     RECT  35.104 123.984 40.208 124.008 ;
     RECT  38.801 126.768 40.208 127.608 ;
     RECT  35.104 128.688 40.208 128.712 ;
     RECT  35.104 131.04 40.208 131.064 ;
     RECT  35.104 132.096 40.208 132.12 ;
     RECT  35.104 156.384 40.208 156.936 ;
     RECT  40.208 2.148 40.312 244.092 ;
     RECT  40.312 2.418 40.504 243.822 ;
     RECT  40.504 102.768 41.141 102.792 ;
     RECT  40.504 131.04 41.321 131.064 ;
     RECT  40.504 97.824 41.861 97.848 ;
     RECT  40.504 126.768 43.085 127.608 ;
     RECT  40.504 91.392 43.121 91.416 ;
     RECT  43.085 126.768 43.697 126.792 ;
     RECT  40.504 123.984 43.805 124.008 ;
     RECT  40.504 92.496 45.608 92.52 ;
     RECT  40.504 98.88 45.608 99.048 ;
     RECT  40.504 100.224 45.608 101.16 ;
     RECT  40.504 105.072 45.608 105.096 ;
     RECT  40.504 106.848 45.608 106.872 ;
     RECT  40.504 112.896 45.608 112.92 ;
     RECT  40.504 121.968 45.608 121.992 ;
     RECT  40.504 128.688 45.608 128.712 ;
     RECT  40.504 132.096 45.608 132.12 ;
     RECT  40.504 156.384 45.608 156.792 ;
     RECT  45.608 2.148 45.712 244.092 ;
     RECT  45.712 2.418 45.904 243.822 ;
     RECT  45.904 92.496 51.008 92.52 ;
     RECT  45.904 98.88 51.008 99.048 ;
     RECT  45.904 100.224 51.008 101.16 ;
     RECT  45.904 105.072 51.008 105.096 ;
     RECT  45.904 106.848 51.008 106.872 ;
     RECT  45.904 112.896 51.008 112.92 ;
     RECT  45.904 121.968 51.008 121.992 ;
     RECT  45.904 132.096 51.008 132.12 ;
     RECT  45.904 156.384 51.008 156.792 ;
     RECT  51.008 2.148 51.112 244.092 ;
     RECT  51.112 2.418 51.304 243.822 ;
     RECT  51.304 92.496 51.905 92.52 ;
     RECT  51.304 112.896 52.765 112.92 ;
     RECT  51.304 113.952 52.765 113.976 ;
     RECT  52.757 95.712 52.841 95.736 ;
     RECT  52.765 112.896 52.849 113.976 ;
     RECT  52.849 113.952 53.315 113.976 ;
     RECT  53.269 123.12 53.413 123.144 ;
     RECT  53.413 123.12 53.459 123.528 ;
     RECT  53.405 135.072 53.489 135.096 ;
     RECT  51.304 98.88 54.709 99.048 ;
     RECT  54.925 135.648 55.009 135.672 ;
     RECT  55.825 92.448 56.408 92.472 ;
     RECT  54.709 98.88 56.408 99.192 ;
     RECT  51.304 100.224 56.408 101.16 ;
     RECT  51.304 105.072 56.408 105.096 ;
     RECT  51.304 106.848 56.408 106.872 ;
     RECT  52.849 112.896 56.408 112.92 ;
     RECT  51.304 121.968 56.408 121.992 ;
     RECT  53.459 123.504 56.408 123.528 ;
     RECT  51.304 132.096 56.408 132.12 ;
     RECT  51.304 156.384 56.408 156.792 ;
     RECT  56.408 2.148 56.512 244.092 ;
     RECT  56.512 2.418 56.704 243.822 ;
     RECT  56.704 98.88 58.313 99.192 ;
     RECT  56.704 100.224 58.385 101.16 ;
     RECT  56.704 123.504 60.901 123.528 ;
     RECT  56.704 92.448 61.808 92.472 ;
     RECT  58.313 98.88 61.808 98.904 ;
     RECT  58.385 101.136 61.808 101.16 ;
     RECT  56.704 105.072 61.808 105.096 ;
     RECT  56.704 106.848 61.808 106.872 ;
     RECT  56.704 112.896 61.808 112.92 ;
     RECT  56.704 121.968 61.808 121.992 ;
     RECT  60.901 123.504 61.808 124.248 ;
     RECT  56.704 132.096 61.808 132.12 ;
     RECT  56.704 156.384 61.808 156.792 ;
     RECT  61.808 2.148 61.912 244.092 ;
     RECT  61.912 2.418 62.104 243.822 ;
     RECT  62.104 101.136 62.165 101.16 ;
     RECT  62.104 92.448 64.757 92.472 ;
     RECT  66.265 92.4 67.208 92.424 ;
     RECT  62.104 105.072 67.208 105.096 ;
     RECT  62.104 106.848 67.208 106.872 ;
     RECT  62.104 112.896 67.208 112.92 ;
     RECT  62.104 121.968 67.208 121.992 ;
     RECT  62.104 123.504 67.208 123.528 ;
     RECT  62.104 132.096 67.208 132.12 ;
     RECT  62.104 156.384 67.208 156.792 ;
     RECT  67.208 2.148 67.312 244.092 ;
     RECT  67.312 2.418 67.504 243.822 ;
     RECT  67.504 92.4 72.608 92.424 ;
     RECT  67.504 105.072 72.608 105.096 ;
     RECT  67.504 106.848 72.608 106.872 ;
     RECT  67.504 112.896 72.608 112.92 ;
     RECT  67.504 121.968 72.608 121.992 ;
     RECT  67.504 123.504 72.608 123.528 ;
     RECT  67.504 132.096 72.608 132.12 ;
     RECT  67.504 156.384 72.608 156.696 ;
     RECT  72.608 2.148 72.712 244.092 ;
     RECT  72.712 2.418 72.904 243.822 ;
     RECT  72.904 156.384 74.513 156.696 ;
     RECT  72.904 123.504 74.653 123.528 ;
     RECT  74.653 123.408 74.693 123.528 ;
     RECT  74.513 156.672 74.797 156.696 ;
     RECT  74.797 156.672 74.881 156.744 ;
     RECT  74.693 123.408 76.741 123.432 ;
     RECT  72.904 132.096 77.605 132.12 ;
     RECT  77.893 243.6 77.921 243.624 ;
     RECT  77.921 243.6 78.005 244.248 ;
     RECT  72.904 92.4 78.008 92.424 ;
     RECT  72.904 105.072 78.008 105.096 ;
     RECT  72.904 106.848 78.008 106.872 ;
     RECT  72.904 112.896 78.008 112.92 ;
     RECT  72.904 121.968 78.008 121.992 ;
     RECT  76.741 123.408 78.008 123.576 ;
     RECT  77.605 132.096 78.008 132.216 ;
     RECT  77.605 154.032 78.008 154.056 ;
     RECT  74.881 156.672 78.008 156.696 ;
     RECT  74.821 225.744 78.008 225.768 ;
     RECT  77.893 241.488 78.008 241.512 ;
     RECT  78.005 243.6 78.008 244.092 ;
     RECT  78.008 2.148 78.112 244.092 ;
     RECT  78.112 2.418 78.304 243.822 ;
     RECT  78.304 105.072 80.053 105.096 ;
     RECT  78.304 92.4 80.099 92.424 ;
     RECT  80.053 111.744 80.137 111.768 ;
     RECT  78.304 112.896 82.021 112.92 ;
     RECT  82.021 112.896 82.067 113.208 ;
     RECT  80.053 105.072 83.408 105.144 ;
     RECT  78.304 106.848 83.408 106.872 ;
     RECT  82.067 113.184 83.408 113.208 ;
     RECT  78.304 121.968 83.408 121.992 ;
     RECT  78.304 153.936 83.408 153.96 ;
     RECT  78.304 156.672 83.408 156.696 ;
     RECT  83.408 2.148 83.512 244.092 ;
     RECT  83.512 2.418 83.704 243.822 ;
     RECT  83.704 105.072 85.313 105.144 ;
     RECT  85.313 105.072 88.808 105.096 ;
     RECT  83.704 106.848 88.808 106.872 ;
     RECT  83.704 113.184 88.808 113.208 ;
     RECT  83.704 121.968 88.808 121.992 ;
     RECT  83.704 153.936 88.808 153.96 ;
     RECT  83.704 156.672 88.808 156.696 ;
     RECT  88.808 2.148 88.912 244.092 ;
     RECT  88.912 2.418 89.104 243.822 ;
     RECT  89.104 105.072 94.208 105.096 ;
     RECT  89.104 106.848 94.208 106.872 ;
     RECT  89.104 113.184 94.208 113.208 ;
     RECT  89.104 121.968 94.208 121.992 ;
     RECT  89.104 153.936 94.208 153.96 ;
     RECT  89.104 156.672 94.208 156.696 ;
     RECT  94.208 2.148 94.312 244.092 ;
     RECT  94.312 2.418 94.504 243.822 ;
     RECT  94.504 105.072 99.608 105.096 ;
     RECT  94.504 106.848 99.608 106.872 ;
     RECT  94.504 113.184 99.608 113.208 ;
     RECT  94.504 121.968 99.608 121.992 ;
     RECT  94.504 153.936 99.608 153.96 ;
     RECT  94.504 156.672 99.608 156.696 ;
     RECT  99.608 2.148 99.712 244.092 ;
     RECT  99.712 2.418 99.904 243.822 ;
     RECT  99.904 156.672 101.513 156.696 ;
     RECT  99.904 105.072 105.008 105.096 ;
     RECT  99.904 106.848 105.008 106.872 ;
     RECT  99.904 113.184 105.008 113.208 ;
     RECT  99.904 121.968 105.008 121.992 ;
     RECT  99.904 153.936 105.008 153.96 ;
     RECT  103.021 156.672 105.008 156.696 ;
     RECT  105.008 2.148 105.112 244.092 ;
     RECT  105.112 2.418 105.304 243.822 ;
     RECT  105.304 105.072 110.408 105.096 ;
     RECT  105.304 106.848 110.408 106.872 ;
     RECT  105.304 113.184 110.408 113.208 ;
     RECT  105.304 121.968 110.408 121.992 ;
     RECT  105.304 153.936 110.408 153.96 ;
     RECT  105.304 156.672 110.408 156.696 ;
     RECT  110.408 2.148 110.512 244.092 ;
     RECT  110.512 2.418 110.704 243.822 ;
     RECT  110.704 105.072 115.808 105.096 ;
     RECT  110.704 106.848 115.808 106.872 ;
     RECT  110.704 113.184 115.808 113.208 ;
     RECT  110.704 121.968 115.808 121.992 ;
     RECT  110.704 153.936 115.808 153.96 ;
     RECT  110.704 156.672 115.808 156.696 ;
     RECT  115.808 2.148 115.912 244.092 ;
     RECT  115.912 2.418 116.104 243.822 ;
     RECT  116.104 153.936 121.052 153.96 ;
     RECT  116.104 121.968 121.093 121.992 ;
     RECT  116.104 105.072 121.208 105.096 ;
     RECT  116.104 106.848 121.208 106.872 ;
     RECT  116.104 113.184 121.208 113.208 ;
     RECT  121.093 121.968 121.208 122.952 ;
     RECT  121.052 153.888 121.208 153.96 ;
     RECT  116.104 156.672 121.208 156.696 ;
     RECT  121.208 2.148 121.312 244.092 ;
     RECT  121.312 2.418 121.504 243.822 ;
     RECT  121.504 105.072 126.608 105.096 ;
     RECT  121.504 106.848 126.608 106.872 ;
     RECT  121.504 113.184 126.608 113.208 ;
     RECT  121.504 121.968 126.608 122.952 ;
     RECT  121.504 153.936 126.608 153.96 ;
     RECT  121.504 156.672 126.608 156.696 ;
     RECT  126.608 2.148 126.712 244.092 ;
     RECT  126.712 2.418 126.904 243.822 ;
     RECT  126.904 105.072 132.008 105.096 ;
     RECT  126.904 106.848 132.008 106.872 ;
     RECT  126.904 113.184 132.008 113.208 ;
     RECT  126.904 121.968 132.008 122.952 ;
     RECT  126.904 153.936 132.008 153.96 ;
     RECT  126.904 156.672 132.008 156.696 ;
     RECT  132.008 2.148 132.112 244.092 ;
     RECT  132.112 2.418 132.304 243.822 ;
     RECT  132.304 105.072 137.408 105.096 ;
     RECT  132.304 106.848 137.408 106.872 ;
     RECT  132.304 113.184 137.408 113.208 ;
     RECT  132.304 121.968 137.408 122.952 ;
     RECT  132.304 153.936 137.408 153.96 ;
     RECT  132.304 156.672 137.408 156.696 ;
     RECT  137.408 2.148 137.512 244.092 ;
     RECT  137.512 2.418 137.704 243.822 ;
     RECT  137.704 105.072 142.808 105.096 ;
     RECT  137.704 106.848 142.808 106.872 ;
     RECT  137.704 113.184 142.808 113.208 ;
     RECT  137.704 121.968 142.808 122.952 ;
     RECT  137.704 153.936 142.808 153.96 ;
     RECT  137.704 156.672 142.808 156.696 ;
     RECT  142.808 2.148 142.912 244.092 ;
     RECT  142.912 2.418 143.104 243.822 ;
     RECT  143.104 105.072 144.781 105.096 ;
     RECT  144.781 104.928 144.821 105.096 ;
     RECT  146.341 110.88 146.428 110.904 ;
     RECT  143.104 153.936 146.473 153.96 ;
     RECT  146.041 124.8 146.483 124.824 ;
     RECT  143.104 121.968 146.725 122.952 ;
     RECT  146.645 98.064 146.729 98.088 ;
     RECT  146.437 125.808 146.761 125.832 ;
     RECT  146.761 125.712 146.801 125.832 ;
     RECT  146.725 121.968 146.809 123.144 ;
     RECT  145.969 94.8 147.089 94.824 ;
     RECT  146.149 115.68 147.155 115.704 ;
     RECT  146.473 153.936 147.26 154.056 ;
     RECT  146.221 134.304 147.301 134.328 ;
     RECT  143.104 113.184 147.445 113.208 ;
     RECT  146.809 121.968 147.445 122.376 ;
     RECT  147.301 133.344 147.445 134.328 ;
     RECT  147.109 117.504 147.949 117.528 ;
     RECT  146.005 93.168 148.208 93.192 ;
     RECT  146.257 96.576 148.208 96.6 ;
     RECT  147.229 101.712 148.208 101.736 ;
     RECT  144.821 104.928 148.208 104.952 ;
     RECT  143.104 106.848 148.208 106.872 ;
     RECT  147.085 108.624 148.208 108.648 ;
     RECT  146.221 112.032 148.208 112.056 ;
     RECT  147.445 113.184 148.208 114.024 ;
     RECT  147.949 117.072 148.208 117.528 ;
     RECT  147.205 119.04 148.208 119.064 ;
     RECT  147.589 120.24 148.208 120.264 ;
     RECT  147.445 121.296 148.208 122.376 ;
     RECT  147.841 123.84 148.208 123.864 ;
     RECT  146.801 125.712 148.208 125.736 ;
     RECT  147.985 127.296 148.208 127.32 ;
     RECT  146.221 131.568 148.208 131.592 ;
     RECT  147.445 132.912 148.208 134.328 ;
     RECT  147.445 136.224 148.208 136.248 ;
     RECT  146.941 138.336 148.208 138.36 ;
     RECT  147.841 141.648 148.208 141.672 ;
     RECT  147.013 144.912 148.208 144.936 ;
     RECT  147.301 146.784 148.208 146.808 ;
     RECT  147.301 149.904 148.208 150.456 ;
     RECT  147.085 151.728 148.208 151.752 ;
     RECT  147.26 153.648 148.208 154.056 ;
     RECT  143.104 156.672 148.208 156.696 ;
     RECT  148.208 2.148 148.312 244.092 ;
     RECT  148.312 2.418 148.504 243.822 ;
     RECT  148.504 94.416 148.601 96.6 ;
     RECT  148.504 101.712 148.601 101.736 ;
     RECT  148.504 125.712 148.643 131.592 ;
     RECT  148.504 138.336 148.643 138.36 ;
     RECT  148.643 125.712 148.673 127.32 ;
     RECT  148.643 130.32 148.704 131.592 ;
     RECT  148.504 98.256 148.787 98.28 ;
     RECT  148.504 147.984 148.787 150.456 ;
     RECT  148.504 107.712 148.835 110.04 ;
     RECT  148.504 114.528 148.835 115.32 ;
     RECT  148.504 116.64 148.835 117.096 ;
     RECT  148.504 113.184 148.853 113.496 ;
     RECT  148.853 113.184 148.889 113.352 ;
     RECT  148.787 147.984 148.889 148.824 ;
     RECT  148.835 107.712 148.925 109.416 ;
     RECT  148.504 141.36 148.925 144.936 ;
     RECT  148.673 126.48 148.933 127.32 ;
     RECT  148.504 118.32 148.997 118.344 ;
     RECT  148.925 144.144 148.997 144.936 ;
     RECT  148.504 104.928 149.075 104.952 ;
     RECT  148.504 132.864 149.097 132.936 ;
     RECT  148.504 103.488 149.116 103.752 ;
     RECT  148.933 127.2 149.177 127.32 ;
     RECT  148.504 146.784 149.213 146.808 ;
     RECT  148.787 150.384 149.219 150.456 ;
     RECT  148.504 156.672 149.219 156.696 ;
     RECT  148.601 94.416 149.315 95.832 ;
     RECT  149.116 103.728 149.393 103.752 ;
     RECT  149.219 150.432 149.564 150.456 ;
     RECT  148.504 151.968 149.564 151.992 ;
     RECT  148.504 154.032 149.569 154.056 ;
     RECT  148.704 131.568 149.645 131.592 ;
     RECT  149.564 150.432 149.651 151.992 ;
     RECT  148.835 114.528 149.753 114.552 ;
     RECT  149.569 153.888 149.753 154.056 ;
     RECT  148.925 107.712 149.789 107.736 ;
     RECT  148.643 128.976 149.789 129 ;
     RECT  149.097 132.912 149.845 132.936 ;
     RECT  149.753 153.888 149.845 153.912 ;
     RECT  149.845 132.912 149.891 133.56 ;
     RECT  149.651 151.968 149.891 151.992 ;
     RECT  149.845 153.072 149.891 153.912 ;
     RECT  148.504 120.24 149.893 120.264 ;
     RECT  148.504 123.84 149.893 123.864 ;
     RECT  149.651 150.432 149.897 150.456 ;
     RECT  148.504 99.696 149.933 99.72 ;
     RECT  149.893 119.904 149.933 120.264 ;
     RECT  149.891 153.072 149.933 153.096 ;
     RECT  149.893 123.84 149.939 124.824 ;
     RECT  148.925 141.36 149.939 142.488 ;
     RECT  149.996 105.888 150.083 105.912 ;
     RECT  148.504 139.584 150.181 139.608 ;
     RECT  149.939 141.36 150.221 141.384 ;
     RECT  149.713 101.424 150.229 101.448 ;
     RECT  150.188 135.84 150.229 135.864 ;
     RECT  148.889 113.328 150.257 113.352 ;
     RECT  150.229 100.848 150.275 102.408 ;
     RECT  150.229 135.6 150.275 135.864 ;
     RECT  148.504 122.112 150.284 122.136 ;
     RECT  150.037 104.256 150.293 104.28 ;
     RECT  150.275 102.384 150.316 102.408 ;
     RECT  150.284 122.064 150.325 122.136 ;
     RECT  149.891 133.536 150.336 133.56 ;
     RECT  150.284 118.224 150.371 118.248 ;
     RECT  149.933 119.904 150.371 119.928 ;
     RECT  150.001 136.944 150.401 136.968 ;
     RECT  148.925 109.392 150.421 109.416 ;
     RECT  149.177 127.2 150.421 127.224 ;
     RECT  150.421 109.392 150.467 109.704 ;
     RECT  150.361 111.024 150.467 111.048 ;
     RECT  150.361 112.656 150.467 112.68 ;
     RECT  150.421 126.816 150.467 127.224 ;
     RECT  149.893 146.448 150.469 146.472 ;
     RECT  148.889 148.8 150.469 148.824 ;
     RECT  150.325 121.968 150.509 122.136 ;
     RECT  150.181 139.056 150.509 139.608 ;
     RECT  150.469 146.448 150.515 148.824 ;
     RECT  150.109 98.64 150.565 98.664 ;
     RECT  150.565 97.92 150.611 98.664 ;
     RECT  148.704 130.32 150.617 130.344 ;
     RECT  150.515 147.216 150.617 148.2 ;
     RECT  150.611 97.92 150.653 97.944 ;
     RECT  150.275 100.848 150.653 100.872 ;
     RECT  150.421 128.256 150.653 128.28 ;
     RECT  148.835 116.64 150.725 116.664 ;
     RECT  149.939 124.8 150.761 124.824 ;
     RECT  149.315 95.808 150.805 95.832 ;
     RECT  148.504 92.544 150.851 92.568 ;
     RECT  150.764 94.176 150.851 94.2 ;
     RECT  148.997 144.144 150.86 144.168 ;
     RECT  150.467 126.816 150.869 126.84 ;
     RECT  150.617 147.216 150.869 147.24 ;
     RECT  150.805 95.568 150.899 95.832 ;
     RECT  150.86 143.904 150.905 144.168 ;
     RECT  150.829 96.912 150.913 96.936 ;
     RECT  150.899 95.568 150.941 95.688 ;
     RECT  149.939 142.464 150.947 142.488 ;
     RECT  150.905 143.904 150.947 143.928 ;
     RECT  150.509 121.968 151.157 121.992 ;
     RECT  150.275 135.6 151.157 135.624 ;
     RECT  150.467 109.68 151.193 109.704 ;
     RECT  151.153 139.632 151.445 139.656 ;
     RECT  153.565 94.992 153.889 95.016 ;
     RECT  153.565 120.48 153.889 120.504 ;
     RECT  153.313 134.304 153.889 134.328 ;
     RECT  153.853 153.312 153.889 153.336 ;
     RECT  153.853 91.968 154.429 91.992 ;
     RECT  152.917 93.264 154.429 93.288 ;
     RECT  153.889 94.56 154.429 95.016 ;
     RECT  153.853 99.312 154.429 99.336 ;
     RECT  153.889 101.472 154.429 101.496 ;
     RECT  153.853 103.2 154.429 103.224 ;
     RECT  153.889 105.792 154.429 105.816 ;
     RECT  153.853 107.088 154.429 107.112 ;
     RECT  153.889 111.408 154.429 111.432 ;
     RECT  153.889 120.48 154.429 120.936 ;
     RECT  153.889 126.096 154.429 126.12 ;
     RECT  153.493 128.688 154.429 128.712 ;
     RECT  154.393 130.416 154.429 130.44 ;
     RECT  154.393 131.712 154.429 131.736 ;
     RECT  153.889 133.872 154.429 134.328 ;
     RECT  153.313 135.6 154.429 135.624 ;
     RECT  153.853 139.488 154.429 139.512 ;
     RECT  153.853 143.808 154.429 143.832 ;
     RECT  153.853 145.104 154.429 145.128 ;
     RECT  153.889 153.312 154.429 153.768 ;
     RECT  154.429 91.968 155.484 154.2 ;
    LAYER M5 ;
     RECT  2.4 2.137 2.52 2.151 ;
     RECT  7.8 2.137 7.92 2.151 ;
     RECT  13.2 2.137 13.32 2.151 ;
     RECT  18.6 2.137 18.72 2.151 ;
     RECT  24 2.137 24.12 2.151 ;
     RECT  29.4 2.137 29.52 2.151 ;
     RECT  34.8 2.137 34.92 2.151 ;
     RECT  40.2 2.137 40.32 2.151 ;
     RECT  45.6 2.137 45.72 2.151 ;
     RECT  51 2.137 51.12 2.151 ;
     RECT  56.4 2.137 56.52 2.151 ;
     RECT  61.8 2.137 61.92 2.151 ;
     RECT  67.2 2.137 67.32 2.151 ;
     RECT  72.6 2.137 72.72 2.151 ;
     RECT  78 2.137 78.12 2.151 ;
     RECT  83.4 2.137 83.52 2.151 ;
     RECT  88.8 2.137 88.92 2.151 ;
     RECT  94.2 2.137 94.32 2.151 ;
     RECT  99.6 2.137 99.72 2.151 ;
     RECT  105 2.137 105.12 2.151 ;
     RECT  110.4 2.137 110.52 2.151 ;
     RECT  115.8 2.137 115.92 2.151 ;
     RECT  121.2 2.137 121.32 2.151 ;
     RECT  126.6 2.137 126.72 2.151 ;
     RECT  132 2.137 132.12 2.151 ;
     RECT  137.4 2.137 137.52 2.151 ;
     RECT  142.8 2.137 142.92 2.151 ;
     RECT  148.2 2.137 148.32 2.151 ;
     RECT  2.4 2.151 2.712 6.181 ;
     RECT  2.4 6.181 3.24 7.957 ;
     RECT  7.8 2.151 8.112 9.349 ;
     RECT  6.432 6.805 6.456 10.405 ;
     RECT  6.24 10.405 6.456 10.451 ;
     RECT  4.896 10.741 4.92 11.365 ;
     RECT  6.24 10.451 6.264 11.365 ;
     RECT  2.4 7.957 3.288 13.091 ;
     RECT  7.8 9.349 8.232 13.621 ;
     RECT  4.896 11.365 6.264 16.981 ;
     RECT  7.8 13.621 8.904 18.181 ;
     RECT  4.656 16.981 6.264 18.851 ;
     RECT  0.528 14.485 0.552 19.237 ;
     RECT  2.4 13.091 2.712 19.333 ;
     RECT  4.896 18.851 6.264 20.485 ;
     RECT  7.8 18.181 9.288 20.485 ;
     RECT  2.4 19.333 3.624 20.531 ;
     RECT  4.896 20.485 9.288 22.741 ;
     RECT  4.56 22.741 9.288 25.427 ;
     RECT  5.376 25.427 9.288 27.205 ;
     RECT  4.512 27.205 9.288 29.075 ;
     RECT  4.704 29.075 9.288 30.709 ;
     RECT  3.936 30.709 9.288 30.851 ;
     RECT  5.376 30.851 9.288 31.141 ;
     RECT  3.936 30.851 3.96 31.285 ;
     RECT  3.744 31.285 3.96 33.683 ;
     RECT  3.744 33.683 3.768 35.845 ;
     RECT  5.376 31.141 9.384 35.845 ;
     RECT  3.744 35.845 9.384 36.419 ;
     RECT  5.376 36.419 9.384 36.949 ;
     RECT  3.744 36.419 4.2 38.243 ;
     RECT  3.936 38.243 3.96 39.637 ;
     RECT  5.376 36.949 9.432 40.405 ;
     RECT  3.792 39.637 3.96 41.027 ;
     RECT  3.936 41.027 3.96 41.797 ;
     RECT  5.088 40.405 9.432 41.797 ;
     RECT  3.936 41.797 9.432 42.133 ;
     RECT  3.936 42.133 10.248 43.237 ;
     RECT  24 2.151 24.312 45.925 ;
     RECT  11.904 21.061 11.928 46.741 ;
     RECT  2.4 20.531 2.712 47.701 ;
     RECT  2.256 47.701 2.712 48.373 ;
     RECT  11.856 46.741 11.928 57.589 ;
     RECT  13.2 2.151 13.512 57.589 ;
     RECT  23.04 45.925 24.312 60.661 ;
     RECT  2.208 48.373 2.712 66.181 ;
     RECT  2.208 66.181 2.808 66.611 ;
     RECT  11.856 57.589 13.512 67.765 ;
     RECT  22.512 60.661 24.312 73.381 ;
     RECT  3.936 43.237 10.584 73.477 ;
     RECT  11.856 67.765 14.232 73.477 ;
     RECT  2.208 66.611 2.712 75.925 ;
     RECT  3.936 73.477 14.232 75.925 ;
     RECT  2.208 75.925 14.232 77.555 ;
     RECT  20.304 39.205 20.328 78.901 ;
     RECT  21.888 73.381 24.312 78.901 ;
     RECT  3.792 77.555 14.232 79.235 ;
     RECT  3.936 79.235 14.232 80.005 ;
     RECT  3.936 80.005 14.328 80.293 ;
     RECT  3.936 80.293 15.144 80.341 ;
     RECT  18.6 2.151 18.912 80.677 ;
     RECT  16.704 80.341 16.728 80.773 ;
     RECT  3.696 80.341 15.144 81.301 ;
     RECT  16.272 80.773 16.728 81.301 ;
     RECT  0.528 19.237 1.128 81.397 ;
     RECT  18.24 80.677 18.912 81.397 ;
     RECT  20.304 78.901 24.312 81.397 ;
     RECT  28.032 81.589 28.056 82.117 ;
     RECT  3.696 81.301 16.728 83.221 ;
     RECT  18.24 81.397 24.312 83.221 ;
     RECT  2.208 77.555 2.712 84.085 ;
     RECT  3.696 83.221 24.312 84.085 ;
     RECT  2.208 84.085 24.312 85.717 ;
     RECT  25.488 84.325 25.512 85.717 ;
     RECT  2.208 85.717 25.512 86.147 ;
     RECT  25.488 86.147 25.512 86.581 ;
     RECT  2.208 86.147 24.312 87.061 ;
     RECT  27.744 82.117 28.056 87.301 ;
     RECT  29.4 2.151 29.712 87.301 ;
     RECT  25.488 86.581 26.184 87.925 ;
     RECT  0.432 81.397 1.128 88.645 ;
     RECT  2.112 87.061 24.312 88.645 ;
     RECT  0.432 88.645 24.312 89.125 ;
     RECT  25.296 87.925 26.184 89.125 ;
     RECT  0.432 89.125 26.184 90.037 ;
     RECT  0.432 90.037 26.376 91.189 ;
     RECT  27.744 87.301 29.712 91.189 ;
     RECT  148.2 2.151 148.512 94.405 ;
     RECT  147.024 93.157 147.048 94.789 ;
     RECT  146.688 94.789 147.048 94.835 ;
     RECT  148.2 94.405 149.304 95.219 ;
     RECT  150.816 92.533 150.84 95.603 ;
     RECT  150.864 95.653 150.888 96.947 ;
     RECT  146.688 94.835 146.712 98.099 ;
     RECT  150.576 97.909 150.6 98.675 ;
     RECT  150.24 100.837 150.264 102.419 ;
     RECT  148.2 95.219 148.824 103.477 ;
     RECT  148.2 103.477 149.064 104.963 ;
     RECT  150.048 104.245 150.072 105.923 ;
     RECT  148.2 104.963 148.512 108.613 ;
     RECT  148.2 108.613 148.824 110.051 ;
     RECT  80.064 92.389 80.088 111.779 ;
     RECT  148.2 110.051 148.512 112.021 ;
     RECT  146.352 110.869 146.376 112.067 ;
     RECT  150.432 109.381 150.456 112.691 ;
     RECT  147.552 112.021 148.512 113.173 ;
     RECT  82.032 112.885 82.056 113.219 ;
     RECT  52.8 95.701 52.824 113.459 ;
     RECT  146.736 113.173 148.512 114.035 ;
     RECT  148.2 114.035 148.512 114.517 ;
     RECT  146.736 114.035 146.76 115.669 ;
     RECT  146.736 115.669 147.144 117.493 ;
     RECT  148.2 114.517 148.824 117.493 ;
     RECT  0.432 91.189 29.712 117.877 ;
     RECT  146.736 117.493 148.824 118.355 ;
     RECT  0.144 117.877 29.712 119.171 ;
     RECT  150.336 118.213 150.36 122.099 ;
     RECT  146.736 118.355 148.512 122.387 ;
     RECT  121.2 2.151 121.512 122.917 ;
     RECT  53.28 113.941 53.304 123.109 ;
     RECT  53.28 123.109 53.448 123.155 ;
     RECT  146.736 122.387 146.76 123.155 ;
     RECT  78 2.151 78.312 123.541 ;
     RECT  149.904 123.829 149.928 124.835 ;
     RECT  146.448 124.789 146.472 125.843 ;
     RECT  148.2 122.387 148.512 126.469 ;
     RECT  150.432 126.805 150.456 128.291 ;
     RECT  31.968 109.957 31.992 132.131 ;
     RECT  148.2 126.469 148.92 132.853 ;
     RECT  148.2 132.853 149.064 132.901 ;
     RECT  147.456 132.901 149.88 133.525 ;
     RECT  147.456 133.525 150.264 133.571 ;
     RECT  53.424 123.155 53.448 135.107 ;
     RECT  0.432 119.171 29.712 135.587 ;
     RECT  0.432 135.587 25.32 135.635 ;
     RECT  147.456 133.571 149.064 136.259 ;
     RECT  0.432 135.635 24.744 136.547 ;
     RECT  150.24 133.571 150.264 136.979 ;
     RECT  26.496 135.587 29.712 137.075 ;
     RECT  23.376 136.547 24.744 137.411 ;
     RECT  23.712 137.411 24.744 137.795 ;
     RECT  0.432 136.547 22.056 137.797 ;
     RECT  23.808 137.795 24.744 137.843 ;
     RECT  0.432 137.797 22.104 137.939 ;
     RECT  27.072 137.075 29.712 138.803 ;
     RECT  23.904 137.843 24.744 138.899 ;
     RECT  23.904 138.899 24.552 139.235 ;
     RECT  24 139.235 24.552 139.667 ;
     RECT  0.432 137.939 22.008 139.715 ;
     RECT  27.984 138.803 29.712 139.763 ;
     RECT  0.432 139.715 21.624 140.003 ;
     RECT  148.2 136.259 149.064 141.349 ;
     RECT  1.632 140.003 21.624 141.443 ;
     RECT  27.984 139.763 28.008 141.587 ;
     RECT  148.2 141.349 149.928 142.499 ;
     RECT  1.632 141.443 17.064 142.547 ;
     RECT  150.912 142.453 150.936 143.939 ;
     RECT  18.192 141.443 21.624 145.187 ;
     RECT  1.632 142.547 17.016 148.021 ;
     RECT  18.432 145.187 21.624 148.021 ;
     RECT  1.632 148.021 21.624 148.739 ;
     RECT  150.48 146.437 150.504 148.835 ;
     RECT  17.808 148.739 21.624 149.171 ;
     RECT  1.632 148.739 16.344 149.459 ;
     RECT  0.432 140.003 0.504 150.323 ;
     RECT  148.2 142.499 149.112 150.373 ;
     RECT  148.2 150.373 149.208 150.421 ;
     RECT  1.632 149.459 15.96 150.803 ;
     RECT  147.312 150.421 149.208 150.997 ;
     RECT  147.312 150.997 149.64 151.957 ;
     RECT  147.312 151.957 149.88 153.683 ;
     RECT  121.104 122.917 121.512 153.923 ;
     RECT  148.2 153.683 149.88 153.923 ;
     RECT  13.2 150.803 15.96 154.501 ;
     RECT  1.632 150.803 11.688 154.741 ;
     RECT  18.6 149.171 21.624 154.885 ;
     RECT  18.48 154.885 21.624 155.651 ;
     RECT  148.2 153.923 149.208 156.707 ;
     RECT  54.96 135.637 54.984 156.803 ;
     RECT  13.2 154.501 16.008 157.477 ;
     RECT  13.2 157.477 16.488 158.531 ;
     RECT  1.632 154.741 11.88 158.965 ;
     RECT  1.632 158.965 12.072 159.925 ;
     RECT  1.632 159.925 12.216 161.315 ;
     RECT  13.2 158.531 15.96 161.363 ;
     RECT  1.632 161.315 12.072 163.475 ;
     RECT  1.632 163.475 12.024 165.155 ;
     RECT  18.6 155.651 21.624 165.875 ;
     RECT  0.48 150.323 0.504 165.923 ;
     RECT  20.256 165.875 21.624 169.427 ;
     RECT  15.408 161.363 15.96 170.291 ;
     RECT  13.2 161.363 14.328 170.771 ;
     RECT  1.632 165.155 11.688 177.491 ;
     RECT  20.784 169.427 21.624 188.531 ;
     RECT  0.144 194.773 0.168 195.587 ;
     RECT  15.936 170.291 15.96 196.115 ;
     RECT  1.68 177.491 11.688 199.907 ;
     RECT  1.68 199.907 11.448 205.235 ;
     RECT  1.68 205.235 5.736 205.571 ;
     RECT  1.68 205.571 5.208 206.869 ;
     RECT  1.68 206.869 5.496 207.973 ;
     RECT  6.72 205.235 11.448 207.973 ;
     RECT  1.68 207.973 11.448 210.131 ;
     RECT  6.72 210.131 11.448 210.371 ;
     RECT  1.68 210.131 5.736 210.947 ;
     RECT  9.168 210.371 11.448 210.947 ;
     RECT  21.6 188.531 21.624 212.099 ;
     RECT  5.472 210.947 5.736 214.021 ;
     RECT  6.72 210.371 8.112 214.021 ;
     RECT  5.472 214.021 8.112 214.067 ;
     RECT  1.68 210.947 4.152 215.701 ;
     RECT  5.472 214.067 5.496 215.701 ;
     RECT  1.68 215.701 5.496 215.747 ;
     RECT  6.576 214.067 8.112 216.371 ;
     RECT  1.68 215.747 5.064 217.669 ;
     RECT  1.68 217.669 5.16 217.763 ;
     RECT  9.168 210.947 9.528 217.763 ;
     RECT  1.68 217.763 3.432 218.821 ;
     RECT  5.04 217.763 5.16 219.397 ;
     RECT  1.68 218.821 4.056 220.643 ;
     RECT  5.04 219.397 5.688 221.173 ;
     RECT  6.72 216.371 8.112 221.173 ;
     RECT  4.032 220.643 4.056 222.229 ;
     RECT  5.04 221.173 8.112 222.229 ;
     RECT  4.032 222.229 8.112 222.275 ;
     RECT  4.128 222.275 8.112 222.515 ;
     RECT  4.368 222.515 8.112 222.803 ;
     RECT  4.368 222.803 5.064 223.619 ;
     RECT  1.68 220.643 3.048 224.005 ;
     RECT  1.68 224.005 4.008 225.733 ;
     RECT  5.04 223.619 5.064 225.733 ;
     RECT  1.68 225.733 5.064 225.779 ;
     RECT  9.36 217.763 9.528 225.779 ;
     RECT  74.832 156.709 74.856 225.779 ;
     RECT  4.512 225.779 5.064 227.363 ;
     RECT  6.72 222.803 8.112 227.365 ;
     RECT  5.04 227.363 5.064 229.093 ;
     RECT  6.192 227.365 8.112 229.187 ;
     RECT  6.192 229.187 6.744 230.339 ;
     RECT  4.512 229.093 5.064 231.397 ;
     RECT  4.32 231.397 5.064 232.499 ;
     RECT  1.68 225.779 3.048 233.267 ;
     RECT  9.504 225.779 9.528 234.899 ;
     RECT  5.04 232.499 5.064 235.381 ;
     RECT  6.72 230.339 6.744 235.381 ;
     RECT  5.04 235.381 6.744 235.669 ;
     RECT  4.896 235.669 6.744 235.715 ;
     RECT  4.896 235.715 4.92 236.485 ;
     RECT  4.512 236.485 4.92 236.579 ;
     RECT  5.952 235.715 6.744 237.107 ;
     RECT  4.512 236.579 4.536 237.683 ;
     RECT  10.848 210.947 11.448 237.683 ;
     RECT  11.424 237.683 11.448 238.307 ;
     RECT  1.68 233.267 2.712 238.547 ;
     RECT  6.72 237.107 6.744 239.459 ;
     RECT  5.616 238.645 5.64 239.747 ;
     RECT  2.4 238.547 2.712 244.089 ;
     RECT  7.8 229.187 8.112 244.089 ;
     RECT  13.2 170.771 13.512 244.089 ;
     RECT  18.6 165.875 18.912 244.089 ;
     RECT  24 139.667 24.312 244.089 ;
     RECT  29.4 139.763 29.712 244.089 ;
     RECT  34.8 2.151 35.112 244.089 ;
     RECT  40.2 2.151 40.512 244.089 ;
     RECT  45.6 2.151 45.912 244.089 ;
     RECT  51 2.151 51.312 244.089 ;
     RECT  56.4 2.151 56.712 244.089 ;
     RECT  61.8 2.151 62.112 244.089 ;
     RECT  67.2 2.151 67.512 244.089 ;
     RECT  72.6 2.151 72.912 244.089 ;
     RECT  77.52 123.541 78.312 244.089 ;
     RECT  83.4 2.151 83.712 244.089 ;
     RECT  88.8 2.151 89.112 244.089 ;
     RECT  94.2 2.151 94.512 244.089 ;
     RECT  99.6 2.151 99.912 244.089 ;
     RECT  105 2.151 105.312 244.089 ;
     RECT  110.4 2.151 110.712 244.089 ;
     RECT  115.8 2.151 116.112 244.089 ;
     RECT  121.2 153.923 121.512 244.089 ;
     RECT  126.6 2.151 126.912 244.089 ;
     RECT  132 2.151 132.312 244.089 ;
     RECT  137.4 2.151 137.712 244.089 ;
     RECT  142.8 2.151 143.112 244.089 ;
     RECT  148.2 156.707 148.512 244.089 ;
     RECT  2.4 244.089 2.52 244.103 ;
     RECT  7.8 244.089 7.92 244.103 ;
     RECT  13.2 244.089 13.32 244.103 ;
     RECT  18.6 244.089 18.72 244.103 ;
     RECT  24 244.089 24.12 244.103 ;
     RECT  29.4 244.089 29.52 244.103 ;
     RECT  34.8 244.089 34.92 244.103 ;
     RECT  40.2 244.089 40.32 244.103 ;
     RECT  45.6 244.089 45.72 244.103 ;
     RECT  51 244.089 51.12 244.103 ;
     RECT  56.4 244.089 56.52 244.103 ;
     RECT  61.8 244.089 61.92 244.103 ;
     RECT  67.2 244.089 67.32 244.103 ;
     RECT  72.6 244.089 72.72 244.103 ;
     RECT  77.52 244.089 78.12 244.103 ;
     RECT  83.4 244.089 83.52 244.103 ;
     RECT  88.8 244.089 88.92 244.103 ;
     RECT  94.2 244.089 94.32 244.103 ;
     RECT  99.6 244.089 99.72 244.103 ;
     RECT  105 244.089 105.12 244.103 ;
     RECT  110.4 244.089 110.52 244.103 ;
     RECT  115.8 244.089 115.92 244.103 ;
     RECT  121.2 244.089 121.32 244.103 ;
     RECT  126.6 244.089 126.72 244.103 ;
     RECT  132 244.089 132.12 244.103 ;
     RECT  137.4 244.089 137.52 244.103 ;
     RECT  142.8 244.089 142.92 244.103 ;
     RECT  148.2 244.089 148.32 244.103 ;
     RECT  77.52 244.103 77.976 246.224 ;
     RECT  6.456 6.805 7.8 10.451 ;
     RECT  4.92 10.741 6.24 11.365 ;
     RECT  4.656 18.851 4.896 19.333 ;
     RECT  1.128 19.237 2.4 47.701 ;
     RECT  3.624 19.333 4.896 20.531 ;
     RECT  11.928 21.061 13.2 57.589 ;
     RECT  2.712 30.709 3.936 31.285 ;
     RECT  3.96 30.851 5.376 33.683 ;
     RECT  2.712 31.285 3.744 38.243 ;
     RECT  4.2 36.419 5.376 38.243 ;
     RECT  2.712 38.243 3.936 39.637 ;
     RECT  3.96 38.243 5.376 40.405 ;
     RECT  18.912 39.205 20.304 81.397 ;
     RECT  2.712 39.637 3.792 41.027 ;
     RECT  3.96 40.405 5.088 41.797 ;
     RECT  2.712 41.027 3.936 66.181 ;
     RECT  10.584 43.237 11.904 46.741 ;
     RECT  10.584 46.741 11.856 73.477 ;
     RECT  1.128 47.701 2.256 48.373 ;
     RECT  1.128 48.373 2.208 87.061 ;
     RECT  2.808 66.181 3.936 66.611 ;
     RECT  2.712 66.611 3.936 75.925 ;
     RECT  2.712 77.555 3.792 79.235 ;
     RECT  2.712 79.235 3.936 80.341 ;
     RECT  2.712 80.341 3.696 84.085 ;
     RECT  16.728 80.677 18.24 83.221 ;
     RECT  15.144 80.773 16.272 81.301 ;
     RECT  28.056 81.589 29.4 87.301 ;
     RECT  24.312 84.325 25.488 85.717 ;
     RECT  24.312 86.147 25.488 87.925 ;
     RECT  1.128 87.061 2.112 88.645 ;
     RECT  24.312 87.925 25.296 89.125 ;
     RECT  26.376 90.037 27.744 91.189 ;
     RECT  147.048 93.157 148.2 94.835 ;
     RECT  149.304 94.405 150.816 95.219 ;
     RECT  146.712 94.835 148.2 98.099 ;
     RECT  51.312 95.701 52.8 113.459 ;
     RECT  148.824 100.837 150.24 102.419 ;
     RECT  148.824 102.419 149.064 103.477 ;
     RECT  149.064 104.245 150.048 104.963 ;
     RECT  146.376 112.021 147.552 112.067 ;
     RECT  146.736 112.067 147.552 113.173 ;
     RECT  82.056 112.885 83.4 113.219 ;
     RECT  146.76 114.035 148.2 115.669 ;
     RECT  147.144 115.669 148.2 117.493 ;
     RECT  148.824 118.213 150.336 118.355 ;
     RECT  146.76 122.387 148.2 123.155 ;
     RECT  148.512 123.829 149.904 124.835 ;
     RECT  148.92 126.805 150.432 128.291 ;
     RECT  149.064 133.571 150.24 136.979 ;
     RECT  25.32 135.587 26.496 135.635 ;
     RECT  54.984 135.637 56.4 156.803 ;
     RECT  22.056 136.547 23.376 137.411 ;
     RECT  22.056 137.411 22.104 137.797 ;
     RECT  28.008 139.763 29.4 141.587 ;
     RECT  0.504 140.003 1.632 165.923 ;
     RECT  17.064 141.443 18.192 142.547 ;
     RECT  149.928 142.453 150.912 142.499 ;
     RECT  17.016 142.547 18.192 145.187 ;
     RECT  17.016 145.187 18.432 148.021 ;
     RECT  149.112 146.437 150.48 148.835 ;
     RECT  16.344 148.739 17.808 149.171 ;
     RECT  11.688 150.803 13.2 154.741 ;
     RECT  11.88 154.741 13.2 158.965 ;
     RECT  12.072 158.965 13.2 159.925 ;
     RECT  12.216 159.925 13.2 161.315 ;
     RECT  12.072 161.315 13.2 163.475 ;
     RECT  14.328 161.363 15.408 170.291 ;
     RECT  12.024 163.475 13.2 165.155 ;
     RECT  11.688 165.155 13.2 199.907 ;
     RECT  18.912 165.875 20.256 169.427 ;
     RECT  0.168 194.773 1.68 195.587 ;
     RECT  5.736 205.235 6.72 205.571 ;
     RECT  5.208 205.571 6.72 206.869 ;
     RECT  5.496 206.869 6.72 207.973 ;
     RECT  5.736 210.131 6.72 214.021 ;
     RECT  8.112 210.371 9.168 217.763 ;
     RECT  4.152 210.947 5.472 215.701 ;
     RECT  9.528 210.947 10.848 234.899 ;
     RECT  5.496 214.067 6.576 215.747 ;
     RECT  5.064 215.747 6.576 216.371 ;
     RECT  5.064 216.371 5.16 217.669 ;
     RECT  3.432 217.763 5.04 218.821 ;
     RECT  8.112 217.763 9.36 225.779 ;
     RECT  4.056 218.821 5.04 222.229 ;
     RECT  5.688 219.397 6.72 221.173 ;
     RECT  3.048 220.643 4.032 222.275 ;
     RECT  3.048 222.275 4.128 222.515 ;
     RECT  3.048 222.515 4.368 223.619 ;
     RECT  3.048 223.619 5.04 224.005 ;
     RECT  4.008 224.005 5.04 225.733 ;
     RECT  3.048 225.779 4.512 227.363 ;
     RECT  8.112 225.779 9.504 234.899 ;
     RECT  5.064 227.365 6.192 230.339 ;
     RECT  3.048 229.093 4.512 231.397 ;
     RECT  6.744 229.187 7.8 239.459 ;
     RECT  3.048 231.397 4.32 232.499 ;
     RECT  4.92 235.715 5.952 236.579 ;
     RECT  4.536 236.579 5.952 237.107 ;
     RECT  5.64 238.645 6.72 239.459 ;
  END
END dsfd_vm_static_fsr_b0
END LIBRARY
